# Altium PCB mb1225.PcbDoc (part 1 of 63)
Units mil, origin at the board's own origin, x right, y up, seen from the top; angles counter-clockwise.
Board outline 5000 x 3464.56 mil, 6 copper layers (TOP, L2_GND, L3_VCC, L4_SIG, L5_GND, BOTTOM), stack 62.2 mil thick; 452 components, 378 nets, 1968 pads, 949 vias.

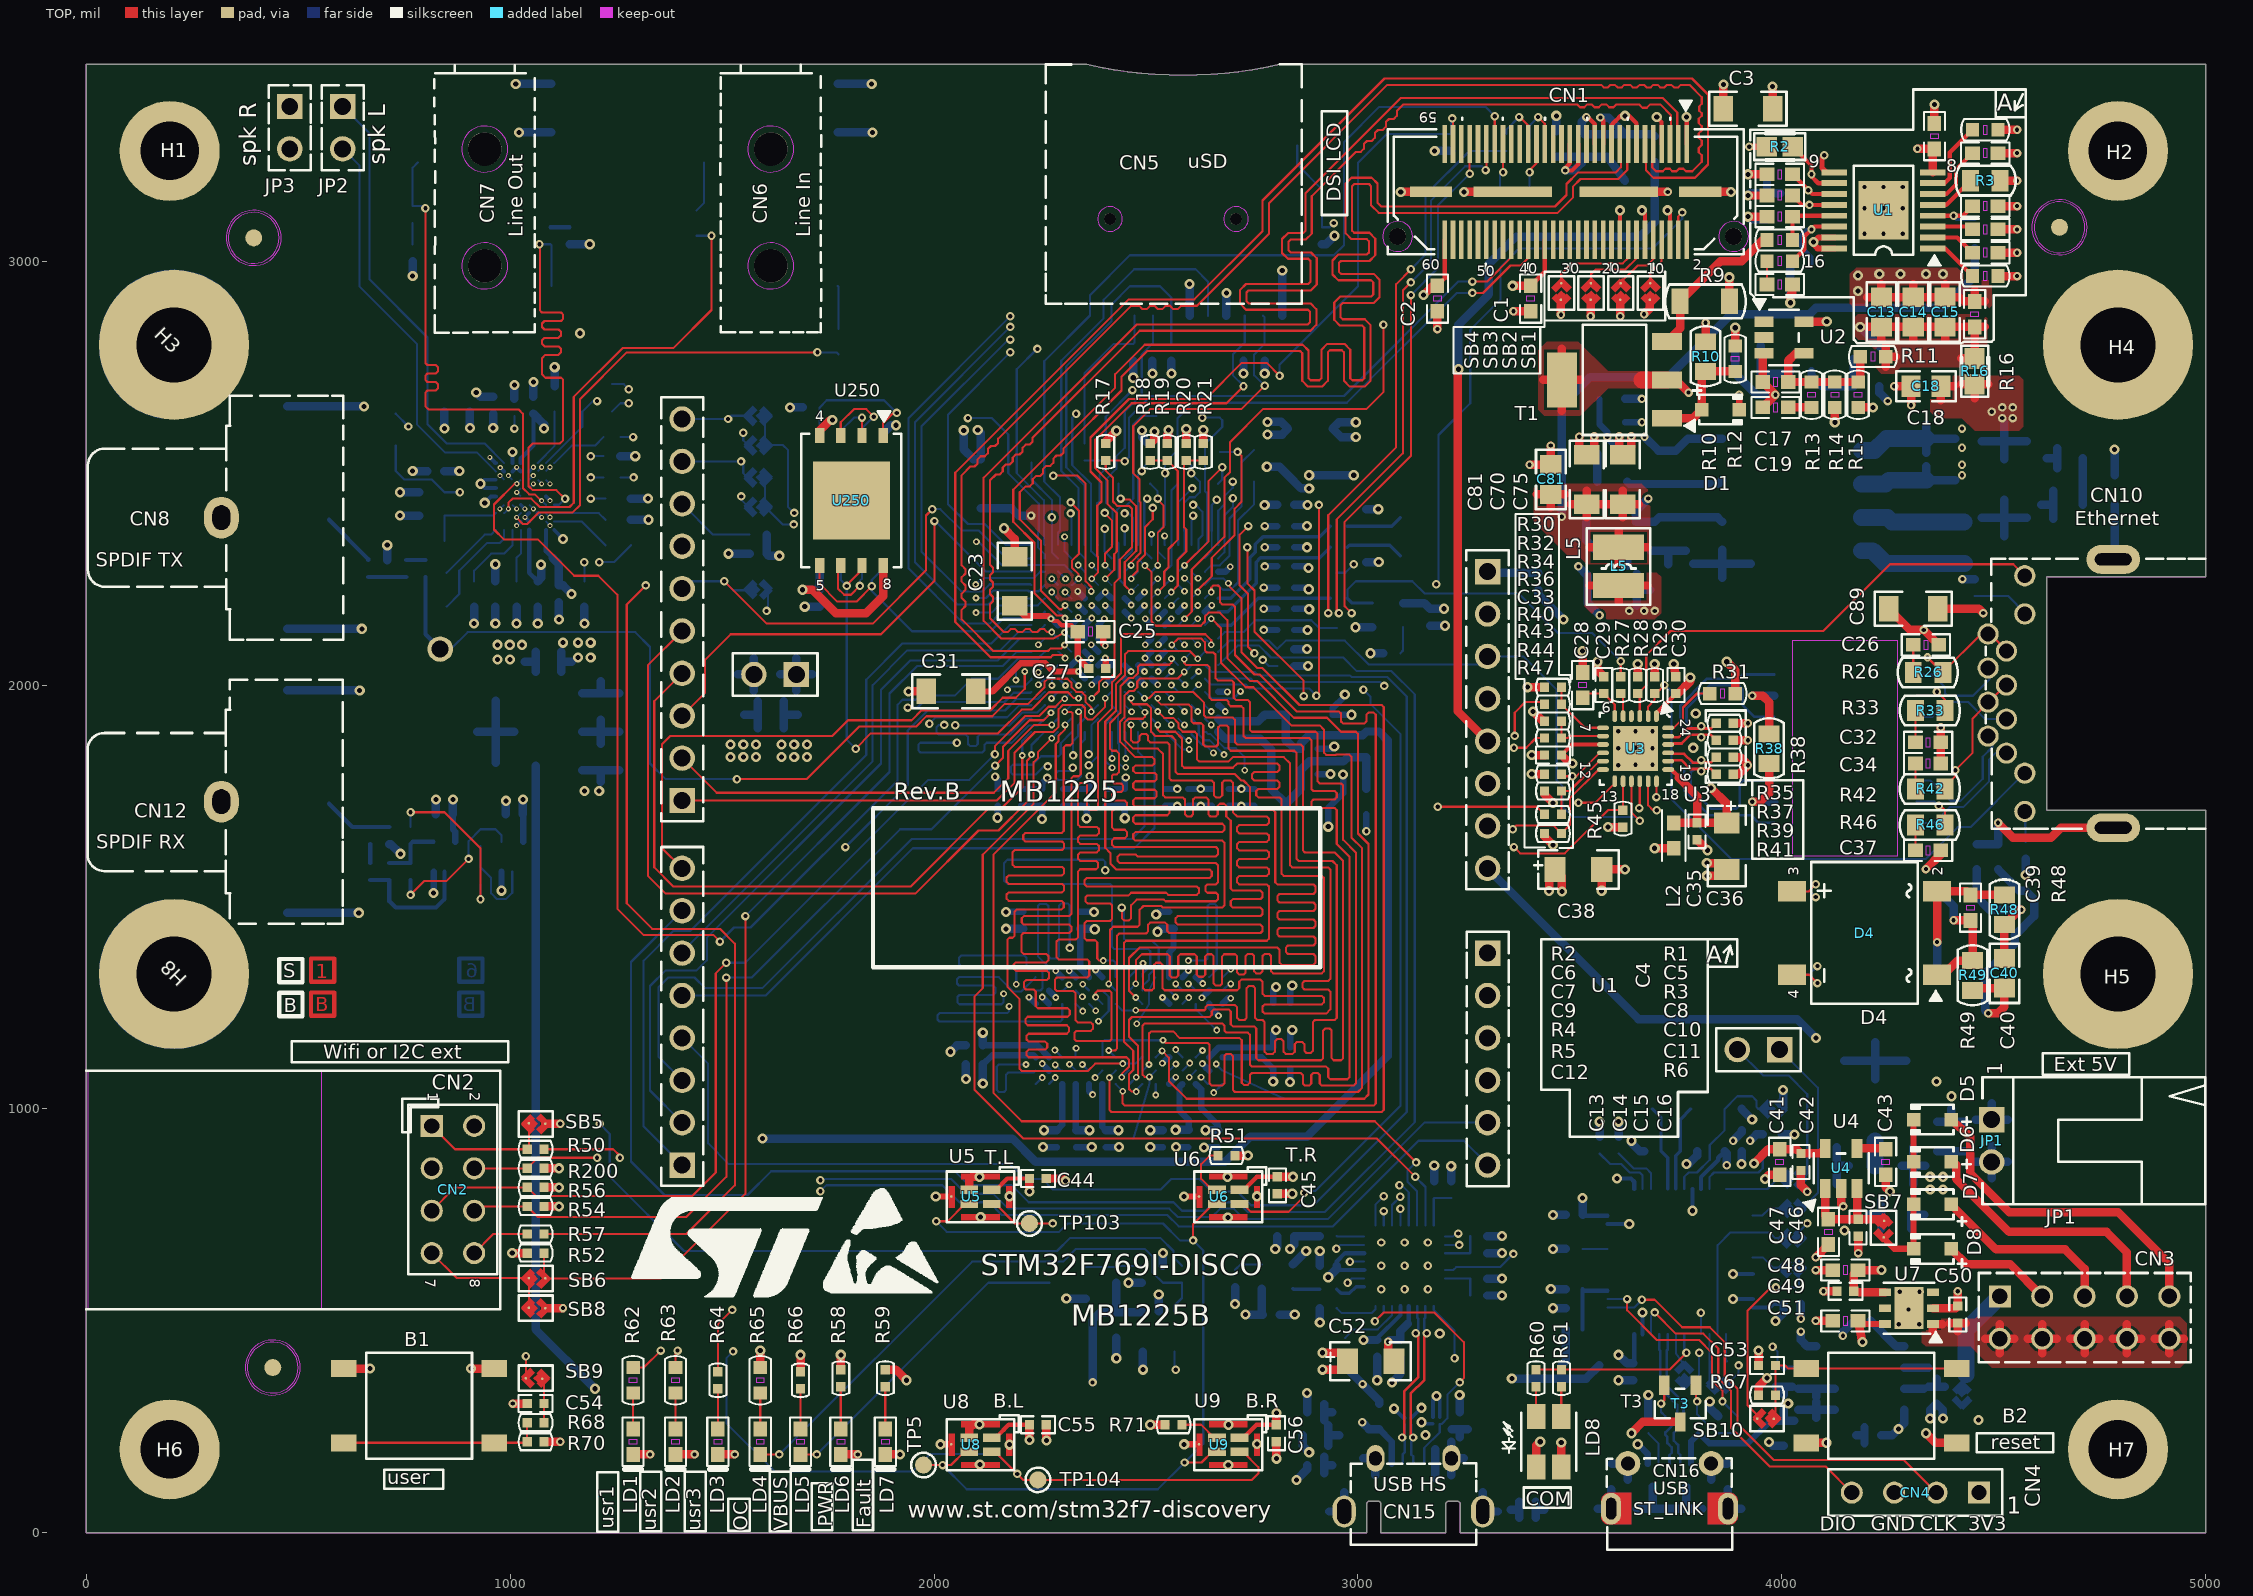
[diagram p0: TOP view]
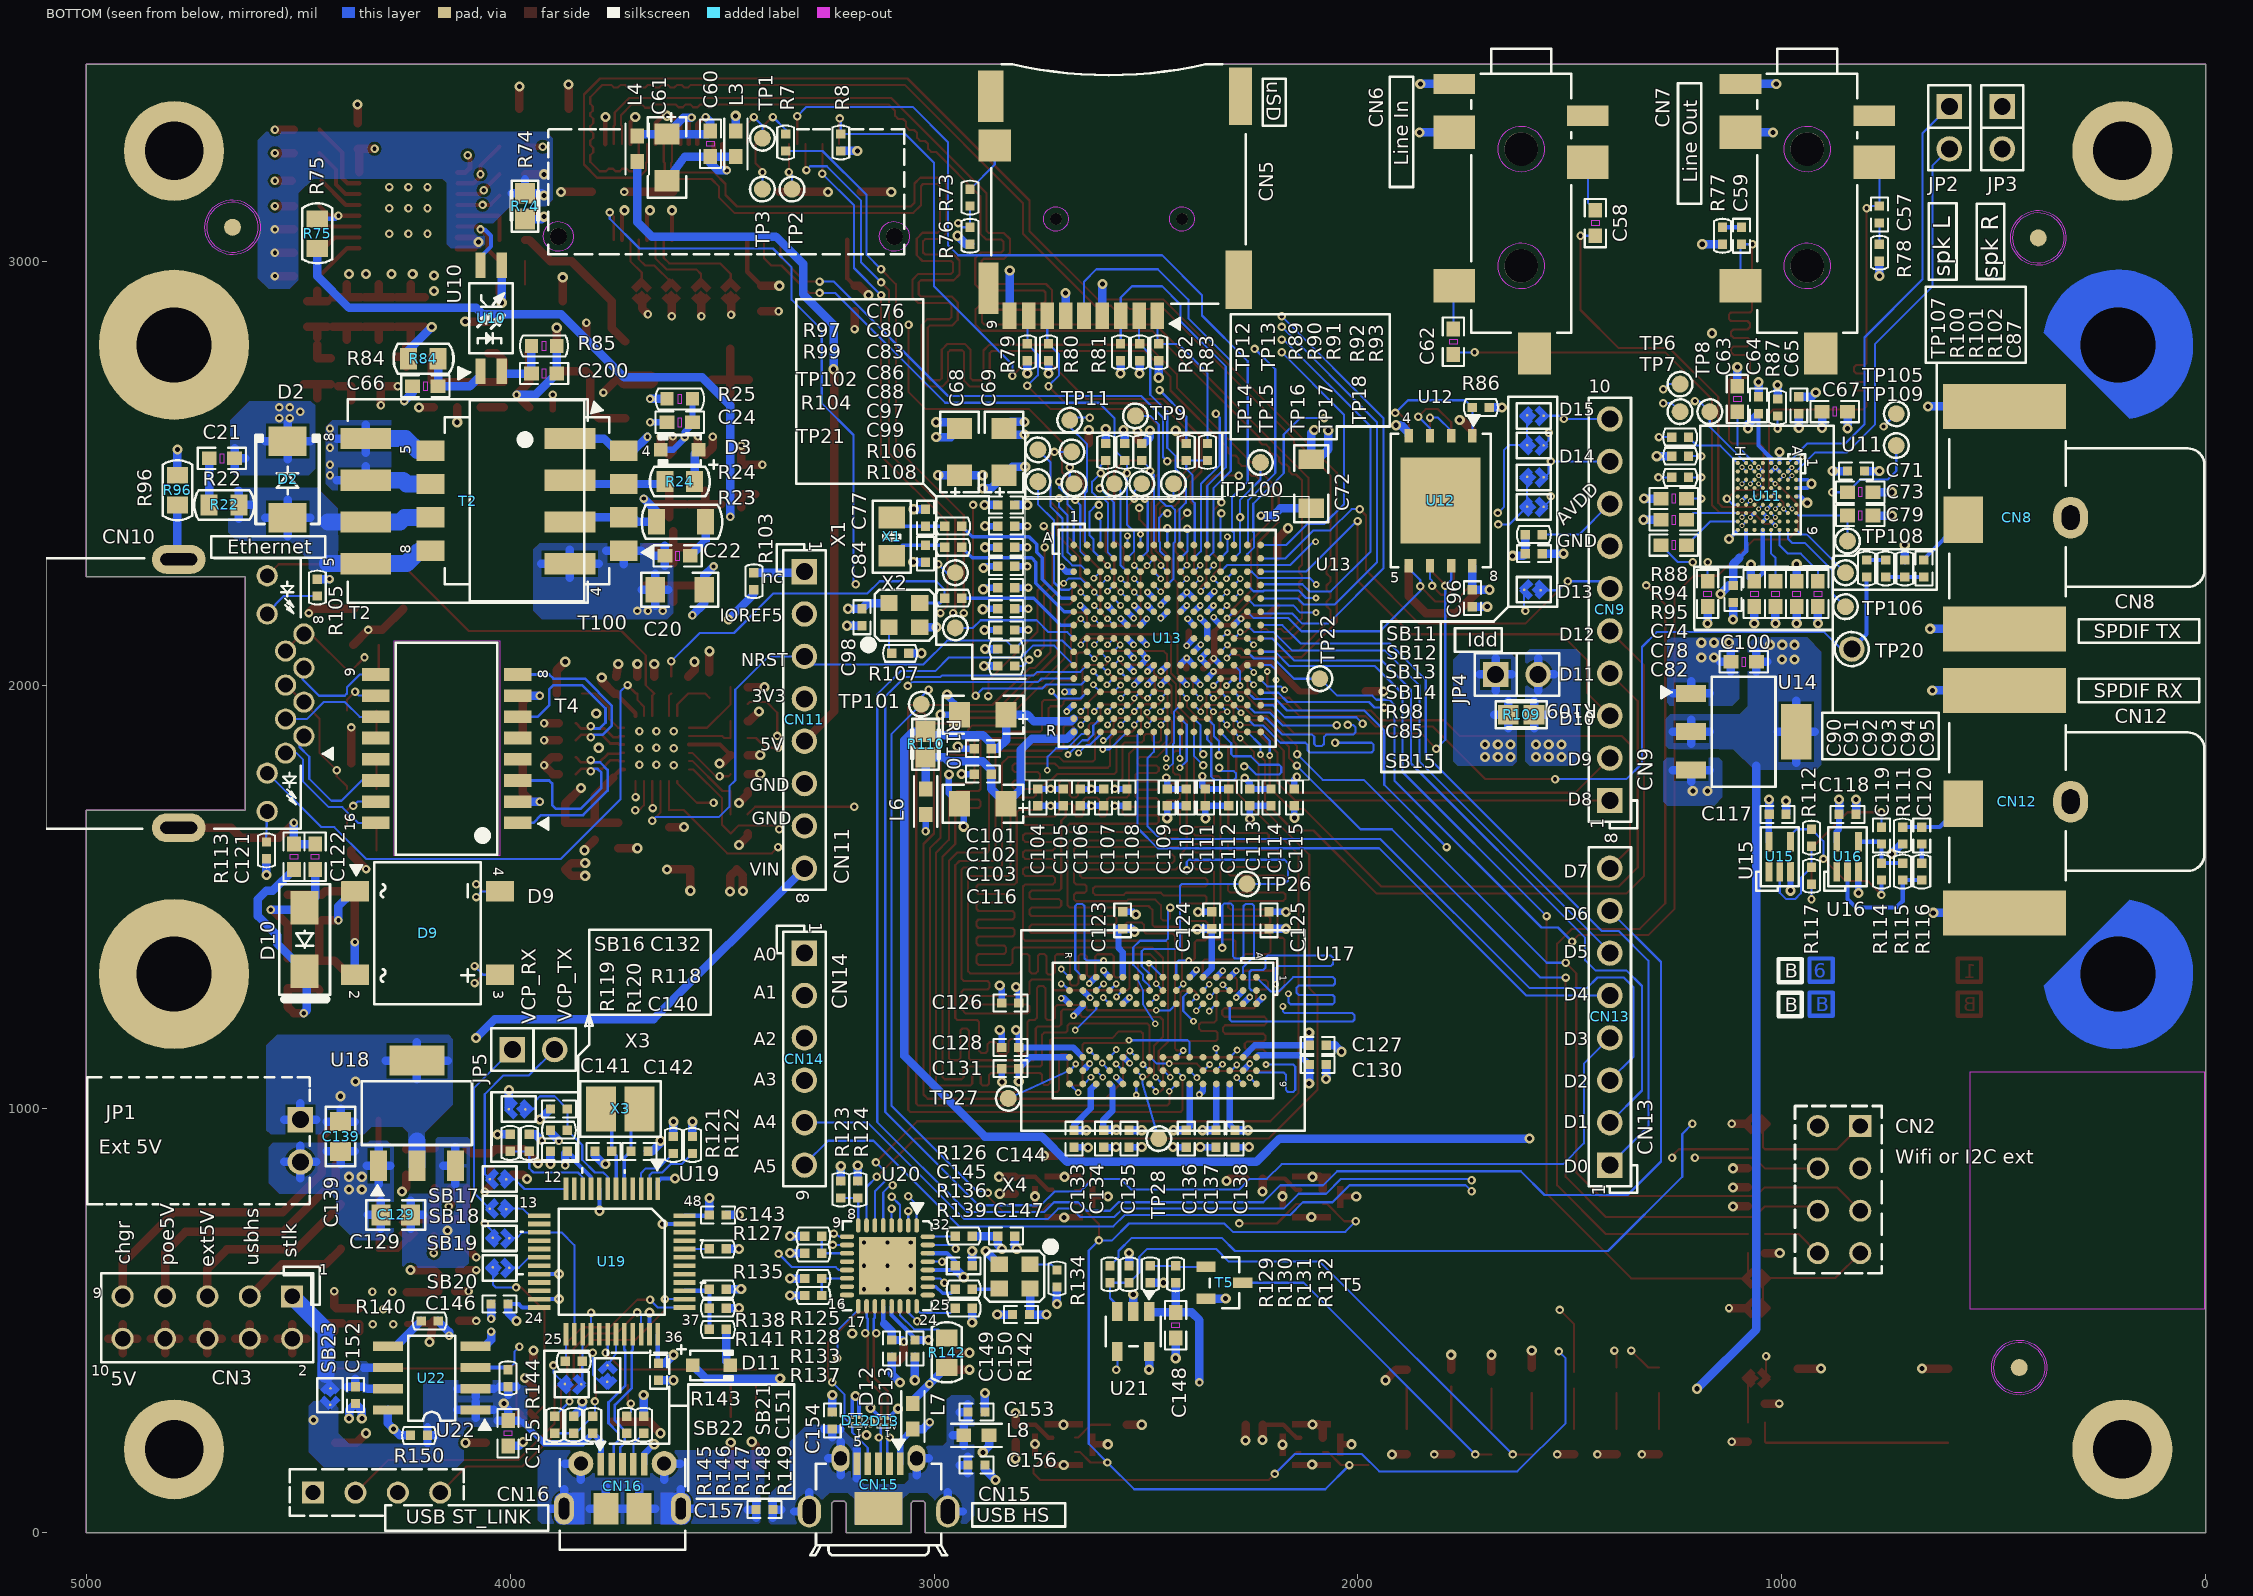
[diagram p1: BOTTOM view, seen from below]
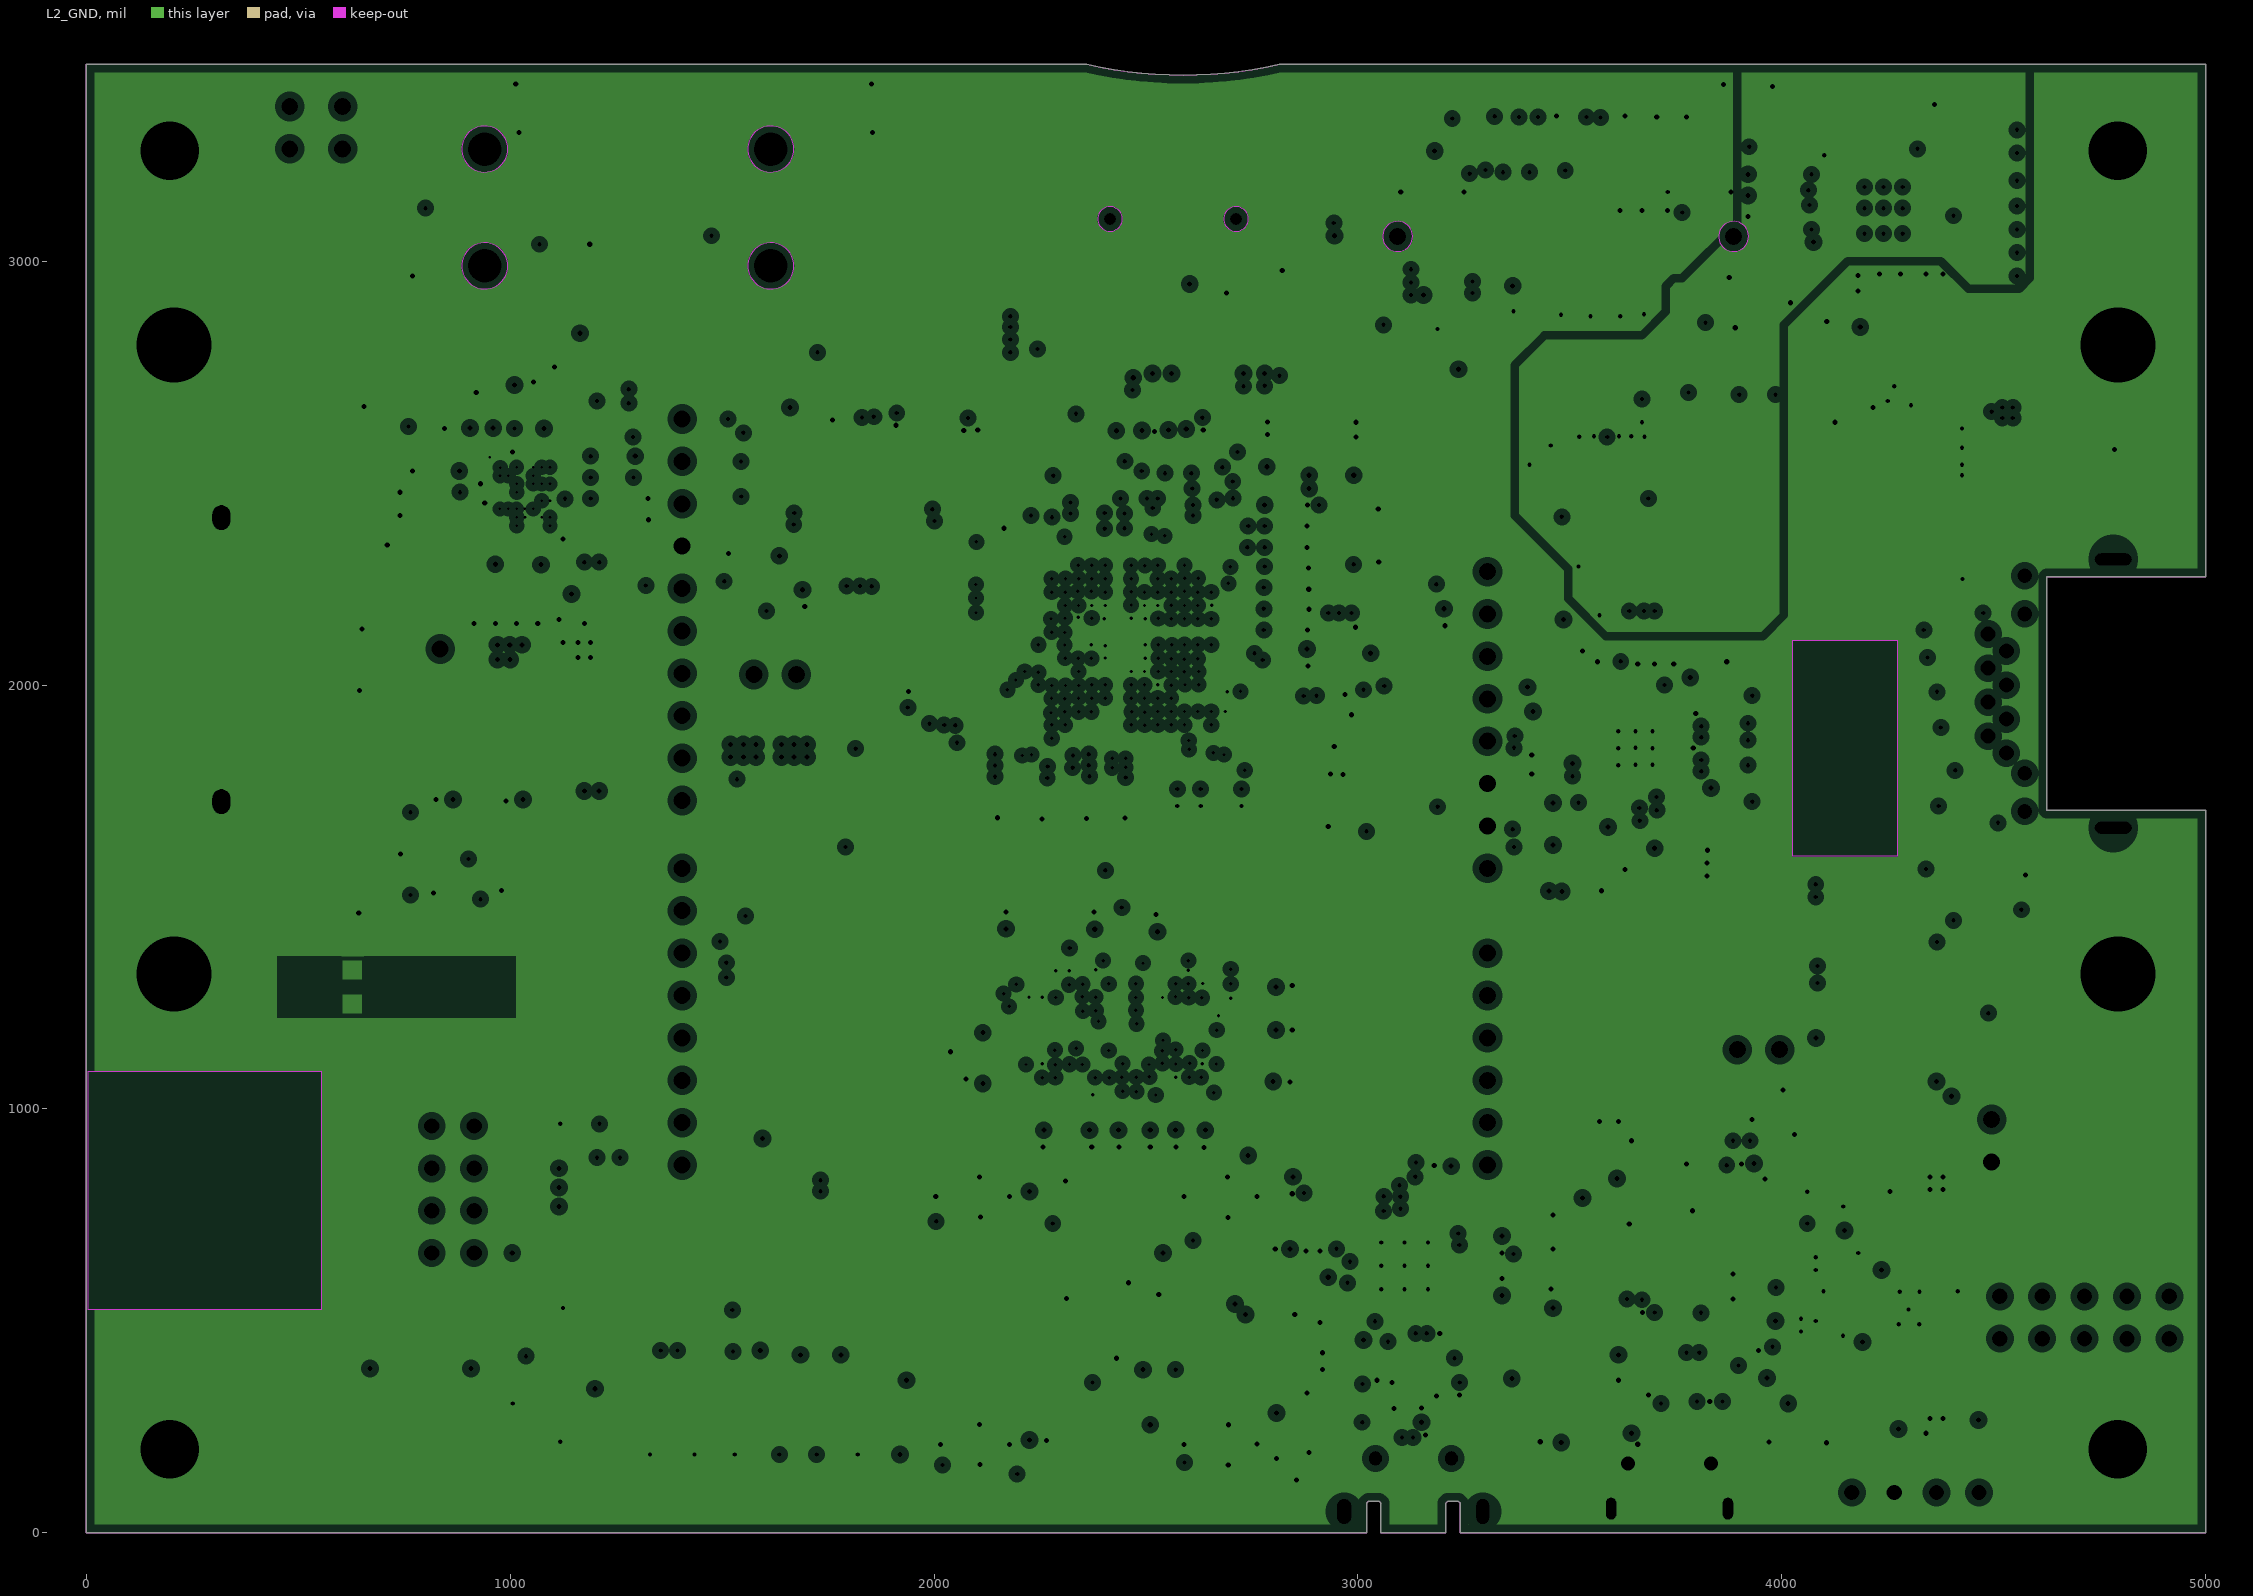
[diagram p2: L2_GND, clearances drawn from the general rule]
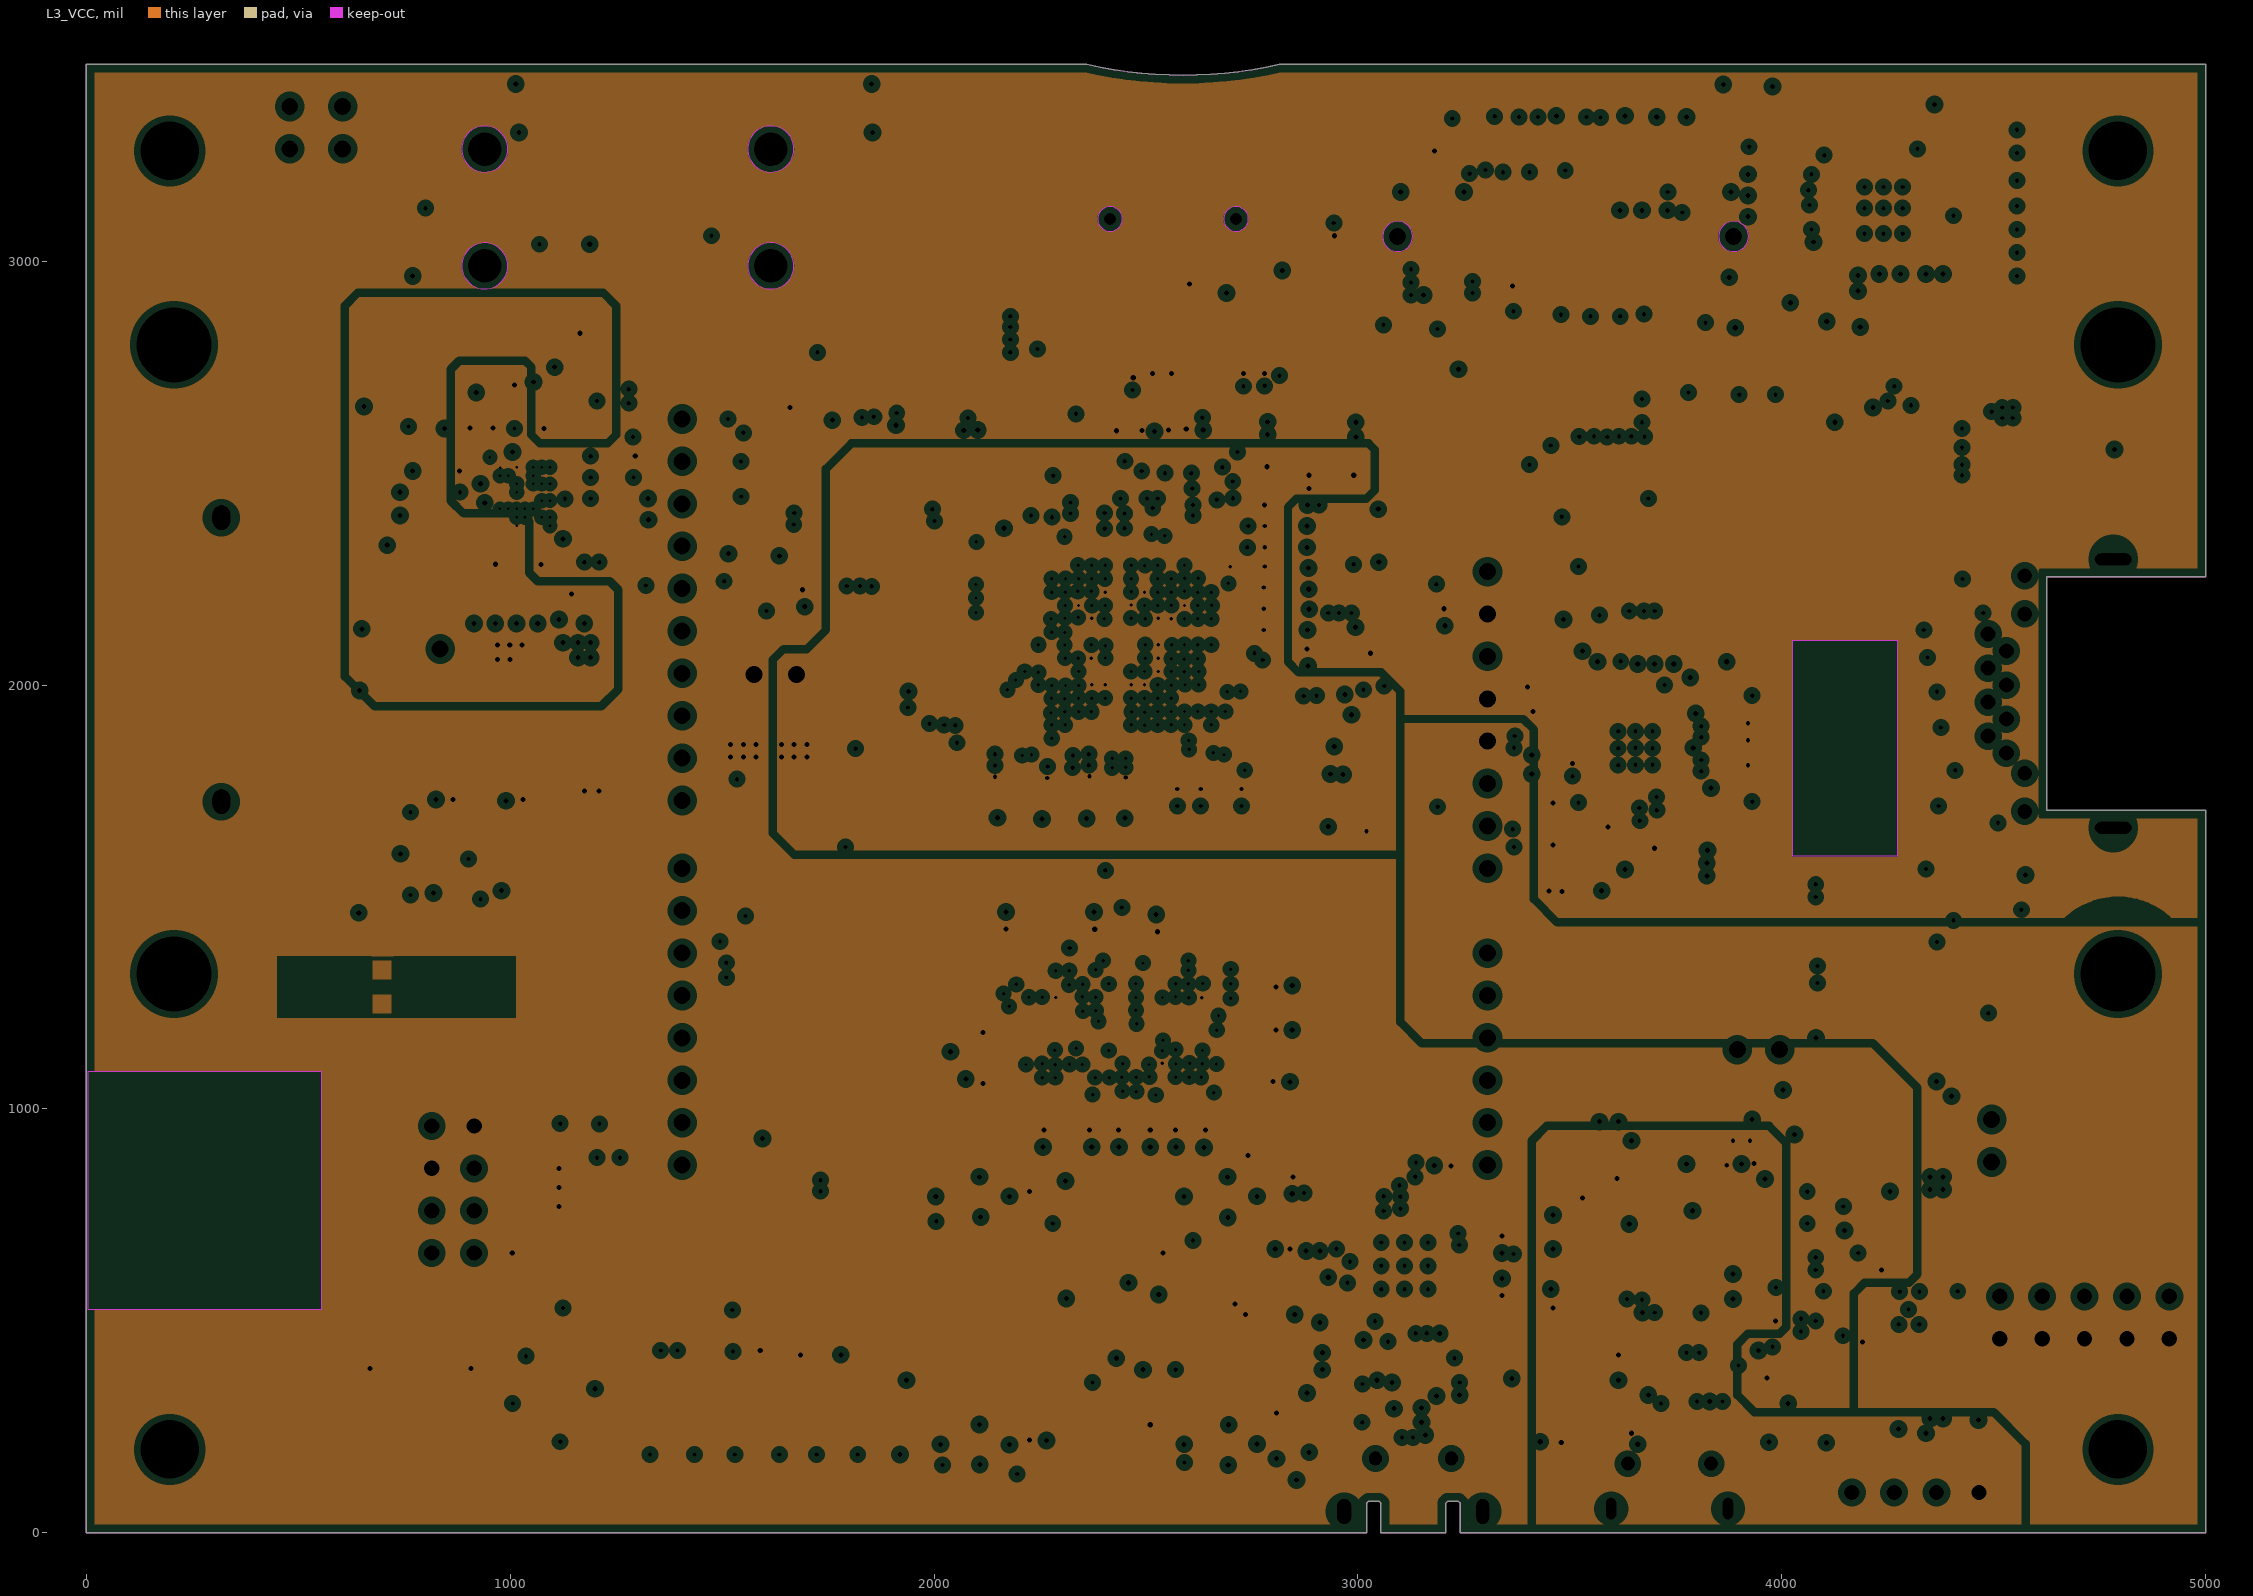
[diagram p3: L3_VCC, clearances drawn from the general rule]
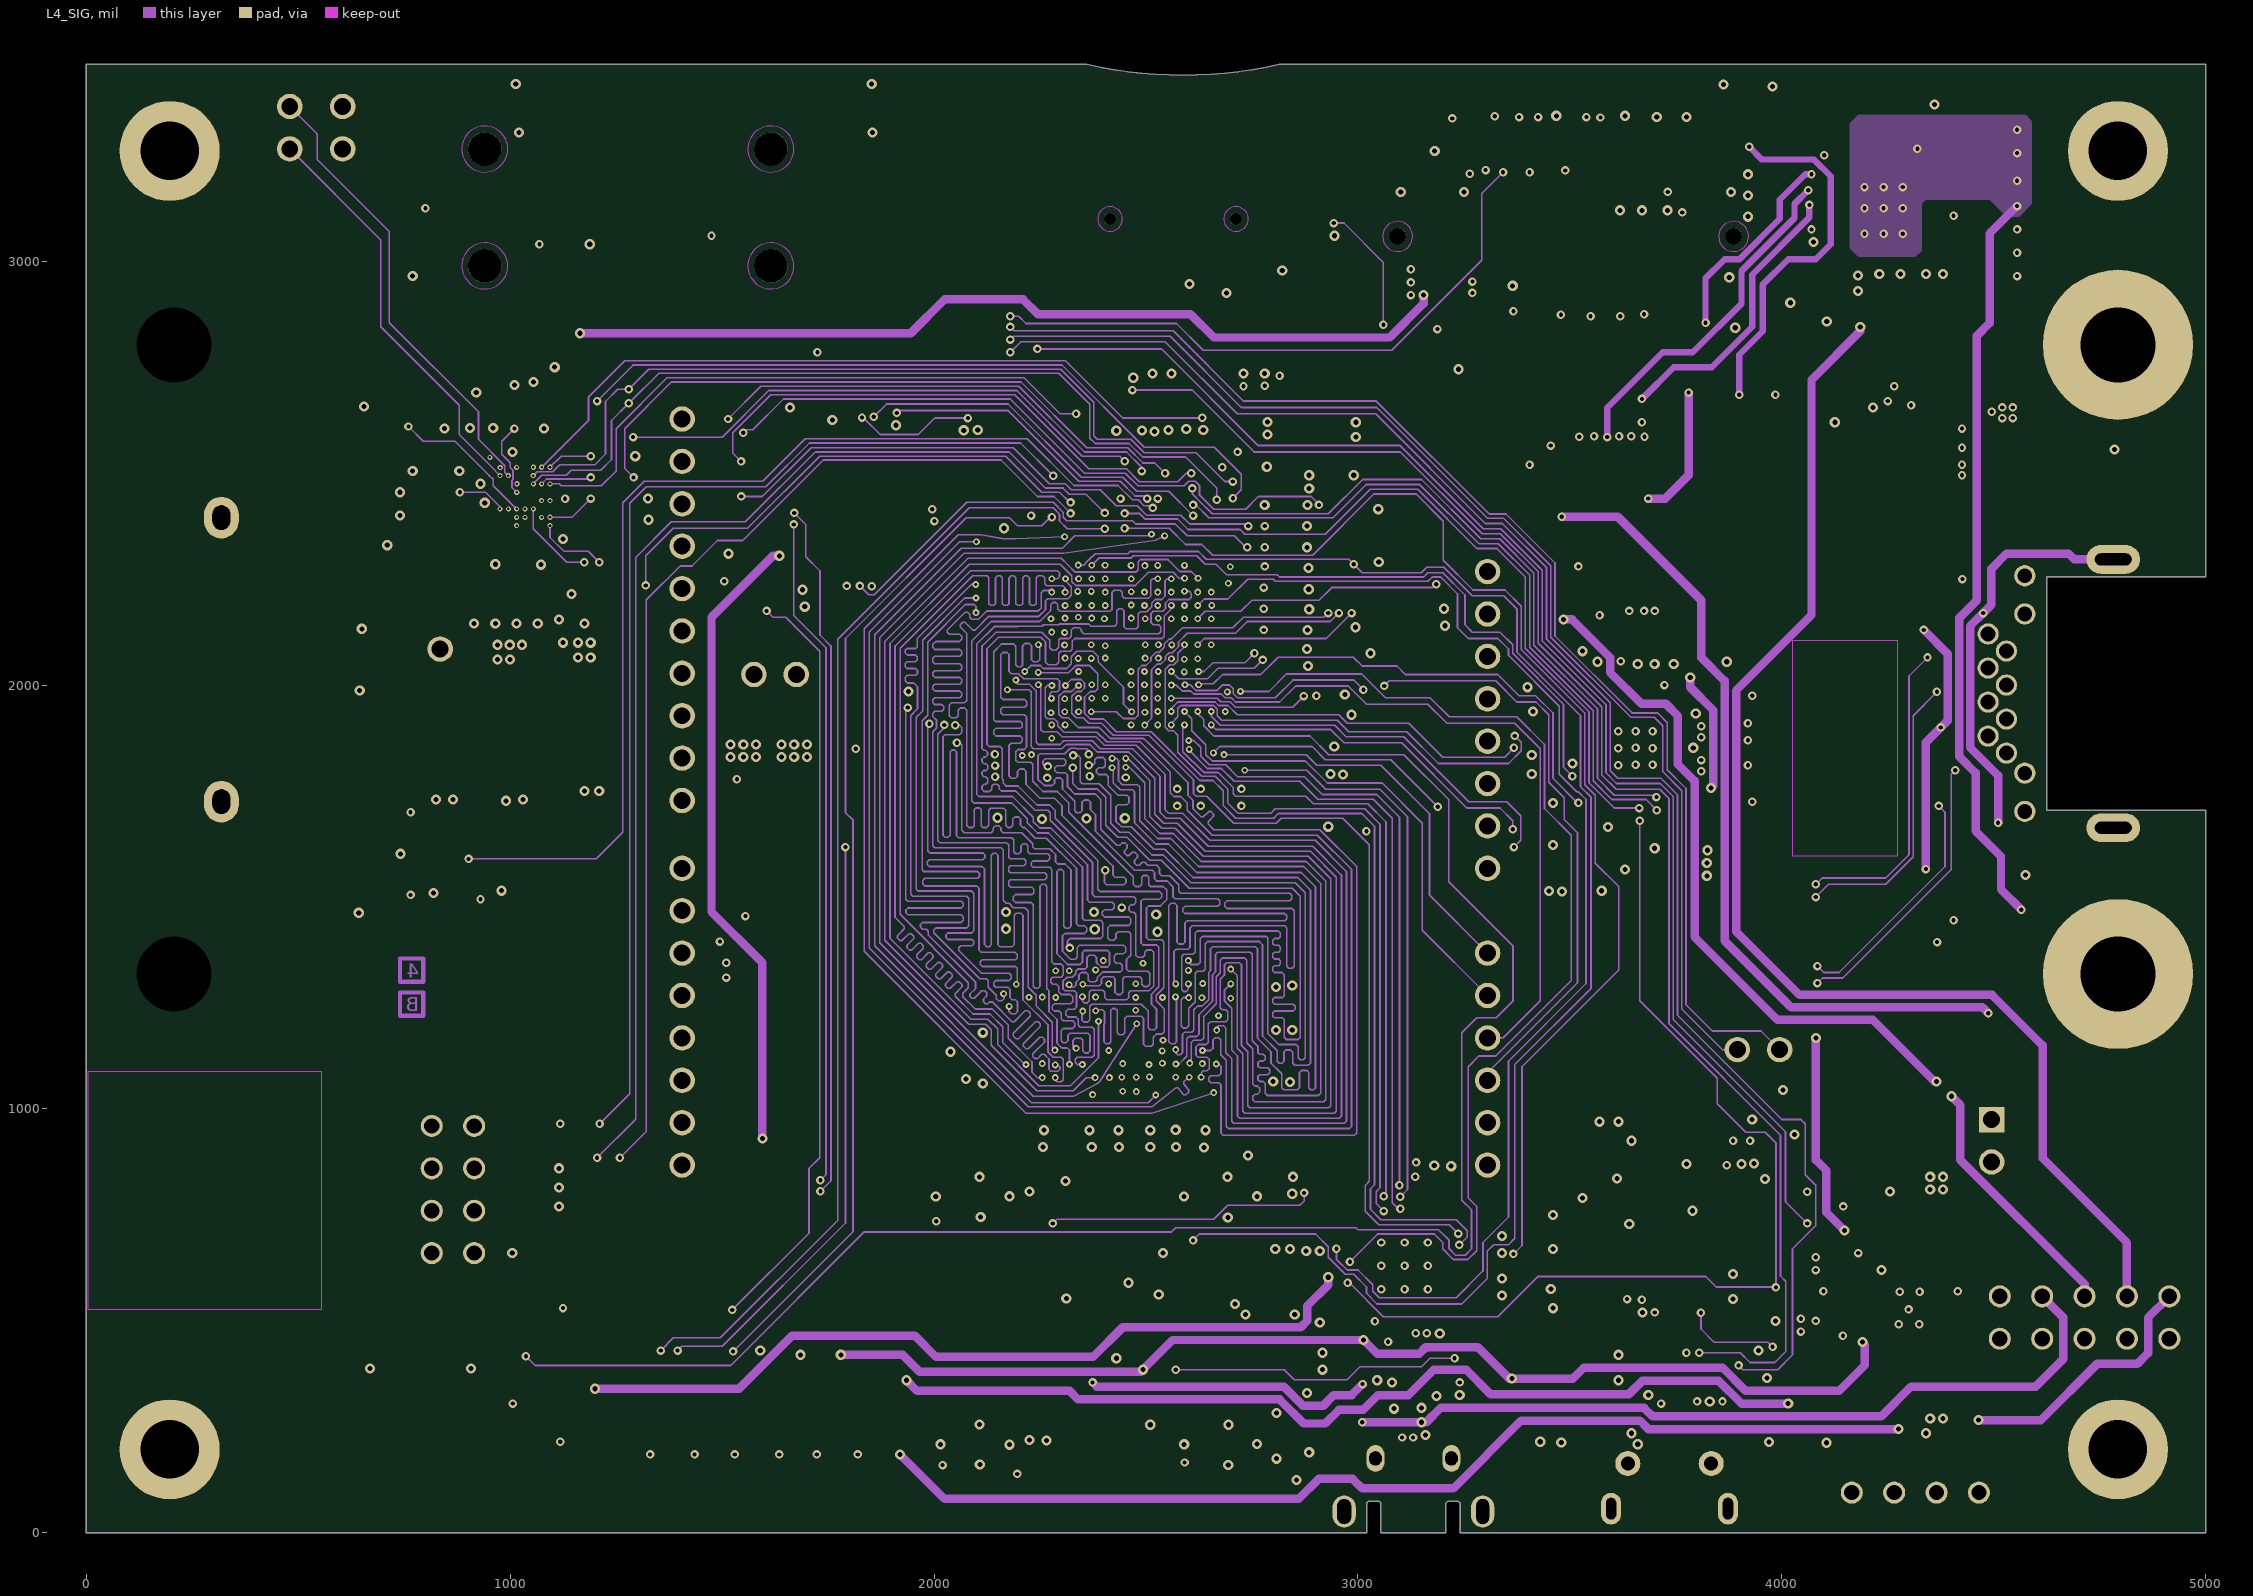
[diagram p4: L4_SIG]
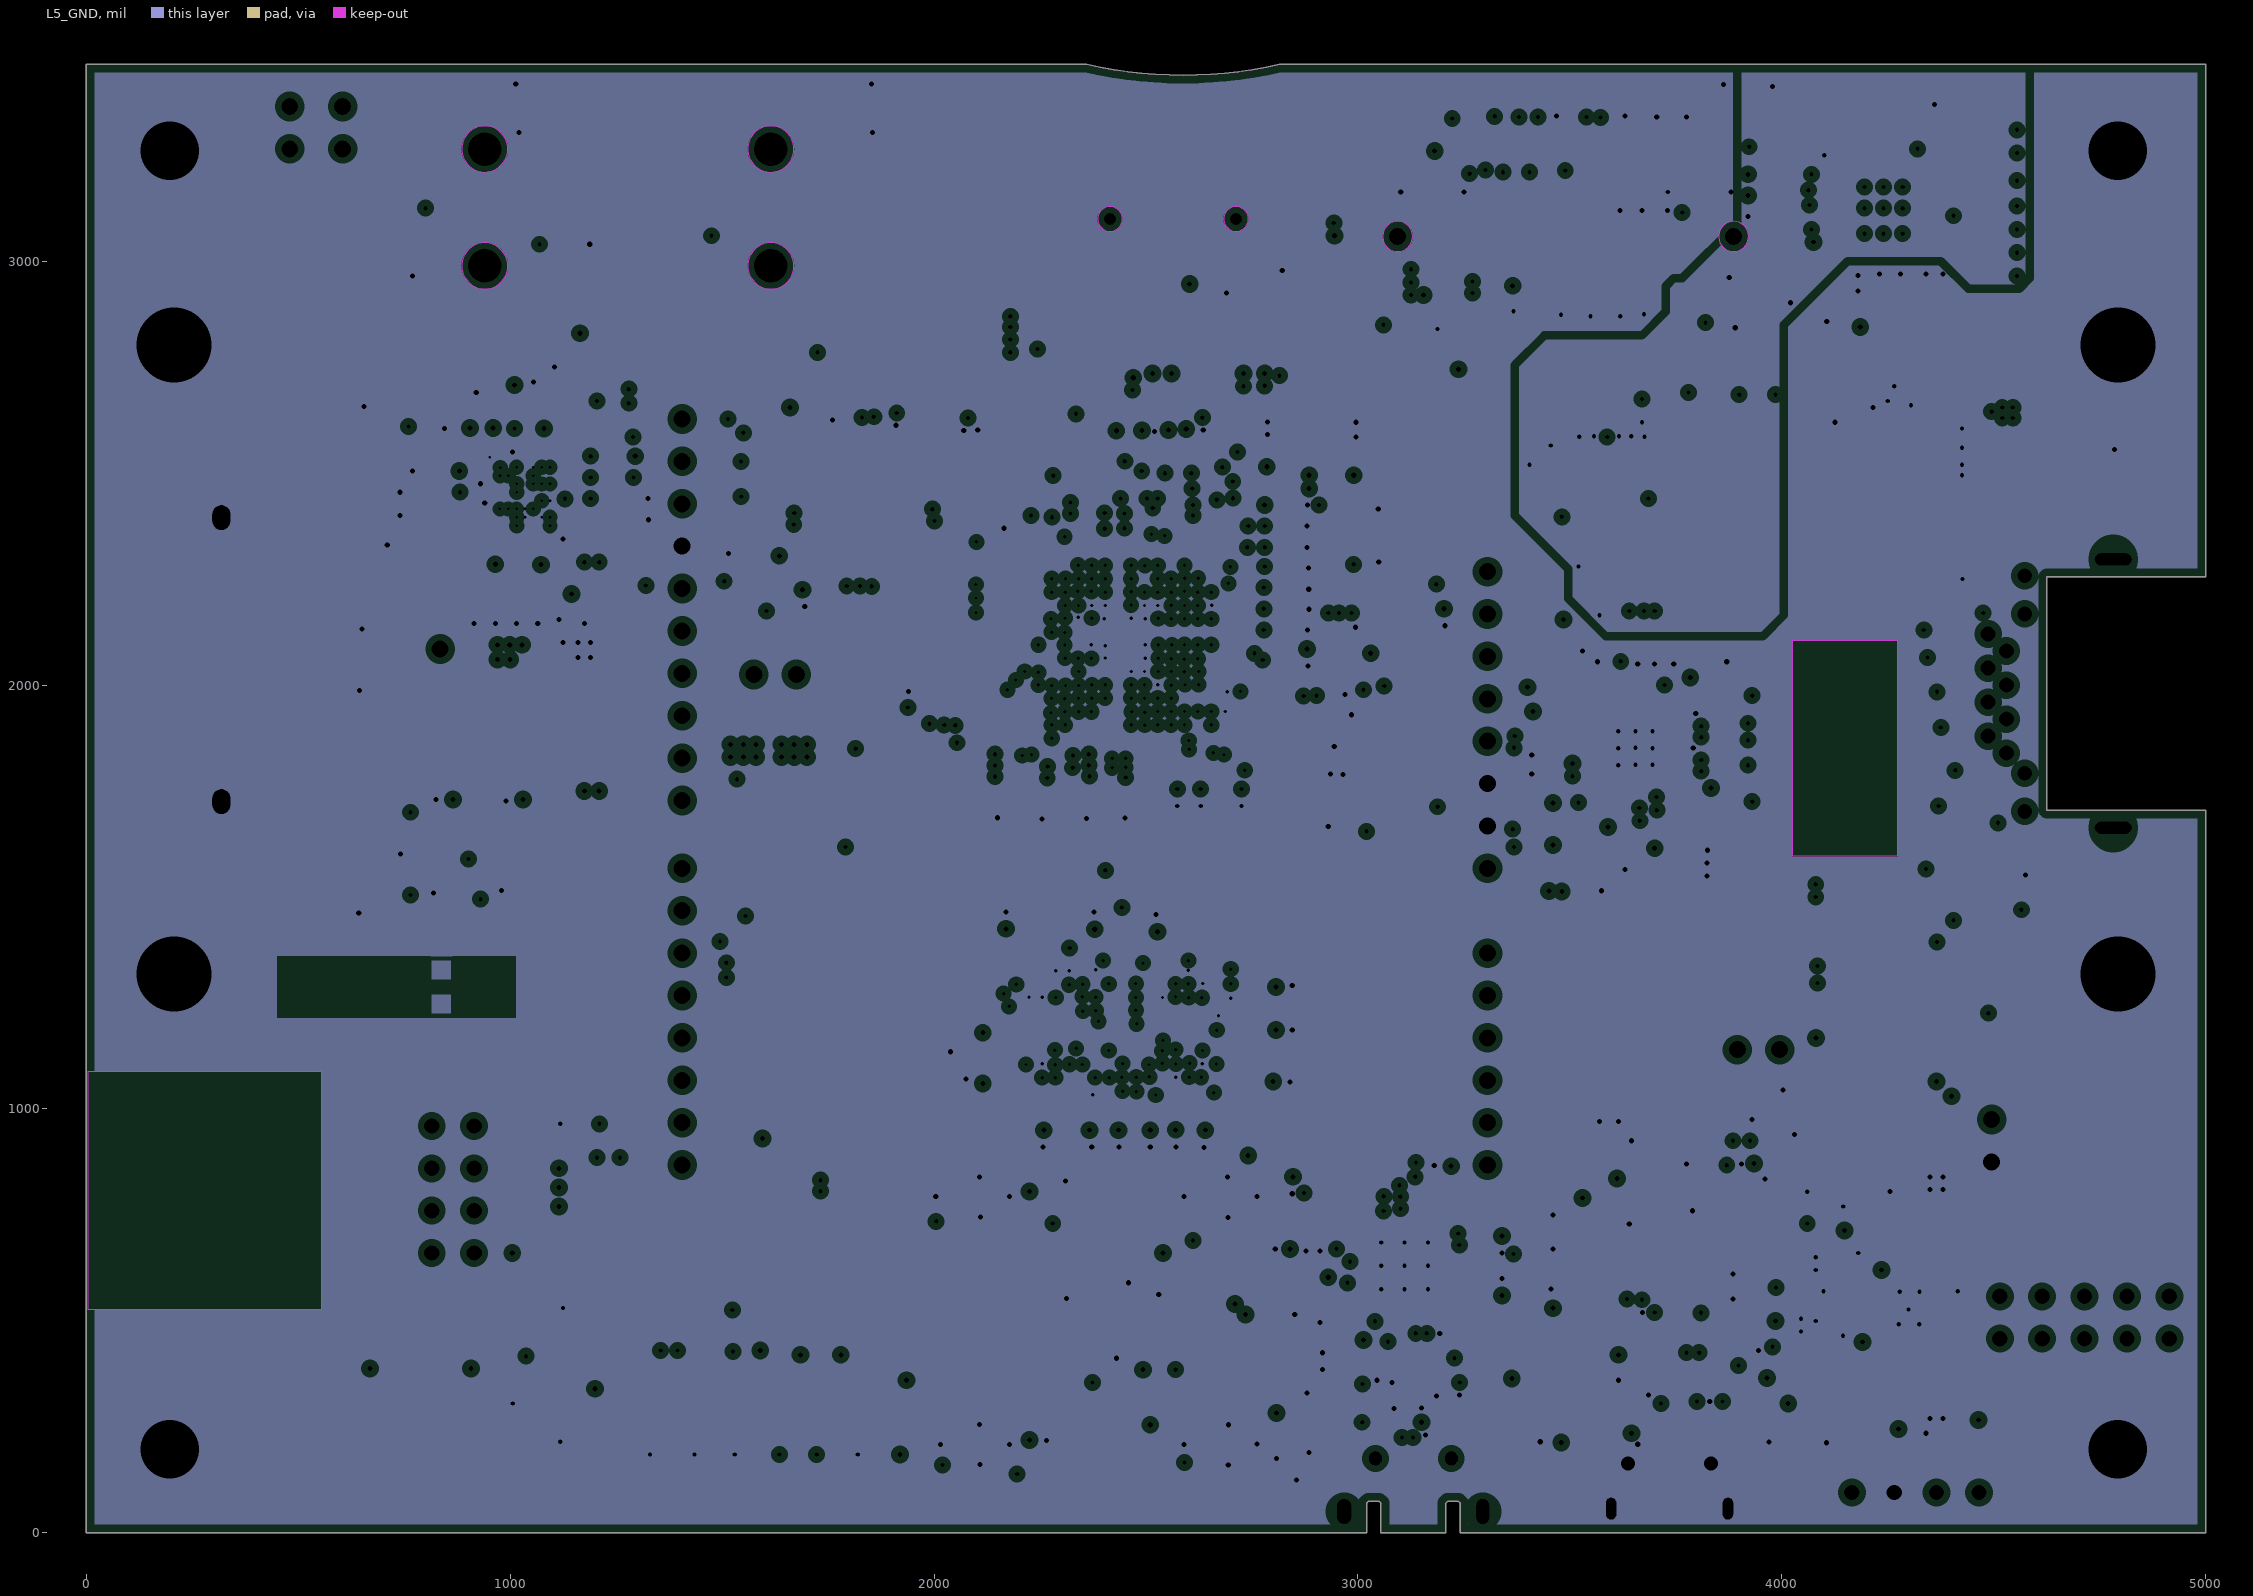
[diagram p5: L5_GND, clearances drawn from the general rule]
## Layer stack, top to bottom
Top Solder: solder mask 0.4, Solder Resist, Dk 3.5
TOP: signal copper 1.8
Dielectric 1: core 3.9, FR-4, Dk 4.3
L2_GND: plane copper 1.2, net POE7
Dielectric2: core 4, FR-4, Dk 4.3
L3_VCC: plane copper 1.2, net 3V3
Dielectric3: core 38, FR-4, Dk 4.3
L4_SIG: signal copper 1.2
Dielectric4: core 4, FR-4, Dk 4.3
L5_GND: plane copper 1.2, net POE7
Dielectric5: core 3.9, FR-4, Dk 4.3
BOTTOM: signal copper 1.8
Bottom Solder: solder mask 0.4, Solder Resist, Dk 3.5

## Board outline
0,0 3020.63,0 3020.63,70.28 3024.57,74.22 3050.16,74.22 3054.1,70.28 3054.1,0 3207.64,0 3207.64,70.28 3211.58,74.22 3237.17,74.22 3241.11,70.28 3241.11,0 5000,0 5000,1705 4625,1705 4625,2255 5000,2255 5000,3464.56 2815,3464.56 cw(c2587.5,4472.06) 2360,3464.56 0,3464.56

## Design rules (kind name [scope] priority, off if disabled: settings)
Clearance Clearance_Keepout [IsKeepOut] p1: gap=0.01 ignorepadtopadclearanceinfootprint=FALSE
Clearance Clearance_Board-cu [IsBoardOutline] p2: gap=5 ignorepadtopadclearanceinfootprint=FALSE except(6: Arc-Fill Arc-Poly Arc-Region Track-Fill Track-Poly Track-Region SMDPad-Fill SMDPad-Poly SMDPad-Region THPad-Fill THPad-Poly THPad-Region Via-Fill Via-Poly Via-Region Fill-Text Fill-Hole Poly-Text Poly-Hole Region-Text Region-Hole; 20: Fill-Fill Fill-Poly Fill-Region Poly-Poly Poly-Region Region-Region)
Clearance Clearance_Board-comp [IsBoardOutline vs IsComponent  and not InComponent('H3','H4','H5','H8','CN5','CN6','CN7','CN10','CN15','CN16')] p3: gap=5 ignorepadtopadclearanceinfootprint=FALSE except(6: Arc-Fill Arc-Poly Arc-Region Track-Fill Track-Poly Track-Region SMDPad-Fill SMDPad-Poly SMDPad-Region THPad-Fill THPad-Poly THPad-Region Via-Fill Via-Poly Via-Region Fill-Text Fill-Hole Poly-Text Poly-Hole Region-Text Region-Hole; 20: Fill-Fill Fill-Poly Fill-Region Poly-Poly Poly-Region Region-Region)
Clearance Clearance_JUMPER [HasFootprint('JP2_SMD') vs HasFootprint('jP2_SMD')] p4: gap=5 ignorepadtopadclearanceinfootprint=FALSE except(3: Fill-Fill Fill-Poly Fill-Region Poly-Poly Poly-Region Region-Region; 6: Arc-Fill Arc-Poly Arc-Region Track-Fill Track-Poly Track-Region SMDPad-Fill SMDPad-Poly SMDPad-Region THPad-Fill THPad-Poly THPad-Region Via-Fill Via-Poly Via-Region Fill-Text Fill-Hole Poly-Text Poly-Hole Region-Text Region-Hole)
Clearance Clearance_3MM [TouchesRoom('RoomDefinition_3MM')] p5: gap=5 ignorepadtopadclearanceinfootprint=FALSE except(3: Arc-Arc Arc-Track Arc-SMDPad Arc-THPad Arc-Via Track-Track Track-SMDPad Track-THPad Track-Via SMDPad-Via THPad-Via; 4: Arc-Hole Track-Hole Via-Hole; 6: Fill-Text Fill-Hole Poly-Text Poly-Hole Region-Text Region-Hole; 15: Fill-Fill Fill-Poly Fill-Region Poly-Poly Poly-Region Region-Region)
Clearance Clearance_BGA [TouchesRoom('RoomDefinition_BGA1') or TouchesRoom('RoomDefinition_BGA2') or TouchesRoom('RoomDefinition_BGA3')] p6: gap=4 ignorepadtopadclearanceinfootprint=FALSE except(5: Arc-Fill Arc-Poly Arc-Region Track-Fill Track-Poly Track-Region SMDPad-SMDPad SMDPad-THPad SMDPad-Fill SMDPad-Poly SMDPad-Region THPad-Fill THPad-Poly THPad-Region Via-Via Via-Fill Via-Poly Via-Region; 15: Fill-Fill Fill-Poly Fill-Region Poly-Poly Poly-Region Region-Region)
Clearance Clearance_2W_L4 [InNetClass('FMC_D[0..31]') or InNetClass('CRL') or InNetClass('FMC_A[0..12]')] p7: gap=5 ignorepadtopadclearanceinfootprint=FALSE except(6: SMDPad-Fill SMDPad-Poly SMDPad-Region THPad-Fill THPad-Poly THPad-Region Via-Fill Via-Poly Via-Region Fill-Text Fill-Hole Poly-Text Poly-Hole Region-Text Region-Hole; 8: Arc-Arc Arc-Track Track-Track; 10: Arc-Fill Arc-Poly Arc-Region Track-Fill Track-Poly Track-Region; 20: Fill-Fill Fill-Poly Fill-Region Poly-Poly Poly-Region Region-Region)
Clearance Clearance_2W [InNetClass('FMC_D[0..31]') or InNetClass('CRL') or InNetClass('FMC_A[0..12]')] p8: gap=5 ignorepadtopadclearanceinfootprint=FALSE except(6: SMDPad-Fill SMDPad-Poly SMDPad-Region THPad-Fill THPad-Poly THPad-Region Via-Fill Via-Poly Via-Region Fill-Text Fill-Hole Poly-Text Poly-Hole Region-Text Region-Hole; 10: Arc-Arc Arc-Track Arc-Fill Arc-Poly Arc-Region Track-Track Track-Fill Track-Poly Track-Region; 20: Fill-Fill Fill-Poly Fill-Region Poly-Poly Poly-Region Region-Region)
Clearance Clearance_3W [InNet('PG8')] p9: gap=5 ignorepadtopadclearanceinfootprint=FALSE except(6: SMDPad-Fill SMDPad-Poly SMDPad-Region THPad-Fill THPad-Poly THPad-Region Via-Fill Via-Poly Via-Region Fill-Text Fill-Hole Poly-Text Poly-Hole Region-Text Region-Hole; 15: Arc-Arc Arc-Track Arc-Fill Arc-Poly Arc-Region Track-Track Track-Fill Track-Poly Track-Region; 20: Fill-Fill Fill-Poly Fill-Region Poly-Poly Poly-Region Region-Region)
Clearance [All] p10: gap=5 ignorepadtopadclearanceinfootprint=FALSE except(6: Arc-Fill Arc-Poly Arc-Region Track-Fill Track-Poly Track-Region SMDPad-Fill SMDPad-Poly SMDPad-Region THPad-Fill THPad-Poly THPad-Region Via-Fill Via-Poly Via-Region Fill-Text Fill-Hole Poly-Text Poly-Hole Region-Text Region-Hole; 20: Fill-Fill Fill-Poly Fill-Region Poly-Poly Poly-Region Region-Region)
ComponentClearance [All] p1: gap=1 collisioncheckmode=3 verticalgap=1 showdistances=FALSE
DiffPairsRouting DiffPairsRouting_100OHM [InDifferentialPairClass('100OHM')] p1: maxlimit=10.9 minlimit=9.9 mostfreqgap=10.9 toplayer_maxgap=9.9 toplayer_prefgap=9.9 toplayer_minwidth=5.1 toplayer_maxwidth=5.1 toplayer_prefwidth=5.1 midlayer1_mingap=10.9 midlayer1_minwidth=4.1 midlayer1_maxwidth=4.1 midlayer1_prefwidth=4.1 bottomlayer_maxgap=9.9 bottomlayer_prefgap=9.9 bottomlayer_minwidth=5.1 bottomlayer_maxwidth=5.1 bottomlayer_prefwidth=5.1 maxuncoupledlength=500
DiffPairsRouting DiffPairsRouting_90OHM [InDifferentialPairClass('90OHM')] p2: maxlimit=9.9 minlimit=8.9 mostfreqgap=9.9 toplayer_maxgap=8.9 toplayer_prefgap=8.9 toplayer_minwidth=6.1 toplayer_maxwidth=6.1 toplayer_prefwidth=6.1 midlayer1_mingap=9.9 midlayer1_minwidth=5.1 midlayer1_maxwidth=5.1 midlayer1_prefwidth=5.1 bottomlayer_maxgap=8.9 bottomlayer_prefgap=8.9 bottomlayer_minwidth=6.1 bottomlayer_maxwidth=6.1 bottomlayer_prefwidth=6.1 maxuncoupledlength=500
HoleSize [All] p1: absolutevalues=TRUE maxlimit=300 minlimit=1 maxpercent=80.000 minpercent=20.000
MatchedLengths MatchedLengths_DSI_DSI_CLK_N [InDifferentialPair('DSI.DSI_D0') or InDifferentialPair('DSI.DSI_D1') or InDifferentialPair('DSI.DSI_CK') or InDifferentialPair('RD') or InDifferentialPair('TD') or InDifferentialPair('USB_HS')] p1: tolerance=5 checknetsindiffpair=TRUE checkdiffpairvsdiffpair=FALSE checkxsignals=FALSE checkothers=FALSE
MatchedLengths "Schematic Matched Net Lengths_11" [InNetClass('ULPI_D[0..7]')] p2 off: tolerance=100 checknetsindiffpair=FALSE checkdiffpairvsdiffpair=TRUE checkxsignals=TRUE checkothers=TRUE
MatchedLengths "Schematic Matched Net Lengths_8" [InNetClass('FMC_A[0..12]')] p3 off: tolerance=100 checknetsindiffpair=FALSE checkdiffpairvsdiffpair=TRUE checkxsignals=TRUE checkothers=TRUE
MatchedLengths "Schematic Matched Net Lengths_7" [InNetClass('FMC_D[0..31]')] p4 off: tolerance=100 checknetsindiffpair=FALSE checkdiffpairvsdiffpair=TRUE checkxsignals=TRUE checkothers=TRUE
MatchedLengths "Schematic Matched Net Lengths_6" [InNetClass('PF[0..15]')] p5 off: tolerance=100 checknetsindiffpair=FALSE checkdiffpairvsdiffpair=TRUE checkxsignals=TRUE checkothers=TRUE
PlaneClearance PlaneClearance_Fix-138 [InComponent('H1','H2','H6','H7')] p1: clearance=9
PlaneClearance PlaneClearance_Fix-177 [InComponent('H3','H4','H5','H8')] p2: clearance=17.5
PlaneClearance PlaneClearance_18mil [IsVia And (PadViaLibraryTemplate = 'via12d6a18')] p3: clearance=6
PlaneClearance PlaneClearance_26mil [IsVia And (PadViaLibraryTemplate = 'via16d8a26')] p4: clearance=9
PlaneClearance PlaneClearance_30mil [IsVia And (PadViaLibraryTemplate = 'via20d10a30')] p5: clearance=10
PlaneClearance PlaneClearance_32mil [IsVia And (PadViaLibraryTemplate = 'via24d12a32')] p6: clearance=10
PlaneClearance [All] p7: clearance=15
PlaneConnect PlaneConnect_CN8-12 [InComponent('CN8','CN12')] p1: planeconnectstyle=Relief reliefexpansion=8 reliefentries=4 reliefconductorwidth=15 reliefairgap=7
PlaneConnect PlaneConnect_Fix-138 [InComponent('H1','H2','H6','H7')] p2: planeconnectstyle=Relief reliefexpansion=2 reliefentries=4 reliefconductorwidth=30 reliefairgap=7
PlaneConnect PlaneConnect_Fix-177 [InComponent('H3','H4','H5','H8')] p3: planeconnectstyle=Relief reliefexpansion=8 reliefentries=4 reliefconductorwidth=40 reliefairgap=7
PlaneConnect [All] p4: pad.planeconnectstyle=Relief pad.reliefexpansion=8 pad.reliefentries=4 pad.reliefconductorwidth=15 pad.reliefairgap=7 via.planeconnectstyle=Direct via.reliefexpansion=20 via.reliefentries=4 via.reliefconductorwidth=10 via.reliefairgap=10
PolygonConnect PolygonConnect_CN15 [IsPad And (Name = 'CN15-10')] p1: connectstyle=Direct reliefconductorwidth=10 reliefentries=4 polygonreliefangle="90 Angle" airgapwidth=10
PolygonConnect [All] p2: thpad.connectstyle=Relief thpad.reliefconductorwidth=10 thpad.reliefentries=4 thpad.polygonreliefangle="90 Angle" thpad.airgapwidth=6 smdpad.connectstyle=Relief smdpad.reliefconductorwidth=10 smdpad.reliefentries=4 smdpad.polygonreliefangle="90 Angle" smdpad.airgapwidth=6 via.connectstyle=Direct via.reliefconductorwidth=10 via.reliefentries=4 via.polygonreliefangle="90 Angle" via.airgapwidth=10
RoomDefinition RoomDefinition_TitleBlock [All] p1: confinementstyle=ConfineOut formatcopy=TRUE lockcomponents=FALSE outline 480,-1550 5370,-1550 5370,-2590 480,-2590
RoomDefinition RoomDefinition_BGA3 [False] p2: confinementstyle=ConfineIn formatcopy=TRUE lockcomponents=FALSE outline 4396.96,374.85 4452.82,374.85 4452.82,285.28 4396.96,285.28
RoomDefinition RoomDefinition_BGA2 [False] p3: confinementstyle=ConfineIn formatcopy=TRUE lockcomponents=FALSE outline 2189,1362 2735,1362 2735,1000 2189,1000
RoomDefinition RoomDefinition_BGA1 [False] p4: confinementstyle=ConfineIn formatcopy=TRUE lockcomponents=FALSE outline 2191,2364 2709,2364 2709,1846 2191,1846
RoomDefinition RoomDefinition_3MM [False] p5: confinementstyle=ConfineIn formatcopy=TRUE lockcomponents=FALSE outline 950,2350 1120,2350 1120,2540 950,2540
RoutingVias RoutingVias_20mil [InNetClass('20mil')] p1: holewidth=28 width=50 viastyle="Through Hole" minholewidth=28 minwidth=50 maxholewidth=28 maxwidth=50 useviatemplates=TRUE viatemplateguid#1={5D3415D3-4873-433A-BEBD-9F6A98E01CBE} viatemplateguid#2={FEA33B1B-546A-4E39-85DE-AC0C76FFA526} viatemplateguid#3={E0448361-9551-48C3-8589-11349CFAC803} viatemplateguid#4={8D40BD13-7136-426A-BA26-E05C9D5C1322} viatemplatename#1=via12d6a18 viatemplatename#2=via16d8a26 viatemplatename#3=via20d10a30 viatemplatename#4=via24d12a32
RoutingVias [All] p2: holewidth=28 width=50 viastyle="Through Hole" minholewidth=28 minwidth=50 maxholewidth=28 maxwidth=50 useviatemplates=TRUE viatemplateguid#1={5D3415D3-4873-433A-BEBD-9F6A98E01CBE} viatemplateguid#2={FEA33B1B-546A-4E39-85DE-AC0C76FFA526} viatemplateguid#3={E0448361-9551-48C3-8589-11349CFAC803} viatemplateguid#4={8D40BD13-7136-426A-BA26-E05C9D5C1322} viatemplatename#1=via12d6a18 viatemplatename#2=via16d8a26 viatemplatename#3=via20d10a30 viatemplatename#4=via24d12a32
SolderMaskExpansion [All] p1: expansion=3
Width Width_3MM [TouchesRoom('RoomDefinition_3MM') and OnLayer('L4_SIG')] p1: maxlimit=5 minlimit=3.5 preferedwidth=3.5
Width Width_BGA [TouchesRoom('RoomDefinition_BGA1') or TouchesRoom('RoomDefinition_BGA2') or TouchesRoom('RoomDefinition_BGA3')] p2: maxlimit=40 minlimit=4 preferedwidth=4 minimp=50.000000 maximp=50.000000 favimp=50.000000
Width Width_20mil [InNetClass('20mil')] p3: maxlimit=60 minlimit=5 preferedwidth=20 minimp=50.000000 maximp=50.000000 favimp=50.000000
Width [not TouchesRoom('RoomDefinition_TitleBlock')] p4: maxlimit=40 minlimit=3 preferedwidth=5 midlayer1_prefwidth=4 minimp=60.000000 maximp=60.000000 favimp=60.000000
25 further rules are at their usual default settings.

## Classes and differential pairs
component class mb1225: H1 H2 H6 H7
component class "U_Arduino_ Connectors": C85 CN9 CN11 CN13 CN14 LD3 R64 R98 R103 SB11 SB12 SB13 SB14 SB15
component class U_AUDIO: C44 C45 C55 C56 C57 C58 C59 C62 C63 C64 C65 C67 C71 C73 C74 C78 C79 C82 C87 C90 C91 C92 C93 C94 C95 C117 C118 C119 C120 CN6 CN7 CN8 CN12 JP2 JP3 R51 R71 R77 R78 R87 R88 R94 R95 R100 R101 R102 R111 R112 R114 R115 R116 R117 TP5 TP20 TP103 TP104 TP105 TP106 TP107 TP108 TP109 U5 U6 U8 U9 U11 U15 U16
component class U_DSI_LCD: C1 C2 C60 C61 CN1 H3 H4 H5 H8 L3 L4 R7 R8 SB1 SB2 SB3 SB4
component class U_Ethernet: C28 C29 C30 C33 C35 C36 C38 L2 R27 R28 R29 R30 R31 R32 R34 R35 R36 R37 R39 R40 R41 R43 R44 R45 R47 R105 R113 U3
component class U_Peripherals: B1 B2 C53 C54 CN2 CN5 LD1 LD2 R50 R52 R54 R56 R57 R62 R63 R67 R68 R70 R73 R76 R79 R80 R81 R82 R83 R200 SB5 SB6 SB8 SB9 SB10
component class U_PoE: C3 C4 C5 C6 C7 C8 C9 C10 C11 C12 C13 C14 C15 C16 C17 C18 C19 C20 C21 C22 C24 C26 C32 C34 C37 C39 C40 C66 C70 C75 C81 C89 C121 C122 C200 CN10 D1 D2 D3 D4 D9 D10 L5 R1 R2 R3 R4 R5 R6 R9 R10 R11 R12 R13 R14 R15 R16 R22 R23 R24 R25 R26 R33 R38 R42 R46 R48 R49 R74 R75 R84 R85 R96 T1 T2 T4 T100 U1 U2 U10
component class U_QSPI: C96 R86 U12 U250
component class U_SDRAM: C123 C124 C125 C126 C127 C128 C130 C131 C133 C134 C135 C136 C137 C138 TP26 TP27 TP28 U17
component class U_ST_LINK_V2-1: C41 C42 C43 C46 C47 C48 C49 C50 C51 C100 C129 C132 C139 C140 C141 C142 C143 C146 C151 C152 C155 CN3 CN4 CN16 D5 D6 D7 D8 D11 JP1 JP5 LD6 LD7 LD8 R58 R59 R60 R61 R118 R119 R120 R121 R122 R127 R135 R138 R140 R141 R143 R144 R145 R146 R147 R148 R149 R150 SB7 SB16 SB17 SB18 SB19 SB20 SB21 SB22 SB23 T3 U4 U7 U14 U18 U19 U22 X3
component class U_STM32F7: C23 C25 C27 C31 C68 C69 C72 C76 C77 C80 C83 C84 C86 C88 C97 C98 C99 C101 C102 C103 C104 C105 C106 C107 C108 C109 C110 C111 C112 C113 C114 C115 C116 JP4 L6 R17 R18 R19 R20 R21 R89 R90 R91 R92 R93 R97 R99 R104 R106 R107 R108 R109 R110 TP1 TP2 TP3 TP6 TP7 TP8 TP9 TP11 TP12 TP13 TP14 TP15 TP16 TP17 TP18 TP21 TP22 TP100 TP101 TP102 U13 X1 X2
component class U_USB_OTG_HS: C52 C144 C145 C147 C148 C149 C150 C153 C154 C156 C157 CN15 D12 D13 L7 L8 LD4 LD5 R65 R66 R123 R124 R125 R126 R128 R129 R130 R131 R132 R133 R134 R136 R137 R139 R142 T5 U20 U21 X4
net class ARD_A[0..5]: ARD_A0 ARD_A1 ARD_A2 ARD_A3 ARD_A4 ARD_A5
net class ARD_D[0..15]: ARD_D0 ARD_D1 ARD_D2 ARD_D3 ARD_D4 ARD_D5 ARD_D6 ARD_D7 ARD_D8 ARD_D9 ARD_D10 ARD_D11 ARD_D12 ARD_D13 ARD_D14 ARD_D15
net class FMC_A[0..12]: FMC_A0 FMC_A1 FMC_A2 FMC_A3 FMC_A4 FMC_A5 FMC_A6 FMC_A7 FMC_A8 FMC_A9 FMC_A10 FMC_A11 FMC_A12
net class FMC_D[0..31]: FMC_D0 FMC_D1 FMC_D2 FMC_D3 FMC_D4 FMC_D5 FMC_D6 FMC_D7 FMC_D8 FMC_D9 FMC_D10 FMC_D11 FMC_D12 FMC_D13 FMC_D14 FMC_D15 FMC_D16 FMC_D17 FMC_D18 FMC_D19 FMC_D20 FMC_D21 FMC_D22 FMC_D23 FMC_D24 FMC_D25 FMC_D26 FMC_D27 FMC_D28 FMC_D29 FMC_D30 FMC_D31 PE0 PE1 PI4 PI5
net class PA[0..15]: PA0 PA1 PA2 PA3 PA5 PA7 PA8 PA9 PA10 PA13 PA14 PA15
net class PB[0..15]: PB0 PB1 PB2 PB3 PB4 PB5 PB6 PB7 PB10 PB11 PB12 PB13
net class PC[0..15]: PC0 PC1 PC3 PC4 PC5 PC9 PC10 PC11 PC12 PC13 PC14 PC15
net class PD[0..15]: PD2 PD3 PD4 PD5 PD6 PD7 PD11 PD12 PD13
net class PE[0..15]: PE0 PE1 PE2 PE3 PE4 PE5 PE6
net class PF[0..15]: PF11
net class PG[0..15]: PG3 PG4 PG5 PG6 PG7 PG8 PG9 PG10 PG11 PG12 PG13 PG14 PG15
net class PH[0..15]: PH0 PH1 PH2 PH3 PH4 PH5 PH7
net class PI[0..15]: PI4 PI5 PI8 PI11 PI12 PI13 PI14 PI15
net class PJ[0..15]: PJ2 PJ5 PJ6 PJ7 PJ8 PJ9 PJ10 PJ11 PJ12 PJ13 PJ14 PJ15
net class PK[0..7]: PK0 PK1 PK2 PK3 PK4 PK5 PK6 PK7
net class 20mil: 1V8 3V3 3V3_ST_LINK 5V 5V_POE 5V_USB_CHARGER 5V_USB_HS E5V POE7 VDD VDDA VIN
differential pair class 100OHM: DSI.DSI_CK DSI.DSI_D0 DSI.DSI_D1
differential pair class 90OHM: RD TD USB_HS
net class CRL: PF11 PG4 PG5 PG15 PH2 PH3 PH5
differential pair DSI.DSI_CK: +DSI.DSI_CK_P -DSI.DSI_CK_N
differential pair DSI.DSI_D0: +DSI.DSI_D0_P -DSI.DSI_D0_N
differential pair DSI.DSI_D1: +DSI.DSI_D1_P -DSI.DSI_D1_N
differential pair RD: +RD_P -RD_N
differential pair TD: +TD_P -TD_N
differential pair USB_HS: +USB_HS_P -USB_HS_N
differential pair USB_STLK: +USB_STLK_P -USB_STLK_N

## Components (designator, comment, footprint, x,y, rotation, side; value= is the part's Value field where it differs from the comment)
B1 "SW-PUSH-CMS_BLUE" PB10 785,300 r180 top
B2 "SW-PUSH-CMS_BLACK" PB10 4235,300 r180 top
C1 "100nF" 0603C#1 3407.51,2911.92 r90 top
C2 "100nF" 0603C#1 3187.51,2911.92 r90 top
C3 "1nF_2KV_X7R_10%_1206" 1206C#1 3920,3360 r180 top value=1nF
C4 "1nF_100V_X7R_10%_0603" 0603C#1 4360,3295 r90 top value=1nF
C5 "10nF_100V_X7R_10%_0603" 0603C#1 4480,3255 r180 top value=10nF
C6 "100nF_50V_X7R_10%_0603" 0603C#1 3995,3205 r0 top value=100nF
C7 "100nF_50V_X7R_10%_0603" 0603C#1 3995,3155 r0 top value=100nF
C8 "1nF_100V_X7R_10%_0603" 0603C#1 4480,3130 r180 top value=1nF
C9 "470pF_100V_X7R_10%_0603" 0603C#1 3995,3105 r0 top value=470pF
C10 "10nF_100V_X7R_10%_0603" 0603C#1 4480,3075 r0 top value=10nF
C11 "100nF_50V_X7R_10%_0603" 0603C#1 4480,3020 r0 top value=100nF
C12 "100nF_50V_X7R_10%_0603" 0603C#1 3995,2945 r180 top value=100nF
C13 "47uF_X5R_20%_0805" 0805C#1 4235,2880 r270 top value=47uF
C14 "47uF_X5R_20%_0805" 0805C#1 4310,2880 r270 top value=47uF
C15 "47uF_X5R_20%_0805" 0805C#1 4385,2880 r270 top value=47uF
C16 "100nF_X7R_10%_0603" 0603C#1 4455,2875 r270 top value=100nF
C17 "100pF_50V_X7R_10%_0603" 0603C#1 3985,2715 r0 top value=100pF
C18 "47uF_X5R_20%_0805" 0805C#1 4340,2705 r0 top value=47uF
C19 "22nF_50V_X7R_10%_0603" 0603C#1 3985,2655 r0 top value=22nF
C20 "4.7uF_100V_X7S_20%_1206" 1206C#2 3600,2225 r180 bottom value=4.7uF
C21 "560pF_X7R_10%_0603" 0603C#2 4680,2535 r0 bottom value=560pF
C22 "27pF_100V_NPO_5%_0603" 0603C#2 3605,2305 r180 bottom value=27pF
C23 "2.2uF[N/A]" 1206C#1 2190,2245 r270 top value=2.2uF
C24 "1uF_25V_X5R_10%_0603" 0603C#2 3600,2620 r0 bottom value=1uF
C25 "2.2uF" 0603C#1 2369,2126 r180 top
C26 "1nF_100V" 0603C#1 4340,2095 r180 top value=1nF
C27 "100nF" 0402C#1 2385,2039 r180 top
C28 "1uF" 0603C#1 3530,2000 r270 top
C29 "470pF" 0402C#1 3580,2000 r270 top
C30 "100nF" 0402C#1 3750,2000 r270 top
C31 "2.2uF" 1206C#1 2040,1985 r0 top
C32 "1nF_100V" 0603C#1 4345,1865 r180 top value=1nF
C33 "100nF" 0402C#1 3460,1835 r0 top
C34 "1nF_100V" 0603C#1 4345,1815 r180 top value=1nF
C35 "100nF" 0402C#1 3800,1655 r90 top
C36 "10uF" TAN-A#1 3870,1620 r90 top
C37 "1nF_100V" 0603C#1 4345,1610 r180 top value=1nF
C38 "10uF" TAN-A#1 3520,1565 r180 top
C39 "1nF_100V_X7R_10%_0603" 0603C#1 4445,1475 r270 top value=1nF
C40 "100nF_100V_X7R_10%_0805" 0805C#1 4525,1320 r270 top value=100nF
C41 "1uF" 0603C#1 3995,875 r270 top
C42 "100nF" 0402C#1 4045,875 r90 top
C43 "10nF" 0603C#1 4245,875 r90 top
C44 "100nF" 0402C#1 2245,836 r0 top
C45 "100nF" 0402C#1 2810,820 r270 top
C46 "100nF" 0402C#1 4180,720 r90 top
C47 "1uF" 0603C#1 4110,710 r90 top
C48 "1uF" 0603C#1 4150,620 r0 top
C49 "100nF" 0402C#1 4150,570 r0 top
C50 "100nF" 0402C#1 4415,515 r270 top
C51 "1uF" 0603C#1 4150,500 r0 top
C52 "2.2uF_X7R_10%_0805" TAN-A#1 3030,405 r180 top value=2.2uF
C53 "100nF" 0402C#1 3965,395 r0 top
C54 "100nF" 0402C#1 1060,305 r0 top
C55 "100nF" 0402C#1 2245,255 r0 top
C56 "100nF" 0402C#1 2807.57,235 r270 top
C57 "100nF" 0402C#2 770,3110 r90 bottom
C58 "1uF" 0603C#2 1440,3090 r270 bottom
C59 "100nF" 0402C#2 1095,3060 r270 bottom
C60 "100nF" 0603C#2 3527.51,3276.92 r270 bottom
C61 "10uF" TAN-A#2 3630,3245 r270 bottom
C62 "1uF" 0603C#2 1775,2810 r270 bottom
C63 "1uF" 0603C#2 1105,2675 r90 bottom
C64 "100nF" 0402C#2 1055,2660 r270 bottom
C65 "100nF" 0402C#2 960,2660 r270 bottom
C66 "1uF_25V_X5R_10%_0603" 0603C#2 4200,2705 r180 bottom value=1uF
C67 "1uF" 0603C#2 875,2645 r180 bottom
C68 "4.7uF" TAN-A#2 2940,2550 r90 bottom
C69 "4.7uF" TAN-A#2 2835,2550 r90 bottom
C70 "4.7uF_100V_X7S_20%_1206" 1206C#1 3540,2485 r270 top value=4.7uF
C71 "100nF" 0402C#2 825,2505 r0 bottom
C72 "2.2uF" 1206C#2 2110,2475 r90 bottom
C73 "4.7uF" 0603C#2 815,2455 r180 bottom
C74 "2.2uF" 0603C#2 1255,2440 r180 bottom
C75 "4.7uF_100V_X7S_20%_1206" 1206C#1 3625,2485 r270 top value=4.7uF
C76 "100nF" 0402C#2 2830,2425 r0 bottom
C77 "4.3pF_NPO_-+0.25pF_0402" 0402C#2 3020,2395 r90 bottom value=4.3pF
C78 "2.2uF" 0603C#2 1255,2390 r180 bottom
C79 "4.7uF" 0603C#2 815,2400 r180 bottom
C80 "100nF" 0402C#2 2830,2375 r0 bottom
C81 "100nF_100V_X7R_10%_0805" 0805C#1 3455,2485 r270 top value=100nF
C82 "2.2uF" 0603C#2 1255,2330 r180 bottom
C83 "100nF" 0402C#2 2830,2325 r0 bottom
C84 "4.3pF_NPO_-+0.25pF_0402" 0402C#2 3020,2310 r270 bottom value=4.3pF
C85 "[NA]" 0402C#2 1585,2310 r180 bottom
C86 "100nF" 0402C#2 2830,2280 r0 bottom
C87 "100nF" 0402C#2 665,2275 r270 bottom
C88 "100nF" 0402C#2 2830,2230 r0 bottom
C89 "1nF_2KV" 1206C#1 4310,2180 r180 top value=1nF
C90 "1uF" 0603C#2 1175,2215 r90 bottom
C91 "100nF" 0402C#2 1115,2215 r90 bottom
C92 "4.7uF" 0603C#2 1065,2215 r90 bottom
C93 "4.7uF" 0603C#2 1015,2215 r90 bottom
C94 "4.7uF" 0603C#2 965,2215 r90 bottom
C95 "4.7uF" 0603C#2 915,2215 r270 bottom
C96 "100nF_X7R_10%_0402" 0402C#2 1730,2205 r270 bottom value=100nF
C97 "100nF" 0402C#2 2830,2180 r0 bottom
C98 "100nF" 0402C#2 3170,2160 r270 bottom
C99 "100nF" 0402C#2 2830,2130 r0 bottom
C100 "10uF" 0603C#2 1090,2055 r0 bottom
C101 "1uF" TAN-A#2 2885,1930 r0 bottom
C102 "100nF" 0402C#2 2885,1850 r0 bottom
C103 "100nF" 0402C#2 2885,1790 r0 bottom
C104 "100nF" 0402C#2 2755,1735 r270 bottom
C105 "100nF" 0402C#2 2695,1735 r270 bottom
C106 "100nF" 0402C#2 2655,1735 r270 bottom
C107 "100nF" 0402C#2 2600,1735 r270 bottom
C108 "100nF" 0402C#2 2545,1735 r270 bottom
C109 "100nF" 0402C#2 2450,1735 r270 bottom
C110 "100nF" 0402C#2 2405,1735 r270 bottom
C111 "100nF" 0402C#2 2360,1735 r270 bottom
C112 "100nF" 0402C#2 2305,1735 r270 bottom
C113 "100nF" 0402C#2 2255,1735 r270 bottom
C114 "100nF" 0402C#2 2205,1735 r270 bottom
C115 "100nF" 0402C#2 2150,1735 r270 bottom
C116 "1uF" TAN-A#2 2885,1720 r0 bottom
C117 "100nF" 0402C#2 1010,1695 r180 bottom
C118 "100nF" 0402C#2 845,1695 r180 bottom
C119 "22nF" 0402C#2 765,1645 r270 bottom
C120 "22nF" 0402C#2 670,1645 r90 bottom
C121 "1nF_100V_X7R_10%_0603" 0603C#2 4510,1595 r90 bottom value=1nF
C122 "1nF_100V_X7R_10%_0603" 0603C#2 4460,1595 r270 bottom value=1nF
C123 "100nF_X7R_10%_0402" 0402C#2 2555,1445 r90 bottom value=100nF
C124 "100nF_X7R_10%_0402" 0402C#2 2345,1445 r90 bottom value=100nF
C125 "100nF_X7R_10%_0402" 0402C#2 2210,1445 r90 bottom value=100nF
C126 "100nF_X7R_10%_0402" 0402C#2 2820,1250 r0 bottom value=100nF
C127 "100nF_X7R_10%_0402" 0402C#2 2095,1150 r180 bottom value=100nF
C128 "100nF_X7R_10%_0402" 0402C#2 2820,1145 r0 bottom value=100nF
C129 "10uF" 0805C#2 4270,750 r0 bottom
C130 "100nF_X7R_10%_0402" 0402C#2 2095,1105 r180 bottom value=100nF
C131 "100nF_X7R_10%_0402" 0402C#2 2820,1095 r0 bottom value=100nF
C132 "100nF" 0402C#2 3885,1000 r0 bottom
C133 "100nF_X7R_10%_0402" 0402C#2 2670,930 r270 bottom value=100nF
C134 "100nF_X7R_10%_0402" 0402C#2 2600,930 r270 bottom value=100nF
C135 "100nF_X7R_10%_0402" 0402C#2 2540,930 r270 bottom value=100nF
C136 "100nF_X7R_10%_0402" 0402C#2 2405,930 r270 bottom value=100nF
C137 "100nF_X7R_10%_0402" 0402C#2 2335,930 r270 bottom value=100nF
C138 "100nF_X7R_10%_0402" 0402C#2 2290,930 r270 bottom value=100nF
C139 "10uF" 0805C#2 4400,935 r270 bottom
C140 "100nF" 0402C#2 3885,900 r180 bottom
C141 "10pF" 0402C#2 3780,900 r0 bottom
C142 "10pF" 0402C#2 3695,900 r180 bottom
C143 "100nF" 0402C#2 3510,750 r180 bottom
C144 "100nF" 0402C#2 2830,700 r0 bottom
C145 "100nF" 0402C#2 2930,630 r180 bottom
C146 "100nF" 0402C#2 4025,540 r0 bottom
C147 "100nF_X7R_10%_0402" 0402C#2 2795,515 r180 bottom value=100nF
C148 "4.7uF_X5R_10%_0603" 0603C#2 2430,490 r90 bottom value=4.7uF
C149 "100nF" 0402C#2 3100,435 r270 bottom
C150 "100nF" 0402C#2 3045,435 r90 bottom
C151 "100nF" 0402C#2 3650,380 r270 bottom
C152 "100nF" 0402C#2 4365,325 r270 bottom
C153 "100nF" 0402C#2 2900,285 r180 bottom
C154 "100nF" 0402C#2 3240,265 r90 bottom
C155 "1uF" 0603C#2 4005,235 r270 bottom
C156 "100nF" 0402C#2 2900,160 r180 bottom
C157 "100nF" 0402C#2 3400,55 r0 bottom
C200 "10nF_X7R_10%_0603" 0603C#2 3920,2735 r0 bottom value=10nF
CN1 "QSH-030-01-F-D-A-K-TR" QSH-030-01-F-D-A 3489.99,3163.54 r180 top
CN2 "Header F Straight 4x2H" HDR_2X4_2R54 815,960 r270 top
CN3 "Header M Straight 5x2H" HDR_2X5_2R54 4514.22,558 r180 bottom
CN4 "Header 4" HDR_1X4_2R54 4465,95 r180 top
CN5 "PJS008-2003" MSD_PJS008_ 2415,3099.56 r180 bottom
CN6 "PJ3028B-3_BE" PJ3028B 1615,3264.56 r90 bottom
CN7 "PJ3028B-3_GR" PJ3028B 940,3264.56 r90 bottom
CN8 "RCA_SMD_Y" PHONE_JACK_JBB0819100002 487.25,2395 r270 bottom
CN9 "BL 1-10 G" HDR_1X10_2R54_W 1405.8,1727.7 r270 bottom
CN10 "KRJ-CB4" RJ45_LED_KRJ-CB4R2GYZNL_EM 4508.23,1980 r90 bottom
CN11 "BL 1-8 G" HDR_1X8_2R54_W 3305.8,2267.7 r90 bottom
CN12 "RCA_SMD_W" PHONE_JACK_JBB0819100002 487.25,1725 r270 bottom
CN13 "BL 1-8 G" HDR_1X8_2R54_W 1405.8,867.7 r270 bottom
CN14 "BL 1-6 G" HDR_1X6_2R54_W 3305.8,1367.7 r90 bottom
CN15 "475900001" MOLEX_47590001 3130.87,162.8 r0 bottom
CN16 "1050170001" MICRO_USB_B_105017 3735,159.45 r0 bottom
D1 "BAT46JFILM" SOD-323#1 3855,2650 r0 top
D2 "STPS2L40UF" SMB 4525,2485 r90 bottom
D3 "BAT46JFILM" SOD-323#2 3600,2555 r180 bottom
D4 "DF01S" DBS101-107G#1 4195,1415 r90 top
D5 "BAT60JFILM" SOD-323#1 4355,975 r180 top
D6 "BAT60JFILM" SOD-323#1 4355,875 r180 top
D7 "BAT60JFILM" SOD-323#1 4355,775 r180 top
D8 "BAT60JFILM" SOD-323#1 4355,670 r180 top
D9 "DF01S" DBS101-107G#2 4195,1415 r90 bottom
D10 "SMAJ58A" SMA 4485,1400 r90 bottom
D11 "BAT60JFILM" SOD-323#2 3525,395 r0 bottom
D12 "ESDA14V2-2BF3" BGA4_0R4_0R8X0R8 3185,265 r180 bottom
D13 "USBULC6-2F3" BGA4_0R4_0R8X0R8 3118,263 r180 bottom
H1 "POSITION HOLE C6D3R5" HOLE_C6D3R5 196.85,3260 r0 top
H2 "POSITION HOLE C6D3R5" HOLE_C6D3R5 4792.99,3260 r0 top
H3 "POSITION HOLE" HOLE_C9D4R5-1 207,2802.84 r315 top
H4 "POSITION HOLE" HOLE_C9D4R5 4792.99,2802.84 r0 top
H5 "POSITION HOLE" HOLE_C9D4R5 4792.99,1318.43 r0 top
H6 "POSITION HOLE C6D3R5" HOLE_C6D3R5 196.85,196.85 r0 top
H7 "POSITION HOLE C6D3R5" HOLE_C6D3R5 4792.99,196.85 r0 top
H8 "POSITION HOLE" HOLE_C9D4R5-1 207,1318.43 r45 top
JP1 "WF25402-06421" HDR_1X2_2R54_RA_11R35 4495,975 r90 top
JP2 "JP2" SIP2 605,3365 r90 bottom
JP3 "JP2" SIP2 480,3365 r90 bottom
JP4 "JP2" SIP2 1675,2025 r0 bottom
JP5 "JP2" SIP2 3995,1140 r0 bottom
L2 "BLM18PG121SN1D" 0603L#1 3745,1645 r270 top value=100uH
L3 "FCM1608KF-601T03" 0603L#2 3467.51,3276.92 r90 bottom value=100uH
L4 "FCM1608KF-601T03" 0603L#2 3700,3265 r270 bottom value=100uH
L5 "ME3220-562ML" LSM2_3R2X2R8_H2 3615,2280 r90 top value=5.6uH
L6 "FCM1608KF-601T03" 0603L#2 3020,1725 r270 bottom value=100uH
L7 "BLM18PG121SN1D" 0603L#2 3050,275 r90 bottom value=100uH
L8 "BLM18PG121SN1D" 0603L#2 2900,230 r180 bottom value=100uH
LD1 "LED, red" 0603D 1290,215 r270 top
LD2 "LED, green" 0603D 1390,215 r270 top
LD3 "LED, green" 0603D 1490,215 r270 top
LD4 "LED, red" 0603D 1590,215 r270 top
LD5 "LED, green" 0603D 1685,215 r270 top
LD6 "LED, red" 0603D 1780,215 r270 top
LD7 "LED, red" 0603D 1885,215 r270 top
LD8 "LD_BICOLOR_CMS" LED2_3528 3450,215 r0 top
R1 "75K_1%_0603" 0603R#1 4480,3310 r180 top value=75K
R2 "0_5%_0603" 0603R-GS 3995,3270 r180 top value=0
R3 "2K_1%_0805" 0805R#1 4480,3190 r180 top value=2K
R4 "510_1%_0603" 0603R#1 3995,3050 r180 top value=510
R5 "1K_1%_0603" 0603R#1 3995,3000 r0 top value=1K
R6 "124K_1%_0603" 0603R#1 4480,2965 r0 top value=124K
R7 "0" 0402R#1 3350,3280 r270 bottom
R8 "10K" 0402R#1 3220,3280 r270 bottom
R9 "0.47_1%_1206" 1206R#1 3820,2905 r180 top value=0.47
R10 "56_1%_0805" 0805R#1 3820,2775 r270 top value=56
R11 "20K_1%_0603" 0603R#1 4215,2775 r0 top value=20K
R12 "10K_1%_0603" 0603R#1 3890,2770 r270 top value=10K
R13 "10K_1%_0603" 0603R#1 4070,2685 r90 top value=10K
R14 "13K_1%_0603" 0603R#1 4125,2685 r90 top value=13K
R15 "13K_1%_0603" 0603R#1 4180,2685 r90 top value=13K
R16 "0_5%_0603" 0603R-GS 4455,2740 r90 top value=0
R17 "2K7" 0402R#2 2405,2550 r90 top
R18 "10K_1%_0402" 0402R#2 2510,2550 r270 top value=10K
R19 "[NA]" 0402R#2 2550,2550 r270 top
R20 "10K_1%_0402" 0402R#2 2595,2550 r270 top value=10K
R21 "[NA]" 0402R#2 2635,2550 r270 top
R22 "15" 0805R#2 4675,2425 r180 bottom
R23 "200" 1206R#2 3595,2385 r180 bottom
R24 "68" 0805R#2 3600,2480 r180 bottom
R25 "10K_1%_0603" 0603R#2 3600,2675 r0 bottom value=10K
R26 "75" 0805R#1 4345,2030 r0 top
R27 "100" 0402R#2 3620,2000 r270 top
R28 "10K" 0402R#2 3660,2000 r270 top
R29 "10K" 0402R#2 3700,2000 r270 top
R30 "10K" 0402R#2 3460,1995 r180 top
R31 "12K1" 0603R#1 3860,1980 r0 top
R32 "33" 0402R#2 3460,1955 r180 top
R33 "75" 0805R#1 4350,1940 r0 top
R34 "10K" 0402R#2 3460,1915 r180 top
R35 "50" 0402R#2 3865,1910 r180 top
R36 "33" 0402R#2 3460,1875 r180 top
R37 "50" 0402R#2 3865,1870 r180 top
R38 "0_5%_0805" 0805R#1 3970,1850 r270 top value=0
R39 "50" 0402R#2 3865,1830 r180 top
R40 "10K" 0402R#2 3460,1790 r0 top
R41 "50" 0402R#2 3865,1790 r180 top
R42 "75" 0805R#1 4350,1755 r0 top
R43 "10K" 0402R#2 3460,1750 r180 top
R44 "33" 0402R#2 3460,1695 r180 top
R45 "10K" 0402R#2 3625,1685 r270 top
R46 "75" 0805R#1 4350,1670 r0 top
R47 "1K5" 0402R#2 3460,1650 r180 top
R48 "0" 0805R#1 4525,1470 r270 top
R49 "0" 0805R#1 4450,1315 r270 top
R50 "1K" 0402R#2 1060,905 r180 top
R51 "10K" 0402R#2 2690,890 r0 top
R52 "10K" 0402R#2 1060,660 r180 top
R54 "10K" 0402R#2 1060,770 r180 top
R56 "10K" 0402R#2 1060,815 r180 top
R57 "1K" 0402R#2 1060,705 r0 top
R58 "1K" 0402R#2 1780,365 r270 top
R59 "1K" 0402R#2 1885,365 r90 top
R60 "330" 0402R#2 3420,365 r270 top
R61 "330" 0402R#2 3480,365 r270 top
R62 "1K_1%_0603" 0603R#1 1290,360 r270 top value=1K
R63 "330_1%_0603" 0603R#1 1390,360 r270 top value=330
R64 "510_1%_0402" 0402R#2 1490,360 r90 top value=510
R65 "620_1%_0603" 0603R#1 1590,360 r90 top value=620
R66 "330_1%_0402" 0402R#2 1685,360 r90 top value=330
R67 "10K_1%_0402" 0402R#2 3965,325 r180 top value=10K
R68 "10K" 0402R#2 1060,260 r180 top
R70 "10K" 0402R#2 1060,215 r180 top
R71 "10K" 0402R#2 2565,255 r180 top
R73 "0_5%_0402" 0402R#1 2915,3150 r270 bottom value=0
R74 "0" 0603R-GS 3965,3130 r90 bottom
R75 "10_1%_0805" 0805R#2 4455,3065 r90 bottom value=10
R76 "[NA]" 0402R#1 2915,3060 r90 bottom
R77 "20" 0402R#1 1140,3060 r90 bottom
R78 "20" 0402R#1 770,3020 r90 bottom
R79 "47K_1%_0402" 0402R#1 2780,2785 r90 bottom value=47K
R80 "47K_1%_0402" 0402R#1 2730,2785 r90 bottom value=47K
R81 "47K_1%_0402" 0402R#1 2560,2785 r90 bottom value=47K
R82 "47K_1%_0402" 0402R#1 2515,2785 r90 bottom value=47K
R83 "47K_1%_0402" 0402R#1 2470,2785 r90 bottom value=47K
R84 "0_5%_0805" 0805R#2 4205,2770 r180 bottom value=0
R85 "1K_1%_0603" 0603R#2 3920,2800 r0 bottom value=1K
R86 "10K_1%_0402" 0402R#1 1710,2655 r0 bottom value=10K
R87 "10K" 0402R#1 1010,2655 r270 bottom
R88 "0" 0402R#1 1240,2585 r0 bottom
R89 "2K7" 0402R#1 2595,2550 r90 bottom
R90 "2K7" 0402R#1 2550,2550 r90 bottom
R91 "2K7" 0402R#1 2510,2550 r90 bottom
R92 "[NA]" 0402R#1 2405,2550 r90 bottom
R93 "0" 0402R#1 2355,2550 r90 bottom
R94 "[NA]" 0402R#1 1240,2540 r180 bottom
R95 "0" 0402R#1 1240,2490 r0 bottom
R96 "0_5%_0805" 0805R#2 4785,2460 r270 bottom value=0
R97 "0" 0402R#1 2955,2375 r0 bottom
R98 "0" 0402R#1 1585,2355 r180 bottom
R99 "0" 0402R#1 2955,2325 r0 bottom
R100 "0" 0402R#1 800,2275 r270 bottom
R101 "210" 0402R#1 755,2275 r90 bottom
R102 "110" 0402R#1 710,2275 r270 bottom
R103 "1K" 0402R#1 3425,2245 r90 bottom
R104 "100_1%_0402" 0402R#1 2955,2205 r0 bottom value=100
R105 "330" 0402R#1 4455,2230 r90 bottom
R106 "10K_1%_0402" 0402R#1 2830,2085 r180 bottom value=10K
R107 "10K_1%_0402" 0402R#1 3080,2075 r180 bottom value=10K
R108 "10K" 0402R#1 2830,2045 r0 bottom
R109 "0" 0603R-GS 1615,1930 r180 bottom
R110 "0" 0603R-GS 3020,1860 r90 bottom
R111 "75" 0402R#1 715,1645 r270 bottom
R112 "1M" 0402R#1 930,1640 r270 bottom
R113 "330" 0402R#1 4575,1610 r270 bottom
R114 "[NA]" 0402R#1 765,1560 r90 bottom
R115 "1M" 0402R#1 715,1560 r270 bottom
R116 "100" 0402R#1 670,1560 r90 bottom
R117 "100" 0402R#1 930,1550 r270 bottom
R118 "100K_1%_0402" 0402R#1 3885,950 r180 bottom value=100K
R119 "4K7" 0402R#1 4000,920 r90 bottom
R120 "4K7" 0402R#1 3955,920 r90 bottom
R121 "[NA]" 0402R#1 3615,915 r90 bottom
R122 "10K" 0402R#1 3570,915 r90 bottom
R123 "0_5%_0402" 0402R#1 3220,810 r270 bottom value=0
R124 "[NA]" 0402R#1 3180,810 r90 bottom
R125 "0_5%_0402" 0402R#1 3285,700 r180 bottom value=0
R126 "0_5%_0402" 0402R#1 2930,700 r0 bottom value=0
R127 "100K_1%_0402" 0402R#1 3510,670 r180 bottom value=100K
R128 "[NA]" 0402R#1 3285,660 r0 bottom
R129 "0" 0402R#1 2585,610 r270 bottom
R130 "3K3" 0402R#1 2540,610 r90 bottom
R131 "100K_1%_0402" 0402R#1 2490,610 r90 bottom value=100K
R132 "47K_1%_0402" 0402R#1 2430,610 r270 bottom value=47K
R133 "[NA]" 0402R#1 3285,600 r0 bottom
R134 "10K_1%_0402" 0402R#1 2710,600 r270 bottom value=10K
R135 "4K7_1%_0402" 0402R#1 3510,575 r180 bottom value=4K7
R136 "100_1%_0402" 0402R#1 2930,575 r180 bottom value=100
R137 "0_5%_0402" 0402R#1 3285,560 r180 bottom value=0
R138 "0" 0402R#1 3510,530 r0 bottom
R139 "8K06_1%_0402" 0402R#1 2930,530 r0 bottom value=8K06
R140 "2K2" 0402R#1 4190,500 r0 bottom
R141 "2K7_1%_0402" 0402R#1 3510,480 r0 bottom value=2K7
R142 "820_1%_0805" 0805R#2 2970,425 r90 bottom value=820
R143 "100" 0402R#1 3850,405 r180 bottom
R144 "10K" 0402R#1 4005,365 r90 bottom
R145 "100" 0402R#1 3895,255 r270 bottom
R146 "36K" 0402R#1 3850,255 r90 bottom
R147 "10K" 0402R#1 3805,255 r90 bottom
R148 "1K5" 0402R#1 3725,255 r270 bottom
R149 "100K" 0402R#1 3685,255 r90 bottom
R150 "100K" 0402R#1 4215,230 r0 bottom
R200 "10K" 0402R#2 1060,860 r180 top
SB1 "Solder Bridge ON" JP2_SMD 3690,2925 r270 top
SB2 "Solder Bridge ON" JP2_SMD 3620,2925 r270 top
SB3 "Solder Bridge ON" JP2_SMD 3550,2925 r270 top
SB4 "Solder Bridge ON" JP2_SMD 3480,2925 r270 top
SB5 "Solder Bridge OFF" JP2_SMD 1060,965 r180 top
SB6 "Solder Bridge OFF" JP2_SMD 1060,600 r180 top
SB7 "Solder Bridge ON" JP2_SMD 4240,720 r90 top
SB8 "Solder Bridge ON" JP2_SMD 1060,530 r180 top
SB9 "Solder Bridge ON" JP2_SMD 1060.14,364.8 r0 top
SB10 "Solder Bridge ON" JP2_SMD 3965,270 r0 top
SB11 "Solder Bridge OFF" JP2_SMD 1585,2635 r0 bottom
SB12 "Solder Bridge ON" JP2_SMD 1585,2565 r0 bottom
SB13 "Solder Bridge OFF" JP2_SMD 1585,2490 r0 bottom
SB14 "Solder Bridge ON" JP2_SMD 1585,2420 r0 bottom
SB15 "Solder Bridge ON" JP2_SMD 1585,2225 r180 bottom
SB16 "Solder Bridge OFF" JP2_SMD 3980,1000 r180 bottom
SB17 "Solder Bridge ON" JP2_SMD 4025,835 r180 bottom
SB18 "Solder Bridge ON" JP2_SMD 4025,765 r180 bottom
SB19 "Solder Bridge ON" JP2_SMD 4025,695 r0 bottom
SB20 "Solder Bridge ON" JP2_SMD 4025,625 r0 bottom
SB21 "Solder Bridge ON" JP2_SMD 3770,372 r270 bottom
SB22 "Solder Bridge ON" JP2_SMD 3855,350 r0 bottom
SB23 "Solder Bridge OFF" JP2_SMD 4425,325 r90 bottom
T1 "STN4NF20L" SOT-223#1 3605,2720 r90 top
T2 "POE30P50L" TF_10R9X13R2-12R2X14R4_CPT 4100,2434 r270 bottom
T3 "9013-SOT23" SOT-23#1 3760,305 r180 top
T4 "H2019NL" TF_16SM_12R7X9R65 4150,1850 r270 bottom
T5 "9013-SOT23" SOT-23#2 2315,590 r90 bottom
T100 "POE30P50L" TF_8SM_12R04X12R85 3960,2435 r270 bottom
TP1 "TP" TP_C40 3405,3290 r270 bottom
TP2 "TP" TP_C40 3335,3170 r180 bottom
TP3 "TP" TP_C40 3405,3170 r270 bottom
TP5 "TP" TP_C40 1975,160 r180 top
TP6 "TP" TP_C40 1240,2710 r0 bottom
TP7 "TP" TP_C40 1240,2645 r0 bottom
TP8 "TP" TP_C40 1170,2645 r0 bottom
TP9 "TP" TP_C40 2525,2635 r90 bottom
TP11 "TP" TP_C40 2680,2625 r0 bottom
TP12 "TP" TP_C40 2755,2555 r0 bottom
TP13 "TP" TP_C40 2675,2550 r0 bottom
TP14 "TP" TP_C40 2755,2480 r90 bottom
TP15 "TP" TP_C40 2670,2475 r0 bottom
TP16 "TP" TP_C40 2575,2475 r0 bottom
TP17 "TP" TP_C40 2510,2475 r0 bottom
TP18 "TP" TP_C40 2435,2475 r0 bottom
TP20 "Test point 1 pin with hole" TP 835,2085 r0 bottom
TP21 "TP" TP_C40 2950,2135 r180 bottom
TP22 "TP" TP_C40 2090,2015 r90 bottom
TP26 "TP" TP_C40 2262,1531 r180 bottom
TP27 "TP" TP_C40 2825,1025 r180 bottom
TP28 "TP" TP_C40 2470,930 r180 bottom
TP100 "TP" TP_C40 2230,2525 r0 bottom
TP101 "TP" TP_C40 3030,1955 r0 bottom
TP102 "TP" TP_C40 2950,2265 r0 bottom
TP103 "TP" TP_C40 2225,730 r0 top
TP104 "TP" TP_C40 2245,125 r0 top
TP105 "TP" TP_C40 730,2640 r0 bottom
TP106 "TP" TP_C40 850,2185 r0 bottom
TP107 "TP" TP_C40 850,2265 r0 bottom
TP108 "TP" TP_C40 845,2340 r0 bottom
TP109 "TP" TP_C40 730,2565 r0 bottom
U1 "PM8800A" TSSOP16_0R65_5X6R4_TP 4240,3120 r90 top
U2 "TS431AILT" SOT23-5#1 4005,2820 r270 top
U3 "LAN8742A-CZ-TR" QFN24_0R5_4X4 3655,1850 r270 top
U4 "LD3985M33R" SOT-23-5L 4140,860 r0 top
U5 "MP34DT01" MP34DT01TR 2109.43,792.55 r270 top
U6 "MP34DT01" MP34DT01TR 2694.04,792.55 r270 top
U7 "LD39050PU33R" DFN6_0R95_3X3 4300,530 r90 top
U8 "MP34DT01" MP34DT01TR 2109.43,207.94 r270 top
U9 "MP34DT01" MP34DT01TR 2694.04,207.94 r270 top
U10 "HMHA2801A" PC_4SM_1R27_2R5X6R8 4045,2865 r0 bottom
U11 "WM8994ECS/R" BGA72_0R5_4R5X4 1035,2445 r90 bottom
U12 "MT25QL512ABB1EW9 (MICRON)" DFN8_1R27_6X8_TP4R8X5R16 1805,2435 r180 bottom
U13 "STM32F769NIH6" BGA216_0R8_13X13 2450,2110 r0 bottom
U14 "LD1117S18TR" SOT-223#2 1090,1890 r90 bottom
U15 "74LVC1G04SE" SOT-353 1005,1595 r0 bottom
U16 "74LVC1G04SE" SOT-353 845,1595 r0 bottom
U17 "MT48LC4M32B2B5-6A  (MICRON)" FBGA90_0R8_8X13 2460,1185 r90 bottom
U18 "LD1117S50TR" SOT-223#2 4220,990 r0 bottom
U19 "STM32F103CBT6" LQFP48_0R5_9X9 3760,640 r90 bottom
U20 "USB3320C-EZK" QFN32_0R5_5X5 3110,630 r90 bottom
U21 "STMPS2151STR" SOT23-5#2 2530,475 r180 bottom
U22 "ST890CDR" SOIC8_1R27_4R9X6 4185,365 r270 bottom
U250 "MX25L51245G (MACRONIX)" SON8_1R27_6X8 1805,2435.44 r180 top
X1 "NX3215SA-32.768K" XTAL_2SM_3R2X1R5 3100,2350 r90 bottom
X2 "NZ2520SB-25.00M" OSC_4SM_2R5X2 3070,2165 r0 bottom
X3 "NX3225GD-8.00M" XTAL_2SM_3R2X2R5_H1 3740,1000 r0 bottom
X4 "NZ2520SB-24.00M" OSC_4SM_2R5X2 2810,605 r180 bottom

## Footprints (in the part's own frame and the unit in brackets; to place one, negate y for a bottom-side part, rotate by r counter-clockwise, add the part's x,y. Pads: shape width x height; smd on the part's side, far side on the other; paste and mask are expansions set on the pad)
0402C#1 [mil] "0402C"
  rect 22x22 smd: 1(-20,0) 2(20,0)
  silkscreen extent -40,-20 40,20, body extent -35,-14 35,14, height 150
0402C#2 [mil] "0402C"
  rect 22x22 smd: 1(20,0) 2(-20,0)
  silkscreen extent -40,-20 40,20, body extent -35,-14 35,14, height 150
0402R#1 [mil] "0402R"
  rect 22x22 smd: 1(20,0) 2(-20,0)
  silkscreen extent -40,-20 40,20, body extent -35,-14 35,14, height 150
0402R#2 [mil] "0402R"
  rect 22x22 smd: 1(-20,0) 2(20,0)
  silkscreen extent -40,-20 40,20, body extent -35,-14 35,14, height 150
0603C#1 [mil] "0603C"
  rect 35x32 smd: 1(-30,0) 2(30,0)
  TOP keep-out region: -5,-10 5,-10 5,10 -5,10 -5,-10
  silkscreen extent -57,-25 57,25, body extent -50,-20 50,20, height 150
0603C#2 [mil] "0603C"
  rect 35x32 smd: 1(30,0) 2(-30,0)
  TOP keep-out region: 5,10 -5,10 -5,-10 5,-10 5,10
  silkscreen extent -57,-25 57,25, body extent -50,-20 50,20, height 150
0603D [mil] "0603D"
  rect 35x32 smd: 1(-30,0) 2(30,0)
  TOP keep-out region: -5,-10 5,-10 5,10 -5,10 -5,-10
  silkscreen extent -57,-25 65,25, body extent -50,-20 50,20, height 150
0603L#1 [mil] "0603L"
  rect 35x32 smd: 1(-30,0) 2(30,0)
  silkscreen extent -60,-28 60,28, body extent -50,-19 50,19, height 150
0603L#2 [mil] "0603L"
  rect 35x32 smd: 1(30,0) 2(-30,0)
  silkscreen extent -60,-28 60,28, body extent -50,-19 50,19, height 150
0603R#1 [mil] "0603R"
  rect 31x32 smd: 1(-30,0) 2(30,0)
  TOP keep-out region: -5,10 -5,-10 5,-10 5,10 -5,10
  silkscreen extent -57,-25 57,25, body extent -50,-20 50,20, height 150
0603R#2 [mil] "0603R"
  rect 31x32 smd: 1(30,0) 2(-30,0)
  TOP keep-out region: 5,-10 5,10 -5,10 -5,-10 5,-10
  silkscreen extent -57,-25 57,25, body extent -50,-20 50,20, height 150
0603R-GS [mil] "0603R-GS"
  rect 49x47 smd mask+2: 1(-30.51,0) 2(30.51,0)
  silkscreen extent -60,-32 60,31, body extent -55,-24 55,24, height 150
0805C#1 [mil] "0805C"
  rect 45x50 smd: 1(-35,0) 2(35,0)
  silkscreen extent -70,-35 70,35, body extent -65,-25 65,25, height 150
0805C#2 [mil] "0805C"
  rect 45x50 smd: 1(35,0) 2(-35,0)
  silkscreen extent -70,-35 70,35, body extent -65,-25 65,25, height 150
0805R#1 [mil] "0805R"
  rect 40x50 smd: 1(-35,0) 2(35,0)
  silkscreen extent -71,-35 70,35, body extent -65,-25 65,25, height 150
0805R#2 [mil] "0805R"
  rect 40x50 smd: 1(35,0) 2(-35,0)
  silkscreen extent -70,-35 71,35, body extent -65,-25 65,25, height 150
1206C#1 [mil] "1206C"
  rect 46x60 smd: 1(-58,0) 2(58,0)
  silkscreen extent -91,-40 91,40, body extent -81,-30 81,30, height 150
1206C#2 [mil] "1206C"
  rect 46x60 smd: 1(58,0) 2(-58,0)
  silkscreen extent -91,-40 91,40, body extent -81,-30 81,30, height 150
1206R#1 [mil] "1206R"
  rect 40x60 smd: 1(-56,0) 2(60,0)
  silkscreen extent -95,-40 95,40, body extent -80,-30 80,30, height 150
1206R#2 [mil] "1206R"
  rect 40x60 smd: 1(56,0) 2(-60,0)
  silkscreen extent -95,-40 95,40, body extent -80,-30 80,30, height 150
BGA4_0R4_0R8X0R8 [mil] "BGA4_0R4_0R8X0R8"
  round 9 smd mask+2: A1(7.87,-7.87) A2(-7.87,-7.87) B1(7.87,7.87) B2(-7.87,7.87)
  silkscreen extent -16,-20 20,16, body extent -16,-16 16,16, height 150
BGA72_0R5_4R5X4 [mm] "BGA72_0R5_4R5X4"
  round 0.249 smd mask+0.051: A1(2,-1.75) A2(1.5,-1.75) A3(1,-1.75) A4(0.5,-1.75) A5(0,-1.75) A6(-0.5,-1.75) A7(-1,-1.75) A8(-1.5,-1.75) A9(-2,-1.75) B1(2,-1.25) B2(1.5,-1.25) B3(1,-1.25) B4(0.5,-1.25) B5(0,-1.25) B6(-0.5,-1.25) B7(-1,-1.25) B8(-1.5,-1.25) B9(-2,-1.25) C1(2,-0.75) C2(1.5,-0.75) C3(1,-0.75) C4(0.5,-0.75) C5(0,-0.75) C6(-0.5,-0.75) C7(-1,-0.75) C8(-1.5,-0.75) C9(-2,-0.75) D1(2,-0.25) D2(1.5,-0.25) D3(1,-0.25) D4(0.5,-0.25) D5(0,-0.25) D6(-0.5,-0.25) D7(-1,-0.25) D8(-1.5,-0.25) D9(-2,-0.25) E1(2,0.25) E2(1.5,0.25) E3(1,0.25) E4(0.5,0.25) E5(0,0.25) E6(-0.5,0.25) E7(-1,0.25) E8(-1.5,0.25) E9(-2,0.25) F1(2,0.75) F2(1.5,0.75) F3(1,0.75) F4(0.5,0.75) F5(0,0.75) F6(-0.5,0.75) F7(-1,0.75) F8(-1.5,0.75) F9(-2,0.75) G1(2,1.25) G2(1.5,1.25) G3(1,1.25) G4(0.5,1.25) G5(0,1.25) G6(-0.5,1.25) G7(-1,1.25) G8(-1.5,1.25) G9(-2,1.25) H1(2,1.75) H2(1.5,1.75) H3(1,1.75) H4(0.5,1.75) H5(0,1.75) H6(-0.5,1.75) H7(-1,1.75) H8(-1.5,1.75) H9(-2,1.75)
  silkscreen extent -4.25,-4 4.25,4, body extent -2.26,-2.01 2.26,2.01, height 3.81
BGA216_0R8_13X13 [mil] "BGA216_0R8_13X13"
  round 16 smd mask+2: A1(220.47,-220.47) A2(188.98,-220.47) A3(157.48,-220.47) A4(125.98,-220.47) A5(94.49,-220.47) A6(62.99,-220.47) A7(31.5,-220.47) A8(0,-220.47) A9(-31.5,-220.47) A10(-62.99,-220.47) A11(-94.49,-220.47) A12(-125.98,-220.47) A13(-157.48,-220.47) A14(-188.98,-220.47) A15(-220.47,-220.47) B1(220.47,-188.98) B2(188.98,-188.98) B3(157.48,-188.98) B4(125.98,-188.98) B5(94.49,-188.98) B6(62.99,-188.98) B7(31.5,-188.98) B8(0,-188.98) B9(-31.5,-188.98) B10(-62.99,-188.98) B11(-94.49,-188.98) B12(-125.98,-188.98) B13(-157.48,-188.98) B14(-188.98,-188.98) B15(-220.47,-188.98) C1(220.47,-157.48) C2(188.98,-157.48) C3(157.48,-157.48) C4(125.98,-157.48) C5(94.49,-157.48) C6(62.99,-157.48) C7(31.5,-157.48) C8(0,-157.48) C9(-31.5,-157.48) C10(-62.99,-157.48) C11(-94.49,-157.48) C12(-125.98,-157.48) C13(-157.48,-157.48) C14(-188.98,-157.48) C15(-220.47,-157.48) D1(220.47,-125.98) D2(188.98,-125.98) D3(157.48,-125.98) D4(125.98,-125.98) D5(94.49,-125.98) D6(62.99,-125.98) D7(31.5,-125.98) D8(0,-125.98) D9(-31.5,-125.98) D10(-62.99,-125.98) D11(-94.49,-125.98) D12(-125.98,-125.98) D13(-157.48,-125.98) D14(-188.98,-125.98) D15(-220.47,-125.98) E1(220.47,-94.49) E2(188.98,-94.49) E3(157.48,-94.49) E4(125.98,-94.49) E5(94.49,-94.49) E6(62.99,-94.49) E7(31.5,-94.49) E8(0,-94.49) E9(-31.5,-94.49) E10(-62.99,-94.49) E11(-94.49,-94.49) E12(-125.98,-94.49) E13(-157.48,-94.49) E14(-188.98,-94.49) E15(-220.47,-94.49) F1(220.47,-62.99) F2(188.98,-62.99) F3(157.48,-62.99) F4(125.98,-62.99) F5(94.49,-62.99) F6(62.99,-62.99) F7(31.5,-62.99) F8(0,-62.99) F9(-31.5,-62.99) F10(-62.99,-62.99) F11(-94.49,-62.99) F12(-125.98,-62.99) F13(-157.48,-62.99) F14(-188.98,-62.99) F15(-220.47,-62.99) G1(220.47,-31.5) G2(188.98,-31.5) G3(157.48,-31.5) G4(125.98,-31.5) G5(94.49,-31.5) G6(62.99,-31.5) G10(-62.99,-31.5) G11(-94.49,-31.5) G12(-125.98,-31.5) G13(-157.48,-31.5) G14(-188.98,-31.5) G15(-220.47,-31.5) H1(220.47,0) H2(188.98,0) H3(157.48,0) H4(125.98,0) H5(94.49,0) H6(62.99,0) H10(-62.99,0) H11(-94.49,0) H12(-125.98,0) H13(-157.48,0) H14(-188.98,0) H15(-220.47,0) J1(220.47,31.5) J2(188.98,31.5) J3(157.48,31.5) J4(125.98,31.5) J5(94.49,31.5) J6(62.99,31.5) J10(-62.99,31.5) J11(-94.49,31.5) J12(-125.98,31.5) J13(-157.48,31.5) J14(-188.98,31.5) J15(-220.47,31.5) K1(220.47,62.99) K2(188.98,62.99) K3(157.48,62.99) K4(125.98,62.99) K5(94.49,62.99) K6(62.99,62.99) K7(31.5,62.99) K8(0,62.99) K9(-31.5,62.99) K10(-62.99,62.99) K11(-94.49,62.99) K12(-125.98,62.99) K13(-157.48,62.99) K14(-188.98,62.99) K15(-220.47,62.99) L1(220.47,94.49) L2(188.98,94.49) L3(157.48,94.49) L4(125.98,94.49) L5(94.49,94.49) L6(62.99,94.49) L7(31.5,94.49) L8(0,94.49) L9(-31.5,94.49) L10(-62.99,94.49) L11(-94.49,94.49) L12(-125.98,94.49) L13(-157.48,94.49) L14(-188.98,94.49) L15(-220.47,94.49) M1(220.47,125.98) M2(188.98,125.98) M3(157.48,125.98) M4(125.98,125.98) M5(94.49,125.98) M6(62.99,125.98) M7(31.5,125.98) M8(0,125.98) M9(-31.5,125.98) M10(-62.99,125.98) M11(-94.49,125.98) M12(-125.98,125.98) M13(-157.48,125.98) M14(-188.98,125.98) M15(-220.47,125.98) N1(220.47,157.48) N2(188.98,157.48) N3(157.48,157.48) N4(125.98,157.48) N5(94.49,157.48) N6(62.99,157.48) N7(31.5,157.48) N8(0,157.48) N9(-31.5,157.48) N10(-62.99,157.48) N11(-94.49,157.48) N12(-125.98,157.48) N13(-157.48,157.48) N14(-188.98,157.48) N15(-220.47,157.48) P1(220.47,188.98) P2(188.98,188.98) P3(157.48,188.98) P4(125.98,188.98) P5(94.49,188.98) P6(62.99,188.98) P7(31.5,188.98) P8(0,188.98) P9(-31.5,188.98) P10(-62.99,188.98) P11(-94.49,188.98) P12(-125.98,188.98) P13(-157.48,188.98) P14(-188.98,188.98) P15(-220.47,188.98) R1(220.47,220.47) R2(188.98,220.47) R3(157.48,220.47) R4(125.98,220.47) R5(94.49,220.47) R6(62.99,220.47) R7(31.5,220.47) R8(0,220.47) R9(-31.5,220.47) R10(-62.99,220.47) R11(-94.49,220.47) R12(-125.98,220.47) R13(-157.48,220.47) R14(-188.98,220.47) R15(-220.47,220.47)
  silkscreen extent -335,-335 335,335, body extent -256,-256 256,256, height 150
DBS101-107G#1 [mil] "DBS101-107G"
  rect 48x66 smd: 1(-98.43,-171.26) 2(98.43,-171.26) 3(98.43,171.26) 4(-98.43,171.26)
  silkscreen extent -167,-183 168,126, body extent -167,-205 167,210, height 150
DBS101-107G#2 [mil] "DBS101-107G"
  rect 48x66 smd: 1(98.43,171.26) 2(-98.43,171.26) 3(-98.43,-171.26) 4(98.43,-171.26)
  silkscreen extent -168,-126 167,183, body extent -167,-210 167,205, height 150
DFN6_0R95_3X3 [mil] "DFN6_0R95_3X3"
  rect 18x28 smd: 1(-37.4,-56.52) 2(0,-56.52) 3(37.4,-56.52) 4(37.4,56.52) 5(0,56.52) 6(-37.4,56.52)
  rect 99x69 smd: 7(0,0)
  silkscreen extent -80,-78 60,60, body extent -59,-72 59,72, height 150
DFN8_1R27_6X8_TP4R8X5R16 [mil] "DFN8_1R27_6X8_TP4R8X5R16"
  rect 20x32 smd: 1(75,153.54) 2(25,153.54) 3(-25,153.54) 4(-75,153.54) 5(-75,-153.54) 6(-25,-153.54) 7(25,-153.54) 8(75,-153.54)
  rect 189x203 smd: 9(0,0)
  silkscreen extent -118,-157 118,202, body extent -119,-173 120,173, height 150
FBGA90_0R8_8X13 [mil] "FBGA90_0R8_8X13"
  round 16 smd mask+2: A1(125.98,-220.47) A2(94.49,-220.47) A3(62.99,-220.47) A7(-62.99,-220.47) A8(-94.49,-220.47) A9(-125.98,-220.47) B1(125.98,-188.98) B2(94.49,-188.98) B3(62.99,-188.98) B7(-62.99,-188.98) B8(-94.49,-188.98) B9(-125.98,-188.98) C1(125.98,-157.48) C2(94.49,-157.48) C3(62.99,-157.48) C7(-62.99,-157.48) C8(-94.49,-157.48) C9(-125.98,-157.48) D1(125.98,-125.98) D2(94.49,-125.98) D3(62.99,-125.98) D7(-62.99,-125.98) D8(-94.49,-125.98) D9(-125.98,-125.98) E1(125.98,-94.49) E2(94.49,-94.49) E3(62.99,-94.49) E7(-62.99,-94.49) E8(-94.49,-94.49) E9(-125.98,-94.49) F1(125.98,-62.99) F2(94.49,-62.99) F3(62.99,-62.99) F7(-62.99,-62.99) F8(-94.49,-62.99) F9(-125.98,-62.99) G1(125.98,-31.5) G2(94.49,-31.5) G3(62.99,-31.5) G7(-62.99,-31.5) G8(-94.49,-31.5) G9(-125.98,-31.5) H1(125.98,0) H2(94.49,0) H3(62.99,0) H7(-62.99,0) H8(-94.49,0) H9(-125.98,0) J1(125.98,31.5) J2(94.49,31.5) J3(62.99,31.5) J7(-62.99,31.5) J8(-94.49,31.5) J9(-125.98,31.5) K1(125.98,62.99) K2(94.49,62.99) K3(62.99,62.99) K7(-62.99,62.99) K8(-94.49,62.99) K9(-125.98,62.99) L1(125.98,94.49) L2(94.49,94.49) L3(62.99,94.49) L7(-62.99,94.49) L8(-94.49,94.49) L9(-125.98,94.49) M1(125.98,125.98) M2(94.49,125.98) M3(62.99,125.98) M7(-62.99,125.98) M8(-94.49,125.98) M9(-125.98,125.98) N1(125.98,157.48) N2(94.49,157.48) N3(62.99,157.48) N7(-62.99,157.48) N8(-94.49,157.48) N9(-125.98,157.48) P1(125.98,188.98) P2(94.49,188.98) P3(62.99,188.98) P7(-62.99,188.98) P8(-94.49,188.98) P9(-125.98,188.98) R1(125.98,220.47) R2(94.49,220.47) R3(62.99,220.47) R7(-62.99,220.47) R8(-94.49,220.47) R9(-125.98,220.47)
  silkscreen extent -236,-335 236,335, body extent -155,-256 155,256, height 150
HDR_1X2_2R54_RA_11R35 [mil] "HDR_1X2_2R54_RA_11R35"
  rect 60x60 hole 40: 1(0,0)
  round 60 hole 40: 2(-100,0)
  silkscreen extent -200,-504 100,22, body extent -200,-505 100,30, height 150
HDR_1X4_2R54 [mil] "HDR_1X4_2R54"
  rect 52x52 / inner round 52 / far side rect 52x52 hole 36: 1(0,0)
  round 52 hole 36: 2(100,0) 3(200,0) 4(300,0)
  silkscreen extent -70,-70 355,55, body extent -138,-138 438,138, height 150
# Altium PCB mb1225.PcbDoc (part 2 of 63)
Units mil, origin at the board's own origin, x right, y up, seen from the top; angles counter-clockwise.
Board outline 5000 x 3464.56 mil, 6 copper layers (TOP, L2_GND, L3_VCC, L4_SIG, L5_GND, BOTTOM), stack 62.2 mil thick; 452 components, 378 nets, 1968 pads, 949 vias.

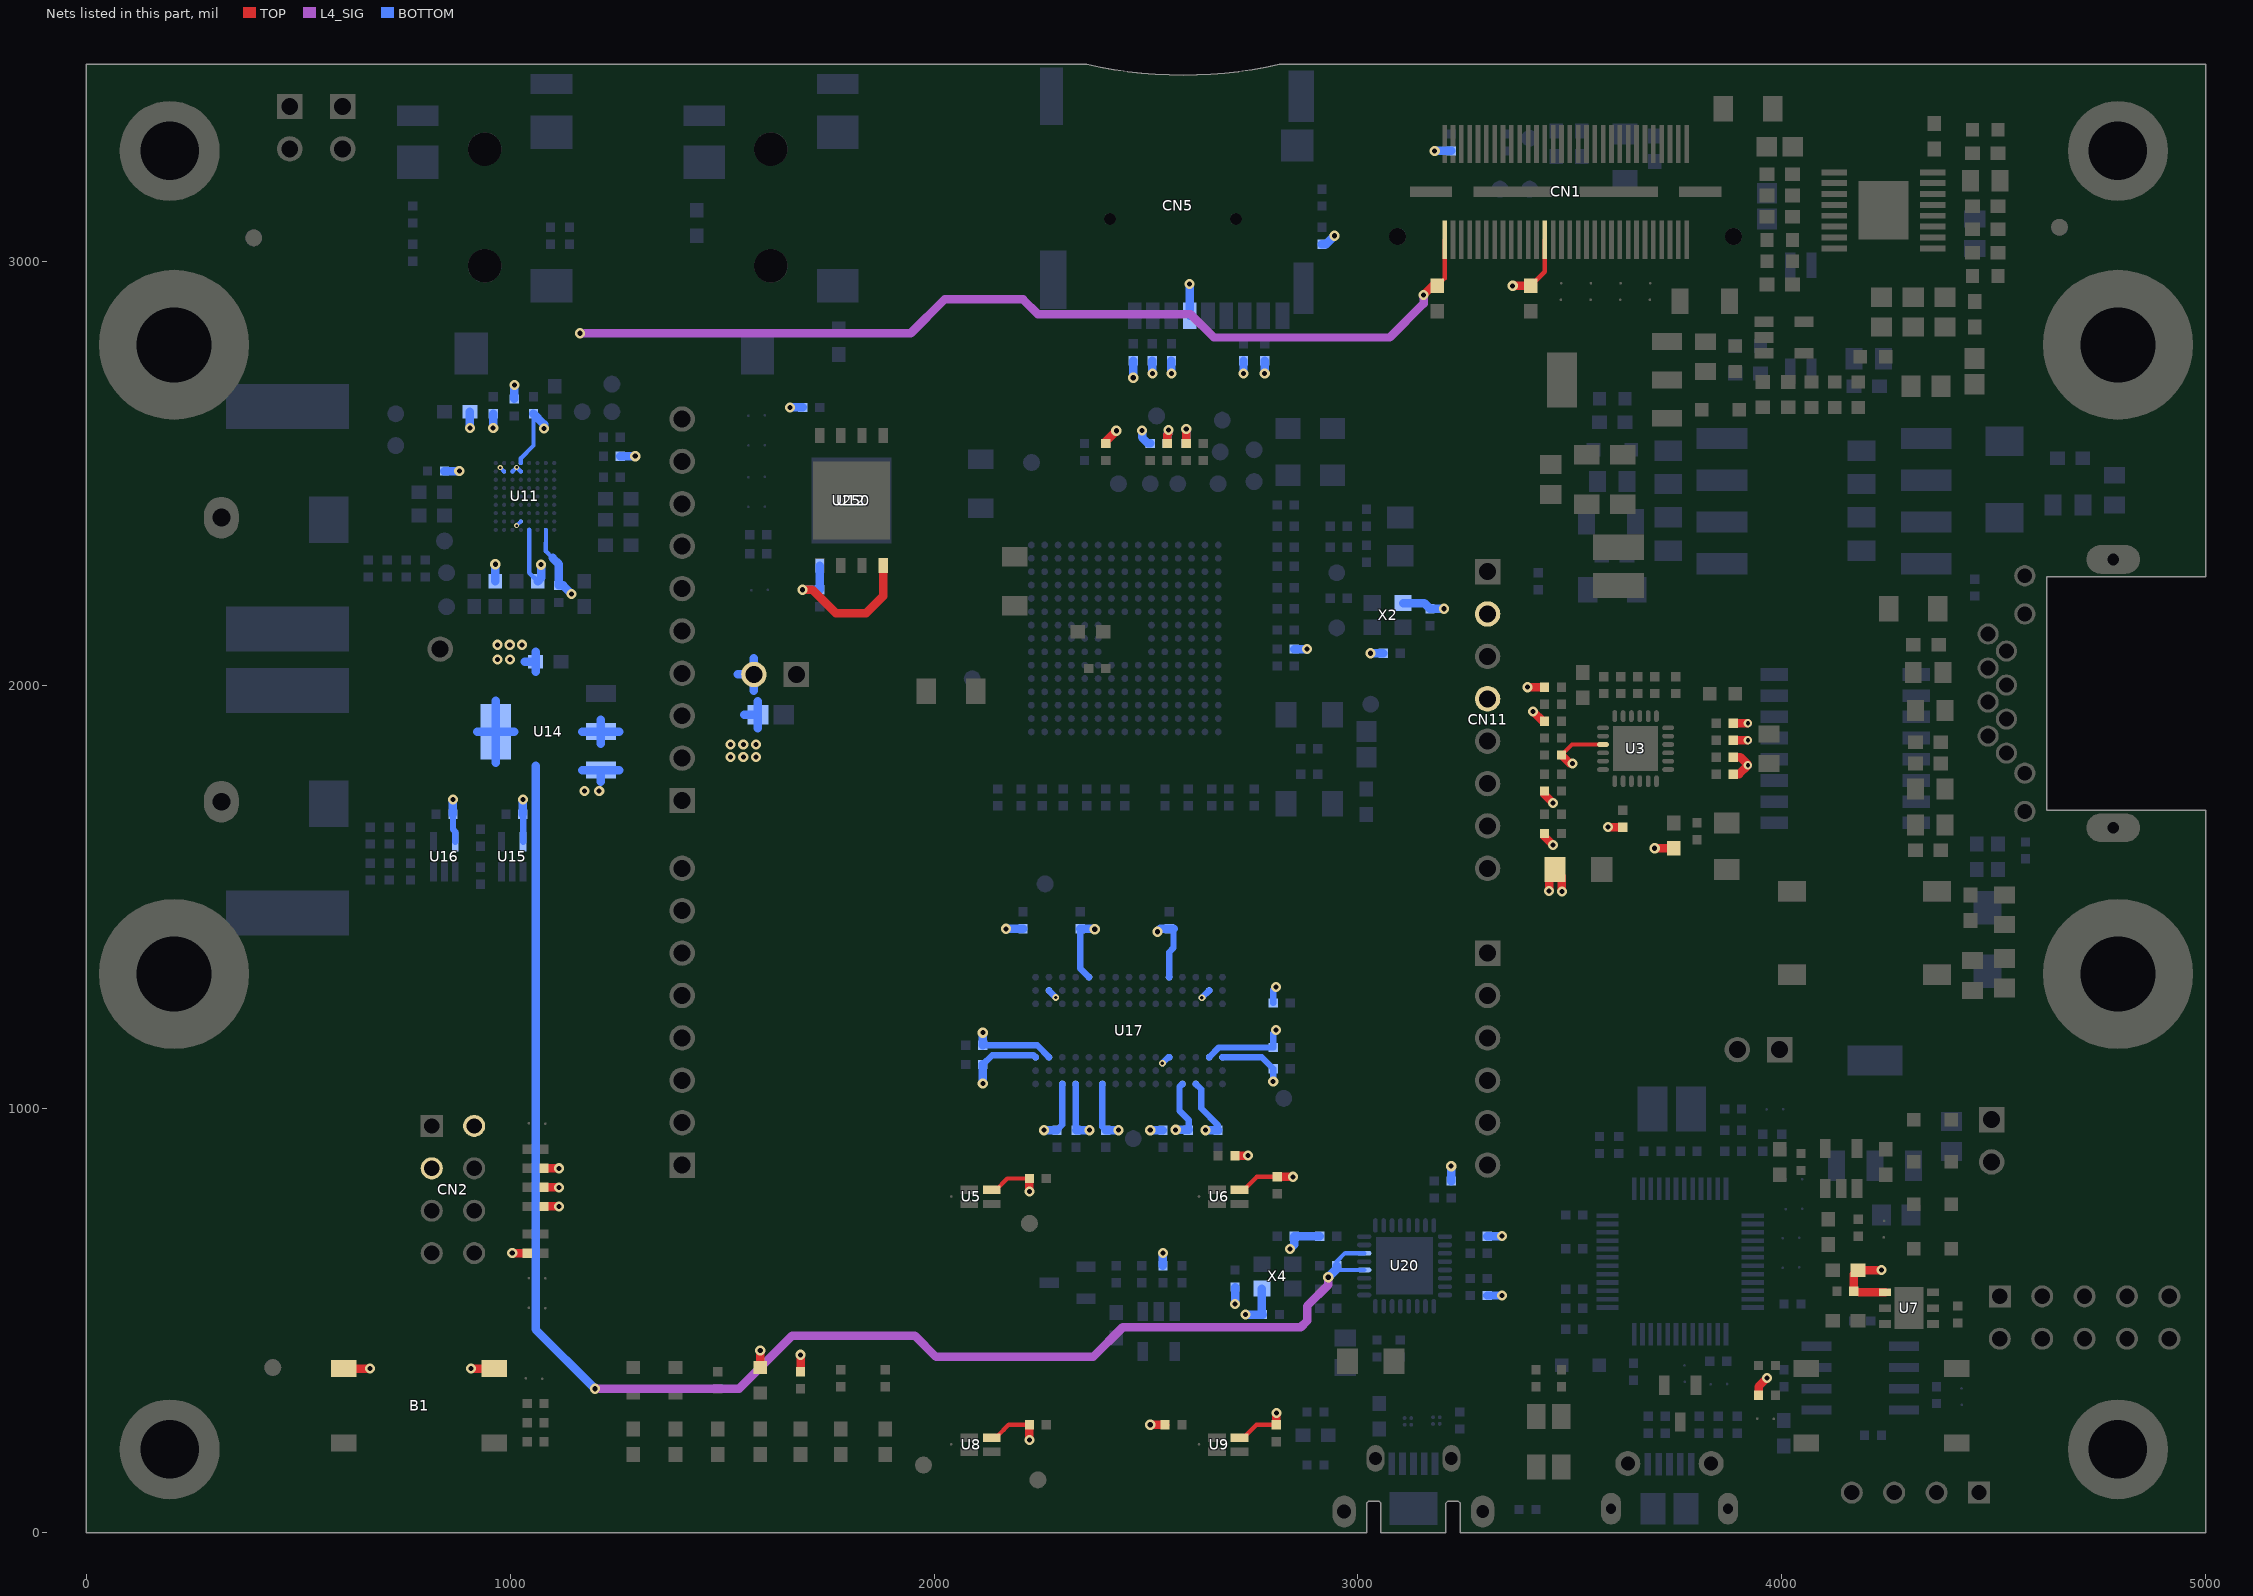
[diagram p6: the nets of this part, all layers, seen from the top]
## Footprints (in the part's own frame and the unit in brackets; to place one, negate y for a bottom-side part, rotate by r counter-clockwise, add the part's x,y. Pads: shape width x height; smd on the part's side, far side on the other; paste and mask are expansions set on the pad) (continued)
HDR_1X6_2R54_W [mil] "HDR_1X6_2R54_W"
  rect 60x60 / inner round 60 / far side rect 60x60 hole 40: 1(0,0)
  round 60 hole 40: 2(-100,0) 3(-200,0) 4(-300,0) 5(-400,0) 6(-500,0)
  silkscreen extent -550,-50 65,65, body extent -550,-50 50,50, height 150
HDR_1X8_2R54_W [mil] "HDR_1X8_2R54_W"
  rect 60x60 / inner round 60 / far side rect 60x60 hole 40: 1(0,0)
  round 60 hole 40: 2(-100,0) 3(-200,0) 4(-300,0) 5(-400,0) 6(-500,0) 7(-600,0) 8(-700,0)
  silkscreen extent -750,-50 65,65, body extent -750,-50 50,50, height 150
HDR_1X10_2R54_W [mil] "HDR_1X10_2R54_W"
  rect 60x60 / inner round 60 / far side rect 60x60 hole 40: 1(0,0)
  round 60 hole 40: 2(-100,0) 3(-200,0) 4(-300,0) 5(-400,0) 6(-500,0) 7(-600,0) 8(-700,0) 9(-800,0) 10(-900,0)
  silkscreen extent -950,-50 65,65, body extent -950,-50 50,50, height 150
HDR_2X4_2R54 [mil] "HDR_2X4_2R54"
  rect 52x52 / inner round 52 / far side rect 52x52 hole 36: 1(0,0)
  round 52 hole 36: 2(0,100) 3(100,0) 4(100,100) 5(200,0) 6(200,100) 7(300,0) 8(300,100)
  silkscreen extent -65,-70 350,155, body extent -157,-157 457,257, height 150
HDR_2X5_2R54 [mil] "HDR_2X5_2R54"
  rect 52x52 / inner round 52 / far side rect 52x52 hole 36: 1(0,0)
  round 52 hole 36: 2(0,-100) 3(-100,0) 4(-100,-100) 5(-200,0) 6(-200,-100) 7(-300,0) 8(-300,-100) 9(-400,0) 10(-400,-100)
  silkscreen extent -450,-155 65,70, body extent -445,-150 45,50, height 150
HOLE_C6D3R5 [mil] "HOLE_C6D3R5"
  round 236 hole 138: 1(0,0)
  body extent -123,-123 123,123, height 150
HOLE_C9D4R5 [mil] "HOLE_C9D4R5"
  round 354 hole 177: 1(0,0)
  body extent -185,-185 185,185, height 150
HOLE_C9D4R5-1 [mil] "HOLE_C9D4R5"
  round 354 / inner round 0 / far side round 0 hole 177 mask+4: 1(0,0)
  BOTTOM region: 103.81,-143.36 24.42,-175.31 -60.68,-166.27 -131.6,-118.37 -171.75,-42.79 -171.75,42.79 -131.6,118.37 -60.68,166.27 24.42,175.31 103.81,143.36 103.81,143.36 104,143.36
  body extent -185,-185 185,185, height 150
JP2_SMD [mil] "JP2_SMD"
  round 6 smd: 1(-23.01,-0.33) 2(15.83,-1.19)
  TOP region: -34.18,2.96 -12.96,24.18 -1.82,13.04 -15.13,-0.26 -2.09,-13.3 -12.7,-23.91 -33.91,-2.7 -31.22,0 -34.18,2.96
  TOP region: 12.7,22.91 33.91,1.7 32.21,0 33.91,-1.7 12.7,-22.91 2.09,-12.3 4.5,-9.89 -5.39,0 4.5,9.89 2.09,12.3 12.7,22.91
  silkscreen extent -40,-30 40,30, body extent -35,-24 35,24, height 150
LED2_3528 [mil] "LED2_3528"
  rect 44x59 smd: 1(-29.53,-59.06) 2(-29.53,59.06) 3(29.53,59.06) 4(29.53,-59.06)
  silkscreen extent -109,-70 65,69, body extent -55,-90 55,90, height 150
LQFP48_0R5_9X9 [mil] "LQFP48_0R5_9X9"
  rect 53x11 smd mask+2: 1(171.26,-108.27) 2(171.26,-88.58) 3(171.26,-68.9) 4(171.26,-49.21) 5(171.26,-29.53) 6(171.26,-9.84) 7(171.26,9.84) 8(171.26,29.53) 9(171.26,49.21) 10(171.26,68.9) 11(171.26,88.58) 12(171.26,108.27) 25(-171.26,108.27) 26(-171.26,88.58) 27(-171.26,68.9) 28(-171.26,49.21) 29(-171.26,29.53) 30(-171.26,9.84) 31(-171.26,-9.84) 32(-171.26,-29.53) 33(-171.26,-49.21) 34(-171.26,-68.9) 35(-171.26,-88.58) 36(-171.26,-108.27)
  rect 11x53 smd mask+2: 13(108.27,171.26) 14(88.58,171.26) 15(68.9,171.26) 16(49.21,171.26) 17(29.53,171.26) 18(9.84,171.26) 19(-9.84,171.26) 20(-29.53,171.26) 21(-49.21,171.26) 22(-68.9,171.26) 23(-88.58,171.26) 24(-108.27,171.26) 37(-108.27,-171.26) 38(-88.58,-171.26) 39(-68.9,-171.26) 40(-49.21,-171.26) 41(-29.53,-171.26) 42(-9.84,-171.26) 43(9.84,-171.26) 44(29.53,-171.26) 45(49.21,-171.26) 46(68.9,-171.26) 47(88.58,-171.26) 48(108.27,-171.26)
  silkscreen extent -220,-220 240,220, body extent -199,-199 199,199, height 150
LSM2_3R2X2R8_H2 [mil] "LSM2_3R2X2R8_H2"
  rect 60x120 smd: 1(-45.08,0) 2(45.08,0)
  silkscreen extent -90,-75 90,75, body extent -80,-65 80,65, height 150
MICRO_USB_B_105017 [mil] "MICRO_USB_B_105017"
  rect 16x53 smd: 1(51.18,-2.95) 2(25.59,-2.95) 3(0,-2.95) 4(-25.59,-2.95) 5(-51.18,-2.95)
  oval 47x75 hole 24 slot 51 at 90 deg: 6(137.8,102.36) 7(-137.8,102.36)
  round 59 hole 33: 8(98.43,-3.94) 9(-98.43,-3.94)
  rect 59x75 smd: 10(39.37,102.36) 11(-39.37,102.36)
  TOP region: 161.42,84.65 161.42,120.08 161.42,120.08 161.34,121.8 161.12,123.5 160.75,125.17 160.23,126.81 159.57,128.4 158.78,129.92 157.86,131.37 156.81,132.73 155.65,133.99 154.38,135.15 153.02,136.2 151.57,137.12 150.05,137.91 148.46,138.57 146.97,139.05 90.55,139.05 90.55,64.96 141.73,64.96 141.73,64.96 143.45,65.03 145.15,65.26 146.83,65.63 148.46,66.15 150.05,66.8 151.58,67.6 153.02,68.52 154.39,69.57 155.65,70.73 156.81,71.99 157.86,73.36 158.78,74.8 159.58,76.33 160.23,77.92 160.75,79.55 161.12,81.23 161.35,82.93 161.42,84.65
  TOP region: -161.42,120.08 -161.42,84.65 -161.42,84.65 -161.35,82.93 -161.12,81.23 -160.75,79.55 -160.23,77.92 -159.58,76.33 -158.78,74.8 -157.86,73.36 -156.81,71.99 -155.65,70.73 -154.39,69.57 -153.02,68.52 -151.58,67.6 -150.05,66.8 -148.46,66.15 -146.83,65.63 -145.15,65.26 -143.45,65.03 -141.73,64.96 -90.55,64.96 -90.55,139.25 -146.19,139.25 -146.19,139.25 -147.84,138.79 -149.45,138.19 -151,137.45 -152.48,136.57 -153.87,135.57 -155.18,134.46 -156.38,133.23 -157.47,131.9 -158.44,130.49 -159.29,128.99 -160,127.43 -160.57,125.81 -160.99,124.15 -161.28,122.45 -161.41,120.74 -161.42,120.08
  BOTTOM region: -161.42,120.08 -161.42,84.65 -161.42,84.65 -161.35,82.93 -161.12,81.23 -160.75,79.55 -160.23,77.92 -159.58,76.33 -158.78,74.8 -157.86,73.36 -156.81,71.99 -155.65,70.73 -154.39,69.57 -153.02,68.52 -151.58,67.6 -150.05,66.8 -148.46,66.15 -146.83,65.63 -145.15,65.26 -143.45,65.03 -141.73,64.96 -90.55,64.96 -90.55,139.25 -146.19,139.25 -146.19,139.25 -147.84,138.79 -149.45,138.19 -151,137.45 -152.48,136.57 -153.87,135.57 -155.18,134.46 -156.38,133.23 -157.47,131.9 -158.44,130.49 -159.29,128.99 -160,127.43 -160.57,125.81 -160.99,124.15 -161.28,122.45 -161.41,120.74 -161.42,120.08
  BOTTOM region: 161.42,84.65 161.42,120.08 161.42,120.08 161.34,121.8 161.12,123.5 160.75,125.17 160.23,126.81 159.57,128.4 158.78,129.92 157.86,131.37 156.81,132.73 155.65,133.99 154.38,135.15 153.02,136.2 151.57,137.12 150.05,137.91 148.46,138.57 146.97,139.05 90.55,139.05 90.55,64.96 141.73,64.96 141.73,64.96 143.45,65.03 145.15,65.26 146.83,65.63 148.46,66.15 150.05,66.8 151.58,67.6 153.02,68.52 154.39,69.57 155.65,70.73 156.81,71.99 157.86,73.36 158.78,74.8 159.58,76.33 160.23,77.92 160.75,79.55 161.12,81.23 161.35,82.93 161.42,84.65
  silkscreen extent -148,-56 148,199, body extent -165,-35 165,200, height 150
MOLEX_47590001 [mil] "MOLEX_47590001"
  rect 16x53 smd: 1(-51.18,0) 2(-25.59,0) 3(0,0) 4(25.59,0) 5(51.18,0)
  oval 42x63 hole 30 slot 33 at 90 deg: 6(-89.57,-12.8) 7(89.57,-12.8)
  oval 55x75 hole 30 slot 59 at 90 deg mask+2: 8(163.39,112.4)
  oval 55x75 hole 33 slot 59 at 90 deg mask+2: 9(-163.39,112.4)
  rect 114x79 smd: 10(0,105.31)
  silkscreen extent -161,-57 161,216, body extent -190,-45 190,215, height 150
MP34DT01TR [mil] "MP34DT01TR"
  rect 20x42 smd: 1(-16.73,26.57) 2(-16.73,-26.57) 3(16.73,-26.57) 4(16.73,26.57)
  round 6 smd: 5(-1,-69)
  TOP region: 41.11,45.28 41.11,-45.28 54.89,-45.28 54.89,45.28 41.11,45.28
  TOP region: -54.89,45.28 -54.89,-45.28 -41.11,-45.28 -41.11,45.28 -54.89,45.28
  TOP region: -25.59,-61.11 -25.59,-74.89 25.59,-74.89 25.59,-61.11 -25.59,-61.11
  TOP region: -25.59,74.89 -25.59,61.11 25.59,61.11 25.59,74.89 -25.59,74.89
  silkscreen extent -70,-80 60,90, body extent -58,-79 59,79, height 150
MSD_PJS008_ [mil] "MSD_PJS008_"
  rect 32x63 smd: 1(-58.07,-228.35) 2(-101.38,-228.35) 3(-144.69,-228.35) 4(-187.99,-228.35) 5(-231.3,-228.35) 6(-274.61,-228.35) 7(-317.91,-228.35) 8(-361.22,-228.35)
  rect 33x63 smd: 9(-406.5,-228.35)
  rect 77x75 smd: 10(-441.93,173.23)
  rect 60x121 smd: 11(-450.79,289.37)
  rect 55x135 smd: 12(137.93,289.65)
  rect 63x138 smd: 13(133.86,-143.7)
  rect 47x122 smd: 14(-456.69,-163.39)
  round 28 hole 28: " "(-297.24,0) " "(0,0)
  Multi-Layer keep-out circle w1: c-297.24,0 r29
  Multi-Layer keep-out circle w1: c0,0 r29
  silkscreen extent -450,-262 150,365, body extent -485,-265 170,365, height 150
OSC_4SM_2R5X2 [mil] "OSC_4SM_2R5X2"
  rect 41x37 smd: 1(36.42,28.54) 2(-36.42,28.54) 3(-36.42,-28.54) 4(36.42,-28.54)
  silkscreen extent -70,-60 95,80, body extent -60,-50 60,50, height 150
PB10 [mil] "PB10"
  rect 60x40 smd paste+15: 1(-177.17,-87.5) 2(-177.17,87.5) 3(177.17,87.5) 4(177.17,-87.5)
  silkscreen extent -125,-125 125,125, body extent -207,-108 207,108, height 150
PC_4SM_1R27_2R5X6R8 [mil] "PC_4SM_1R27_2R5X6R8"
  rect 24x60 smd: 1(25,125.08) 2(-25,125.08) 3(-25,-125.08) 4(25,-125.08)
  silkscreen extent -51,-83 77,143, body extent -51,-157 51,157, height 150
PHONE_JACK_JBB0819100002 [mil] "PHONE_JACK_JBB0819100002"
  oval 98x82 hole 42 slot 58 at 0 deg: 1(0,168.5)
  rect 106x290 smd: 2(262.28,12.6) 3(-262.28,12.6)
  rect 109x93 smd: 4(5,-85.16)
  silkscreen extent -185,-118 190,484, body extent -320,-140 320,485, height 150
PJ3028B [mil] "PJ3028B"
  rect 48x98 smd: 2(153.54,157.48) 7(78.74,-157.48)
  rect 79x98 smd: 3(39.37,157.48) 4(-31.5,-157.48) 6(-322.83,157.48)
  rect 98x79 smd: 5(-482.28,-31.5)
  round 79 hole 79: " "(-275.59,0) " "(0,0)
  Multi-Layer keep-out circle w1: c0,0 r54.33
  Multi-Layer keep-out circle w1: c-275.59,0 r54.33
  silkscreen extent -433,-118 236,118, body extent -532,-210 235,210, height 150
QFN24_0R5_4X4 [mil] "QFN24_0R5_4X4"
  oval 28x11 smd mask+2: 1(-76.77,49.21) 2(-76.77,29.53) 3(-76.77,9.84) 4(-76.77,-9.84) 5(-76.77,-29.53) 6(-76.77,-49.21) 13(76.77,-49.21) 14(76.77,-29.53) 15(76.77,-9.84) 16(76.77,9.84) 17(76.77,29.53) 18(76.77,49.21)
  oval 11x28 smd mask+2: 7(-49.21,-76.77) 8(-29.53,-76.77) 9(-9.84,-76.77) 10(9.84,-76.77) 11(29.53,-76.77) 12(49.21,-76.77) 19(49.21,76.77) 20(29.53,76.77) 21(9.84,76.77) 22(-9.84,76.77) 23(-29.53,76.77) 24(-49.21,76.77)
  rect 106x106 smd: 25(0,0)
  silkscreen extent -110,-85 85,88, body extent -95,-95 95,95, height 150
QFN32_0R5_5X5 [mil] "QFN32_0R5_5X5"
  oval 34x11 smd mask+2: 1(95.28,-68.9) 2(95.28,-49.21) 3(95.28,-29.53) 4(95.28,-9.84) 5(95.28,9.84) 6(95.28,29.53) 7(95.28,49.21) 8(95.28,68.9) 17(-95.28,68.9) 18(-95.28,49.21) 19(-95.28,29.53) 20(-95.28,9.84) 21(-95.28,-9.84) 22(-95.28,-29.53) 23(-95.28,-49.21) 24(-95.28,-68.9)
  oval 11x34 smd mask+2: 9(68.9,95.28) 10(49.21,95.28) 11(29.53,95.28) 12(9.84,95.28) 13(-9.84,95.28) 14(-29.53,95.28) 15(-49.21,95.28) 16(-68.9,95.28) 25(-68.9,-95.28) 26(-49.21,-95.28) 27(-29.53,-95.28) 28(-9.84,-95.28) 29(9.84,-95.28) 30(29.53,-95.28) 31(49.21,-95.28) 32(68.9,-95.28)
  rect 135x135 smd mask+2: 33(0,0)
  silkscreen extent -105,-105 148,105, body extent -115,-115 115,115, height 150
QSH-030-01-F-D-A [mil] "QSH-030-01-F-D-A"
  rect 11x90 smd mask+2: 1(-285.43,-112.99) 2(-285.43,112.99) 3(-265.75,-112.99) 4(-265.75,112.99) 5(-246.06,-112.99) 6(-246.06,112.99) 7(-226.38,-112.99) 8(-226.38,112.99) 9(-206.69,-112.99) 10(-206.69,112.99) 11(-187.01,-112.99) 12(-187.01,112.99) 13(-167.32,-112.99) 14(-167.32,112.99) 15(-147.64,-112.99) 16(-147.64,112.99) 17(-127.95,-112.99) 18(-127.95,112.99) 19(-108.27,-112.99) 20(-108.27,112.99) 21(-88.58,-112.99) 22(-88.58,112.99) 23(-68.9,-112.99) 24(-68.9,112.99) 25(-49.21,-112.99) 26(-49.21,112.99) 27(-29.53,-112.99) 28(-29.53,112.99) 29(-9.84,-112.99) 30(-9.84,112.99) 31(9.84,-112.99) 32(9.84,112.99) 33(29.53,-112.99) 34(29.53,112.99) 35(49.21,-112.99) 36(49.21,112.99) 37(68.9,-112.99) 38(68.9,112.99) 39(88.58,-112.99) 40(88.58,112.99) 41(108.27,-112.99) 42(108.27,112.99) 43(127.95,-112.99) 44(127.95,112.99) 45(147.64,-112.99) 46(147.64,112.99) 47(167.32,-112.99) 48(167.32,112.99) 49(187.01,-112.99) 50(187.01,112.99) 51(206.69,-112.99) 52(206.69,112.99) 53(226.38,-112.99) 54(226.38,112.99) 55(246.06,-112.99) 56(246.06,112.99) 57(265.75,-112.99) 58(265.75,112.99) 59(285.43,-112.99) 60(285.43,112.99)
  rect 100x25 smd mask+3: 61(-317.52,0) 64(317.52,0)
  rect 185x25 smd mask+3: 62(-125,0) 63(125,0)
  round 40 hole 40: " "(-396.26,105.12) " "(396.26,105.12)
  Multi-Layer keep-out circle w1: c-396.26,105.12 r35.43
  Multi-Layer keep-out circle w1: c396.26,105.12 r35.43
  silkscreen extent -420,-216 420,185, body extent -420,-160 420,160, height 150
RJ45_LED_KRJ-CB4R2GYZNL_EM [mil] "RJ45_LED_KRJ-CB4R2GYZNL_EM"
  round 50 hole 35: 1(-140.55,21.65) 2(-100.39,-21.65) 3(-60.24,21.65) 4(-20.08,-21.65) 5(20.08,21.65) 6(60.24,-21.65) 7(100.39,21.65) 8(140.55,-21.65) 9(-277.95,64.96) 10(-187.8,64.96) 11(187.8,64.96) 12(277.95,64.96)
  oval 68x127 hole 28 slot 87 at 90 deg: 13(316.54,273.62) 14(-316.54,273.62)
  silkscreen extent -319,-90 319,589, body extent -355,-55 355,590, height 150
SIP2 [mil] "SIP2"
  rect 60x60 / inner round 60 / far side rect 60x60 hole 40: 1(0,0)
  round 60 hole 40: 2(-100,0)
  silkscreen extent -150,-50 75,50, body extent -130,-30 30,30, height 150
SMA [mil] "SMA"
  rect 79x66 smd: 1(74.8,0) 2(-74.8,0)
  silkscreen extent -141,-60 130,60, body extent -130,-60 130,60, height 150
SMB [mil] "SMB"
  rect 70x90 smd: 1(-90.55,0) 2(90.55,0)
  silkscreen extent -105,-75 105,75, body extent -125,-70 125,70, height 150
SOD-323#1 [mil] "SOD-323"
  rect 32x32 smd: 1(-44.29,0) 2(44.29,0)
  silkscreen extent -65,-35 50,55, body extent -65,-25 65,27, height 150
SOD-323#2 [mil] "SOD-323"
  rect 32x32 smd: 1(44.29,0) 2(-44.29,0)
  silkscreen extent -50,-45 90,35, body extent -65,-27 65,25, height 150
SOIC8_1R27_4R9X6 [mil] "SOIC8_1R27_4R9X6"
  rect 22x70 smd: 1(75,103.3) 2(25,103.3) 3(-25,103.3) 4(-75,103.3) 5(-75,-103.3) 6(-25,-103.3) 7(25,-103.3) 8(75,-103.3)
  silkscreen extent -100,-55 123,140, body extent -96,-141 96,141, height 150
SON8_1R27_6X8 [mil] "SON8_1R27_6X8"
  rect 22x36 smd: 1(-75,-153.54) 2(-25,-153.54) 3(25,-153.54) 4(75,-153.54) 5(75,153.54) 6(25,153.54) 7(-25,153.54) 8(-75,153.54)
  rect 181x185 smd: 9(0,0)
  silkscreen extent -118,-210 118,157, body extent -120,-175 119,174, height 150
SOT23-5#1 [mil] "SOT23-5"
  rect 25x45 smd: 1(-37.4,-47.24) 2(0,-47.24) 3(37.4,-47.24) 4(37.4,47.24) 5(-37.4,47.24)
  silkscreen extent -90,-73 65,35, body extent -57,-70 57,70, height 150
SOT23-5#2 [mil] "SOT23-5"
  rect 25x45 smd: 1(37.4,47.24) 2(0,47.24) 3(-37.4,47.24) 4(-37.4,-47.24) 5(37.4,-47.24)
  silkscreen extent -65,-35 65,95, body extent -57,-70 57,70, height 150
SOT-23#1 [mil] "SOT-23"
  rect 25x45 smd: 1(-37.4,-43.31) 2(37.4,-43.31) 3(0,43.31)
  silkscreen extent -60,-35 60,35, body extent -60,-70 60,70, height 150
SOT-23#2 [mil] "SOT-23"
  rect 25x45 smd: 1(37.4,43.31) 2(-37.4,43.31) 3(0,-43.31)
  silkscreen extent -60,-35 60,35, body extent -60,-70 60,70, height 150
SOT-23-5L [mil] "SOT-23-5L"
  rect 25x45 smd: 1(-37.4,-47.24) 2(0,-47.24) 3(37.4,-47.24) 4(37.4,47.24) 5(-37.4,47.24)
  silkscreen extent -89,-102 65,35, body extent -57,-70 57,70, height 150
SOT-223#1 [mil] "SOT-223"
  rect 40x71 smd: 1(-90.55,-124.02) 2(0,-124.02) 3(90.55,-124.02)
  rect 130x71 smd: 4(0,124.02)
  silkscreen extent -130,-189 130,75, body extent -128,-160 128,160, height 150
SOT-223#2 [mil] "SOT-223"
  rect 40x71 smd: 1(90.55,124.02) 2(0,124.02) 3(-90.55,124.02)
  rect 130x71 smd: 4(0,-124.02)
  silkscreen extent -130,-75 130,194, body extent -128,-160 128,160, height 150
SOT-353 [mil] "SOT-353"
  rect 16x47 smd: 1(25.59,35.43) 2(0,35.43) 3(-25.59,35.43) 4(-25.59,-35.43) 5(25.59,-35.43)
  silkscreen extent -45,-70 55,80, body extent -40,-65 39,65, height 150
TAN-A#1 [mil] "TAN-A"
  rect 50x60 smd: 1(55,0) 2(-55,0)
  silkscreen extent -95,-45 105,45, body extent -85,-25 85,25, height 150
TAN-A#2 [mil] "TAN-A"
  rect 50x60 smd: 1(-55,0) 2(55,0)
  silkscreen extent -105,-45 95,45
TF_8SM_12R04X12R85 [mil] "TF_8SM_12R04X12R85"
  rect 48x66 smd: 1(118.11,227.95) 2(39.37,227.95) 3(-39.37,227.95) 4(-118.11,227.95) 5(-118.11,-227.95) 6(-39.37,-227.95) 7(39.37,-227.95) 8(118.11,-227.95)
  silkscreen extent -237,-194 237,296, body extent -235,-264 235,264, height 150
TF_10R9X13R2-12R2X14R4_CPT [mil] "TF_10R9X13R2-12R2X14R4_CPT"
  rect 50x120 smd: 1(-147.64,240.79) 2(-49.21,240.79) 3(49.21,240.79) 4(147.64,240.79) 5(147.64,-240.79) 6(49.21,-240.79) 7(-49.21,-240.79) 8(-147.64,-240.79)
  silkscreen extent -240,-283 240,319, body extent -240,-305 240,305, height 150
TF_16SM_12R7X9R65 [mil] "TF_16SM_12R7X9R65"
  rect 30x65 smd: 1(175,167.52) 2(125,167.52) 3(75,167.52) 4(25,167.52) 5(-25,167.52) 6(-75,167.52) 7(-125,167.52) 8(-175,167.52) 9(-175,-167.52) 10(-125,-167.52) 11(-75,-167.52) 12(-25,-167.52) 13(25,-167.52) 14(75,-167.52) 15(125,-167.52) 16(175,-167.52)
  silkscreen extent -250,-120 250,240, body extent -250,-203 250,203, height 150
TP [mil] "TP"
  round 60 hole 40: 1(0,0)
  silkscreen extent -40,-40 40,40, body extent -31,-31 31,31, height 150
TP_C40 [mil] "TP_C40"
  round 40 smd paste-100: 1(0,0)
  silkscreen extent -29,-29 29,29, body extent -31,-31 31,31, height 150
TSSOP16_0R65_5X6R4_TP [mil] "TSSOP16_0R65_5X6R4_TP"
  rect 14x60 smd: 1(-89.57,-116.14) 2(-63.98,-116.14) 3(-38.39,-116.14) 4(-12.8,-116.14) 5(12.8,-116.14) 6(38.39,-116.14) 7(63.98,-116.14) 8(89.57,-116.14) 9(89.57,116.14) 10(63.98,116.14) 11(38.39,116.14) 12(12.8,116.14) 13(-12.8,116.14) 14(-38.39,116.14) 15(-63.98,116.14) 16(-89.57,116.14)
  rect 138x118 smd: 17(0,0)
  silkscreen extent -130,-135 105,70, body extent -100,-149 100,149, height 150
XTAL_2SM_3R2X1R5 [mil] "XTAL_2SM_3R2X1R5"
  rect 51x63 smd: 1(45.28,0) 2(-45.28,0)
  silkscreen extent -85,-45 85,45, body extent -72,-32 71,30, height 150
XTAL_2SM_3R2X2R5_H1 [mil] "XTAL_2SM_3R2X2R5_H1"
  rect 71x106 smd: 1(45.28,0) 2(-45.28,0)
  silkscreen extent -95,-65 95,65, body extent -84,-56 84,56, height 150

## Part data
B1: "Non-Open Push-Button 0.1A 24V", Manuf_1=wealthmetal, Manuf_2=FARNELL, Manuf_Part_1=TD0341X-G01-BLU, Manuf_Part_2=535-930
B2: "Non-Open Push-Button 0.1A 24V", Manuf_1=wealthmetal, Manuf_2=FARNELL, Manuf_Part_1=TD0341X-G01-BLA, Manuf_Part_2=535-930
C1 C2 C16 C60: library part Cap_100nF_X7R_10%_0603, "Capacitor,100nF,16V,X7R,10%,0603,YAGEO", Manuf_1=YAGEO, Manuf_Part_1=CC0603KRX7R9BB104
C3 C89: library part Cap_1nF_2KV_X7R_10%_1206, "Capacitor,1nF,2KV,X7R,10%,1206,YAGEO", Manuf_1=YAGEO, Manuf_Part_1=CC1206KKX7RDBB102
C4 C8 C26 C32 C34 C37 C39 C121 C122: library part Cap_1nF_100V_X7R_10%_0603, "Capacitor,1nF,100V,X7R,10%,0603,YAGEO", Manuf_1=YAGEO, Manuf_Part_1=CC0603KRX7R0BB102
C5 C10: library part Cap_10nF_100V_X7R_10%_0603, "Capacitor,10nF,100V,X7R,10%,0603,YAGEO", Manuf_1=YAGEO, Manuf_Part_1=CC0603KRX7R0BB103
C6 C7 C11 C12: library part Cap_100nF_50V_X7R_10%_0603, "Capacitor,100nF,50V,X7R,10%,0603,YAGEO", Manuf_1=YAGEO, Manuf_Part_1=CC0603KRX7R9BB104
C9: library part Cap_470pF_100V_X7R_10%_0603, "Capacitor,470pF,100V,X7R,10%,0603,AVX", Manuf_1=AVX, Manuf_Part_1=06031C471KAT2A
C13 C14 C15 C18: library part Cap_47uF_X5R_20%_0805, "Capacitor,47uF,10V,X5R,20%,0805,MURATA", Manuf_1=MURATA, Manuf_Part_1=GRM21BR61A476ME15K
C17: library part Cap_100pF_50V_X7R_10%_0603, "Capacitor,100pF,50V,X7R,10%,0603,AVX", Manuf_1=AVX, Manuf_Part_1=06035C101JAT4A
C19: library part Cap_22nF_50V_X7R_10%_0603, "Capacitor,22nF,50V,X7R,10%,0603,YAGEO", Manuf_1=YAGEO, Manuf_Part_1=CC0603KRX7R9BB223
C20 C70 C75: library part Cap_4.7uF_100V_X7S_20%_1206, "Capacitor,4.7uF,100V, X7S,20%,1206,AVX", Manuf_1=AVX, Manuf_Part_1=12061Z475MAT2A
C21: library part Cap_560pF_X7R_10%_0603, "Capacitor,560pF,16V,X7R,10%,0603,AVX", Manuf_1=AVX, Manuf_Part_1=0603YC561KAT2A
C22: library part Cap_27pF_100V_NPO_5%_0603, "Capacitor,27pF,100V,NPO,5%,0603,YAGEO", Manuf_1=YAGEO, Manuf_2=AVX, Manuf_Part_1=CC0603JRNPO0BN270, Manuf_Part_2=06031A270JAT2A
C23 C31 C72: library part Cap_2.2uF_X7R_10%_1206, "Capacitor,2.2uF,16V, X7R,10%,1206,YAGEO", Manuf_1=YAGEO, Manuf_2=KEMET, Manuf_Part_1=CC1206KKX7R7BB225, Manuf_Part_2=C1206C225K4RAC
C24 C66: library part Cap_1uF_25V_X5R_10%_0603, "Capacitor,1uF,25V,X5R,10%,0603,YAGEO", Manuf_1=YAGEO, Manuf_Part_1=CC0603KRX5R8BB105
C25 C74 C78 C82: library part Cap_2.2uF_X5R_10%_0603, "Capacitor,2.2uF,10V, X5R,10%,0603,YAGEO", Manuf_1=YAGEO, Manuf_2=KEMET, Manuf_Part_1=CC0603KRX5R6BB225, Manuf_Part_2=C0603C225K8PACTU
C27 C30 C33 C35 C42 C44 C45 C46 C49 C50 C53 C54 C55 C56 C57 C59 C64 C65 C71 C76 C80 C83 C86 C87 C88 C91 C96 C97 C98 C99 C102 C103 C104 C105 C106 C107 C108 C109 C110 C111 C112 C113 C114 C115 C117 C118 C123 C124 C125 C126 C127 C128 C130 C131 C132 C133 C134 C135 C136 C137 C138 C140 C143 C144 C145 C146 C147 C149 C150 C151 C152 C153 C154 C156 C157: library part Cap_100nF_X7R_10%_0402, "Capacitor,100nF,16V,X7R,10%,0402,YAGEO", Manuf_1=YAGEO, Manuf_Part_1=CC0402KRX7R7BB104
C28 C41 C47 C48 C51 C58 C62 C63 C67 C90 C155: library part Cap_1uF_X5R_10%_0603, "Capacitor,1uF,16V,X5R,10%,0603,YAGEO", Manuf_1=YAGEO, Manuf_Part_1=CC0603KRX5R7BB105
C29: library part Cap_470pF_X7R_10%_0402, "Capacitor,470pF,16V,X7R,10%,0402,YAGEO", Manuf_1=YAGEO, Manuf_Part_1=0402YC471KAT4A
C36 C38 C61: library part Cap_10uF_POL_10%_TANA, "Polarized Capacitor,10uF,10V,10%,typeA,VISHAY", Manuf_1=VISHAY, Manuf_Part_1=293D106X9010A2TE3
C40 C81: library part Cap_100nF_100V_X7R_10%_0805, "Capacitor,100nF,100V,X7R,10%,0805,TDK", Manuf_1=TDK, Manuf_Part_1=C2012X7R2A104K125AA
C43 C200: library part Cap_10nF_X7R_10%_0603, "Capacitor,10nF,50V,X7R,10%,0603,YAGEO", Manuf_1=YAGEO, Manuf_Part_1=CC0603KRX7R9BB103
C52: library part Cap_2.2uF_X7R_10%_0805, "Capacitor,2.2uF,16V, X7R,10%,0805,YAGEO", Manuf_1=YAGEO, Manuf_Part_1=CC0805KKX7R7BB225
C68 C69: library part Cap_4.7uF_POL_10%_TANA, "Polarized Capacitor,4.7uF,16V,10%,typeA,AVX", Manuf_1=AVX, Manuf_Part_1=TAJA475K016R
C73 C79 C92 C93 C94 C95 C148: library part Cap_4.7uF_X5R_10%_0603, "Capacitor,4.7uF,16V, X5R,10%,0603,YAGEO", Manuf_1=YAGEO, Manuf_Part_1=CC0603KRX5R7BB475
C77 C84: library part Cap_4.3pF_NPO_-+0.25pF_0402, "Capacitor, 4.3pF, 16V, NPO, -+0.25pF, 0402, KEMET", Manuf_1=AVX, Manuf_Part_1=C0402C439C4GACTU
C85: library part Cap_NA_0402, "Capacitor,NA,0402"
C100: library part Cap_10uF_X5R_10%_0603, "Capacitor,10uF,6.3V,X5R,10%,0603,YAGEO", Manuf_1=YAGEO, Manuf_Part_1=CC0603KRX5R5BB106
C101 C116: library part Cap_1uF_POL_10%_TANA, "Polarized Capacitor,1uF,16V,10%,typeA,AVX", Manuf_1=AVX, Manuf_Part_1=TAJA105K016R
C119 C120: library part Cap_22nF_X7R_10%_0402, "Capacitor,22nF,16V,X7R,10%,0402,YAGEO", Manuf_1=YAGEO, Manuf_Part_1=CC0402KRX7R7BB223
C129 C139: library part Cap_10uF_X5R_10%_0805, "Capacitor,10uF,25V,X5R,10%,0805,YAGEO", Manuf_1=YAGEO, Manuf_Part_1=CC0805KRX5R8BB106
C141 C142: library part Cap_10pF_NPO_5%_0402, "Capacitor,10pF,50V,NPO,5%,0402,YAGEO", Manuf_1=YAGEO, Manuf_Part_1=CC0402JRNPO9BN100
CN1: library part QSH-030-01-F-D-A, "HIGH SPEED SOCKET STRIP, .5mm PITCH, 60 PINS", Manuf_1=SAMTEC
CN2: library part "Header 4X2F", "Header Female, 4-Pin, Dual row, Straight", Manuf_1="Fischer Electronik", Manuf_Part_1="BL 2-8G"
CN3: library part "Header 5X2M", "Header Male, 5-Pin, Dual row, Straight, AMD", Manuf_1=AMD, Manuf_Part_1=826632-5
CN4: "Header, 4-Pin"
CN5: library part microSD-PJS008-2003, "Memory Card Connectors MicroSD Card Conn Revrs Mnt Push-Push", Manuf_1=YAMAICHI, Manuf_Part_1=PJS008-2003-1
CN6: "Connector Jack Stereo 3.5mm, female SMT, Blue (Line input)", Manuf_Part_2=PJ30280-3_BE
CN7: "Connector Jack Stereo 3.5mm, female SMT, Green (Line output)", Manuf_Part_2=PJ30280-3_GR
CN8: "RCA Phono Jack, Right Angle, SMD, Yellow", Manuf_1=JIUBABA, Manuf_2="CUI Inc", Manuf_Part_1=JBB0819100002, Manuf_Part_2=RCJ-014-SMT
CN9: library part "Header 10X1_Female_THT", "Header, 10-Pin, Single row, female, THT, 2.54", Manuf_1="Fischer Electronik"
CN10: "100 Base-TX (Fast Ethernet)  RJ45 single port (1x1) with LEDS Integrated Connector", Manuf_1=DGKYD, Manuf_Part_1=KRJ-CB4.2GYZNL
CN11 CN13: library part "Header 8X1_Female_THT", "Header, 8-Pins, Single row, female, THT, 2.54", Manuf_1="Fischer Electronik"
CN12: "RCA Phono Jack, Right Angle, SMD, White", Manuf_1=JIUBABA, Manuf_2="CUI Inc", Manuf_Part_1=JBB0819100004, Manuf_Part_2=RCJ-013-SMT
CN14: library part "Header 6X1_Female_THT", "Header, 6-Pins, Single row, female THT, 2.54", Manuf_1="Fischer Electronik"
CN15: "USB-MICRO-AB, 47590-0001, SMT, MOLEX", Manuf_1=MOLEX, Manuf_Part_1=47590-0001
CN16: "USB-MICRO-B, 1050170001, SMT, MOLEX", Manuf_1=MOLEX
D1 D3: "Schottky Single diode(150mA, 100V)", Manuf_1=STM
D2: "Low drop power Schottky rectifier(2A, 40V, 0.34V)", Manuf_1=STM, Manuf_Part_2=STPS2L40U, Manuf_Part_3=STPS2L40AF
D4 D9: library part DF01S_SMD, "Surface Mount Bridge Rectifiers", Manuf_1=VISHAY, Manuf_2=DIODES, Manuf_3=FAIRCHILD
D5 D6 D7 D8 D11: Manuf_1=STM
D10: "Transil 400W, VRM=58V", Manuf_1=STM, Manuf_Part_1=SMAJ58A-TR
D12: "Quad bidirectional Transil array for ESD protection", Manuf_1=STM
D13: "2-line Transil, (TVS), ultralow capacitance protection for high speed USB", Manuf_1=STM
JP1: library part JP2_RA, "Header, 2-Pins, Single row, Right Angle, 2.54 mm pitch, DIP", Manuf_1=ATOM
L2 L7 L8: library part BEAD_120R_2A_0603, "Bead,120R,2A,0603,BLM18PG121SN1D,MURATA", Manuf_1=MURATA, Manuf_2=TDK, Manuf_3=Tai-tech, Manuf_Part_2=MPZ1608S300A, Manuf_Part_3=FCM1608KF-601T03
L3 L4 L6: library part BEAD_600R_350MA_0603, "Bead,600R,350mA,0603,FCM1608KF-601T03,Tai-tech", Manuf_1=Tai-tech, Manuf_2=TDK, Manuf_3=MURATA, Manuf_Part_2=MPZ1608S300A, Manuf_Part_3=BLM18PG121SN1D
L5: "Power Inductor, 5.6uH, 0.2R, ME3220-562ML, CoilCraft", Manuf_1=CoilCraft, Manuf_2=Cyntec, Manuf_Part_2=SDET32251E-5R6MS-11
LD1 LD4 LD6 LD7: library part LED_red, "LED, red, 0603", Manuf_1=everlight, Manuf_Part_1=19-213-R6C-AP1Q2B/3T
LD2 LD3 LD5: library part LED_green, "LED, green, 0603", Manuf_1=everlight, Manuf_Part_1=19-213SYGC/S530-E2/TR8
LD8: "Bicolor Led", Manuf_1="Avago Technologies", Manuf_2=everluck, Manuf_Part_1=HSMF-A201-A00J1, Manuf_Part_2=LE-RGW35280
R1: library part Res_75K_1%_0603, "Resistor,75K,0603,1%,YAGEO", Manuf_1=YAGEO, Manuf_Part_1=RC0603FR-0775KL
R2 R16 R74 R109 R110: library part Res_0_5%_0603, "Resistor,0,0603,5%,YAGEO", Manuf_1=YAGEO, Manuf_Part_1=RC0603JR-070RL
R3: library part Res_2K_1%_0805, "Resistor,2K,0805,1%,YAGEO", Manuf_1=YAGEO, Manuf_Part_1=RC0805FR-072KL, Manuf_Part_2=RT0805FRE072KL
R4: library part Res_510_1%_0603, "Resistor,510,0603,1%,YAGEO", Manuf_1=YAGEO, Manuf_Part_1=RC0603FR-07510RL
R5 R62 R85: library part Res_1K_1%_0603, "Resistor,1K,0603,1%,YAGEO", Manuf_1=YAGEO, Manuf_Part_1=RC0603FR-071KL
R6: library part Res_124K_1%_0603, "Resistor,124K,0603,1%,YAGEO", Manuf_1=YAGEO, Manuf_Part_1=RC0603FR-07124KL
R7 R73 R88 R93 R95 R97 R98 R99 R100 R123 R125 R126 R129 R137 R138: library part Res_0_5%_0402, "Resistor,0,0402,5%,YAGEO", Manuf_1=YAGEO, Manuf_Part_1=RC0402JR-070RL
R8 R18 R20 R28 R29 R30 R34 R40 R43 R45 R51 R52 R54 R56 R67 R68 R70 R71 R86 R87 R106 R107 R108 R122 R134 R144 R147 R200: library part Res_10K_1%_0402, "Resistor,10K,0402,1%,YAGEO", Manuf_1=YAGEO, Manuf_Part_1=RC0402FR-0710KL
R9: library part Res_0.47_1%_1206, "Resistor,0.47,1206,1%,YAGEO", Manuf_1=YAGEO, Manuf_2="Rohm Semiconductor", Manuf_Part_1=RL1206FR-070R47L, Manuf_Part_2=LTR18EZPFLR470
R10: library part Res_56_1%_0805, "Resistor,56,0805,1%,YAGEO", Manuf_1=YAGEO, Manuf_Part_1=RC0805FR-0756RL
R11: library part Res_20K_1%_0603, "Resistor,20K,0603,1%,YAGEO", Manuf_1=YAGEO, Manuf_Part_1=RC0603FR-0720KL
R12 R13 R25: library part Res_10K_1%_0603, "Resistor,10K,0603,1%,YAGEO", Manuf_1=YAGEO, Manuf_Part_1=RC0603FR-0710KL
R14 R15: library part Res_13K_1%_0603, "Resistor,13K,0603,1%,YAGEO", Manuf_1=YAGEO, Manuf_Part_1=RC0603FR-0713KL
R17 R89 R90 R91 R141: library part Res_2K7_1%_0402, "Resistor,2K7,0402,1%,YAGEO", Manuf_1=YAGEO, Manuf_Part_1=RC0402FR-072K7L
R19 R21 R76 R92 R94 R114 R121 R124 R128 R133: library part Res_NA_0402, "Resistor,[NA],0402"
R22: library part Res_15_1%_0805, "Resistor,15,0805,1%,YAGEO", Manuf_1=YAGEO, Manuf_Part_1=RC0805FR-0715RL
R23: library part Res_200_1%_1206, "Resistor,200,1206,1%,Rohm", Manuf_1="Rohm Semiconductor", Manuf_Part_1=LTR18EZPF2000
R24: library part Res_68_1%_0805, "Resistor,68,0805,1%,YAGEO", Manuf_1=YAGEO, Manuf_Part_1=RC0805FR-0768RL
R26 R33 R42 R46: library part Res_75_1%_0805, "Resistor,75,0805,1%,YAGEO", Manuf_1=YAGEO, Manuf_Part_1=RC0805FR-0775RL
R27 R104 R116 R117 R136 R143 R145: library part Res_100_1%_0402, "Resistor,100,0402,1%,YAGEO", Manuf_1=YAGEO, Manuf_Part_1=RC0402FR-07100RL
R31: library part Res_12K1_1%_0603, "Resistor,12K1,0603,1%,VISHAY", Manuf_1=VISHAY, Manuf_Part_1="MCT 0603-50 1% P5 12K1"
R32 R36 R44: library part Res_33_1%_0402, "Resistor,33,0402,1%,YAGEO", Manuf_1=YAGEO, Manuf_Part_1=RC0402FR-0733RL
R35 R37 R39 R41: library part Res_50_1%_0402, "Resistor,50,0402,1%,YAGEO", Manuf_1=YAGEO, Manuf_Part_1=RC0402FR-0750RL
R38 R48 R49 R84 R96: library part Res_0_5%_0805, "Resistor,0,0805,5%,YAGEO", Manuf_1=YAGEO, Manuf_Part_1=RC0805JR-070RL
R47 R148: library part Res_1K5_1%_0402, "Resistor,1K5,0402,1%,YAGEO", Manuf_1=YAGEO, Manuf_Part_1=RC0402FR-071K5L
R50 R57 R58 R59 R103: library part Res_1K_1%_0402, "Resistor,1K,0402,1%,YAGEO", Manuf_1=YAGEO, Manuf_Part_1=RC0402FR-071KL
R60 R61 R66 R105 R113: library part Res_330_1%_0402, "Resistor,330,0402,1%,YAGEO", Manuf_1=YAGEO, Manuf_Part_1=RC0402FR-07330RL
R63: library part Res_330_1%_0603, "Resistor,330,0603,1%,YAGEO", Manuf_1=YAGEO, Manuf_Part_1=RC0603FR-07330RL, Manuf_Part_2=RT0603FRE07330RL
R64: library part Res_510_1%_0402, "Resistor,510,0402,1%,YAGEO", Manuf_1=YAGEO, Manuf_Part_1=RC0402FR-07510L
R65: library part Res_620_1%_0603, "Resistor,620,0603,1%,VISHAY", Manuf_1="VISHAY DRALORIC", Manuf_Part_1=CRCW0603620RFKEA
R75: library part Res_10_1%_0805, "Resistor,10,0805,1%,Stackpole,1/4W", Manuf_1="Stackpole Electronics Inc", Manuf_Part_1=RNCP0805FTD10R0
R77 R78: library part Res_20_1%_0402, "Resistor,20,0402,1%,YAGEO", Manuf_1=YAGEO, Manuf_Part_1=RC0402FR-0720RL
R79 R80 R81 R82 R83 R132: library part Res_47K_1%_0402, "Resistor,47K,0402,1%,YAGEO", Manuf_1=YAGEO, Manuf_Part_1=RC0402FR-0747KL
R101: library part Res_210_1%_0402, "Resistor,210,0402,1%,YAGEO", Manuf_1=YAGEO, Manuf_Part_1=RC0402FR-07210RL
R102: library part Res_110_1%_0402, "Resistor,110,0402,1%,YAGEO", Manuf_1=YAGEO, Manuf_Part_1=RC0402FR-07110RL
R111: library part Res_75_1%_0402, "Resistor,75,0402,1%,YAGEO", Manuf_1=YAGEO, Manuf_Part_1=RC0402FR-0775RL
R112 R115: library part Res_1M_1%_0402, "Resistor,1M,0402,1%,YAGEO", Manuf_1=YAGEO, Manuf_Part_1=RC0402FR-071ML
R118 R127 R131 R149 R150: library part Res_100K_1%_0402, "Resistor,100K,0402,1%,YAGEO", Manuf_1=YAGEO, Manuf_Part_1=RC0402FR-07100KL, Manuf_Part_2=RT0402FRE07100KL
R119 R120 R135: library part Res_4K7_1%_0402, "Resistor,4K7,0402,1%,YAGEO", Manuf_1=YAGEO, Manuf_Part_1=RC0402FR-074K7L, Manuf_Part_2=RT0402FRE074K7L
R130: library part Res_3K3_1%_0402, "Resistor,3K3,0402,1%,YAGEO", Manuf_1=YAGEO, Manuf_Part_1=RC0402FR-073K3L
R139: library part Res_8K06_1%_0402, "Resistor,8K06,0402,1%,YAGEO", Manuf_1=YAGEO, Manuf_Part_1=RC0402FR-078K06L
R140: library part Res_2K2_1%_0402, "Resistor,2K2,0402,1%,YAGEO", Manuf_1=YAGEO, Manuf_Part_1=RC0402FR-072K2L
R142: library part Res_820_1%_0805, "Resistor,820,0805,1%,YAGEO", Manuf_1=YAGEO, Manuf_Part_1=RC0805FR-07820RL
R146: library part Res_36K_1%_0402, "Resistor,36K,0402,1%,YAGEO", Manuf_1=YAGEO, Manuf_Part_1=RC0402FR-0736KL
SB1 SB2 SB3 SB4 SB7 SB8 SB9 SB10 SB12 SB14 SB15 SB17 SB18 SB19 SB20 SB21 SB22: library part SB_ON
SB5 SB6 SB11 SB13 SB16 SB23: library part SB_OFF
T1: "N-channel 200 V, 1.1ohm, 1 A, low gate charge STripFET II, Power MOSFET", Manuf_1=ST, Manuf_2=Fairchild, Manuf_Part_2=FDN86246
T2: library part POE30P_C, "Flyback Transformers for 3 Watt, PoE applications, CoilCraft Cyntec", Manuf_1=CoilCraft, Manuf_2=Cyntec, Manuf_Part_1=POEP30P50L, Manuf_Part_2=86H-15181
T3 T5: "NPN Bipolar Transistor", Manuf_1=NXP, Manuf_Part_1=BSR14
T4: library part H2019, "10/100BASE-TX VoIP Magnetics Modules, Data Transformer", Manuf_1=PULSE, Manuf_2=TDK, Manuf_3=DGKYD, Manuf_Part_2="TLA-6T127LF, with different pinout", Manuf_Part_3=KMS-1102NL
T100: library part POE30P_W, "Flyback Transformers for 3 Watt, PoE applications, Wurth", Manuf_1=Wurth, Manuf_Part_1=750315923
TP1 TP2 TP3 TP5 TP6 TP7 TP8 TP9 TP11 TP12 TP13 TP14 TP15 TP16 TP17 TP18 TP21 TP22 TP26 TP27 TP28 TP100 TP101 TP102 TP103 TP104 TP105 TP106 TP107 TP108 TP109: "Test Point"
TP20: library part TP1, "Test Point"
U1: "Integrated IEEE 802.3af compliant PoE-PD interface, and PWM controller with support of external source", Manuf_1=ST, Manuf_Part_1=PM8800ATR
U2: "Low voltage adjustable shunt reference", Manuf_1=ST
U3: "LAN8742A-CZ-TR - Small Footprint RMII 10/100 Ethernet, Transceiver with HP Auto-MDIX and flexPWR Technology SQFN-24", Manuf_1=MICROCHIP
U4: "Ultra low drop-low noise BiCMOS voltage, regulators low ESR capacitors compatible", Manuf_1=STM
U5 U6 U8 U9: "MEMS audio sensor, omnidirectional digital microphone", Manuf_1=STM, Manuf_Part_1=MP34DT01TR-M
U7: library part LD39050P, "Ultra low drop-low , 500 mA low quiescent current", Manuf_1=STM
U10: "OPTOISOLATOR 3.7KV TRANSISTOR 4SMD", Manuf_1=FAIRCHILD
U11: "Multi-Channel Audio Hub CODEC for Smartphones", Manuf_1="Cirrus Logic"
U12: library part MT25QL512ABB1EW9, "512Mb, 3V, Multiple I/O Serial Flash Memory, Quad/Dual", Manuf_1=MICRON, Manuf_Part_1=MT25QL512ABB1EW9-0SIT, Manuf_Part_2=N25Q512A13GF840E
U13: library part STM32F769NIH6U, "STM32F769NIH6 (STM32F7 Big Birdie) TBGA216", Manuf_1=STM
U14: "LOW DROP FIXED AND ADJUSTABLE POSITIVE VOLTAGE REGULATORS (1.8 Volts)", Manuf_1=STM
U15 U16: "Single inverter gate with a standard push-pull output. (1.65V to 5.5V)", Manuf_1=DIODES, Manuf_Part_1=74LVC1G04SE-7
U17: library part MT48LC4M32B2B5-6A, "SDRAM 128MBIT (4M x 32) 166MHZ 90-VFBGA (8x13)", Manuf_1=MICRON, Manuf_Part_1="MT48LC4M32B2B5-6A IT:L TR"
U18: "IC REG LDO 5V 0.8A SOT223", Manuf_1=STM
U19: "Medium-density performance line ARM-based 32-bit MCU with 128KB Flash", Manuf_1=STM
U20: "USB3320C,  Hi-Speed USB Host, Device or OTG PHY with ULPI Low Pin Interface", Manuf_1=MICROCHIP, Manuf_Part_1=USB3320C-EZK-TR
U21: "Enhanced single channel power switches", Manuf_1=STM
U22: "1.2 A current limited high-side power switch with thermal shutdown", Manuf_1=STM
U250: library part MX25L51245G, "512Mb, 3V, Multiple I/O Serial Flash Memory, Quad/Dual", Manuf_1=MACRONIX, Manuf_Part_1=MX25L51245GZ2I-08G, Manuf_Part_2=MX25L51245GZ2I-10G
X1: library part XTAL_32K_NX3215SA, "Crystal 32.768kHz, 6pF, -+20PPM, R=50K, SMD", Manuf_1=NDK, Manuf_Part_1="NX3215SA 32.768KHz EXS00A-MU00525"
X2: library part OSC_25M_NZ2520SB, "Oscillator 25.00Mhz, -+50PPM, 3.3V, Temp -55 to +125°C", Manuf_1=NDK, Manuf_2="AVX Corp/Kyocera Corp", Manuf_Part_1="NZ2520SB 25MHz END4869B", Manuf_Part_2=KC2520B25.0000C10E00
X3: library part XTAL_8M_NX3225GD, "Crystal 8Mhz, 8pF, -+50PPM, SMD", Manuf_1=NDK, Manuf_Part_1="NX3225GD 8MHz EXS00A-CG04874", Manuf_Part_2=NX3225GD-8.000M-STD-CRA-3
X4: library part OSC_24M_NZ2520SB, "Oscillator 24.00Mhz, -+50PPM, 3.3V, Temp -55 to +125°C", Manuf_1=NDK, Manuf_2="AVX Corp/Kyocera Corp", Manuf_Part_1="NZ2520SB 24MHz END4869A", Manuf_Part_2=KC2520B24.0000C10E00

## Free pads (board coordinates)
  round 0 on Mech12: 1(-5703.15,-5263.15) 1(-5703.15,-2200) 1(-5693,-4141.57) 1(-5693,-2657.16) 1(-5581.25,-3735) 1(-5581.25,-3065) 1(-5257.28,-3997.28) 1(-5254.97,-3472.68) 1(-5250,-3327.28) 1(-5245,-2802.72) 1(-5190,-3130) 1(-5160,-3060) 1(-5160,-3005) 1(-5159,-3858) 1(-5130,-2955) 1(-5130,-2495) 1(-5080.59,-3950.59) 1(-5075,-3730) 1(-5055,-2855) 1(-4985,-3315) 1(-4980,-2770) 1(-4970,-2985) 1(-4960,-3030) 1(-4947.74,-2922.64) 1(-4935,-3315) 1(-4920.59,-3945) 1(-4910,-3733) 1(-4894.53,-2910.4) 1(-4894,-5155) 1(-4886.9,-2041.9) 1(-4885,-3315) 1(-4878.93,-2156.07) 1(-4865.09,-3044.44) 1(-4865,-3064.21) 1(-4845.3,-2946.1) 1(-4845,-2745) 1(-4835,-3315) 1(-4825.62,-3064.22) 1(-4806.04,-3024.75) 1(-4795,-2710) 1(-4785,-3305) 1(-4782,-5245) 1(-4781.99,-4494.67) 1(-4775.33,-4929.67) 1(-4775,-3360) 1(-4775,-3115) 1(-4740,-3395) 1(-4740,-3360) 1(-4725,-3315) 1(-4712.3,-2420) 1(-4710,-3395) 1(-4710,-3360) 1(-4575,-3020) 1(-4574,-3070) 1(-4570,-5275) 1(-4494.2,-3132.3) 1(-4465,-5275) 1(-4385,-3150) 1(-4370,-5275) 1(-4205,-3275) 1(-4140,-2835) 1(-4080,-5275) 1(-4047.1,-2041.9) 1(-4045.07,-2156.07) 1(-3990,-2847) 1(-3960,-3475) 1(-3896,-4666.45) 1(-3884.94,-5251.06) 1(-3861,-4325) 1(-3830,-2859) 1(-3825,-4389) 1(-3797,-2858) 1(-3793,-5204) 1(-3793,-4620) 1(-3792,-5299) 1(-3790,-4715) 1(-3750,-3773) 1(-3735,-3090) 1(-3730,-3995) 1(-3722,-5252) 1(-3722,-4666) 1(-3676,-4196.49) 1(-3645,-4353) 1(-3645,-4196) 1(-3645,-3776) 1(-3643,-4550) 1(-3635,-5242) 1(-3613,-4134) 1(-3590,-4630) 1(-3588,-4907.4) 1(-3581,-4134.01) 1(-3560,-3300.16) 1(-3540,-3775) 1(-3529,-3365) 1(-3528,-4550) 1(-3527.84,-3272.16) 1(-3526,-4426) 1(-3523,-3995) 1(-3519,-4132) 1(-3498.14,-3303.65) 1(-3496.35,-3272.16) 1(-3496,-3396) 1(-3496,-3367) 1(-3470,-5048) 1(-3464,-4550) 1(-3450,-3774) 1(-3441,-4870) 1(-3435.15,-3427.84) 1(-3435,-3302.01) 1(-3403.65,-3427.84) 1(-3403.65,-3272.16) 1(-3402.16,-3396.35) 1(-3402,-3303.51) 1(-3401.86,-3364.85) 1(-3390,-4550) 1(-3380.24,-2862) 1(-3376,-4001) 1(-3372.16,-3459.34) 1(-3372.16,-3272.16) 1(-3370,-4898) 1(-3361,-4197) 1(-3330,-4385) 1(-3329,-4550) 1(-3326,-3745) 1(-3310,-4666.45) 1(-3309.94,-5251.06) 1(-3300,-4133) 1(-3271,-3745) 1(-3267,-4353) 1(-3266,-4164) 1(-3265,-2858) 1(-3263,-4551) 1(-3245,-3271.99) 1(-3229,-4240) 1(-3213.01,-3522.33) 1(-3210.39,-2535) 1(-3208,-4620) 1(-3208,-3475.98) 1(-3207,-4716) 1(-3206,-5300) 1(-3205,-5205) 1(-3200,-4199) 1(-3175,-3745) 1(-3138,-5250) 1(-3138,-4666) 1(-3113,-2869) 1(-3113,-2839) 1(-3095,-4790) 1(-3092.43,-5285) 1(-3078.5,-2482) 1(-3060,-4396) 1(-3055,-4660) 1(-3055,-4274) 1(-3055,-4169) 1(-3049,-4945) 1(-3045,-5335) 1(-3022.12,-4794.96) 1(-3020,-5130) 1(-3020,-3135) 1(-3020,-3085) 1(-3019.14,-3035) 1(-3019,-3330) 1(-3018,-3415) 1(-3017,-3184) 1(-3016,-3234) 1(-3015,-5270) 1(-3015,-3281) 1(-2990,-4964) 1(-2990,-4795) 1(-2984,-5075) 1(-2984,-5035) 1(-2970,-3794) 1(-2965,-3670) 1(-2956,-3605) 1(-2935,-3671) 1(-2931,-3482) 1(-2915,-3530) 1(-2906,-3323.54) 1(-2905,-2875) 1(-2905,-2840) 1(-2854.64,-5100) 1(-2852,-3045) 1(-2851,-3170) 1(-2845,-4885) 1(-2845,-4830) 1(-2845,-4775) 1(-2820,-5105) 1(-2815,-5167) 1(-2799,-2296.46) 1(-2790,-4885) 1(-2790,-4830) 1(-2790,-4775) 1(-2750,-5165) 1(-2741,-5229) 1(-2735,-4885) 1(-2735,-4830) 1(-2735,-4775) 1(-2720,-4593) 1(-2714.33,-5137) 1(-2712.49,-2620) 1(-2707,-4990) 1(-2695,-3320) 1(-2660,-5135) 1(-2650,-2296.46) 1(-2594.2,-3792.3) 1(-2594.2,-3692.3) 1(-2560,-4860) 1(-2560,-4800) 1(-2533.08,-2578.08) 1(-2495,-2940) 1(-2490,-3670) 1(-2490,-3625) 1(-2470,-5245) 1(-2445,-4885) 1(-2445,-2895) 1(-2440,-4790) 1(-2440,-4710) 1(-2432,-2117) 1(-2421.19,-2586.19) 1(-2380,-3180) 1(-2378,-2874) 1(-2370,-3380) 1(-2351.19,-2590) 1(-2343,-2873) 1(-2335,-3405) 1(-2330,-4490) 1(-2330,-3295) 1(-2325,-3945.1) 1(-2302.8,-5402.91) 1(-2286,-3649) 1(-2286,-3609) 1(-2286,-3569) 1(-2285,-5100) 1(-2285,-4490) 1(-2284,-2873) 1(-2282.06,-2340) 1(-2281.19,-2590) 1(-2270,-3895) 1(-2270,-2117) 1(-2263.43,-5296.61) 1(-2260,-4731.42) 1(-2255,-4535) 1(-2255,-2873) 1(-2245,-3648) 1(-2245,-3608) 1(-2245,-3569) 1(-2240,-5251) 1(-2240,-3410) 1(-2230,-2840) 1(-2230,-2340) 1(-2228.58,-4940) 1(-2225,-2585) 1(-2224,-2874) 1(-2215,-5135) 1(-2205,-3648) 1(-2205,-3609) 1(-2205,-3569) 1(-2200,-3410) 1(-2195,-2120) 1(-2170,-2340) 1(-2169,-2296.46) 1(-2155,-3410) 1(-2125,-4590) 1(-2124.58,-2120) 1(-2110.47,-4700) 1(-2109,-3608) 1(-2103,-3527) 1(-2077,-3910) 1(-2077,-3880) 1(-2075.7,-3849.6) 1(-2070,-5150) 1(-2066.57,-5296.61) 1(-2038,-2043) 1(-2030,-3405) 1(-2027.2,-5402.91) 1(-2024,-2498) 1(-2020,-2296.46) 1(-2015,-4908.58) 1(-2015,-4849.53) 1(-2010,-2617) 1(-1995,-4590) 1(-1980,-2355) 1(-1970,-4485) 1(-1955,-5030) 1(-1940,-4625) 1(-1930,-5246) 1(-1922,-2048) 1(-1896.99,-4415) 1(-1880,-2558) 1(-1870,-4520) 1(-1855,-4985) 1(-1855,-4955) 1(-1840,-4655) 1(-1820,-4960) 1(-1820,-4840) 1(-1820,-4810) 1(-1802,-4890) 1(-1800,-2210) 1(-1795,-5247.5) 1(-1794,-2602.6) 1(-1775,-2840) 1(-1756,-4995) 1(-1755,-4690) 1(-1720,-4800) 1(-1720,-2530) 1(-1720,-2494) 1(-1685,-2805) 1(-1670,-2490) 1(-1650,-2790) 1(-1645,-4655) 1(-1635,-5365) 1(-1635,-2755) 1(-1624,-4968) 1(-1622,-4891) 1(-1620,-2490) 1(-1601,-4933) 1(-1595,-2800) 1(-1576,-4968) 1(-1575,-4891) 1(-1560,-5225) 1(-1560,-2490) 1(-1550,-5190) 1(-1550,-4650) 1(-1550,-4620) 1(-1540,-2090) 1(-1520,-5190) 1(-1520,-4650) 1(-1520,-4620) 1(-1520,-2490) 1(-1485,-4890) 1(-1475,-2965) 1(-1475,-2940) 1(-1475,-2900) 1(-1475,-2855) 1(-1474,-3210) 1(-1405,-4585) 1(-1325,-3908.2) 1(-1115,-2904) 1(-1107.01,-5263.15) 1(-1107.01,-4141.57) 1(-1107.01,-2657.16) 1(-1107.01,-2200)
  round 40 smd far side mask+40: ""(395,3055) ""(440,390) ""(4655,3080)
  round 40 smd mask+40: ""(395,3055) ""(440,390) ""(4655,3080)

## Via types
v1: diameter 20, hole 10, TOP to BOTTOM, 354 vias
v2: diameter 24, hole 12, TOP to BOTTOM, 349 vias
v3: diameter 16, hole 8, TOP to BOTTOM, 219 vias
v4: diameter 12, hole 6, TOP to BOTTOM, 27 vias

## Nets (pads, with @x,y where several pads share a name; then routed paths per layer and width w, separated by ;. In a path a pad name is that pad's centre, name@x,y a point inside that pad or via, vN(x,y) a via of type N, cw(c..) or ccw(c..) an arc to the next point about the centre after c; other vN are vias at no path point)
1V8: C2.2 C64.1 C91.1 C94.1 C100.2 C145.2 CN1.60 U11.D1 U11.D8 U11.G9 U14.2 U14.4 U20.28 U20.30 | length 6757.6
  TOP w10: C2.2@3187.51,2941.92 3204.56,2958.97 CN1.60@3204.56,3050.55
  TOP w20: v2(3155,2920) 3176.92,2941.92 C2.2@3187.51,2941.92
  L4_SIG w20: v2(1165,2830) 1945,2830 2025,2910 2210,2910 2245,2875 2605,2875 2660,2820 3075,2820 3155,2900 v2(3155,2920) ; v2(1200,340) 1540,340 1665,465 1955,465 2005,415 2375,415 2445,485 2865,485 2880,500 2880,535 2930,585 v2(2930,603)
  BOTTOM w9: v4(1015.31,2376.09) U11.D8@1025.16,2385.94 ; 1084.21,2335.96 U11.G9@1084.21,2366.26
  BOTTOM w10: U11.D1@1025.16,2523.74 1025.16,2535.16 1055,2565 C64.1@1055,2640 ; 1084.21,2335.96 1084.21,2315.79 1100,2300 ; U20.28@3014.72,620.16 2993.77,620.16 2993.45,619.84 2960.16,619.84 C145.2@2950,630 2950,640 2969.84,659.84 3014.41,659.84 U20.30@3014.72,659.53
  BOTTOM w20: 922.46,1890 U14.4@965.98,1890 ; C94.1@965,2245 v2(965,2285) ; 965.98,1816.98 U14.4@965.98,1890 ; 965.98,1963.02 U14.4@965.98,1890 ; 1009.5,1890 U14.4@965.98,1890 ; 1034.48,2055 C100.2@1060,2055 ; C64.1@1055,2640 1080,2615 v2(1080,2605) ; 1060,1810 1060,480 v2(1200,340) ; 1060,2030.98 C100.2@1060,2055 ; 1060,2079.02 C100.2@1060,2055 ; 1100,2300 1115,2285 C91.1@1115,2235 1125,2235 v2(1145,2215) ; 1170.5,1890 U14.2@1214.02,1890 ; 1214.02,1861.98 U14.2@1214.02,1890 ; 1214.02,1918.02 U14.2@1214.02,1890 ; 1257.54,1890 U14.2@1214.02,1890 ; v2(2930,603) 2950,623 C145.2@2950,630
  other v2: 970,2060 1000,2060 970,2095 999,2094.97 1028,2095.01
3V3: B1.1 B1.4 C1.2 C33.2 C38.1 C44.1 C45.1 C48.2 C49.2 C55.1 C56.1 C65.1 C67.2 C71.1 C92.1 C96.2 C98.2 C117.2 C118.2 C123.2 C124.2 C125.2 C126.2 C127.2 C128.2 C130.2 C131.2 C133.2 C134.2 C135.2 C136.2 C137.2 C138.2 C144.1 C147.1 CN1.36 CN2.2 CN2.3 CN5.4 CN11.2 CN11.4 JP4.2 L2.2 R8.1 R17.2 R19.1 R20.1 R30.2 R34.2 R35.1 R37.1 R39.1 R41.1 R43.2 R45.2 R47.2 R51.2 R52.2 R54.1 R56.1 R65.2 R66.2 R67.2 R71.2 R76.2 R79.2 R80.2 R81.2 R82.2 R83.2 R86.2 R87.2 R89.1 R90.1 R91.1 R94.2 R106.2 R107.1 R109.2 R123.2 R125.2 R126.2 R130.1 R134.1 R137.2 R200.1 U3.9 U5.1 U6.1 U7.4 U8.1 U9.1 U11.B2 U11.C2 U11.D2 U11.E9 U12.8 U14.3 U15.5 U16.5 U17.A7 U17.B2 U17.B7 U17.C9 U17.D9 U17.E1 U17.F9 U17.L1 U17.L7 U17.M9 U17.N9 U17.P2 U17.P7 U17.R7 U250.8 X2.4 X4.4 | length 6354.3
  TOP w10: U8.1@2136,224.67 2145.67,224.67 2159.05,238.05 2159.27,238.05 2165.71,244.49 2165.71,244.71 2176,255 C55.1@2225,255 ; U5.1@2136,809.28 2145.89,809.28 2172.61,836 C44.1@2225,836 ; U9.1@2720.61,224.67 2730.5,224.67 2760.83,255 C56.1@2807.57,255 ; U6.1@2720.61,809.28 2730.73,809.28 2761.45,840 C45.1@2810,840 ; C1.2@3407.51,2941.92 3440.78,2975.19 CN1.36@3440.78,3050.55 ; C33.2@3480,1835 3504.84,1859.84 U3.9@3578.23,1859.84
  TOP w20: B1.4@607.83,387.5 v2(669.5,387.5) ; v2(907.5,387.5) B1.1@962.17,387.5 ; v2(1005,660) R52.2@1040,660 ; R54.1@1080,770 v2(1115,770) ; R56.1@1080,815 v2(1115,815) ; R200.1@1080,860 v2(1115,860) ; R65.2@1590,390 v2(1590,430) ; R66.2@1685,380 v2(1685,420) ; v2(1690,2225) 1713,2225 1768,2170 1840,2170 1880,2210 U250.8@1880,2281.9 ; v2(2225,219) C55.1@2225,255 ; C44.1@2225,836 2225,805.29 v2(2225.29,805.29) ; R17.2@2405,2570 2405,2575 v2(2430,2600) ; v2(2510,255) R71.2@2545,255 ; R19.1@2550,2570 2550,2590 2553,2593 v2(2553,2602) ; R20.1@2595,2570 v2(2595,2604) ; R51.2@2710,890 v2(2741,890) ; C56.1@2807.57,255 v2(2807.57,283) ; C45.1@2810,840 v2(2847,840) ; v2(3365,2941.92) C1.2@3407.51,2941.92 ; v2(3400,1995) R30.2@3440,1995 ; v2(3413,1938) 3436,1915 R34.2@3440,1915 ; R47.2@3440,1650 3440,1643 v2(3460,1623) ; R43.2@3440,1750 3440,1742 v2(3460,1722) ; v2(3451,1514) C38.1@3451,1544 ; C38.1@3451,1551 C38.1@3465,1565 3481,1549 v2(3481,1513) ; C33.2@3480,1835 3500,1815 v2(3506,1815) ; v2(3590,1665) R45.2@3625,1665 ; v2(3700,1615) L2.2@3745,1615 ; R41.1@3885,1790 3899,1790 v1(3920,1811) 3920,1812 3902,1830 R39.1@3885,1830 ; R37.1@3885,1870 v1(3920,1870) ; R35.1@3885,1910 v1(3920,1910) ; R67.2@3945,325 3945,345 v2(3965,365) ; v2(4235,620) C48.2@4180,620 4170,610 C49.2@4170,570 4182.6,567.4 U7.4@4243.48,567.4
  BOTTOM w9: v4(976.54,2513.25) 985.73,2504.06 U11.B2@985.79,2504.06 ; U11.C2@1005.47,2504.06 U11.C2@1005.47,2504.06 v4(1015.22,2513.76)
  BOTTOM w10: v4(1015.22,2513.76) 1024.92,2504.06 U11.D2@1025.16,2504.06 ; U11.E9@1044.84,2366.26 1044.84,2265.16 C92.1@1065,2245
  BOTTOM w15: C118.2@865,1695 865,1660 870.59,1654.41 U16.5@870.59,1630.43 ; C117.2@1030,1695 1030.59,1694.41 U15.5@1030.59,1630.43 ; C130.2@2115,1105 2137,1127 2234.54,1127 U17.A7@2239.53,1122.01 ; C127.2@2115,1150 2243.03,1150 U17.B7@2271.02,1122.01 ; U17.B2@2271.02,1279.49 2271.02,1278.98 v3(2287,1263) ; C138.2@2290,950 2302.52,962.52 U17.C9@2302.52,1059.02 ; U17.D9@2334.02,1059.02 2334.02,950.98 C137.2@2335,950 ; C124.2@2345,1425 2345,1331.49 U17.E1@2365.51,1310.98 ; U17.F9@2397.01,1059.02 2397.01,957.99 C136.2@2405,950 ; v3(2538.61,1108) 2552.62,1122.01 U17.L7@2554.49,1122.01 ; U17.L1@2554.49,1310.98 2554.49,1369.49 2565,1380 C123.2@2565,1425 ; U17.M9@2585.98,1059.02 2579,1052.04 2579,996 2600.84,974.16 2600.84,950.84 C134.2@2600,950 ; U17.N9@2617.48,1059.02 2630,1046.5 2630,1002 2670,962 C133.2@2670,950 ; v3(2631.92,1262.43) U17.P2@2648.98,1279.49 ; U17.P7@2648.98,1122.01 2671.97,1145 C128.2@2800,1145 2800,1179 v2(2807,1186) ; U17.R7@2680.47,1122.01 2772.99,1122.01 C131.2@2800,1095 v2(2800,1065) ; C126.2@2800,1250 2800,1281 v2(2807,1288)
  BOTTOM w20: C71.1@845,2505 v2(880,2505) ; C118.2@865,1695 v2(865,1730) ; v2(905,2606.83) C67.2@905,2645 ; v2(960,2606.83) C65.1@960,2640 ; R87.2@1010,2675 v2(1010,2707.91) ; C117.2@1030,1695 v2(1030,1730) ; C92.1@1065,2245 1073,2253 v2(1073,2284) ; 1170.5,1799.45 U14.3@1214.02,1799.45 ; 1214.02,1771.43 U14.3@1214.02,1799.45 ; 1257.54,1799.45 U14.3@1214.02,1799.45 ; R94.2@1260,2540 v2(1295,2540) ; 1536.98,2025 JP4.2@1575,2025 ; 1551.97,1930 R109.2@1584.49,1930 ; 1575,1986.98 JP4.2@1575,2025 ; 1575,2063.02 JP4.2@1575,2025 ; 1584.49,1898.48 R109.2@1584.49,1930 ; 1584.49,1961.52 R109.2@1584.49,1930 ; v2(1660,2655) R86.2@1690,2655 ; v2(1690,2225) C96.2@1730,2225 U12.8@1730,2281.46 ; v2(2115,1060) C130.2@2115,1105 ; C127.2@2115,1150 v2(2115,1180) ; v2(2170,1425) C125.2@2210,1425 ; v2(2259,950) C138.2@2290,950 ; C137.2@2335,950 v2(2367,950) ; C124.2@2345,1425 2378,1425 v2(2379,1424) ; C136.2@2405,950 v2(2435,950) ; v2(2470,2725) R83.2@2470,2765 ; v2(2490.82,2600.29) 2490.82,2584.18 2505,2570 R91.1@2510,2570 ; v2(2510,950) C135.2@2540,950 ; v2(2515,2735) R82.2@2515,2765 ; v2(2527,1418) 2534,1425 C123.2@2555,1425 C123.2@2565,1425 ; R130.1@2540,630 v2(2540,660) ; R90.1@2550,2570 2550,2590 2553,2593 v2(2553,2602) ; v2(2560,2735) R81.2@2560,2765 ; v2(2570,950.84) C134.2@2600.84,950.84 ; R89.1@2595,2570 v2(2595,2604) ; CN5.4@2602.99,2871.21 v2(2602.99,2946) ; v2(2640,950) C133.2@2670,950 ; v2(2710,540) R134.1@2710,580 ; v2(2730,2735) R80.2@2730,2765 ; v2(2735,515) C147.1@2775,515 2773.58,516.42 X4.4@2773.58,576.46 ; v2(2780,2735) R79.2@2780,2765 ; v2(2840,670) 2850,680 C144.1@2850,700 R126.2@2910,700 ; R106.2@2850,2085 v2(2880,2085) ; R76.2@2915,3040 2925,3040 v2(2945,3060) ; v2(3030,2075) R107.1@3060,2075 ; X2.4@3106.42,2193.54 3156.46,2193.54 C98.2@3170,2180 v2(3203.12,2180) ; v2(3181,3260) R8.1@3220,3260 ; R123.2@3220,830 v2(3220,865) ; R137.2@3305,560 v2(3340,560) ; R125.2@3305,700 v2(3340,700)
  other v2: 1175,1750 1210,1750 1520,1830 1550,1830 1580,1830 1520,1860 1550,1860 1580,1860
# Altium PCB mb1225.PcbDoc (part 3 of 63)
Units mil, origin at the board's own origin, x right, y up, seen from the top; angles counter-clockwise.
Board outline 5000 x 3464.56 mil, 6 copper layers (TOP, L2_GND, L3_VCC, L4_SIG, L5_GND, BOTTOM), stack 62.2 mil thick; 452 components, 378 nets, 1968 pads, 949 vias.

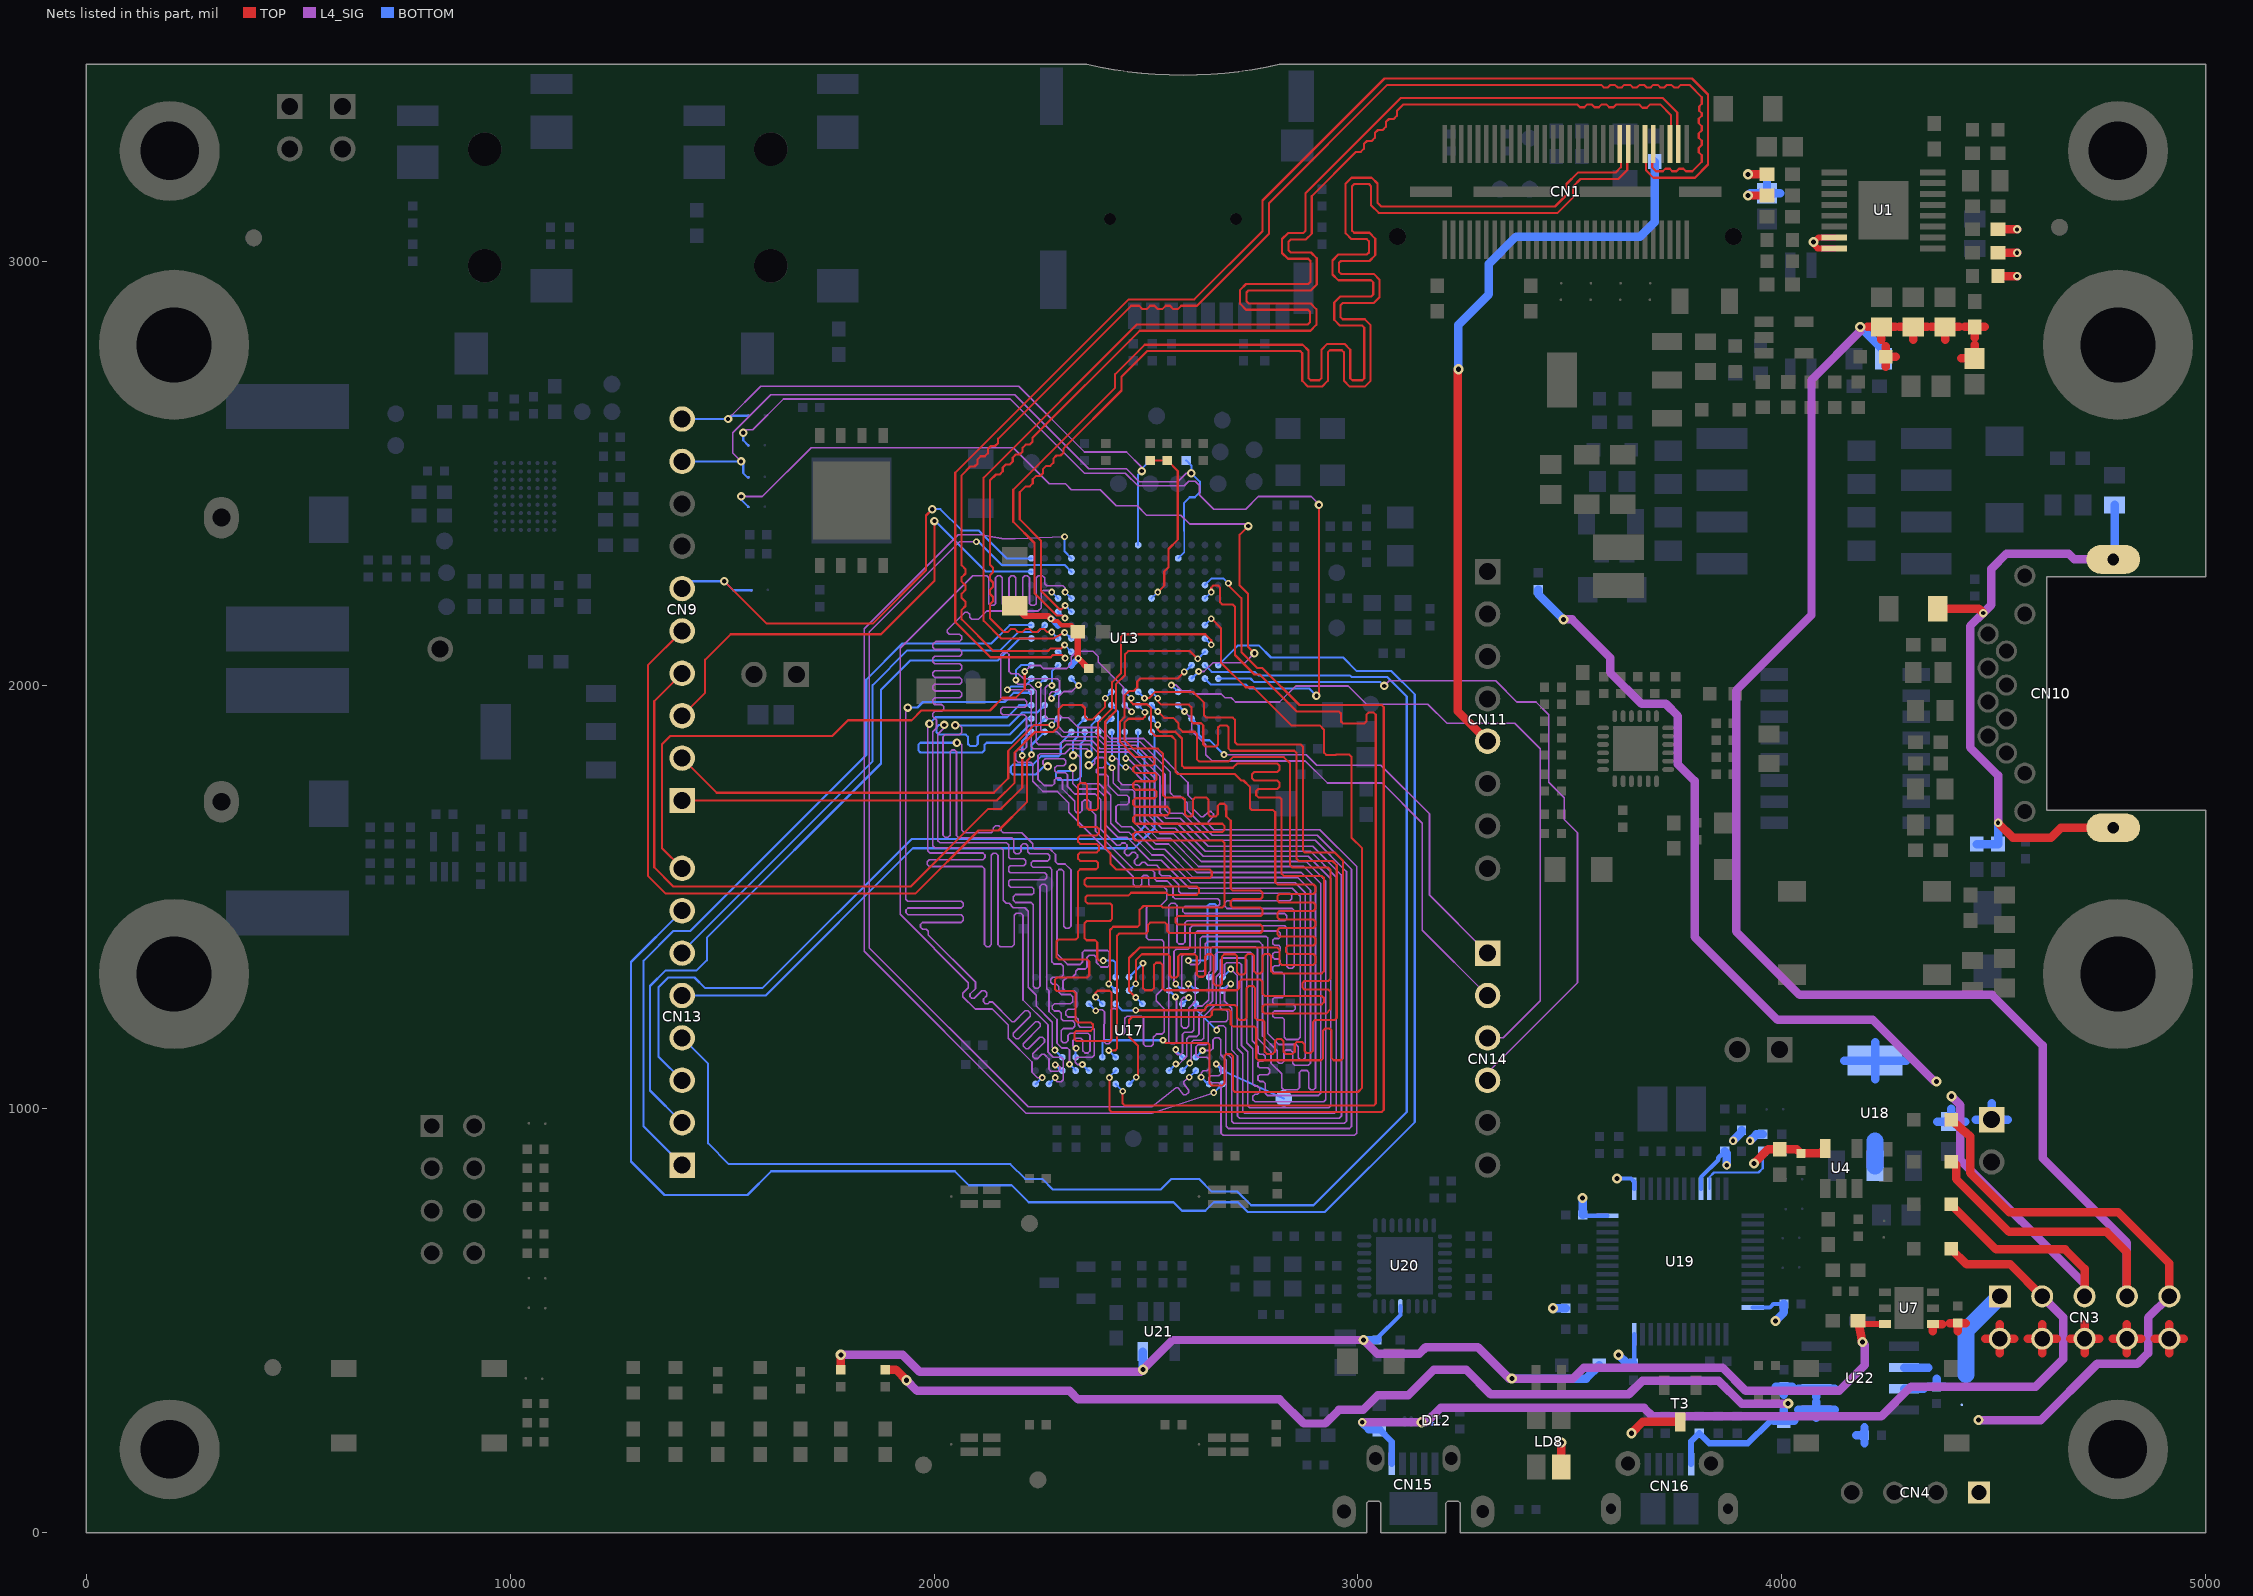
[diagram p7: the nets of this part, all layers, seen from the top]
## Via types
v1: diameter 20, hole 10, TOP to BOTTOM, 354 vias
v2: diameter 24, hole 12, TOP to BOTTOM, 349 vias
v3: diameter 16, hole 8, TOP to BOTTOM, 219 vias
v4: diameter 12, hole 6, TOP to BOTTOM, 27 vias

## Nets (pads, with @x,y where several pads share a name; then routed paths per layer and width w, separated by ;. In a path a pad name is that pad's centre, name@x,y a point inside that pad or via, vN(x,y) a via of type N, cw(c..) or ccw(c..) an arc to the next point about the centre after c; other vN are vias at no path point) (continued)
3V3_ST_LINK: C41.1 C42.2 C140.1 C143.2 C146.2 C151.2 CN4.1 LD8.4 R118.2 R120.1 R138.2 T3.3 U4.5 U19.1 U19.9 U19.24 U19.36 U19.48 | length 1019.4
  TOP w20: LD8.4@3479.53,155.94 v2(3479.53,213) ; v2(3645,235) 3671.69,261.69 T3.3@3760,261.69 ; v2(3933.98,871.31) 3967.67,905 C41.1@3995,905 4035,905 C42.2@4045,895 4090.36,895 U4.5@4102.6,907.24
  BOTTOM w10: C143.2@3530,750 3531.73,748.27 U19.48@3588.74,748.27 ; v2(3611,836) 3644,836 3651.73,828.27 U19.1@3651.73,811.26 ; C151.2@3650,400 3651.73,401.73 U19.36@3651.73,468.74 ; U19.9@3809.21,811.26 3809.21,839.21 3850,880 3850,885 C140.1@3865,900 ; U19.24@3931.26,531.73 3971.73,531.73 3980,540 C146.2@4005,540
  BOTTOM w20: v2(3460,530) R138.2@3490,530 ; C143.2@3530,750 v2(3530,790) ; v2(3615,420) 3635,400 C151.2@3650,400 ; C140.1@3865,900 3870,895 v1(3870,867.5) ; v1(3885,925) 3905,945 R118.2@3905,950 ; v1(3925,925) 3940,940 R120.1@3955,940 ; v2(3985,500) 4005,520 C146.2@4005,540
5V: C50.2 C51.2 C150.1 CN3.2 CN3.4 CN3.6 CN3.8 CN3.10 CN11.5 D11.1 L4.1 R58.1 U7.1 U7.6 U20.21 U21.5 | length 5713.9
  TOP w15: C51.2@4180,500 4197.4,492.6 U7.6@4243.48,492.6
  TOP w20: R58.1@1780,385 v2(1780,420) ; v2(3237,2745) 3235,2743 3235,1938.5 CN11.5@3305.8,1867.7 ; C51.2@4180,500 v2(4190,450) ; 4356.52,475.58 U7.1@4356.52,492.6 4378.54,492.6 ; 4395.98,495 C50.2@4415,495 ; 4415,475.98 C50.2@4415,495 ; 4434.02,495 C50.2@4415,495 ; 4480.2,458 CN3.2@4514.22,458 ; 4514.22,423.98 CN3.2@4514.22,458 ; 4514.22,492.02 CN3.2@4514.22,458 ; 4548.24,458 CN3.2@4514.22,458 ; 4580.2,458 CN3.4@4614.22,458 ; 4614.22,423.98 CN3.4@4614.22,458 ; 4614.22,492.02 CN3.4@4614.22,458 ; 4648.24,458 CN3.4@4614.22,458 ; 4680.2,458 CN3.6@4714.22,458 ; 4714.22,423.98 CN3.6@4714.22,458 ; 4714.22,492.02 CN3.6@4714.22,458 ; 4748.24,458 CN3.6@4714.22,458 ; 4780.2,458 CN3.8@4814.22,458 ; 4814.22,423.98 CN3.8@4814.22,458 ; 4814.22,492.02 CN3.8@4814.22,458 ; 4848.24,458 CN3.8@4814.22,458 ; 4880.2,458 CN3.10@4914.22,458 ; 4914.22,423.98 CN3.10@4914.22,458 ; 4914.22,492.02 CN3.10@4914.22,458 ; 4948.24,458 CN3.10@4914.22,458
  L4_SIG w20: v2(1780,420) 1926,420 1966,380 2487.6,380 v2(2492.6,385) 2562.6,455 v2(3013,455) 3045,423 3145,423 3160,438 3283,438 3357,364 v2(3363,364) 3507,364 3533,390 3860,390 3915,335 4135,335 4196,396 4196,444 v2(4190,450)
  BOTTOM w10: C150.1@3045,455 3045,459 3100.16,514.16 U20.21@3100.16,534.72
  BOTTOM w20: v2(2492.6,385) U21.5@2492.6,427.76 ; v2(3013,455) C150.1@3045,455 ; v2(3237,2745) 3237,2850 3309,2922 3309,2994 3373,3058 3666,3058 3700,3092 L4.1@3700,3235 ; v2(3363,364) 3538.29,364 D11.1@3569.29,395
5V_POE: C13.2 C14.2 C15.2 C16.2 CN3.7 D6.1 R11.2 R16.2 R84.2 | length 4278.5
  TOP w20: 4201.98,2845 C13.2@4235,2845 ; 4235,2814.48 C13.2@4235,2845 ; 4245,2750.98 R11.2@4245,2775 ; 4245,2799.02 R11.2@4245,2775 ; 4268.02,2845 C13.2@4235,2845 ; 4268.52,2775 R11.2@4245,2775 ; 4276.98,2845 C14.2@4310,2845 ; 4310,2814.48 C14.2@4310,2845 ; 4343.02,2845 C14.2@4310,2845 ; 4351.98,2845 C15.2@4385,2845 ; 4385,2814.48 C15.2@4385,2845 ; D6.1@4399.29,875 4411,868.29 4411,835 4536,710 4766,710 4814.22,661.78 CN3.7@4814.22,558 ; 4418.02,2845 C15.2@4385,2845 ; 4423.48,2770.51 R16.2@4455,2770.51 4455,2803.03 ; 4430.98,2845 C16.2@4455,2845 ; 4455,2819.48 C16.2@4455,2845 ; 4479.02,2845 C16.2@4455,2845
  L4_SIG w20: v2(4185,2845) 4185,2835 4070,2720 4070,2165 3892,1987 3892,1419 4042,1269 4496,1269 4615,1150 4615,884 4814.22,684.78 CN3.7@4814.22,558
  BOTTOM w20: v2(4185,2845) 4240,2790 R84.2@4240,2770
5V_ST_LINK: C152.2 CN3.1 SB23.2 U22.6 U22.7 | length 378.7
  BOTTOM w20: U22.7@4288.3,340 4335,340 ; U22.6@4288.3,390 4345.98,390 ; 4345.98,345 C152.2@4365,345 ; 4365,364.02 C152.2@4365,345 ; 4384.02,345 C152.2@4365,345
  BOTTOM w40: 4434,374 4434,477.78 CN3.1@4514.22,558
5V_USB_CHARGER: C155.2 CN3.9 CN16.1 D5.1 R59.2 R144.2 R147.2 R150.2 SB23.1 U22.1 U22.2 | length 4390.4
  TOP w20: R59.2@1885,385 1910,385 v2(1935,360) ; D5.1@4399.29,975 4444,935.29 4444,849 4537,756 4794,756 4914.22,635.78 CN3.9@4914.22,558
  L4_SIG w20: v2(1935,360) 1960,335 2320,335 2340,315 2815,315 2872,258 2923,258 2955,290 3012,290 3047,325 3119,325 3179,385 3255,385 3313,327 3639,327 3671,359 3851,359 3905,305 v2(4015,305) ; v2(4464,266) 4611,266 4744,399 4839,399 4864,424 4864,507.78 CN3.9@4914.22,558
  BOTTOM w14: CN16.1@3786.18,162.4 3786.18,216.18 R147.2@3805,235
  BOTTOM w15: R147.2@3805,235 3829,211 3920,211 3970,261
  BOTTOM w20: 3980.98,265 C155.2@4005,265 ; 3985.98,345 R144.2@4005,345 ; 4005,290.52 C155.2@4005,265 ; 4005,325.98 R144.2@4005,345 ; 4024.02,345 R144.2@4005,345 ; 4029.02,265 C155.2@4005,265 ; 4038.68,290 U22.1@4081.7,290 ; 4038.68,340 U22.2@4081.7,340 ; 4081.7,270.98 U22.1@4081.7,290 ; 4081.7,309.02 U22.1@4081.7,290 ; 4081.7,320.98 U22.2@4081.7,340 ; 4124.72,290 U22.1@4081.7,290 ; 4124.72,340 U22.2@4081.7,340 ; 4175.98,230 R150.2@4195,230 ; 4195,210.98 R150.2@4195,230 ; 4195,249.02 R150.2@4195,230
5V_USB_HS: CN3.3 CN15.1 D8.1 D12.A1 L7.2 | length 2332.1
  TOP w20: D8.1@4399.29,670 4436.15,633.14 4539.08,633.14 CN3.3@4614.22,558
  L4_SIG w20: v1(3010,261) v2(3150,261) 3161.03,261 3194.98,295 3675,295 3695,275 4235,275 4305,345 4599,345 4664,410 4664,508.22 CN3.3@4614.22,558
  BOTTOM w8: v2(3150,261) 3153.87,257.13 D12.A1@3177.13,257.13
  BOTTOM w15: L7.2@3050,245 3079.69,215.31 CN15.1@3079.69,162.8
  BOTTOM w20: v1(3010,261) 3026,245 L7.2@3050,245
AGND: C6.1 C7.1 C10.2 C11.2 R6.2 R74.2 U1.15 U1.16 | length 447.6
  TOP w14: U1.16@4123.86,3030.43 4084.57,3030.43 4075,3040 v2(4075,3045) 4086.02,3056.02 U1.15@4123.86,3056.02
  TOP w20: v2(3920,3155) C7.1@3965,3155 ; v2(3920,3205) C6.1@3965,3205 ; R6.2@4510,2965 v1(4555,2965) ; C11.2@4510,3020 v1(4555,3020) ; C10.2@4510,3075 v1(4555,3075)
  BOTTOM w20: v2(3920,3155) 3925.51,3160.51 R74.2@3965,3160.51 ; 3965,3193.03 R74.2@3965,3160.51 ; 3996.52,3160.51 R74.2@3965,3160.51
AIN_1: R119.2 R120.2 U19.10 | length 247.5
  BOTTOM w5: U19.10@3828.9,811.26 3828.9,838.9 3840,850 3945,850 3955,860 R120.2@3955,900 R119.2@4000,900
ARD_A0: CN14.1 U13.P3 | length 1051.7
  L4_SIG w4: v3(2684,1836) 2878,1836 2903,1811 3054,1811 3169,1696 3169,1504.5 CN14.1@3305.8,1367.7
  BOTTOM w5: U13.P3@2607.48,1921.02 2624.48,1904.02 2624.48,1883.52 2638,1870 2650,1870 v3(2684,1836)
ARD_A1: CN14.2 U13.N4 | length 1191.6
  L4_SIG w4: v3(2590.83,1937.67) 2608,1920.5 2608,1892 2641,1859 2641,1836 2656,1821 2876,1821 2928,1769 3057,1769 3152,1674 3152,1421.5 CN14.2@3305.8,1267.7
  BOTTOM w5: U13.N4@2575.98,1952.52 v3(2590.83,1937.67)
ARD_A2: CN14.3 U13.M4 | length 1741.6
  L4_SIG w4: v3(2560,2000) 2571.41,2000 2585.2,1986.21 2605.47,1986.21 2612.68,1979 2677.22,1979 2686.2,1970.02 2700.98,1970.02 2711,1960 2815,1960 2853,1998 2977,1998 3020,1955 3165,1955 3210,1910 3370,1910 3430,1850 3430,1255 3342.7,1167.7 CN14.3@3305.8,1167.7
  BOTTOM w5: v3(2560,2000) U13.M4@2575.98,1984.02
ARD_A3: CN14.4 U13.L1 | length 1803.3
  L4_SIG w4: v1(3062,1998) 3074,2010 3325,2010 3375,1960 3420,1960 3450,1930 3450,1771 3487,1734 3487,1683 3518,1652 3518,1298 3305.8,1085.8 CN14.4@3305.8,1067.7
  BOTTOM w5: U13.L1@2670.47,2015.51 2746.49,2015.51 2755,2007 3053,2007 v1(3062,1998)
ARD_A4: SB14.1 U13.L3 | length 1847.5
  TOP w5: v1(2741,2375) 2721,2355 2721,2235 2741,2215 2741,2089.77 v1(2755.75,2075.02)
  L4_SIG w4: v1(1545,2445) 1595,2445 1710,2560 2187,2560 2272,2475 2310,2475 2324,2461 2392,2461 2430,2423 2479,2423 2501.16,2400.84 2582.16,2400.84 2603,2380 2736,2380 v1(2741,2375) ; v3(2624,2032) 2637,2032 2658,2053 2733.73,2053 v1(2755.75,2075.02)
  BOTTOM w5: v1(1545,2445) 1545,2437.32 SB14.1@1561.99,2420.33 ; U13.L3@2607.48,2015.51 2616.96,2024.99 ; 2616.99,2024.99 v3(2624,2032)
ARD_A5: SB12.1 U13.L2 | length 2310.3
  TOP w5: v1(2902,1975) 2903,1975 2908,1980 v1(2908,2425.01)
  L4_SIG w4: v1(1550,2595) 1557.5,2602.5 1572.5,2602.5 1645,2675 2180,2675 2355,2500 2451.22,2500 2481.22,2470 2590,2470 2601,2481 2616.05,2481 2626,2471.05 2626,2449 2660,2415 2735,2415 2765,2445 2890,2445 2908,2427 v1(2908,2425.01)
  BOTTOM w5: v1(1550,2595) 1550,2577.32 SB12.1@1561.99,2565.33 ; U13.L2@2638.98,2015.51 2653.49,2001 2736,2001 2745,1992 2885,1992 v1(2902,1975)
ARD_D0: CN13.1 U13.G15 | length 1866.6
  BOTTOM w5: CN13.1@1405.8,867.7 1315,958.5 1315,1350 1385,1420 1425,1420 1840,1835 1840,2013 1925,2098 2135,2098 2178.5,2141.5 U13.G15@2229.53,2141.5
ARD_D1: CN13.2 U13.H15 | length 1725.9
  BOTTOM w5: CN13.2@1405.8,967.7 1330,1043.5 1330,1290 1367,1327 1440,1327 1464,1351 1464,1404 1875,1815 1875,1989 1944,2058 2150,2058 2202,2110 U13.H15@2229.53,2110
ARD_D2: CN13.3 U13.R7 | length 1795.4
  BOTTOM w5: CN13.3@1405.8,1067.7 1350,1123.5 1350,1287 1373,1310 1435,1310 1460,1285 1595,1285 1947,1637 2466,1637 2496.35,1667.35 2496.35,1827.65 2481.5,1842.5 U13.R7@2481.5,1889.53
ARD_D3: CN13.4 U13.K2 | length 3581
  BOTTOM w5: CN13.4@1405.8,1167.7 1467,1106.5 1467,919 1516,870 2180,870 2215,835 2255,835 2280,810 2535,810 2560,835 2625,835 2655,805 2716,805 2748,773 2895,773 3115,993 3115,1973 3069,2019 2985,2019 2981,2023 2765,2023 2756.9,2031.1 2654.89,2031.1 U13.K2@2638.98,2047.01
ARD_D4: CN13.5 U13.R6 | length 1507.4
  BOTTOM w5: CN13.5@1405.8,1267.7 1602.7,1267.7 1950,1615 2472,1615 2520,1663 2520,1882.52 U13.R6@2512.99,1889.53
ARD_D5: CN13.6 U13.G14 | length 1283
  BOTTOM w5: CN13.6@1405.8,1367.7 1405.8,1370.8 1855,1820 1855,2000 1937,2082 2156,2082 2199,2125 2244.52,2125 U13.G14@2261.02,2141.5
ARD_D6: CN13.7 U13.K1 | length 4230
  BOTTOM w5: CN13.7@1405.8,1467.7 1285,1346.9 1285,876 1364,797 1560,797 1616,853 2049,853 2082,820 2183,820 2223,780 2565,780 2585,760 2640,760 2660,780 2717,780 2740,757 2922,757 3134,969 3134,1978 3079,2033 2997,2033 2965,2065 2795,2065 2767,2093 2716.46,2093 U13.K1@2670.47,2047.01
ARD_D7: CN13.8 U13.N8 | length 1663.7
  TOP w5: CN13.8@1405.8,1567.7 1358,1615.5 1358,1860 1378,1880 1760,1880 1797,1917 1947,1917 1970,1940 2132,1940 2162,1970 2193,1970 2214,1991 v3(2214,2032)
  L4_SIG w4: v3(2214,2032) 2228,2046 2251,2046 2258,2039 2313,2039 2324,2050 2324,2067 2337,2080 2375,2080 2387.5,2067.5 2387.5,2054.5 2447,1995 2447,1955 2465,1937 v3(2466,1937)
  BOTTOM w4: U13.N8@2450,1952.52 2450.48,1952.52 v3(2466,1937)
ARD_D8: CN9.1 U13.M9 | length 1237
  TOP w5: CN9.1@1405.8,1727.7 2147.7,1727.7 2190,1770 2190,1841 2238.25,1889.25 2281.26,1889.25 2294,1901.99 2294,1942.99 2304.01,1953 2349,1953 2356,1946 2356,1925 2362,1919 2374,1919 2403.65,1948.65 v3(2403.65,1969.17)
  BOTTOM w5: v3(2403.65,1969.17) U13.M9@2418.5,1984.02
ARD_D9: CN9.2 U13.P13 | length 1031
  TOP w5: CN9.2@1405.8,1827.7 1487.5,1746 2141,1746 2175.08,1780.08 2175.08,1844.92 2236.33,1906.17 v3(2277.67,1906.17)
  BOTTOM w5: v3(2277.67,1906.17) U13.P13@2292.52,1921.02
ARD_D10: CN9.3 U13.C15 | length 1191.8
  TOP w5: CN9.3@1405.8,1927.7 1460,1981.9 1460,2060 1520,2120 1875,2120 2001,2246 v1(2001,2387)
  BOTTOM w5: v1(2001,2387) 2003,2387 2122,2268 2229.01,2268 U13.C15@2229.53,2267.48
ARD_D11: CN9.4 U13.R15 | length 1608.6
  TOP w5: CN9.4@1405.8,2027.7 1340,1961.9 1340,1570 1385,1525 1945,1525 2128,1708 2158,1708 2208,1758 v3(2208,1834)
  BOTTOM w5: v3(2208,1834) 2208,1868 U13.R15@2229.53,1889.53
ARD_D12: CN9.5 U13.R14 | length 1795
  TOP w5: CN9.5@1405.8,2127.7 1325,2046.9 1325,1550 1367,1508 1956,1508 2105,1657 2152,1657 2219,1724 2219,1821 2230,1832 v3(2230,1836)
  BOTTOM w5: v3(2230,1836) 2230,1858.51 U13.R14@2261.02,1889.53
ARD_D13: CN9.6 SB15.2 U13.B15 | length 1180.7
  TOP w5: v1(1505,2245) 1605,2145 1855,2145 1981,2271 1981,2400 v1(1996,2415)
  BOTTOM w5: CN9.6@1405.8,2227.7 1423.1,2245 v1(1505,2245) 1526.19,2223.81 SB15.2@1569.17,2223.81 ; v1(1996,2415) 2015,2415 2065,2365 2105,2365 2171.02,2298.98 U13.B15@2229.53,2298.98
ARD_D14: CN9.9 R89.2 SB13.1 U13.B4 | length 1745.1
  L4_SIG w4: v1(1544.67,2527.7) 1525,2547.37 1525,2595 1615,2685 2190,2685 2365,2510 2453.95,2510 2483.95,2480 2575,2480 2595,2500 v1(2607,2500)
  BOTTOM w4: U13.B4@2575.98,2298.98 2590,2313 2590,2364
  BOTTOM w5: CN9.9@1405.8,2527.7 v1(1544.67,2527.7) 1550,2522.37 1550,2500 1559.67,2490.33 SB13.1@1561.99,2490.33 ; 2590,2364 2590,2430 2603,2443 2615,2443 2627,2455 2627,2480 v1(2607,2500) 2607,2518 R89.2@2595,2530
ARD_D15: CN9.10 R91.2 SB11.1 U13.A7 | length 1466.8
  L4_SIG w4: v1(1514,2627.7) 1591.3,2705 2200,2705 2355,2550 2454,2550 2490,2514 v1(2490,2505)
  BOTTOM w5: CN9.10@1405.8,2627.7 v1(1514,2627.7) 1521.63,2635.33 SB11.1@1561.99,2635.33 ; U13.A7@2481.5,2330.47 2481.5,2496.5 v1(2490,2505) 2490,2510 R91.2@2510,2530
BOOT0: R18.2 R19.2 U13.E6 | length 401.6
  TOP w5: R18.2@2510,2530 R19.2@2550,2530 2575,2505 2575,2343 2553,2321 2553,2278 2543,2268 2543,2234.5 v3(2527.84,2219.34)
  BOTTOM w4: U13.E6@2512.99,2204.49 v3(2527.84,2219.34)
CHASSIS: C89.1 C121.1 C122.2 CN10.13 CN10.14 R96.1 | length 1592.4
  TOP w20: C89.1@4368,2180 4465,2180 v1(4475,2170) ; v1(4510,1675) 4545,1640 4635,1640 4658.46,1663.46 CN10.14@4781.85,1663.46
  L4_SIG w20: v1(4510,1675) 4510,1787 4444,1853 4444,2139 v1(4475,2170) 4494,2189 4494,2274 4530,2310 4676.54,2310 4690,2296.54 CN10.13@4781.85,2296.54
  BOTTOM w20: C122.2@4460,1625 C121.1@4510,1625 v1(4510,1675) ; CN10.13@4781.85,2296.54 4785,2299.69 R96.1@4785,2425
DSI.DSI_CK_N: CN1.5 U13.H13 | length 3263.4
  TOP w5.1: v3(2277.5,2125) 2267,2125 2260,2132 2249.79,2132 2242.79,2125 2232.59,2125 2225.59,2132 2215.39,2132 2208.39,2125 2198.19,2125 2191.19,2132 2180.99,2132 2173.99,2125 2165,2125 2132,2158 2132,2190.52 2139,2197.52 2139,2207.72 2132,2214.72 2132,2224.92 2139,2231.92 2139,2242.12 2132,2249.12 2132,2259.32 2139,2266.32 2139,2276.52 2132,2283.52 2132,2483 2145.93,2496.93 2154.93,2496.93 2162.14,2504.14 2162.14,2513.14 2169.35,2520.35 2178.35,2520.35 2185.56,2527.56 2185.56,2536.56 2192.77,2543.77 2201.77,2543.77 2208.98,2550.98 2208.98,2559.98 2216.19,2567.19 2225.19,2567.19 2232.4,2574.4 2232.4,2583.4 2485,2836 2888.22,2836 2902,2849.78 2902,2886.76 2888.22,2900.54 2742,2900.54 2737,2905.54 2737,2926.14 2742,2931.14 2889.22,2931.14 2903,2944.92 2903,3006.86 2889.22,3020.64 2841.1,3020.64 2836,3025.74 2836,3046.14 2841.1,3051.24 2877.12,3051.24 2891,3065.12 2891,3153.52 2995.29,3257.81 3006.81,3257.81 3014.02,3265.02 3014.02,3276.54 3021.23,3283.75 3032.75,3283.75 3039.96,3290.96 3039.96,3302.48 3047.17,3309.69 3058.69,3309.69 3065.9,3316.9 3065.9,3328.42 3073.11,3335.63 3084.63,3335.63 3091.84,3342.84 3091.84,3354.36 3107.48,3370 3516.78,3370 3523.78,3363 3533.98,3363 3540.98,3370 3551.18,3370 3558.18,3363 3568.38,3363 3575.38,3370 3585.58,3370 3592.58,3363 3602.78,3363 3609.78,3370 3663.01,3370 3671.01,3362 3681.21,3362 3689.21,3370 3713,3370 3738.39,3344.61 3738.39,3321 3736.05,3318.66 CN1.5@3736.05,3276.53
  BOTTOM w5.1: v3(2277.5,2125) U13.H13@2292.52,2110
DSI.DSI_CK_P: CN1.3 U13.H12 | length 3265
  TOP w5.1: v3(2308,2124) 2281,2110 2158.78,2110 2117,2151.78 2117,2489.22 2478.78,2851 2882,2851 2887,2856 2887,2880.54 2882,2885.54 2735.78,2885.54 2722,2899.32 2722,2932.36 2735.78,2946.14 2883,2946.14 2888,2951.14 2888,3000.64 2883,3005.64 2834.88,3005.64 2821,3019.52 2821,3052.36 2834.88,3066.24 2870.9,3066.24 2876,3071.34 2876,3159.74 3101.26,3385 3719.22,3385 3753.39,3350.83 3753.39,3321 3755.74,3318.65 CN1.3@3755.74,3276.53
  BOTTOM w5.1: v3(2308,2124) U13.H12@2324.02,2110
DSI.DSI_D0_N: CN1.11 U13.J13 | length 3288
  TOP w5.1: v3(2309.17,2063.65) 2301.82,2071 2280.67,2071 2275.22,2065.55 2133.23,2065.55 2050,2148.78 2050,2501 2459,2910 2614,2910 2775,3071 2775,3143.22 3062.78,3431 3788.22,3431 3826,3393.22 3826,3228 3795,3197 3697,3197 3679.34,3214.66 3679.34,3231.66 3677,3234 CN1.11@3677,3276.53
  BOTTOM w4: U13.J13@2292.52,2078.5 2294.32,2078.5 v3(2309.17,2063.65)
DSI.DSI_D0_P: CN1.9 U13.J12 | length 3284.5
  TOP w5.1: v3(2308,2094.52) 2299.48,2086 2274.45,2086 2269,2080.55 2139.45,2080.55 2065,2155 2065,2177.44 2074,2186.44 2074,2196.64 2065,2205.64 2065,2215.84 2074,2224.84 2074,2235.04 2065,2244.04 2065,2254.24 2074,2263.24 2074,2273.44 2065,2282.44 2065,2494.78 2085.76,2515.54 2095.54,2515.54 2102.76,2522.76 2102.76,2532.54 2109.98,2539.76 2119.76,2539.76 2126.98,2546.98 2126.98,2556.76 2134.2,2563.98 2143.98,2563.98 2151.2,2571.2 2151.2,2580.98 2465.22,2895 2483.78,2895 2491.78,2887 2501.98,2887 2509.98,2895 2520.18,2895 2528.18,2887 2538.38,2887 2546.38,2895 2556.58,2895 2564.58,2887 2574.78,2887 2582.78,2895 2620.22,2895 2790,3064.78 2790,3137 3069,3416 3573.8,3416 3579.8,3410 3590,3410 3596,3416 3606.2,3416 3612.2,3410 3622.4,3410 3628.4,3416 3642.29,3416 3648.29,3410 3658.49,3410 3664.49,3416 3674.69,3416 3680.69,3410 3690.89,3410 3696.89,3416 3707.09,3416 3713.09,3410 3723.29,3410 3729.29,3416 3739.49,3416 3745.49,3410 3755.69,3410 3761.69,3416 3782,3416 3811,3387 3811,3371.06 3805,3365.06 3805,3354.86 3811,3348.86 3811,3342.92 3804,3335.92 3804,3325.72 3811,3318.72 3811,3308.52 3804,3301.52 3804,3291.32 3811,3284.32 3811,3274.12 3804,3267.12 3804,3256.92 3811,3249.92 3811,3234.22 3788.78,3212 3773.8,3212 3767.8,3218 3757.6,3218 3751.6,3212 3741.4,3212 3735.4,3218 3725.2,3218 3719.2,3212 3703.22,3212 3694.34,3220.88 3694.34,3234 3696.68,3236.34 CN1.9@3696.68,3276.53
  BOTTOM w4: v3(2308,2094.52) U13.J12@2324.02,2078.5
DSI.DSI_D1_N: CN1.17 U13.F13 | length 3220.4
  TOP w5.1: v3(2309,2158) 2303,2164 2289.78,2164 2237,2216.78 2237,2335 2187,2385 2187,2461 2427.22,2701.22 2427.22,2733.44 2496.78,2803 2869.59,2803 2883.47,2789.12 2883.47,2724 2888.47,2719 2909.07,2719 2914.07,2724 2914.07,2791.22 2927.85,2805 2968.22,2805 2982,2791.22 2982,2724 2987,2719 3010,2719 3015,2724 3015,2843 3010,2848 2957.78,2848 2944,2861.78 2944,2902.62 2957.78,2916.4 3031,2916.4 3036,2921.4 3036,2950 3031,2955 2953.78,2955 2940,2968.78 2940,3001.82 2953.78,3015.6 3021,3015.6 3026,3020.6 3026,3047 3021,3052 2984.78,3052 2971,3065.78 2971,3183.22 2984.78,3197 3032.22,3197 3046,3183.22 3046,3138.22 3055.22,3129 3464.78,3129 3492,3156.22 3492,3182.22 3518.78,3209 3607.78,3209 3620.28,3221.5 3620.28,3232 3617.94,3234.34 CN1.17@3617.94,3276.53
  BOTTOM w5.1: U13.F13@2292.52,2172.99 v3(2309,2158)
DSI.DSI_D1_P: CN1.15 U13.F12 | length 3218.5
  TOP w5.1: v3(2309.17,2187.84) 2300.33,2179 2296,2179 2252,2223 2252,2341.22 2202,2391.22 2202,2454.78 2216.01,2468.79 2225.79,2468.79 2233.01,2476.01 2233.01,2485.79 2240.23,2493.01 2250.01,2493.01 2257.23,2500.23 2257.23,2510.01 2264.45,2517.23 2274.23,2517.23 2281.45,2524.45 2281.45,2534.23 2288.67,2541.45 2298.45,2541.45 2305.67,2548.67 2305.67,2558.45 2442.22,2695 2442.22,2727.22 2503,2788 2863.37,2788 2868.47,2782.9 2868.47,2717.78 2882.25,2704 2915.29,2704 2929.07,2717.78 2929.07,2785 2934.07,2790 2962,2790 2967,2785 2967,2717.78 2980.78,2704 3016.22,2704 3030,2717.78 3030,2849.22 3016.22,2863 2964,2863 2959,2868 2959,2896.4 2964,2901.4 3037.22,2901.4 3051,2915.18 3051,2956.22 3037.22,2970 2960,2970 2955,2975 2955,2995.6 2960,3000.6 3027.22,3000.6 3041,3014.38 3041,3053.22 3027.22,3067 2991,3067 2986,3072 2986,3177 2991,3182 3026,3182 3031,3177 3031,3132 3049,3114 3471,3114 3507,3150 3507,3176 3525,3194 3614,3194 3635.28,3215.28 3635.28,3232 3637.63,3234.35 CN1.15@3637.63,3276.53
  BOTTOM w5.1: v3(2309.17,2187.84) U13.F12@2324.02,2172.99
DSI_VDD12: C23.2 C25.2 C27.2 U13.G13 U13.K12 | length 317.9
  TOP w10: v3(2276,2156.35) 2281.35,2151 2291,2151 2301,2141 2324,2141 C25.2@2339,2126
  TOP w15: C23.2@2190,2187 2214,2163 2269.35,2163 v3(2276,2156.35) ; C25.2@2339,2126 2339,2064 v3(2340,2063) 2364,2039 C27.2@2365,2039
  BOTTOM w15: v3(2276,2156.35) 2277.67,2156.35 U13.G13@2292.52,2141.5 ; U13.K12@2324.02,2047.01 v3(2340,2063)
E5V: C139.2 CN3.5 D7.1 JP1.1 R103.2 U18.2 U18.4 | length 3276.8
  TOP w20: D7.1@4399.29,775 4505.65,668.64 4668.36,668.64 4714.22,622.78 CN3.5@4714.22,558
  L4_SIG w20: v2(3485,2155) 3505,2155 3595,2065 3595,2030 3669,1956 3726,1956 3755,1927 3755,1813 3794,1774 3794,1406 3990,1210 4215,1210 4360,1065 v2(4365,1065) ; v2(4400,1030) 4421,1009 4421,880 4714.22,586.78 CN3.5@4714.22,558
  BOTTOM w20: R103.2@3425,2225 3425,2215 v2(3485,2155) ; 4146.98,1114.02 U18.4@4220,1114.02 ; 4220,1070.5 U18.4@4220,1114.02 ; 4220,1157.54 U18.4@4220,1114.02 ; 4293.02,1114.02 U18.4@4220,1114.02 ; 4366.98,970 C139.2@4400,970 ; 4400,1000.52 C139.2@4400,970 ; 4433.02,970 C139.2@4400,970 ; 4456.98,975 JP1.1@4495,975 ; 4495,1013.02 JP1.1@4495,975 ; 4533.02,975 JP1.1@4495,975
  BOTTOM w40: U18.2@4220,865.98 4220,925
FMC_A0: U13.D2 U17.G8 | length 2331.5
  TOP w5: v3(2413.65,1074) 2413.65,998 2418.65,993 3056,993 3061,998 3061,1948 3056,1953 2862,1953 2775,2040 2763,2040 2725,2078 2725,2205 2694.36,2235.64 v3(2694.36,2240)
  BOTTOM w5: v3(2413.65,1074) 2413.65,1075.66 U17.G8@2428.5,1090.51 ; U13.D2@2638.98,2235.98 2654.83,2251.83 2682.53,2251.83 v3(2694.36,2240)
FMC_A1: U13.E2 U17.G9 | length 2248.6
  TOP w5: v3(2445,1042) 2445,1013 2450,1008 3037,1008 3042,1013 3042,1930 3037,1935 3025,1935 3020,1930 3020,1914 3015,1909 2965,1909 2960,1914 2960,1933 2955,1938 2855,1938 2768,2025 2756,2025 2710,2071 2710,2185 2705,2190 2680,2190 2675,2195 2675,2230 2670,2235 2658.83,2235 2653.83,2230 v3(2653.83,2219.34)
  BOTTOM w5: U17.G9@2428.5,1059.02 2428.5,1058.5 v3(2445,1042) ; U13.E2@2638.98,2204.49 v3(2653.83,2219.34)
FMC_A2: U13.G2 U17.F7 | length 2263.1
  TOP w5: v3(2540,1162) 2546,1156 2645,1156 2650,1151 2650,1060 2655,1055 2680,1055 2685,1060 2685,1125 2690,1130 2700,1130 2705,1125 2705,1045 2710,1040 3000,1040 3010,1050 3010,1615 2984.5,1640.5 2984.5,1831 2979.5,1836 2948.58,1836 2948.08,1835.5 2925,1835.5 2920,1840.5 2920,1895 2910,1905 2843,1905 2753,1995 2735,1995 2677,2053 2677,2134.35 2655,2156.35 v3(2653.83,2156.35)
  BOTTOM w5: U17.F7@2397.01,1122.01 2397.01,1157 2402.01,1162 v3(2540,1162) ; U13.G2@2638.98,2141.5 v3(2653.83,2156.35)
FMC_A3: U13.H2 U17.F3 | length 2226.7
  TOP w5: v3(2381,1264) 2381,1274 2386,1279 2414,1279 2419,1274 2419,1165 2414,1160 2336,1160 2331,1165 2331,1179.29 2336,1184.29 2370,1184.29 2375,1189.29 2375,1199.29 2370,1204.29 2339,1204.29 2334,1209.29 2334,1273 2329,1278 2290,1278 2285,1283 2285,1305 2290,1310 2361,1310 2366,1315 2366,1348 2361,1353 2294,1353 2289,1358 2289,1395 2294,1400 2315.78,1400 2328.21,1399.99 2335,1400 2340,1405 2340,1560.44 2345,1565.44 2382,1565.44 2387,1570.44 2387,1580.44 2382,1585.44 2345,1585.44 2340,1590.44 2340,1600.44 2345,1605.44 2384,1605.44 2389,1610.44 2389,1620.44 2384,1625.44 2345,1625.44 2340,1630.44 2340,1640.44 2345,1645.44 2384,1645.44 2389,1650.44 2389,1660.44 2384,1665.44 2345,1665.44 2340,1670.44 2340,1764 2345,1769 2356,1769 2361,1764 2361,1710 2366,1705 2382,1705 2387,1710 2387,1912 2420,1945 2420,2007 2441.35,2028.35 2441.35,2115 2446.35,2120 2640,2120 2653.83,2106.17 v3(2653.83,2095.15)
  BOTTOM w5: v3(2381,1264) U17.F3@2397.01,1247.99 ; U13.H2@2638.98,2110 v3(2653.83,2095.15)
FMC_A4: U13.J2 U17.G1 | length 2221.5
  TOP w5: v3(2399,1350) 2390,1350 2385,1355 2385,1393 2380,1398 2360,1398 2355,1403 2355,1438.5 2360,1443.5 2415,1443.5 2420,1448.5 2420,1480 2415,1485 2362,1485 2357,1490 2357,1499 2362,1504 2459,1504 2465,1510 2547.44,1510 2552.44,1505 2620,1505 2625,1510 2625,1520 2620,1525 2360,1525 2355,1530 2355,1540 2360,1545 2650,1545 2655,1550 2655,1560 2650,1565 2430,1565 2416,1579 2416,1604 2404,1616 2404,1914 2429,1939 2429,2002 2450.35,2023.35 2450.35,2072.35 2458,2080 2603.65,2080 2621.65,2062 v3(2622,2062)
  BOTTOM w5: v3(2399,1350) 2423.5,1350 2428.5,1345 U17.G1@2428.5,1310.98 ; v3(2622,2062) 2623.51,2063.51 2623.99,2063.51 U13.J2@2638.98,2078.5
FMC_A5: U13.K3 U17.G2 | length 2248.1
  TOP w5: v3(2412,1295) 2415,1298 2415,1422.28 2422.72,1430 2480,1430 2485,1435 2485,1470 2494,1479 2536,1479 2540,1475 2680,1475 2685,1480 2685,1628 2680,1633 2475,1633 2470,1638 2470,1648 2475,1653 2680,1653 2685,1658 2685,1668 2680,1673 2475,1673 2470,1678 2470,1688 2475,1693 2550,1693 2555,1698 2555,1708 2550,1713 2475,1713 2470,1718 2470,1728 2475,1733 2520,1733 2525,1738 2525,1748 2520,1753 2475,1753 2470,1758 2470,1768 2475,1773 2520,1773 2525,1778 2525,1788 2520,1793 2475,1793 2470,1798 2470,1805 2475,1810 2515,1810 2520,1815 2520,1825 2515,1830 2475,1830 2439,1866 2439,1914 2449,1924 2449,1975 2460.16,1986.16 2470.86,1986.16 2479.35,1994.65 2479.35,2008.51 2486,2015.16 2574.16,2015.16 v3(2590,2031)
  BOTTOM w5: v3(2412,1295) 2412.99,1295 U17.G2@2428.5,1279.49 ; v3(2590,2031) 2591.47,2031 U13.K3@2607.48,2047.01
FMC_A6: U13.M6 U17.G3 | length 2219.6
  TOP w5: v3(2476,1233) 2638,1233 2640,1235 2640,1240 2645,1245 2710,1245 2715,1240 2715,1215 2720,1210 2732.36,1210 2737.36,1215 2737.36,1285 2742.36,1290 2752.36,1290 2757.36,1285 2757.36,1215 2762.36,1210 2775,1210 2780,1205 2780,1135 2785,1130 2799.34,1130 2804.34,1135 2804.34,1160 2809.34,1165 2819.34,1165 2824.34,1160 2824.34,1135 2829.34,1130 2846,1130 2851,1135 2851,1153 2856,1158 2868.56,1158 2873.56,1153 2873.56,1137 2878.56,1132 2888.56,1132 2893.56,1137 2893.56,1205 2898.56,1210 2945,1210 2950,1215 2950,1575 2940,1585 2860,1585 2855,1590 2855,1840 2850,1845 2700,1845 2695,1850 2695,1900 2690,1905 2675,1905 2670,1900 2670,1860 2665,1855 2640,1855 2635,1860 2635,1905 2630,1910 2612,1910 2607,1915 2607,1948 2601,1954 2536,1954 2527.84,1962.16 v3(2527.84,1969.17)
  BOTTOM w5: U17.G3@2428.5,1247.99 2444.49,1232 2475,1232 v3(2476,1233) ; U13.M6@2512.99,1984.02 v3(2527.84,1969.17)
FMC_A7: U13.N6 U17.H1 | length 2266.8
  TOP w5: v3(2493,1344) 2493,1285 2498,1280 2513.83,1280 2518.83,1285 2518.83,1340 2523.83,1345 2533.83,1345 2538.83,1340 2538.83,1285 2543.83,1280 2715,1280 2720,1285 2720,1300 2725,1305 2770,1305 2775,1300 2775,1271.87 2780,1266.87 2915,1266.87 2920,1261.87 2920,1251.87 2915,1246.87 2780,1246.87 2775,1241.87 2775,1230 2780,1225 2925,1225 2935,1235 2935,1276.87 2930,1281.87 2874,1281.87 2869,1286.87 2869,1296.87 2874,1301.87 2930,1301.87 2935,1306.87 2935,1565 2930,1570 2845,1570 2840,1575 2840,1815 2825,1830 2705,1830 2695,1820 2625,1820 2620,1825 2620,1885 2615,1890 2586.33,1890 2576.33,1900 2576.33,1910.67 2564.25,1922.75 2542.76,1922.75 v3(2527.84,1937.67)
  BOTTOM w5: U17.H1@2460,1310.98 v3(2493,1344) ; U13.N6@2512.99,1952.52 v3(2527.84,1937.67)
FMC_A8: U13.P6 U17.H2 | length 2265.5
  TOP w5: v3(2476,1295.34) 2476,1350.71 2490.29,1365 2551.02,1365 2556.02,1360 2556.02,1315 2561.02,1310 2571.02,1310 2576.02,1315 2576.02,1360 2581.02,1365 2614.67,1365 2619.67,1360 2619.67,1317 2624.67,1312 2634.67,1312 2639.67,1317 2639.67,1360 2644.67,1365 2654.67,1365 2659.67,1360 2659.67,1296 2664.67,1291 2674.67,1291 2679.67,1296 2679.67,1360 2684.67,1365 2710,1365 2715,1360 2715,1322 2720,1317 2730,1317 2735,1322 2735,1361 2740,1366 2750,1366 2755,1361 2755,1325 2760,1320 2770,1320 2775,1325 2775,1361 2780,1366 2790,1366 2795,1361 2795,1325 2800,1320 2915,1320 2920,1325 2920,1545 2915,1550 2825,1550 2820,1555 2820,1730 2815,1735 2765,1735 2760,1740 2760,1750 2765,1755 2810,1755 2815,1760 2815,1770 2810,1775 2755,1775 2750,1780 2750,1790 2755,1795 2810,1795 2815,1800 2815,1810 2810,1815 2715,1815 2705,1805 2590,1805 2585,1810 2585,1874.01 2569.01,1890 2532.84,1890 2527.84,1895 v3(2527.84,1906.17)
  BOTTOM w5: U17.H2@2460,1279.49 2460.15,1279.49 v3(2476,1295.34) ; U13.P6@2512.99,1921.02 v3(2527.84,1906.17)
FMC_A9: U13.M8 U17.J3 | length 2269.8
  TOP w5: v3(2464.85,1969.17) 2464.85,1959.82 2470,1954.67 2502.36,1954.67 2512,1945.03 2512,1890 2522,1880 2560,1880 2570,1870 2570,1795 2575,1790 2710,1790 2725,1775 2730,1775 2745,1760 2745,1710 2750,1705 2800,1705 2805,1700 2805,1535 2810,1530 2895,1530 2900,1525 2900,1512.05 2895,1507.05 2815,1507.05 2810,1502.05 2810,1492.05 2815,1487.05 2895,1487.05 2900,1482.05 2900,1472.05 2895,1467.05 2815,1467.05 2810,1462.05 2810,1452.05 2815,1447.05 2895,1447.05 2900,1442.05 2900,1432.05 2895,1427.05 2815,1427.05 2810,1422.05 2810,1412.05 2815,1407.05 2895,1407.05 2900,1402.05 2900,1390.56 2895,1385.56 2835,1385.56 2830,1380.56 2830,1370.56 2835,1365.56 2895,1365.56 2900,1360.56 2900,1345 2895,1340 2820,1340 2815,1345 2815,1376 2810,1381 2485,1381
  TOP w5.1: v3(2476,1263) 2460,1279 2460,1356 2485,1381
  BOTTOM w5: U13.M8@2450,1984.02 v3(2464.85,1969.17) ; v3(2476,1263) 2491.01,1247.99 U17.J3@2491.5,1247.99
FMC_A10: U13.N7 U17.G7 | length 2227.5
  TOP w5: v3(2412,1138) 2427,1138 2432,1143 2432,1409 2437,1414 2500,1414 2505,1419 2505,1434.5 2510,1439.5 2545,1439.5 2550,1434.5 2550,1420 2555,1415 2770,1415 2775,1420 2775,1430 2770,1435 2575,1435 2570,1440 2570,1450 2575,1455 2770,1455 2775,1460 2775,1470 2770,1475 2705,1475 2700,1480 2700,1490 2705,1495 2770,1495 2775,1500 2775,1510 2770,1515 2705,1515 2700,1520 2700,1680 2689.37,1690.63 2689.37,1715 2684.37,1720 2674.37,1720 2669.37,1715 2669.37,1695 2664.37,1690 2652,1690 2647,1695 2647,1730 2642,1735 2616,1735 2611,1730 2611,1695 2606,1690 2597,1690 2592,1695 2592,1730 2587,1735 2545,1735 2540,1740 2540,1838 2528,1850 2470,1850 2449,1871 2449,1911 2458.67,1920.67 2492.5,1920.67 2497.5,1925.67 v3(2497.5,1935.81)
  BOTTOM w4: U13.N7@2481.5,1952.52 2497.5,1936.52 v3(2497.5,1935.81)
  BOTTOM w5: v3(2412,1138) 2427.99,1122.01 U17.G7@2428.5,1122.01
FMC_A11: U13.M7 U17.H9 | length 2255.9
  TOP w5: v3(2477,1075) 2481,1079 2481,1149 2460,1170 2460,1210 2467,1217 2650,1217 2655,1222 2655,1230 2660,1235 2695,1235 2700,1230 2700,1200 2705,1195 2755,1195 2760,1190 2760,1120 2765,1115 2912.9,1115 2917.9,1120 2917.9,1185 2922.9,1190 2932.9,1190 2937.9,1185 2937.9,1120 2942.9,1115 2960,1115 2965,1120 2965,1585 2945,1605 2875,1605 2870,1610 2870,1855 2865,1860 2715,1860 2710,1865 2710,1918.17 2705,1923.17 2642,1923.17 2637,1928.17 2637,1958 2611,1984 2522,1984 2507.17,1969.17 v3(2496.35,1969.17)
  BOTTOM w5: U17.H9@2460,1059.02 2461.02,1059.02 v3(2477,1075) ; U13.M7@2481.5,1984.02 v3(2496.35,1969.17)
FMC_A12: U13.M13 U17.E3 | length 2225
  L4_SIG w4: v3(2277,1968.5) 2273,1972.5 2273,1979 2278,1984 2291,1984 2296,1989 2296,2009.66 2291,2014.66 2211.34,2014.66 2199,2027 2182,2027 2177,2032 2177,2072 2172,2077 2162,2077 2157,2072 2157,1971 2162,1966 2214,1966 2219,1961 2219,1952.69 2214.31,1948 2162,1948 2157,1943 2157,1935 2162,1930 2213,1930 2218,1925 2218,1853 2213,1848 2198,1848 2193,1843 2193,1823 2198,1818 2228,1818 2233,1813 2233,1773 2257,1749 2291,1749 2318,1722 2318,1700.12 2470.12,1548 2470.12,1530 2475.12,1525 2485.29,1525 2490.29,1530 2490.29,1547 2494.29,1551 2502.29,1551 2506.29,1547 2506.29,1529 2510.29,1525 2541,1525 2549,1517 2549,1494 2534,1479 2506,1479 2501,1474 2501,1404 2506,1399 2537,1399 2542,1394 2542,1286 2524,1268 2524,1255 2543,1236 2543,1182 2538,1177 2525,1177 2517,1169 2517,1153 2512,1148 2499,1148 2494,1153 2494,1214 2489,1219 2455,1219 2450,1214 2450,1180 2445,1175 2437,1175 2432,1180 2432,1232.61 2427.61,1237 2421.39,1237 2417,1232.61 2417,1158.69 2412.31,1154 2405.69,1154 2401,1158.69 2401,1200.2 2402,1201.2 2402,1229 2397,1234 2383.54,1234 v3(2381.52,1231.98)
  BOTTOM w5: v3(2277,1968.5) U13.M13@2292.52,1984.02 ; U17.E3@2365.51,1247.99 v3(2381.52,1231.98)
FMC_D0: TP27.1 U13.L12 U17.R8 | length 2396.6
  L4_SIG w4: v3(2341,1999) 2339,1999 2325,1985 2305.68,1985 2294.37,1973.69 2294.37,1962.09 2294.51,1961.95 2294.51,1931.19 2302.71,1922.99 2317.01,1922.99 2340,1900 2390,1900 2416,1874 2495,1874 2510.97,1858.03 ; 2510.97,1858.01 2599,1769.98 2599,1740 2611,1728 2611,1708 2629.78,1689.22 2635.44,1689.22 2647.78,1701.56 2653.44,1701.56 2659.1,1695.9 2659.1,1690.24 2646.76,1677.9 2646.76,1672.24 2660,1659 2910,1659 2997,1572 2997,943 2992,938 2682,938 2677,943 2677,1057.17 2672,1062.17 2652.69,1062.17 2648,1066.86 2648,1073.48 2652.69,1078.17 2672,1078.17 2677,1083.17 2677,1101 2672,1106 v3(2665.98,1106)
  BOTTOM w5: U13.L12@2324.02,2015.51 2340.53,1999 v3(2341,1999) ; v3(2665.98,1106) 2665.98,1105 U17.R8@2680.47,1090.51 TP27.1@2825,1025
FMC_D1: U13.K13 U17.N7 | length 2263.6
  L4_SIG w4: v3(2278,1999) 2267,1999 2262,1994 2262,1925.5 2267,1920.5 2283.14,1920.5 2291.67,1911.97 2291.67,1903.87 2306.54,1889 2384,1889 2407,1866 2486,1866 2557,1795 2557,1746 2566,1737 2582,1737 2597,1722 2597,1705 2656,1646 2904,1646 2985,1565 2985,959 2980,954 2694,954 2689,959 2689,1115 2676,1128 2676,1163.61 2671.61,1168 2663,1168 2658,1163 2658,1142.86 2653,1137.86 v3(2633.33,1137.86)
  BOTTOM w5: v3(2278,1999) 2278,2032.49 U13.K13@2292.52,2047.01 ; U17.N7@2617.48,1122.01 v3(2633.33,1137.86)
FMC_D2: U13.B12 U17.R9 | length 2404.5
  L4_SIG w4: v3(2308,2350) 2191,2345.43 2180,2345 2175,2345 2160,2346 2111,2355 2057,2355 1835.14,2133.14 1835.14,1371.86 2217,990 2514,990 2589.18,1015 v3(2660,1038.55)
  BOTTOM w5: v3(2308,2350) 2308,2315 U13.B12@2324.02,2298.98 ; v3(2660,1038.55) U17.R9@2680.47,1059.02
FMC_D3: U13.C12 U17.N8 | length 2341.6
  L4_SIG w4: v3(2100,2338) 2060,2338 1847.14,2125.14 1847.14,1379.86 2222,1005 2514,1005 2570.64,1050.06 2576.26,1049.41 2588.39,1034.16 2594.01,1033.53 2600.28,1038.52 2600.91,1044.14 2588.78,1059.38 2589.42,1065.01 v3(2602,1075.03)
  BOTTOM w5: v3(2100,2338) 2105,2338 2159.75,2283.25 2308.25,2283.25 U13.C12@2324.02,2267.48 ; v3(2602,1075.03) U17.N8@2617.48,1090.51
FMC_D4: U13.R8 U17.P9 | length 2240.9
  L4_SIG w4: v3(2452,1827) 2457,1827 2509,1775 2509,1690.06 2537.06,1662 2569,1662 2635,1596 2883,1596 2936,1543 2936,1008 2931,1003 2745,1003 2740,1008 2740,1135 2725.5,1149.5 2725.5,1340 2720.5,1345 2690,1345 2685,1340 2685,1316 2675,1306 2675,1239 2680,1234 2688,1234 2693,1229 2693,1211 2688,1206 2652,1206 2647,1201 2647,1157 2642,1152 2623,1152 2618,1147 2618,1127 2623,1122 2644,1122 2649,1117 2649,1095 2644,1090 2635.05,1090 2630.05,1085 v3(2630.05,1074.94)
  BOTTOM w5: U13.R8@2450,1889.53 2452,1887.53 v3(2452,1827) ; v3(2630.05,1074.94) 2645.97,1059.02 U17.P9@2648.98,1059.02
FMC_D5: U13.N9 U17.M8 | length 2219.5
  L4_SIG w4: v3(2452,1806) 2461,1806 2497,1770 2497,1685.08 2532.08,1650 2564,1650 2630,1584 2878,1584 2924,1538 2924,1022 2919,1017 2757,1017 2752,1022 2752,1030 2757,1035 2763,1035 2768,1040 2768,1049 2763,1054 2757,1054 2752,1059 2752,1142 2738,1156 2738,1351 2733,1356 2680,1356 2675,1351 2675,1321 2666,1312 2666,1248 2636,1218 2636,1167 2631,1162 2612,1162 2607,1157 2607,1112.08 v3(2603.06,1108.14)
  BOTTOM w5: U13.N9@2418.5,1952.52 2434.3,1936.72 2434.3,1862.7 2436,1861 2436,1816 2446,1806 v3(2452,1806) ; U17.M8@2585.98,1090.51 2603.06,1107.59 v3(2603.06,1108.14)
FMC_D6: U13.P9 U17.M7 | length 2233.1
  L4_SIG w4: v3(2420,1805) 2423,1802 2423,1769 2439,1753 2468,1753 2473,1748 2473,1675.12 2523.12,1625 2553,1625 2620,1558 2866,1558 2900,1524 2900,1049.69 2895.31,1045 2888.69,1045 2884,1049.69 2884,1086 2879,1091 2867,1091 2862,1086 2862,1050 2857,1045 2825,1045 2820,1050 2820,1083 2795,1108 2795,1135 2763,1167 2763,1378 2758,1383 2657,1383 2652,1378 2652,1326 2648,1322 2648,1258 2633,1243 2622,1243 2613,1234 2613,1186 2608,1181 2591,1181 2586,1176 2586,1133 2581,1128 2575,1128 2570,1133 v3(2570,1140)
  BOTTOM w5: U13.P9@2418.5,1921.02 2404,1906.52 2404,1821 v3(2420,1805) ; v3(2570,1140) 2570,1137.99 U17.M7@2585.98,1122.01
FMC_D7: U13.R9 U17.L8 | length 2224
  L4_SIG w4: v3(2420,1827) 2430,1827 2435,1822 2435,1774 2444,1765 2480,1765 2485,1760 2485,1680.1 2527.1,1638 2558,1638 2624,1572 2872,1572 2912,1532 2912,1037 2907,1032 2786,1032 2781,1037 2781,1060.02 2776,1065.02 2768,1065.02 2764,1069.02 2764,1077.02 2768,1081.02 2787.31,1081.02 2792,1085.71 2792,1092.33 2787.31,1097.02 2768,1097.02 2764,1101.02 2764,1109.02 2768,1113.02 2776.31,1113.02 2781,1117.71 2781,1124.33 2776.31,1129.02 2768,1129.02 2764,1133.02 2764,1148 2751,1161 2751,1365 2746,1370 2669,1370 2664,1365 2664,1324 2657,1317 2657,1254 2625,1222 2625,1176 2620,1171 2601,1171 2596,1166 2596,1124 2578.01,1106.01 v3(2570.51,1106.01)
  BOTTOM w5: U13.R9@2418.5,1889.53 2420,1888.03 v3(2420,1827) ; U17.L8@2554.49,1090.51 2569.48,1105.5 2570,1105.5 v3(2570.51,1106.01)
FMC_D8: U13.P10 U17.L2 | length 2225.9
  L4_SIG w4: v1(2365,1837) 2365,1845 2360,1850 2336.05,1850 2335.05,1851 2320.95,1851 2307.95,1838 2250,1838 2245,1833 2245,1778 2260,1763 2279,1763 2284,1768 2284,1776 2289,1781 2298,1781 2303,1776 2303,1755 2332,1726 2332,1703.98 2336.98,1699 2344.02,1699 2349,1703.98 2349,1724 2354,1729 2364,1729 2369,1724 2369,1706 2381,1694 2381,1655 2473,1563 2515,1563 2520,1558 2520,1543 2525,1538 2550,1538 2563.5,1524.5 2563.5,1501 2568.5,1496 2669,1496 2674,1491 2674,1483 2669,1478 2592,1478 2587,1473 2587,1465.98 2591.98,1461 2827.02,1461 2832,1456.02 2832,1448.98 2827.02,1444 2597,1444 2592,1439 2592,1394 2587,1389 2578,1389 2573,1394 2573,1480 2568,1485 2559,1485 2554,1480 2554,1159 2559,1154 2567,1154 2572,1159 2572,1261.98 v3(2569.49,1264.49)
  BOTTOM w5: v1(2365,1837) 2371.2,1843.2 2371.2,1905.21 U13.P10@2387.01,1921.02 ; U17.L2@2554.49,1279.49 v3(2569.49,1264.49)
FMC_D9: U13.R10 U17.M3 | length 2226.1
  L4_SIG w4: v1(2365,1811) 2374,1811 2379,1816 2379,1824 2384,1829 2399.02,1829 2404,1824.02 2404,1810 2399,1805 2388,1805 2383,1800 2383,1793.98 2387.98,1789 2406,1789 2411,1784 2411,1763 2434,1740 2455,1740 2460,1735 2460,1723 2455,1718 2434,1718 2429,1713 2429,1679.12 2442.12,1666 2465,1666 2518,1613 2544,1613 2611,1546 2858,1546 2888,1516 2888,1108 2883,1103 2851,1103 2846,1108 2846,1134 2841,1139 2829.54,1139 2825.54,1135 2825.54,1112.69 2820.85,1108 2814.23,1108 2809.54,1112.69 2809.54,1137.46 2775,1172 2775,1387 2767,1395 2645,1395 2640,1390 2640,1330 2635,1325 2621,1325 2616,1320 2616,1253 2601,1238 2601,1196 2596,1191 2588,1191 2583,1196 2583,1257.84 2588,1262.84 v3(2600.83,1262.84)
  BOTTOM w5: v1(2365,1811) 2387.01,1833.01 U13.R10@2387.01,1889.53 ; U17.M3@2585.98,1247.99 v3(2600.83,1262.84)
FMC_D10: U13.R12 U17.M2 | length 2247.4
  L4_SIG w4: v1(2268,1808) 2262,1808 2257,1813 2257,1821 2262,1826 2306.31,1826 2311,1821.31 2311,1814.69 2306.31,1810 2289.98,1810 2285,1805.02 2285,1797.98 2289.98,1793 2310,1793 2315,1788 2315,1760 2332,1743 2380,1743 2393,1730 2393,1660 2431,1622 2438,1622 2443.54,1627.54 2450.46,1627.54 2455.37,1622.63 2455.37,1615.71 2449.15,1609.49 2449.15,1603.83 2454.81,1598.17 2460.47,1598.17 2467.82,1605.52 2473.48,1605.52 2479.86,1599.14 2479.86,1593.48 2473.01,1586.63 2473.01,1579.99 2477.69,1575.31 2484.33,1575.31 2491.18,1582.16 2496.84,1582.16 2504,1575 2525,1575 2532,1568 2532,1555 2537,1550 2556,1550 2577,1529 2577,1514 2582,1509 2839,1509 2844,1504 2844,1496 2839,1491 2691,1491 2686,1486 2686,1478 2691,1473 2845,1473 2850,1468 2850,1337 2845,1332 2837,1332 2832,1337 2832,1427 2827,1432 2609,1432 2604,1427 2604,1382 2599,1377 2571,1377 2566,1372 2566,1299 v3(2570,1295)
  BOTTOM w5: v1(2268,1808) 2259,1808 2240,1789 2186,1789 2181,1794 2181,1807 2186,1812 2233,1812 2253,1832 2294,1832 2299,1837 2299,1862.98 2324.02,1888 U13.R12@2324.02,1889.53 ; v3(2570,1295) 2570.47,1295 U17.M2@2585.98,1279.49
FMC_D11: U13.P11 U17.P1 | length 2226.8
  L4_SIG w4: v1(2328,1834) 2340,1834 2345,1829 2345,1772 2350,1767 2390,1767 2417,1740 2417,1674.14 2438.14,1653 2460,1653 2514,1599 2541.02,1599 2606.02,1534 2852,1534 2876,1510 2876,1120.9 2871.1,1116 2864.18,1116 2859.28,1120.9 2859.28,1147 2854.28,1152 2813,1152 2787,1178 2787,1404 2784,1407 2633,1407 2628,1402 2628,1346 2623,1341 2605,1341 2600,1346 v3(2600,1350)
  BOTTOM w5: v1(2328,1834) 2328,1868 2340,1880 2340,1905.51 2343.81,1909.33 U13.P11@2355.51,1921.02 ; v3(2600,1350) 2640,1350 2645,1355 2645,1479 2650,1484 2662,1484 2667,1479 2667,1329 U17.P1@2648.98,1310.98
FMC_D12: U13.R11 U17.N2 | length 2224.3
  L4_SIG w4: v1(2327,1805) 2327,1768 2340,1755 2385,1755 2405,1735 2405,1669.16 2433.16,1641 2455,1641 2509,1587 2536.04,1587 2602.04,1521 2845,1521 2864,1502 2864,1169 2859,1164 2831,1164 2826,1169 2826,1211.02 2822,1215.02 2803,1215.02 2799,1219.02 2799,1227.02 2803,1231.02 2847.31,1231.02 2852,1235.71 2852,1242.33 2847.31,1247.02 2803,1247.02 2799,1251.02 2799,1259.02 2803,1263.02 2822,1263.02 2826,1267.02 2826,1317 2821,1322 2803,1322 2799,1326 2799,1334 2803,1338 2813,1338 2817,1342 2817,1350 2813,1354 2803,1354 2799,1358 2799,1366 2803,1370 2813,1370 2817,1374 2817,1382 2813,1386 2803,1386 2799,1390 2799,1398 2803,1402 2813,1402 2817,1406 2817,1415 2812,1420 2621,1420 2616,1415 2616,1370 2611,1365 2589,1365 2584,1360 2584,1281.69 2588.69,1277 2595.31,1277 2600,1281.69 v3(2600,1295)
  BOTTOM w5: v1(2327,1805) 2327,1802 2322,1797 2293,1797 2288,1792 2288,1781 2293,1776 2338,1776 2346,1784 2346,1862 2355.51,1871.51 U13.R11@2355.51,1889.53 ; v3(2600,1295) 2601.97,1295 U17.N2@2617.48,1279.49
FMC_D13: U13.L15 U17.R1 | length 2313
  L4_SIG w4: v3(2173.05,1988.95) 2224,1988.95 2229,1983.95 2229,1855 2234,1850 2302,1850 2312,1860 2367,1860 2385,1842 2459,1842 2521,1780 2521,1695.04 2542.04,1674 2574,1674 2640,1608 2888,1608 2949,1547 2949,995 2944,990 2733,990 2728,995 2728,1130 2715,1143 2715,1315 v3(2700,1330)
  BOTTOM w5: v3(2173.05,1988.95) 2173.77,1988.95 2181.82,1997 2214,1997 2229.53,2012.53 U13.L15@2229.53,2015.51 ; U17.R1@2680.47,1310.98 2680.98,1310.98 v3(2700,1330)
FMC_D14: U13.L14 U17.N3 | length 2241.2
  L4_SIG w4: v3(2246.17,2000.66) 2247,2000.66 2252,1995.66 2252,1895 2257,1890 2290,1890 2302,1878 2382,1878 2402,1858 2477,1858 2545,1790 2545,1706 2553,1698 2586,1698 2650,1634 2899,1634 2973,1560 2973,971 2968,966 2707,966 2702,971 2702,1119 2688,1133 2688,1191 2683,1196 2671.9,1196 2666.9,1191 v3(2666.9,1186)
  BOTTOM w5: v3(2246.17,2000.66) U13.L14@2261.02,2015.51 ; U17.N3@2617.48,1247.99 2617.48,1235.42 v3(2666.9,1186)
FMC_D15: U13.K15 U17.R2 | length 2329.2
  L4_SIG w4: v3(2193,2012) 2193,2007 2198,2002 2225,2002 2241,1986 2241,1865 2246,1860 2297,1860 2306,1869 2373,1869 2392,1850 2467.98,1850 2533,1784.98 2533,1700.02 2547.02,1686 2581,1686 2647,1620 2893,1620 2961,1552 2961,983 2956,978 2721,978 2716,983 2716,1125 2702,1139 2702,1238 2685,1255 2685,1280 v3(2700,1295)
  BOTTOM w5: v3(2193,2012) 2193,2035 2205.01,2047.01 U13.K15@2229.53,2047.01 ; U17.R2@2680.47,1279.49 2695.98,1295 v3(2700,1295)
FMC_D16: U13.P14 U17.E8 | length 2227.8
  L4_SIG w4: v1(2054,1864) 2060,1864 2065,1859 2065,1658 2071,1652 2135,1652 2140,1657 2140,1663 2145,1668 2153,1668 2158,1663 2158,1657 2163,1652 2207,1652 2233,1626 2233,1618 2237,1614 2273,1614 2286.5,1600.5 2286.5,1583.5 2292,1578 2309,1578 2323,1564 2323,1430.98 2318.02,1426 2310.98,1426 2306,1430.98 2306,1560.31 2301.31,1565 2294.69,1565 2290,1560.31 2290,1366 2315,1341 2345,1341 2350,1346 2350,1369 2355,1374 2409,1374 2414,1369 2414,1340 2409,1335 2394,1335 2383,1346 2383,1358.02 2378.02,1363 2366,1363 2361,1358 2361,1335 2356,1330 2339,1330 2334,1325 2334,1319 2326,1311 2314,1311 2304,1301 2304,1284 2309,1279 2331,1279 2336,1274 2336,1240 2331,1235 2316,1235 2311,1230 2311,1222 2316,1217 2335,1217 2340,1212 2340,1198 2345,1193 2373,1193 2378,1188 2378,1127 2373,1122 2338,1122 2333,1117 2333,1110 2338,1105 v3(2350,1105)
  BOTTOM w5: v1(2054,1864) 1968,1864 1963,1859 1963,1846 1968,1841 2114,1841 2119,1846 2119,1859 2124,1864 2183,1864 2224.1,1905.1 2245.1,1905.1 U13.P14@2261.02,1921.02 ; v3(2350,1105) 2364.49,1090.51 U17.E8@2365.51,1090.51
FMC_D17: U13.N14 U17.D7 | length 2223.5
  L4_SIG w4: v1(2050,1905) 2060,1905 2065,1900 2065,1888 2060,1883 2026,1883 2021,1878 2021,1645.98 2025.98,1641 2033.02,1641 2038,1645.98 2038,1842.61 2042.39,1847 2048.61,1847 2053,1842.61 2053,1645 2058,1640 2183,1640 2188,1635 2188,1607 2193,1602 2200,1602 2205,1607 2205,1621.31 2209.69,1626 2216,1626 2221,1621 2221,1607 2226,1602 2268.02,1602 2273,1597.02 2273,1589.98 2268.02,1585 2233.39,1585 2229,1580.61 2229,1574.39 2233.39,1570 2273,1570 2278,1565 2278,1347 2283,1342 2300,1342 2305,1337 2305,1316 2300,1311 2279.98,1311 2275,1306.02 2275,1298.98 2279.98,1294 2289,1294 2294,1289 2294,1276 2300,1270 2322,1270 2327,1265 2327,1253 2322,1248 2283.98,1248 2279,1243.02 2279,1235.98 2283.98,1231 2295,1231 2300,1226 2300,1213 2305,1208 2327,1208 2332,1203 2332,1195 2327,1190 2305,1190 2300,1185 2300,1161 2305,1156 2311,1156 2316,1161 2316,1174 2321,1179 2363,1179 2368,1174 2368,1137 2363,1132 2356,1132 2351,1137 2351,1162.31 2346.31,1167 2333,1167 2328,1162 2328,1148.01 2333,1143.01 v3(2335,1143.01)
  BOTTOM w5: v1(2050,1905) 2178,1905 2208.52,1935.52 2244.02,1935.52 U13.N14@2261.02,1952.52 ; U17.D7@2334.02,1122.01 2334.02,1142.03 v3(2335,1143.01)
FMC_D18: U13.P15 U17.D8 | length 2224.4
  L4_SIG w4: v1(2024,1906) 2024,1899 2009,1884 2009,1633 2014,1628 2171,1628 2176,1623 2176,1594 2180,1590 2211.31,1590 2216,1585.31 2216,1578.69 2211.31,1574 2180,1574 2176,1570 2176,1561 2180,1557 2261.31,1557 2266,1552.31 2266,1545.69 2261.31,1541 2180,1541 2176,1537 2176,1528 2181,1523 2231,1523 2235,1519 2235,1509 2232,1506 2192,1506 2187,1501 2187,1492 2192,1487 2229,1487 2234,1482 2234,1289.69 2238.69,1285 2245.31,1285 2250,1289.69 2250,1525.31 2254.69,1530 2261.31,1530 2266,1525.31 2266,1284 2271,1279 2271,1230 2290,1211 2290,1155 2301,1144 2314.41,1144 2319.41,1139 v3(2319.41,1105.61)
  BOTTOM w5: v1(2024,1906) 2011,1906 2006,1901 2006,1888 2011,1883 2075,1883 2080,1878 2080,1861 2085,1856 2098,1856 2103,1861 2103,1878 2108,1883 2178,1883 2216.02,1921.02 U13.P15@2229.53,1921.02 ; v3(2319.41,1105.61) 2334.02,1091 U17.D8@2334.02,1090.51
FMC_D19: U13.N15 U17.B9 | length 2255.1
  L4_SIG w4: v1(1989,1909) 1985,1905 1985,1609 1990,1604 2115.31,1604 2120,1599.31 2120,1592.69 2115.31,1588 1988.69,1588 1984,1583.31 1984,1576.69 1988.69,1572 2114,1572 2119,1567 2119,1388 2124,1383 2130,1383 2135,1388 2135,1598.31 2139.69,1603 2146.31,1603 2151,1598.31 2151,1388 2156,1383 2184,1383 2189,1388 2189,1457 2194,1462 2205,1462 2210,1457 2210,1257 2269,1198 2269,1134 2281,1122 2300,1122 2305,1117 2305,1069 2300,1064 2291,1064 2286,1069 v3(2286,1074)
  BOTTOM w5: v1(1989,1909) 2004,1924 2172.48,1924 2201,1952.52 U13.N15@2229.53,1952.52 ; U17.B9@2271.02,1059.02 v3(2286,1074)
FMC_D20: U13.M15 U17.C8 | length 2245.9
  L4_SIG w4: v1(1938,1947) 1933,1942 1933,1495 1938,1490 2064.31,1490 2069,1485.31 2069,1478.69 2064.31,1474 1938.69,1474 1934,1469.31 1934,1462.69 1938.69,1458 2064,1458 2069,1453 2069,1445 2064,1440 1972.69,1440 1968,1435.31 1968,1429 1973,1424 1981.5,1424 1986.5,1419 1986.5,1410.5 2098,1299 2098,1284.32 2084.82,1271.14 2084.82,1265.18 2089.02,1260.98 2094.98,1260.98 2112.63,1278.63 2119.37,1278.63 2124.13,1273.87 2124.13,1267.13 2116.48,1259.48 2116.48,1253.09 2121.02,1248.56 2127.42,1248.56 2131.43,1252.57 2137.41,1252.57 2183.99,1205.99 2188.99,1205.99 2214.46,1231.46 2221.54,1231.46 2226.96,1226.04 2226.96,1218.96 2187,1179 2187,1171.98 2193.38,1165.6 2199.04,1165.6 2239.4,1205.96 2246.04,1205.96 2250.72,1201.28 2250.72,1194.64 2210.36,1154.28 2210.36,1148.62 2216.75,1142.23 2222.41,1142.23 2249.27,1169.09 2255.91,1169.09 2260.59,1164.41 2260.59,1157.77 2233.16,1130.34 2233.16,1123.84 2237.75,1119.25 2244.25,1119.25 2254,1129 2260,1129 2271,1118 2271,1093.39 2275.39,1089 2292.22,1089 2297,1093.78 2297,1099 2292,1104 v3(2286,1104)
  BOTTOM w5: v1(1938,1947) 1961,1947 1974,1960 2166.04,1960 2188.04,1982 2227.51,1982 U13.M15@2229.53,1984.02 ; v3(2286,1104) 2299.49,1090.51 U17.C8@2302.52,1090.51
FMC_D21: U13.E12 U17.A9 | length 2242.8
  L4_SIG w4: v3(2255,1074) 2244,1074 2231,1087 2231,1111 2175,1167 2175,1198 2138,1235 2136.98,1236 2097,1236 2068,1265 2068,1273 2081,1286 2081,1298 1920,1459 1920,2087 2091,2258 2124.01,2258 2129.01,2253 2129.01,2192 2133.01,2188 2141.01,2188 2145.01,2192 2145.01,2253 2150.01,2258 2156.01,2258 2161.01,2253 2161.01,2192 2165.01,2188 2173.01,2188 2177.01,2192 2177.01,2253 2182.01,2258 2188.01,2258 2193.01,2253 2193.01,2192 2197.01,2188 2205.01,2188 2209.01,2192 2209.01,2253 2214.01,2258 2220.01,2258 2225.01,2253 2225.01,2192 2229.01,2188 2237.01,2188 2241.01,2192 2241.01,2253 2246.01,2258 2256,2258 2261,2253 2261,2239 2266,2234 2304.17,2234 2309.17,2229 v3(2309.17,2219.34)
  BOTTOM w5: U17.A9@2239.53,1059.02 2254.51,1074 v3(2255,1074) ; v3(2309.17,2219.34) U13.E12@2324.02,2204.49
FMC_D22: U13.E13 U17.C7 | length 2228.9
  L4_SIG w4: v3(2277.67,2219.34) 2274.01,2223 2258,2223 2253,2218 2253,2182 2246,2175 2125,2175 2105,2155 2089,2155 2084,2160 2084,2167 2079,2172 2073,2172 2031,2130 2031,2125 2036,2120 2060.02,2120 2065,2115.02 2065,2107.98 2060.02,2103 2004,2103 1997,2096 1997,2088.98 2002,2083.98 2060.31,2083.98 2065,2079.29 2065,2072.67 2060.31,2067.98 2002,2067.98 1997,2062.98 1997,2055 2002,2050 2060.31,2050 2065,2045.31 2065,2038.69 2060.31,2034 2002,2034 1997,2029 1997,2023 2002,2018 2060.31,2018 2065,2013.31 2065,2006.69 2060.31,2002 2002,2002 1997,1997 1997,1991 2002,1986 2060.31,1986 2065,1981.31 2065,1974.69 2060.31,1970 2002,1970 1997,1965 1997,1959 2002,1954 2018.31,1954 2023,1949.31 2023,1942.69 2018.31,1938 2002,1938 1997,1933 1997,1926 2006,1917 2006,1899 1997,1890 1997,1621 2002,1616 2158,1616 2163,1611 2163,1492 2170,1485 2177,1485 2187,1475 2213.85,1475 2222,1466.85 2222,1287 2241,1268 2241,1243 2279,1205 2279,1145 v3(2285,1139)
  BOTTOM w4: v3(2277.67,2219.34) U13.E13@2292.52,2204.49
  BOTTOM w5: v3(2285,1139) 2301.99,1122.01 U17.C7@2302.52,1122.01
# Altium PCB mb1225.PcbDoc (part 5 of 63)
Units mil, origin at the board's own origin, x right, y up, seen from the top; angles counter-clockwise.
Board outline 5000 x 3464.56 mil, 6 copper layers (TOP, L2_GND, L3_VCC, L4_SIG, L5_GND, BOTTOM), stack 62.2 mil thick; 452 components, 378 nets, 1968 pads, 949 vias.

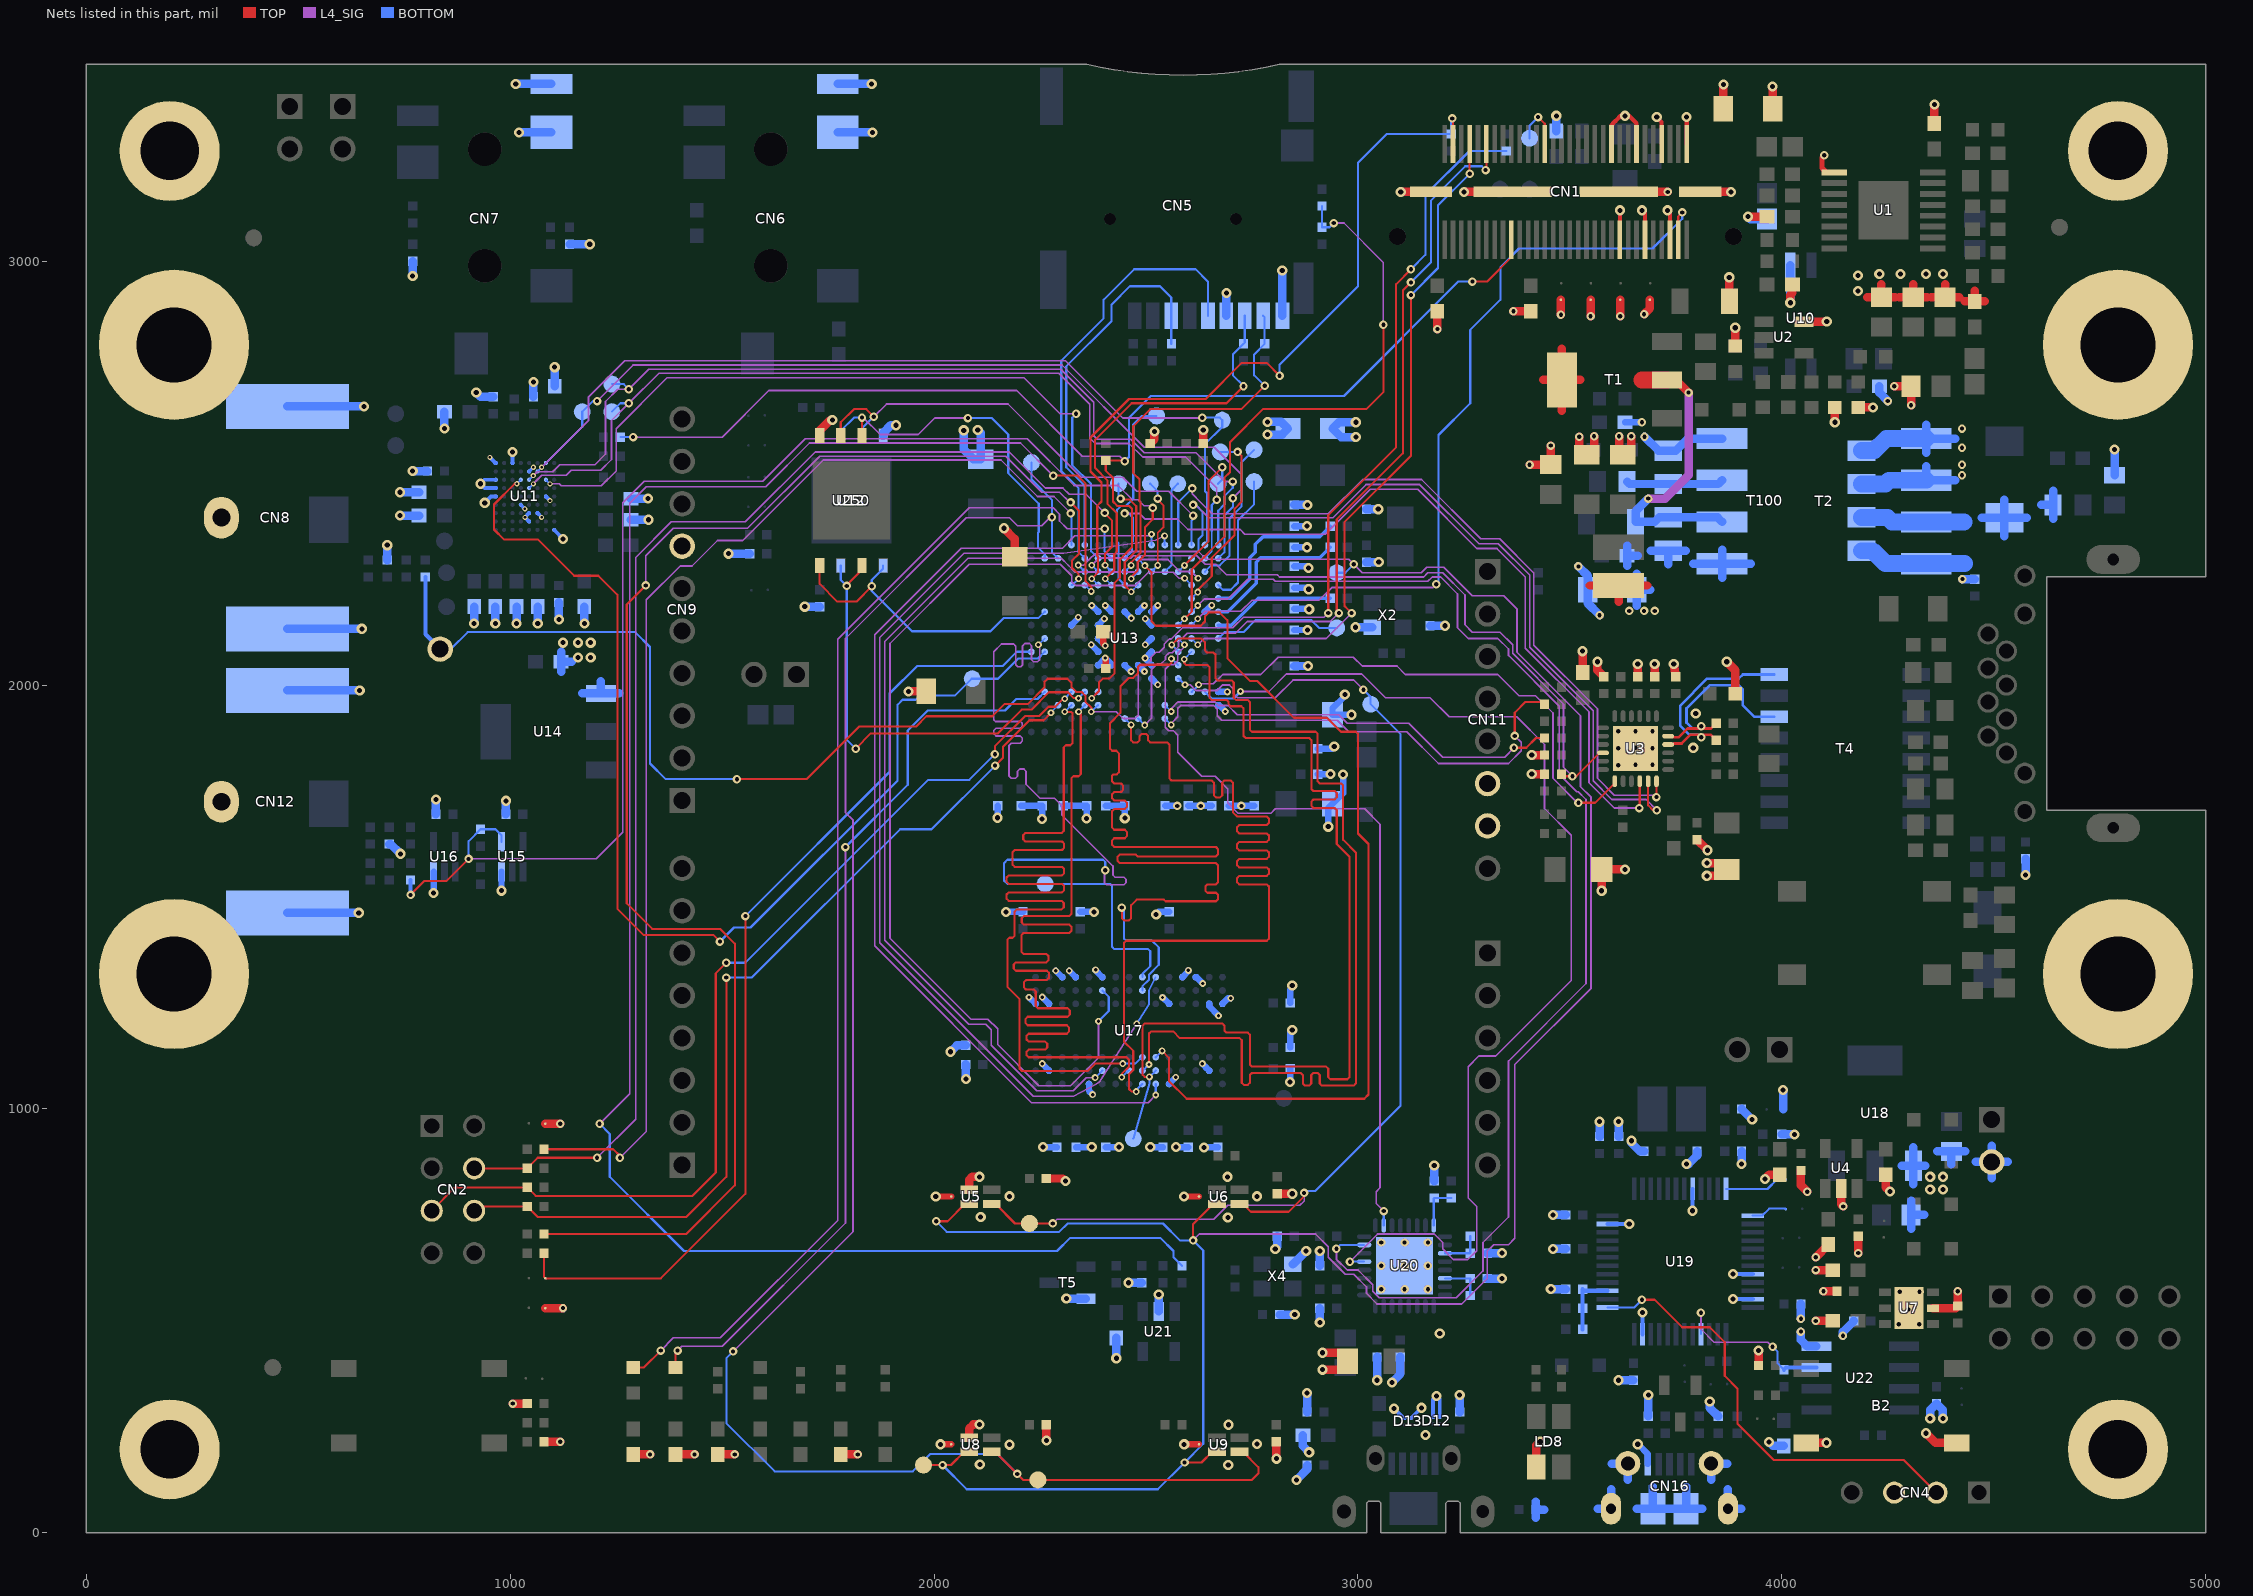
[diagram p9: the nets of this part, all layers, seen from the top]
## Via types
v1: diameter 20, hole 10, TOP to BOTTOM, 354 vias
v2: diameter 24, hole 12, TOP to BOTTOM, 349 vias
v3: diameter 16, hole 8, TOP to BOTTOM, 219 vias
v4: diameter 12, hole 6, TOP to BOTTOM, 27 vias

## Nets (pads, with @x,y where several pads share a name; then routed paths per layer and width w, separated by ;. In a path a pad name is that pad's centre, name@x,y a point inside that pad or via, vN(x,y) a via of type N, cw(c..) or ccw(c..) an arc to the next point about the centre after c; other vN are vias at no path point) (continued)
PC0: U13.M2 U20.29 | length 2654.4
  L4_SIG w4: v3(2723,1985) 2790,1985 2831,2026 3009,2026 3065,1970 3170,1970 3215,1925 3375,1925 3440,1860 3440,1709 3503,1646 3503,1303 3325,1125 3285,1125 3260,1100 3260,790 3280,770 3280,665.75 3259.25,645 3225,645 3200,670 3200,685 3180,705 3046.33,705 v1(2981.17,639.84)
  BOTTOM w5: U13.M2@2638.98,1984.02 2654.61,1968.4 2706.4,1968.4 v3(2723,1985) ; v1(2981.17,639.84) U20.29@3014.72,639.84
PC1: U3.13 U13.M3 | length 1289
  TOP w5: v1(3520,1722.5) 3559.5,1722.5 3605.79,1768.79 U3.13@3605.79,1773.23
  L4_SIG w4: v3(2624,2001) 2626,2003 2659,2003 2681,2025 2771,2025 2812,2066 2989,2066 3010,2045 3092,2045 3112,2025 3330,2025 3380,1975 3419,1975 3460,1934 3460,1780 3517.5,1722.5 v1(3520,1722.5)
  BOTTOM w5: U13.M3@2607.48,1984.02 2608.02,1984.02 2624,2000 v3(2624,2001)
PC3: TP101.1 TP103.1 U5.4 U6.4 U13.L4 | length 2810
  TOP w5: U5.4@2136,775.82 2145.18,775.82 2191,730 TP103.1@2225,730 v1(2280,730) ; U6.4@2720.61,775.82 2729.18,775.82 2747.5,757.5 2836.5,757.5 2873,794 v1(2873,802)
  L4_SIG w4: v1(2280,730) 2290,740 2660,740 2693,773 2863,773 2873,783 v1(2873,802) ; v3(2592,2001) 2604,2001 2618,1987 2667,1987 2680,2000 2697,2000 2706,1991 2706,1980 2716,1970 2805,1970 2847,2012 2990,2012 v1(3013,1989)
  BOTTOM w5: U13.L4@2575.98,2015.51 2577.49,2015.51 v3(2592,2001) ; v1(2873,802) 2877.5,806.5 2899.5,806.5 3100,1007 3100,1885 TP101.1@3030,1955 3030,1972 v1(3013,1989)
PC4: R36.2 U13.N5 | length 987.3
  TOP w5: v1(3367.97,1852.03) 3397.03,1852.03 3420,1875 R36.2@3440,1875
  L4_SIG w4: v3(2559.34,1937.67) 2559.34,1944.34 2575,1960 2662.62,1960 2670.95,1951.67 2693.33,1951.67 2715,1930 2955,1930 2975,1910 3120,1910 3200,1830 3345.94,1830 v1(3367.97,1852.03)
  BOTTOM w4: U13.N5@2544.49,1952.52 v3(2559.34,1937.67)
PC5: R32.2 U13.P5 | length 1135.7
  TOP w5: v1(3370,1880) 3370,1935 3395,1960 3435,1960 R32.2@3440,1955
  L4_SIG w4: v3(2559.34,1906.17) 2559.34,1909.34 2575,1925 2575,1945 2581.67,1951.67 2659.63,1951.67 2668,1943.3 2668,1928 2679,1917 2951,1917 2978,1890 3115,1890 3190,1815 3355,1815 3385,1845 3385,1865 v1(3370,1880)
  BOTTOM w5: U13.P5@2544.49,1921.02 v3(2559.34,1906.17)
PC9: U12.5 U13.F14 U250.5 | length 735.3
  TOP w5: U250.5@1730,2281.9 1730,2239 1772,2197 1817,2197 v1(1853,2233)
  BOTTOM w5: U12.5@1880,2281.46 1880,2275 1853,2248 v1(1853,2233) 1853,2222 1948,2127 2133,2127 2164,2158 2246.03,2158 U13.F14@2261.02,2172.99
PC10: U12.2 U13.B14 U250.2 | length 839.5
  TOP w5: U250.2@1830,2588.98 v1(1830,2631)
  L4_SIG w4: v1(1830,2631) 1833,2631 1873,2591 1963,2591 2002,2630 v1(2080,2630)
  BOTTOM w5: U12.2@1780,2588.54 1780,2600 1811,2631 v1(1830,2631) ; v1(2080,2630) 2136,2630 2175,2591 2175,2500 2247,2428 2247,2361 2245,2359 2245,2325 2261.02,2308.98 U13.B14@2261.02,2298.98
PC11: TP100.1 TP104.1 U8.4 U9.4 U13.B13 | length 4362.1
  TOP w5: U8.4@2136,191.21 2143.79,191.21 v1(2196,139) 2210,125 TP104.1@2245,125 2750,125 2765,140 2765,155 2728.79,191.21 U9.4@2720.61,191.21
  L4_SIG w4: v1(1526,428) 1809,711 1809,1681 1791,1699 1791,2110 2076,2395 2178,2395 2197,2376 2254,2376 2274,2396 v1(2278,2396)
  BOTTOM w5: v1(1526,428) 1510,412 1510,259 1624,145 1950,145 1991,186 2149,186 v1(2196,139) ; TP100.1@2230,2525 2230,2485 2278,2437 v1(2278,2396) 2278,2313.5 U13.B13@2292.52,2298.98
PC12: R50.1 U13.A12 | length 2797.1
  TOP w5: R50.1@1080,905 1243,905 1259,889 v1(1259,885)
  L4_SIG w4: v1(1259,885) 1321,947 1321,2201 1401,2281 1429,2281 1489,2341 1549,2341 1739,2531 2158,2531 2244,2445 2283,2445 2322,2406 v1(2322,2405)
  BOTTOM w5: v1(2322,2405) 2324.02,2402.98 U13.A12@2324.02,2330.47
PC13: TP14.1 U13.D1 | length 311.9
  BOTTOM w5: U13.D1@2670.47,2235.98 2681.45,2225 2700,2225 2717,2242 2717,2389 2755,2427 TP14.1@2755,2480
PC14: R97.2 U13.E1 | length 375.6
  BOTTOM w8: U13.E1@2670.47,2204.49 2699.49,2204.49 2745,2250 2745,2300 2758,2313 2758,2332 2776,2350 2910,2350 R97.2@2935,2375
PC15: R99.2 U13.F1 | length 356.8
  BOTTOM w8: U13.F1@2670.47,2172.99 2692.99,2172.99 2760,2240 2760,2290 2770,2300 2910,2300 R99.2@2935,2325
PD2: R57.2 U13.D12 | length 3570.3
  TOP w5: R57.2@1080,705 1415,705 1530,820 1530,1390 1495,1425 1335,1425 1275,1485 1275,2190 v1(1320,2235) ; v1(2322,2431) 2342,2411 2342,2310 2325,2293 2325,2277.49 2341,2261.49 v3(2341,2251)
  L4_SIG w4: v1(1320,2235) 1320,2305 1385,2370 1560,2370 1730,2540 2169,2540 2254,2455 2296,2455 2320,2431 v1(2322,2431)
  BOTTOM w5: U13.D12@2324.02,2235.98 2325.98,2235.98 v3(2341,2251)
PD3: TP5.1 TP102.1 U5.3 U6.3 U8.3 U9.3 U13.C11 | length 6007.5
  TOP w5: TP5.1@1975,160 v1(2020,160) 2040,160 2071.21,191.21 U8.3@2082.86,191.21 ; v1(2005,735) 2032,735 2072.82,775.82 U5.3@2082.86,775.82 ; v1(2591,166) 2631,166 2656.21,191.21 U9.3@2667.47,191.21 ; v1(2611,690) 2611,728 2658.82,775.82 U6.3@2667.47,775.82
  L4_SIG w4: v3(2340,2283) 2353,2283 2358,2288 2358,2288.29 2366.2,2296.49 2366.49,2296.49 2380,2310 2457,2310 2462,2315 2624,2315 2642,2297 2978,2297 v1(2990,2285) 3010,2265 3149,2265 3162,2278 3202.46,2278 3269.81,2210.65 3344.35,2210.65 3375,2180 3375,2078 3525,1928 3525,1760 3550,1735 3550,1285 3370,1105 3370,695 3355,680 3320,680 3305,665 3305,600 3245,540 3045,540 3020,565 3020,580 2990,610 2970,610 2930,650 2930,675 2900,705 2626,705 v1(2611,690)
  BOTTOM w5: v1(2005,735) 2030,710 2295,710 2315,730 2540,730 2580,690 v1(2611,690) 2635,666 2635,210 v1(2591,166) 2528,103 2077,103 v1(2020,160) ; v3(2340,2283) 2341,2282 U13.C11@2355.51,2267.48 ; TP102.1@2950,2265 2970,2265 v1(2990,2285)
PD4: R129.2 U13.D11 | length 4555.2
  TOP w5: v1(2281,2494) 2338.5,2494 2357.5,2475 2357.5,2244.98 2371,2231.48 v3(2371,2221)
  L4_SIG w4: v1(1211,965) 1282,1036 1282,2429 1321,2468 1603,2468 1706,2571 2204,2571 v1(2281,2494)
  BOTTOM w4: U13.D11@2355.51,2235.98 2370.49,2221 v3(2371,2221)
  BOTTOM w5: v1(1211,965) 1235,941 1235,840 1410,665 2290,665 2321,696 2534,696 2565,665 2565,650 R129.2@2585,630
PD5: R40.2 U3.10 U13.C10 | length 1651.4
  TOP w5: R40.2@3480,1790 3485,1785 v1(3506,1785) 3515,1785 3570.16,1840.16 U3.10@3578.23,1840.16
  L4_SIG w4: v3(2372,2282.49) 2389.51,2300 2465,2300 2470,2305 2620,2305 2640,2285 2665,2285 2690,2260 2810,2260 2815,2255 3155,2255 3165,2265 3200,2265 3252.5,2212.5 3252.5,2142.5 3270,2125 3335,2125 3365,2095 3365,2075 3485,1955 3485,1806 v1(3506,1785)
  BOTTOM w5: v3(2372,2282.49) U13.C10@2387.01,2267.48
PD6: CN5.5 U13.B11 | length 1043.2
  BOTTOM w5: U13.B11@2355.51,2298.98 2341,2313.49 2341,2464 2300,2505 2300,2765 2400,2865 2400,2909 2472,2981 2617,2981 2646.3,2951.7 CN5.5@2646.3,2871.21
PD7: CN5.3 R81.1 U13.A11 | length 908.9
  BOTTOM w5: U13.A11@2355.51,2330.47 2355.51,2470 2312,2513.51 2312,2752 2419,2859 2419,2898 2462,2941 2533,2941 2559.69,2914.31 CN5.3@2559.69,2871.21 2559.69,2805.31 R81.1@2560,2805
PD11: R7.1 R100.1 TP20.1 U13.N10 | length 4278.9
  TOP w5: v1(1535,1778) 1699,1778 1823,1902 1957.25,1902 1981.75,1926.5 2137.5,1926.5 2166,1955 2221.02,1955 2260.67,1994.65 2260.67,2007.67 2268,2015 2314.51,2015 2324.5,2005.01 2324.5,1994.99 2335.49,1984 2348,1984 2357,1975 2357,1961 2371,1947 v3(2371,1937) ; v1(2930,2170) 2930,2401 3090,2561 3090,2946 v1(3125,2981)
  L4_SIG w4: v3(2371,1937) 2430,1937 2446,1921 2474,1921 2482,1929 2482,2037.61 2490.55,2046.16 2500.15,2046.16 2511.84,2057.85 2511.84,2065.95 2523.54,2077.65 2531.64,2077.65 2543.34,2089.35 2543.34,2097.01 2555.2,2108.87 2559.87,2108.87 2586,2135 2705,2135 2730,2160 2920,2160 v1(2930,2170)
  BOTTOM w5: TP20.1@835,2085 860,2085 900,2125 1295,2125 1330,2090 1330,1815 1367,1778 v1(1535,1778) ; v3(2371,1937) 2386.52,1952.52 U13.N10@2387.01,1952.52 ; v1(3125,2981) 3159,3015 3159,3156 3263,3260 R7.1@3350,3260
  BOTTOM w10: R100.1@800,2255 800,2120 TP20.1@835,2085
PD12: CN1.44 R17.1 R88.1 U13.M10 | length 3230.1
  TOP w5: v3(2372.16,1969.17) 2389.15,1986.16 2389.15,2006.67 2397.64,2015.16 2413.16,2015.16 2426,2028 2426,2241 2438,2253 2438,2296 2467,2325 2467,2416 2460.5,2422.5 2432.49,2422.5 2430.99,2424 2422,2433.01 2422,2489 2405,2506 R17.1@2405,2530 2448,2530 v1(2450,2528) ; v1(3270,2952) 3305,2952 3362.04,3009.04 CN1.44@3362.04,3050.55
  L4_SIG w4: v1(1290,2585) 1500,2585 1610,2695 2195,2695 2350,2540 2438,2540 v1(2450,2528)
  BOTTOM w5: R88.1@1260,2585 v1(1290,2585) ; v3(2372.16,1969.17) U13.M10@2387.01,1984.02 ; v1(2450,2528) 2460,2538 2460,2631 2511,2682 2967,2682 3237,2952 v1(3270,2952)
PD13: U12.7 U13.M11 U250.7 | length 1116.2
  TOP w5: v1(1794,2234) 1794,2236 1830,2272 U250.7@1830,2281.9 ; v1(1815,1850) 1851,1886 2151,1886 2207,1942 2229.99,1942 2270.99,1983 2316,1983 2329.83,1969.17 v3(2340.66,1969.17)
  BOTTOM w5: U12.7@1780,2281.46 1780,2248 v1(1794,2234) 1794,1871 v1(1815,1850) ; v3(2340.66,1969.17) U13.M11@2355.51,1984.02
PE0: U13.A6 U17.K9 | length 2360.2
  L4_SIG w4: v3(2512.99,2356) 2508.99,2352 2332,2352 2303,2323 2064.41,2323 1860,2118.59 1860,1385 2230,1015 2504.99,1015 v3(2522.99,1033)
  BOTTOM w4: U13.A6@2512.99,2330.47 v3(2512.99,2356)
  BOTTOM w5: v3(2522.99,1033) U17.K9@2522.99,1059.02
PE1: U13.A5 U17.K1 | length 2463.1
  L4_SIG w4: v3(2478,1201) 2411.36,1096.46 2398.25,1076.06 2391.15,1065 2391,1065 2388.5,1062.5 2381.75,1058.05 2329,1030 2234,1030 1872,1392 1872,2112.2 2070.8,2311 2306,2311 2522.89,2341.59 v3(2543.96,2352)
  BOTTOM w4: v3(2478,1201) 2507,1246 2507,1280 U17.K1@2522.99,1310.98
  BOTTOM w5: v3(2543.96,2352) 2543.96,2331 U13.A5@2544.49,2330.47
PE2: U12.3 U13.A3 U250.3 | length 1131.3
  TOP w5: U250.3@1780,2588.98 1780,2620 1811,2651 1840,2651 v1(1858,2633)
  L4_SIG w4: v1(1858,2633) 1888,2663 2174.27,2663 2347.27,2490 2445,2490 2478,2457 2554,2457 v1(2611,2400)
  BOTTOM w5: U12.3@1830,2588.54 1830,2606 1857,2633 v1(1858,2633) ; U13.A3@2607.48,2330.47 2607.48,2387.48 2611,2391 v1(2611,2400)
PE3: TP11.1 U11.F2 U13.A2 | length 2130.5
  L4_SIG w3.5: v4(1074.28,2513.81) 1100.47,2540
  L4_SIG w4: 1100.47,2540 1185,2624.53 1185,2680 1270,2765 2310,2765 2445,2630 2631.99,2630 v1(2632.92,2630.93)
  BOTTOM w3.5: U11.F2@1064.53,2504.06 v4(1074.28,2513.81)
  BOTTOM w5: v1(2632.92,2630.93) 2674.07,2630.93 TP11.1@2680,2625 2680,2609 2638.98,2567.98 2638.98,2458.02 2644,2453 2644,2335.49 U13.A2@2638.98,2330.47
PE4: TP6.1 U11.E3 U13.A1 | length 2205.1
  L4_SIG w3.5: v4(1054.47,2494) 1063.47,2503 1100,2503 1117,2520 1120,2520
  L4_SIG w4: 1120,2520 1200,2520 1225,2545 1225,2669 1254,2698 v1(1280,2698) 1327,2745 2299,2745 2376.79,2667.21 2376.79,2588.21 2385,2580 2464,2580 2496,2548 2618,2548 2685.9,2480.1 v1(2704.63,2480.1)
  BOTTOM w3.5: U11.E3@1044.84,2484.37 v4(1054.47,2494)
  BOTTOM w5: TP6.1@1240,2710 1268,2710 v1(1280,2698) ; U13.A1@2670.47,2330.47 2670.47,2411.47 2685,2426 2685,2445.75 2704.63,2465.38 v1(2704.63,2480.1)
PE5: TP8.1 U11.G1 U13.B1 | length 2084.8
  L4_SIG w4: v1(1205,2670) 1290,2755 2302,2755 2496,2561 2661,2561 2725,2497 2725,2461 v1(2705,2441)
  BOTTOM w5: U11.G1@1084.21,2523.74 1170,2609.53 TP8.1@1170,2645 1195,2670 v1(1205,2670) ; U13.B1@2670.47,2298.98 2685,2313.51 2685,2400 2705,2420 v1(2705,2441)
PE6: TP7.1 U11.E4 U13.B2 | length 2173.5
  L4_SIG w3.5: v4(1054.69,2474.54) 1055.94,2475.79 1055.94,2475.94 1075,2495 1120,2495
  L4_SIG w4: 1120,2495 1132,2495 1144,2507 1214,2507 1239,2532 1239,2624 v1(1280,2665) 1351,2736 2294,2736 2367.5,2662.5 2367.5,2582.5 2380,2570 2460,2570 2492,2538 2594,2538 2667,2465 v1(2667,2437)
  BOTTOM w3.5: U11.E4@1044.84,2464.69 v4(1054.69,2474.54)
  BOTTOM w4: U13.B2@2638.98,2298.98 2655,2315 2655,2364
  BOTTOM w5: TP7.1@1240,2645 1260,2665 v1(1280,2665) ; 2655,2364 2655,2425 v1(2667,2437)
PF11: U13.P8 U17.J9 | length 2227.6
  TOP w5: v3(2464.85,1906.17) 2464.85,1870 2469.85,1865 2480,1865 2485,1870 2485,1880 2490,1885 2500,1885 2505,1880 2505,1870 2510,1865 2550,1865 2555,1860 2555,1780 2560,1775 2655,1775 2660,1770 2660,1740 2665,1735 2675,1735 2680,1740 2680,1770 2685,1775 2700,1775 2705,1770 2705,1700 2715,1690 2785,1690 2790,1685 2790,1675 2785,1670 2720,1670 2715,1665 2715,1655 2720,1650 2785,1650 2790,1645 2790,1635 2785,1630 2720,1630 2715,1625 2715,1615 2720,1610 2785,1610 2790,1605 2790,1595 2785,1590 2720,1590 2715,1585 2715,1575 2720,1570 2785,1570 2790,1565 2790,1555 2785,1550 2720,1550 2715,1545 2715,1535 2720,1530 2785,1530 2790,1525 2790,1402 2785,1397 2453,1397 2448,1392 2448,1159 2470,1137 2470,1092 2460,1082 2460,1047 2466,1041 v3(2477.23,1041)
  BOTTOM w5: U13.P8@2450,1921.02 v3(2464.85,1906.17) ; v3(2477.23,1041) 2477.23,1044.75 U17.J9@2491.5,1059.02
PG3: CN2.5 R56.2 U13.M12 | length 2319
  TOP w5: CN2.5@815,760 870,815 R56.2@1040,815 1060,795 1430,795 1485,850 1485,1320 v1(1510,1345) ; v1(2143.5,1837) 2143.5,1855.5 2215,1927 2247.99,1927 2269.99,1949 2286,1949 2304.89,1967.89 v3(2308.37,1967.89)
  BOTTOM w5: v1(1510,1345) 1555,1345 1986.5,1776.5 2083,1776.5 v1(2143.5,1837) ; v3(2308.37,1967.89) 2308.37,1968.37 U13.M12@2324.02,1984.02
PG4: U13.N12 U17.J7 | length 2266.1
  TOP w5: v3(2308.51,1936.99) 2308.51,1936.49 2324,1936.49 2326.5,1933.99 2326.5,1863 2321.5,1858 2311,1858 2306,1853 2306,1656 2301,1651 2215.5,1651 2210.5,1646 2210.5,1636 2215.5,1631 2302,1631 2307,1626 2307,1616 2302,1611 2190,1611 2185,1606 2185,1576.03 2190,1571.03 2302,1571.03 2307,1566.03 2307,1556.03 2302,1551.03 2176,1551.03 2171,1546.03 2171,1536.03 2176,1531.03 2302,1531.03 2307,1526.03 2307,1516.03 2302,1511.03 2176,1511.03 2171,1506.03 2171,1496.03 2176,1491.03 2301,1491.03 2306,1486.03 2306,1476.03 2301,1471.03 2195,1471.03 2190,1466.03 2190,1409 2185,1404 2178,1404 2173,1399 2173,1288 2202,1259 2202,1094.5 2207,1089.5 2362.5,1089.5 2380,1107 v3(2445,1107)
  BOTTOM w5: v3(2308.51,1936.99) U13.N12@2324.02,1952.52 ; v3(2445,1107) 2474.99,1107 2490,1122.01 U17.J7@2491.5,1122.01
PG5: U13.N11 U17.H8 | length 2237.8
  TOP w5: v3(2341,1937) 2346,1932 2346,1790 2341,1785 2329,1785 2324,1780 2324,1460 2319,1455 2212,1455 2207,1450 2207,1440 2212,1435 2319,1435 2324,1430 2324,1420 2319,1415 2211,1415 2206,1410 2206,1371 2211,1366 2265,1366 2270,1361 2270,1351 2265,1346 2193,1346 2188,1341 2188,1331 2193,1326 2266,1326 2271,1321 2271,1309 2266,1304 2217,1304 2212,1299 2212,1287 2217,1282 2235,1282 2240,1277 2240,1242.54 2245,1237.54 2315,1237.54 2320,1232.54 2320,1222.54 2315,1217.54 2221,1217.54 2216,1212.54 2216,1202.54 2221,1197.54 2313,1197.54 2318,1192.54 2318,1182.54 2313,1177.54 2223,1177.54 2218,1172.54 2218,1164 2223,1159 2262,1159 2267,1154 2267,1145 2262,1140 2223,1140 2218,1135 2218,1127 2223,1122 2454,1122 2460,1116 2460,1100 2443,1083 v3(2443,1075)
  BOTTOM w5: v3(2341,1937) 2341,1938.01 U13.N11@2355.51,1952.52 ; v3(2443,1075) 2458.51,1090.51 U17.H8@2460,1090.51
PG6: R52.1 SB6.1 U13.J15 | length 2311.8
  TOP w5: R52.1@1080,660 1080,603.34 SB6.1@1083.01,600.33 1355.33,600.33 1555,800 v1(1555,1455)
  BOTTOM w5: v1(1555,1455) 1895,1795 1895,1980 1960,2045 2162,2045 2195.5,2078.5 U13.J15@2229.53,2078.5
PG7: TP22.1 U11.D3 U13.J14 | length 2670
  TOP w5: v4(1015.73,2474.94) 1010.94,2474.94 962,2426 962,2367 986,2343 1066,2343 1151,2258 1208,2258 1253,2213 1253,1472 1315,1410 1480,1410 v1(1495,1395)
  BOTTOM w3.5: v4(1015.73,2474.94) U11.D3@1025.16,2484.37
  BOTTOM w5: v1(1495,1395) 1528,1428 1567,1428 1914,1775 1914,1954 1925.5,1965.5 1956.5,1965.5 1966,1975 2049,1975 2089,2015 TP22.1@2090,2015 2151,2015 2198.8,2062.8 2245.32,2062.8 U13.J14@2261.02,2078.5
PG8: TP26.1 U13.H14 U17.J1 | length 2225
  L4_SIG w4: v3(2246.17,2095.15) 2249,2092.32 2249,2060 2244,2055 2234.74,2055 2230,2059.74 2230,2093 2225,2098 2213.85,2098 2208.85,2093 2208.85,2047.64 2204.21,2043 2197.64,2043 2193,2047.64 2193,2092 2188,2097 2159,2097 2141,2079 2141,1918 2145,1914 2204,1914 2208,1910 2208,1902 2204,1898 2146,1898 2141,1893 2141,1885 2146,1880 2203,1880 2208,1875 2208,1868 2203,1863 2182,1863 2177,1858 2177,1785 2182,1780 2192,1780 2197,1785 2197,1797 2202,1802 2212,1802 2217,1797 2217,1766 2250,1733 2284,1733 2302,1715 2302,1693 2422,1573 2422,1552 2427,1547 2448,1547 2453,1542 2453,1534 2448,1529 2407,1529 2402,1534 2402,1561 v1(2404,1563)
  BOTTOM w4: v3(2246.17,2095.15) U13.H14@2261.02,2110
  BOTTOM w5: v1(2404,1563) 2404,1583 2399,1588 2173,1588 2165,1580 2165,1539 2173,1531 TP26.1@2262,1531 2415,1531 2420,1526 2420,1382 2425,1377 2505,1377 2510,1372 2510,1337 2491.5,1318.5 U17.J1@2491.5,1310.98
PG9: CN5.7 R80.1 U13.D9 | length 972
  TOP w5: v3(2403.65,2250.83) 2403.83,2250.83 2425,2272 2425,2309 2431,2315 2431,2406 2409,2428 2409,2483 2380,2512 2380,2579 2466,2665 2690,2665 v1(2730,2705)
  BOTTOM w4: v3(2403.65,2250.83) U13.D9@2418.5,2235.98
  BOTTOM w5: v1(2730,2705) 2730,2706 2705,2731 2705,2780 R80.1@2730,2805 2732.91,2807.91 CN5.7@2732.91,2871.21
PG10: CN5.8 R79.1 U13.C8 | length 902.7
  TOP w5: v3(2464.85,2282.33) 2464.85,2289.85 2487,2312 2487,2430.75 2485,2432.75 2485,2485 2470,2500 2470,2611 2510,2651 2725,2651 v1(2780,2706)
  BOTTOM w5: U13.C8@2450,2267.48 v3(2464.85,2282.33) ; CN5.8@2776.22,2871.21 2780,2867.43 R79.1@2780,2805 2755,2780 2755,2731 v1(2780,2706)
PG11: U3.16 U13.B8 | length 1977.4
  TOP w5: v1(3663.68,1710) 3664.84,1711.16 U3.16@3664.84,1773.23
  L4_SIG w4: v1(2449.5,2405) 2484,2405 2497,2392 2497.27,2392 2497.43,2391.84 2574.16,2391.84 2599,2367 2722,2367 2733,2356 2923,2356 3029,2462 3141,2462 3281,2322 3328,2322 3395,2255 3395,2086.73 3545,1936.73 3545,1770 3605,1710 v1(3663.68,1710)
  BOTTOM w5: v1(2449.5,2405) 2459,2405 2469,2395 2469,2338.48 2467,2336.48 2467,2315.98 U13.B8@2450,2298.98
PG12: R112.2 R114.2 U13.C7 U15.4 | length 3118.9
  TOP w5: v1(765,1505) 798,1538 850,1538 v1(902,1590) ; v3(2465,2250.98) 2465,2255 2480,2270 2480,2290 2498,2308 2498,2373 2516,2391 2516,2417.84 v1(2515.91,2417.84)
  L4_SIG w4: v1(902,1590) 1203,1590 1265.5,1652.5 1265.5,2430.5 1316,2481 1596,2481 1696,2581 2220,2581 2330,2471 2434,2471 2468,2437 2481.45,2437 2495.45,2423 2511,2423 2516,2418 2516,2417.84 v1(2515.91,2417.84)
  BOTTOM w5: v1(902,1590) 902,1632 R112.2@930,1660 965,1660 965.76,1659.24 966.1,1659.24 979.41,1645.93 U15.4@979.41,1630.43 ; v3(2465,2250.98) U13.C7@2481.5,2267.48
  BOTTOM w10: v1(765,1505) R114.2@765,1540
PG13: U3.17 U13.B3 | length 1884.6
  TOP w5: U3.17@3684.53,1773.23 3684.53,1716.42 3695.95,1705 v1(3705,1705)
  L4_SIG w4: v1(2611,2425) 2618,2425 2648,2395 2941,2395 3019,2473 3146,2473 3285.44,2333.56 3331,2333.56 3405,2259.56 3405,2089.46 3555,1939.46 3555,1774 3599,1730 3680,1730 v1(3705,1705)
  BOTTOM w5: U13.B3@2607.48,2298.98 2624,2315.5 2624,2344 2633,2353 2633,2409 2619,2423 2613,2423 v1(2611,2425)
PG14: U3.18 U13.A4 | length 1852.2
  TOP w5: v1(3704.21,1735.79) U3.18@3704.21,1773.23
  L4_SIG w4: v1(2609,2464) 2609,2451.05 2628,2432.05 ; 2628,2432 2656,2404 2930,2404 3011,2485 3150,2485 3290,2345 3334.56,2345 3415,2264.56 3415,2094 3565,1944 3565,1780 3605,1740 3700,1740 v1(3704.21,1735.79)
  BOTTOM w5: U13.A4@2575.98,2330.47 2575.98,2430.98 v1(2609,2464)
PG15: U13.B7 U17.K7 | length 2296.9
  TOP w5: v3(2497.35,2281.83) 2513.34,2265.84 2513.34,2150 2523.34,2140 2629.33,2140 2639.33,2150 2639.33,2162.36 2647.82,2170.85 2674.15,2170.85 2692,2153 2692,2063 2745,2010 2761.78,2010 2848.78,1923 2927,1923 2960,1890 2995,1890 3000,1885 3000,1650 3025,1625 3025,1034 3015,1024 2596,1024 2554,1066 2554,1121 v3(2537.98,1137)
  BOTTOM w5: U13.B7@2481.5,2298.98 2481.5,2297.68 v3(2497.35,2281.83) ; U17.K7@2522.99,1122.01 v3(2537.98,1137)
PH0: R104.2 U13.G1 | length 290.8
  BOTTOM w8: U13.G1@2670.47,2141.5 2701.5,2141.5 2765,2205 R104.2@2935,2205
PH1: TP21.1 U13.H1 | length 304.8
  BOTTOM w5: U13.H1@2670.47,2110 2685.47,2125 2730,2125 2758,2153 2890,2153 2908,2135 TP21.1@2950,2135
PH2: U13.K4 U17.J2 | length 2218
  TOP w5: v1(2443,1475) 2443,1450 2448,1445 2460,1445 2465,1450 2465,1481 2478,1494 2542.22,1494 2546.22,1490 2665,1490 2670,1495 2670,1505 2665,1510 2645,1510 2640,1515 2640,1525 2645,1530 2665,1530 2670,1535 2670,1575 2665,1580 2438,1580 2433,1585 2433,1595 2438,1600 2476,1600 2480,1596 2665,1596 2670,1601 2670,1613 2665,1618 2425,1618 2420,1623 2420,1633.7 2425,1638.7 2450,1638.7 2455,1643.7 2455,1653.7 2450,1658.7 2425,1658.7 2420,1663.7 2420,1702.71 2425,1707.71 2450,1707.71 2455,1712.71 2455,1722.71 2450,1727.71 2425,1727.71 2420,1732.71 2420,1742.71 2425,1747.71 2441,1747.71 2446,1752.71 2446,1762.71 2441,1767.71 2425,1767.71 2420,1772.71 2420,1786 2423.5,1789.5 2431,1789.5 2436,1794.5 2436,1839 2430,1845 2420,1845 2415,1850 2415,1910 2439.5,1934.5 2439.5,1996.5 2460,2017 2470.2,2017 2481,2027.8 2481,2043 2486,2048 2555,2048 2560,2053 v3(2560,2062)
  BOTTOM w4: v3(2560,2062) 2560.99,2062 U13.K4@2575.98,2047.01
  BOTTOM w5: v1(2443,1475) 2448,1470 2448,1402 2453,1397 2514.18,1397 2530,1381.18 2530,1340 2507,1317 2507,1305 2491.5,1289.5 U17.J2@2491.5,1279.49
PH3: U13.J4 U17.J8 | length 2252.7
  TOP w5: v3(2507,1105) 2507,1178 2512,1183 2564,1183 2580,1167 2721,1167 2726,1162 2726,1062 2731,1057 2740,1057 2745,1062 2745,1080 2750,1085 2864.95,1085 2869.95,1080 2869.95,1060 2874.95,1055 2884.95,1055 2889.95,1060 2889.95,1080 2894.95,1085 2904.95,1085 2909.95,1080 2909.95,1060 2914.95,1055 2990,1055 2995,1060 2995,1605 2965,1635 2965,1763 2960,1768 2910,1768 2905,1773 2905,1885 2900,1890 2750,1890 2745,1895 2745,1960 2740,1965 2712,1965 2707,1970 2707,2006 2702,2011 2669,2011 2664,2016 2664,2072 2659,2077 2644,2077 2639,2082 2639,2101 2630,2110 2576.13,2110 v3(2561,2094.87)
  BOTTOM w4: v3(2561,2094.87) 2575.98,2079.89 U13.J4@2575.98,2078.5
  BOTTOM w5: U17.J8@2491.5,1090.51 2492.51,1090.51 v3(2507,1105)
PH4: U13.H4 U20.2 | length 1850.7
  L4_SIG w4: v3(2590.83,2095.15) 2590.83,2090.83 2575,2075 2575,2057.2 2565.6,2047.8 2556,2047.8 2545.34,2037.14 2545.34,1900.37 2553.54,1892.17 2564.83,1892.17 2575,1882 2575,1841.54 2631.54,1785 2663,1785 2693,1755 2693,1722 2717,1698 2795,1698 2805,1708 3016,1708 3052.13,1671.87 3052.13,814.1 3043,804.97 3043,777 v1(3060.79,759.21)
  BOTTOM w4: U13.H4@2575.98,2110 v3(2590.83,2095.15)
  BOTTOM w5: U20.2@3060.79,725.28 v1(3060.79,759.21)
PH5: TP28.1 U13.J3 U17.K8 | length 2375
  TOP w5: v3(2508,1075.66) 2497,1075.66 2492,1080.66 2492,1197 2497,1202 2680,1202 2685,1197 2685,1185 2690,1180 2740,1180 2745,1175 2745,1105 2750,1100 2924.95,1100 2929.95,1095 2929.95,1075 2934.95,1070 2975,1070 2980,1075 2980,1595 2950,1625 2950,1705 2945,1710 2895,1710 2890,1715 2890,1725 2895,1730 2945,1730 2950,1735 2950,1745 2945,1750 2895,1750 2890,1755 2890,1870 2885,1875 2735,1875 2730,1880 2730,1945 2725,1950 2700,1950 2695,1955 2695,1960 2690,1965 2655,1965 2650,1970 2650,2042 2645,2047 2595.28,2047 2590.28,2052 v3(2590.28,2061)
  BOTTOM w4: v3(2590.28,2061) 2590.28,2061.3 U13.J3@2607.48,2078.5
  BOTTOM w5: TP28.1@2470,930 2508,1060 v3(2508,1075.66) 2508.15,1075.66 U17.K8@2522.99,1090.51
PH7: CN2.6 R54.2 U13.N13 | length 2183.6
  TOP w5: CN2.6@915,760 925,770 R54.2@1040,770 1065,745 1415,745 1510,840 v1(1510,1310) ; v1(2144,1810) 2163,1829 2163,1855 2225,1917 2258.5,1917 v3(2276,1934.5)
  BOTTOM w4: v3(2276,1934.5) 2276,1936 U13.N13@2292.52,1952.52
  BOTTOM w5: v1(1510,1310) 1570,1310 1920,1660 1994,1660 v1(2144,1810)
PI4: U13.C3 U17.F8 | length 2303.6
  L4_SIG w4: v3(2380,1074) 2359,1074 2328,1043 2242,1043 2135,1150 2135,1187 2122,1200 2082,1200 1884,1398 1884,2102.98 2080.02,2299 2300,2299 2317,2282 2331.99,2267 2477,2267 2482,2272 2482,2291.33 2487,2296.33 2551.67,2296.33 2580,2268 2607,2268 v3(2623,2252)
  BOTTOM w4: U13.C3@2607.48,2267.48 v3(2623,2252)
  BOTTOM w5: v3(2380,1074) 2396.51,1090.51 U17.F8@2397.01,1090.51
PI5: U13.D3 U17.F2 | length 2397.9
  L4_SIG w4: v3(2388,1207) 2388,1121 2322,1055 2247,1055 2150,1152 2150,1189 2127,1212 2087.02,1212 2086.02,1213 1896,1403 1896,2098 2083,2285 2298,2285 2325,2258 2325,2244 2334,2235 2475,2235 2506,2266 2563.97,2266 2577.97,2252 v3(2591,2252)
  BOTTOM w4: v3(2591,2252) 2593,2250 2593.46,2250 U13.D3@2607.48,2235.98
  BOTTOM w5: v3(2388,1207) 2412,1231 2412,1264.5 U17.F2@2397.01,1279.49
PI8: TP12.1 U13.C2 | length 347.6
  BOTTOM w5: U13.C2@2638.98,2267.48 2653.83,2282.33 2674.33,2282.33 2697,2305 2697,2393 2725,2421 2725,2525 TP12.1@2755,2555
PI11: U13.F3 U20.31 | length 3059.9
  L4_SIG w4: v3(2622.33,2187.84) 2637.49,2203 2693.16,2203 2740.16,2250 2800,2250 2805,2245 3165,2245 3175,2255 3195,2255 3235,2215 3235,2135 3260,2110 3330,2110 3355,2085 3355,2070 3475,1950 3475,1790 3516.5,1748.5 3519.5,1748.5 3538,1730 3538,1296 3355,1113 3355,745 3295,685 3295,618 3232,555 3050,555 3035,570 3035,585 3000,620 2975,620 2949.21,645.79 v1(2949.21,670)
  BOTTOM w4: U13.F3@2607.48,2172.99 v3(2622.33,2187.84)
  BOTTOM w5: v1(2949.21,670) 2958.42,679.21 U20.31@3014.72,679.21
PI12: TP13.1 U13.E3 | length 438.9
  TOP w5: v3(2622.33,2219.34) 2622.33,2224.33 2655,2257 2655,2300 2709,2354 2709,2416 2725,2432 2725,2541 v1(2716,2550)
  BOTTOM w4: U13.E3@2607.48,2204.49 v3(2622.33,2219.34)
  BOTTOM w5: TP13.1@2675,2550 v1(2716,2550)
PI13: CN1.4 U13.G3 | length 1987.5
  TOP w5: CN1.4@3755.74,3050.55 3755.74,3105.74 v1(3765,3115)
  L4_SIG w4: v3(2622.33,2156.35) 2639.82,2173.84 2723.84,2173.84 2750,2200 2908,2200 2938,2230 3177,2230 v1(3185,2238)
  BOTTOM w4: U13.G3@2607.48,2141.5 v3(2622.33,2156.35)
  BOTTOM w5: v1(3185,2238) 3190,2243 3190,2590 3265,2665 3265,2838 3336,2909 3336,2986 3380,3030 3695,3030 3765,3100 v1(3765,3115)
PI14: CN1.53 U13.H3 | length 1651.9
  TOP w5: v1(2985,2170) 2970,2185 2968,2185 2968,2384 3125,2541 v1(3125,2920) ; v1(3263.61,3206.39) CN1.53@3263.61,3276.53
  L4_SIG w4: v3(2622.33,2095.15) 2637.18,2110 2925,2110 v1(2985,2170)
  BOTTOM w4: U13.H3@2607.48,2110 v3(2622.33,2095.15)
  BOTTOM w5: v1(3125,2920) 3189,2984 3189,3131.78 v1(3263.61,3206.39)
PI15: R73.1 R76.1 U13.G4 | length 1436.6
  TOP w5: v3(2590.83,2156.35) 2607.83,2173.35 2607.83,2272.83 2685,2350 2685,2489 2698,2502 2698,2573 2776.5,2651.5 3020.5,2651.5 3060,2691 v1(3060,2850)
  L4_SIG w4: v1(2943,3090) 2967,3090 3060,2997 v1(3060,2850)
  BOTTOM w4: U13.G4@2575.98,2141.5 v3(2590.83,2156.35)
  BOTTOM w5: R73.1@2915,3130 R76.1@2915,3080 2933,3080 v1(2943,3090)
PJ2: CN1.49 U13.P7 | length 1962.7
  TOP w5: v1(2955,2170) 2950,2175 2950,2391 3106,2547 3106,2931 v1(3125,2950) ; v1(3301,3215) 3302.98,3216.98 CN1.49@3302.98,3276.53
  L4_SIG w4: v3(2497,1905.52) 2513,1921.52 2513,2035.8 2526.85,2049.65 2535.14,2049.65 2546,2060.51 2546,2067.8 2554.55,2076.35 2562.28,2076.35 2576.83,2090.9 2576.83,2101.8 2597.03,2122 2711,2122 2739,2150 2935,2150 v1(2955,2170)
  BOTTOM w5: U13.P7@2481.5,1921.02 v3(2497,1905.52) ; v1(3125,2950) 3172,2997 3172,3143 3253,3224 3292,3224 v1(3301,3215)
PJ5: R63.1 U13.M14 | length 2146.4
  TOP w5: R63.1@1390,390 1390,425 v1(1395,430)
  L4_SIG w4: v1(1395,430) 1405,440 1500,440 1791,731 v1(1791,1618)
  BOTTOM w5: v1(1791,1618) 1938,1765 1938,1893 1985,1940 2167.26,1940 2194.28,1967.02 2244.02,1967.02 U13.M14@2261.02,1984.02
PJ12: U11.G3 U13.B10 | length 1826.2
  L4_SIG w3.5: v4(1093.96,2474.62) 1115.38,2474.62 1120,2470
  L4_SIG w4: 1120,2470 1215,2470 1250,2505 1250,2605 1370,2725 2212.06,2725 2297.06,2640 v1(2335,2640)
  BOTTOM w3.5: U11.G3@1084.21,2484.37 v4(1093.96,2474.62)
  BOTTOM w5: v1(2335,2640) 2326,2631 2326,2519 2370.5,2474.5 2370.5,2315.49 U13.B10@2387.01,2298.98
PJ13: R62.1 U13.B9 | length 2862
  TOP w5: R62.1@1290,390 1315,390 v1(1355,430)
  L4_SIG w4: v1(1355,430) 1385,460 1496,460 1773,737 1773,2108 2083,2418 2281,2418 2296,2403 2296,2387 2314,2369 v1(2402.5,2369)
  BOTTOM w5: v1(2402.5,2369) 2402.5,2314.98 U13.B9@2418.5,2298.98
PJ14: CN2.4 R200.2 U13.C9 | length 3182.2
  TOP w5: CN2.4@915,860 R200.2@1040,860 1065,885 v1(1205,885) ; v1(2402.5,2406) 2402.5,2405 2420,2387.5 2420,2327 2403.49,2310.49 v3(2403.49,2282.49)
  L4_SIG w4: v1(1205,885) 1296,976 1296,2301 1380,2385 1555,2385 1720,2550 2177,2550 2262,2465 2304,2465 2319,2450 2358.5,2450 v1(2402.5,2406)
  BOTTOM w5: v3(2403.49,2282.49) U13.C9@2418.5,2267.48
PJ15: CN1.57 R8.2 U13.D10 | length 1832.8
  TOP w5: v3(2372.16,2250.83) 2386.5,2265.17 2386.5,2303 2385,2304.5 2385,2423 2395,2433 2395,2478 2369,2504 2369,2584 2460,2675 2641,2675 2726,2760 2785,2760 v1(2815,2730) ; v1(3222.51,3336.92) 3224.24,3335.19 CN1.57@3224.24,3276.53
  BOTTOM w4: v3(2372.16,2250.83) U13.D10@2387.01,2235.98
  BOTTOM w5: v1(2815,2730) 2815,2756 3000,2941 3000,3232 3068,3300 R8.2@3220,3300 3220,3334.41 v1(3222.51,3336.92)
PK3: TP9.1 U13.D8 | length 472.5
  BOTTOM w5: U13.D8@2450,2235.98 2435,2250.98 2435,2334.48 2432,2337.48 2432,2414 2440.5,2422.5 2452.5,2422.5 2470,2440 2470,2615 2490,2635 TP9.1@2525,2635
PK4: TP18.1 U13.D7 | length 324
  TOP w5: v1(2440,2440) 2440.53,2440 2443.06,2437.47 2461.53,2437.47 2477,2422 2477,2317 2450,2290 2450,2235 v3(2465,2220)
  BOTTOM w4: v3(2465,2220) 2480.98,2235.98 U13.D7@2481.5,2235.98
  BOTTOM w5: TP18.1@2435,2475 2435,2445 v1(2440,2440)
PK5: TP17.1 U13.C6 | length 232
  TOP w4: v3(2527.84,2282.33) 2527.84,2359.25 2532.59,2364
  TOP w5: v1(2527.5,2440) 2527.5,2437.5 2541,2424 2541,2372.41 2532.59,2364
  BOTTOM w5: TP17.1@2510,2475 2527.5,2457.5 v1(2527.5,2440) ; U13.C6@2512.99,2267.48 v3(2527.84,2282.33)
PK6: TP16.1 U13.C5 | length 220.2
  BOTTOM w5: U13.C5@2544.49,2267.48 2560,2282.99 2560,2460 TP16.1@2575,2475
PK7: TP15.1 U13.C4 | length 332.7
  TOP w5: v3(2590.83,2282.33) 2647,2338.5 2647,2481 v1(2680,2514)
  BOTTOM w4: U13.C4@2575.98,2267.48 v3(2590.83,2282.33)
  BOTTOM w5: TP15.1@2670,2475 2680,2485 v1(2680,2514)
POE1: C3.1 C4.2 C9.1 C12.1 C20.1 C24.1 C70.1 C75.1 C81.1 R9.1 R12.1 R74.1 T2.1 T100.4 U1.9 U10.3 | length 1168.6
  TOP w12: v1(4100,3250) 4095,3245 4095,3220 4105.43,3209.57 U1.9@4123.86,3209.57
  TOP w20: v1(3405,2520) C81.1@3455,2520 v1(3455,2565) ; v1(3522,2586) 3522,2561 C70.1@3540,2543 3557,2560 v1(3557,2587) ; v1(3616,2587) 3616,2552 C75.1@3625,2543 3645,2563 v1(3645,2587) ; R9.1@3876,2905 v2(3876,2962) ; R12.1@3890,2800 v2(3890,2843) ; v2(3920,3105) C9.1@3965,3105 ; C3.1@3978,3360 v2(3978,3412) ; v2(4020,2902) 4020,2920 4025,2925 C12.1@4025,2945 ; C4.2@4360,3325 v2(4360,3370)
  BOTTOM w15: C24.1@3630,2620 v1(3670,2620)
  BOTTOM w20: v1(3520,2280) 3542,2258 C20.1@3542,2225 3542,2193 v1(3570,2165) ; v1(3676,2586) 3708.89,2553.11 T100.4@3732.05,2553.11 3750.11,2553.11 3778.64,2581.64 T2.1@3859.21,2581.64 ; v2(3920,3105) 3925.51,3099.49 R74.1@3965,3099.49 ; v2(4020,2902) U10.3@4020,2990.08
POE2: R24.2 T2.2 T100.3 | length 230.2
  BOTTOM w20: R24.2@3635,2480 3640.63,2474.37 T100.3@3732.05,2474.37 3850.37,2474.37 T2.2@3859.21,2483.21
POE3: R23.2 T1.2 T1.4 T2.3 T100.2 | length 948.8
  TOP w20: 3437.46,2720 T1.4@3480.98,2720 ; 3480.98,2646.98 T1.4@3480.98,2720 ; 3480.98,2793.02 T1.4@3480.98,2720 ; 3524.5,2720 T1.4@3480.98,2720 ; T1.2@3729.02,2720 3750,2720 v1(3780,2690)
  TOP w40: 3670,2720 T1.2@3729.02,2720
  L4_SIG w20: v1(3685,2440) 3725,2440 3780,2495 v1(3780,2690)
  BOTTOM w20: v1(3685,2440) 3655,2410 R23.2@3655,2385 3700,2385 3710.63,2395.63 T100.2@3732.05,2395.63 3848.37,2395.63 T2.3@3859.21,2384.79
POE4: C20.2 C22.2 L5.1 T2.4 T100.1 | length 701.8
  TOP w20: 3546.98,2234.92 L5.1@3615,2234.92 ; 3615,2196.9 L5.1@3615,2234.92 ; 3683.02,2234.92 L5.1@3615,2234.92
  BOTTOM w20: 3626.98,2225 C20.2@3658,2225 ; 3635,2280.98 C22.2@3635,2305 ; 3635,2329.02 C22.2@3635,2305 ; 3658,2186.98 C20.2@3658,2225 ; 3658,2263.02 C20.2@3658,2225 ; 3660.52,2305 C22.2@3635,2305 ; 3689.02,2225 C20.2@3658,2225 ; 3691.03,2316.89 T100.1@3732.05,2316.89 ; 3732.05,2284.87 T100.1@3732.05,2316.89 ; 3773.07,2316.89 T100.1@3732.05,2316.89 ; 3791.19,2286.36 T2.4@3859.21,2286.36 ; 3859.21,2253.34 T2.4@3859.21,2286.36 ; 3859.21,2319.38 T2.4@3859.21,2286.36 ; 3927.23,2286.36 T2.4@3859.21,2286.36
  other v1: 3640,2175 3675,2175 3700,2175
POE5: D2.1 R22.1 T2.5 T2.6 T100.7 T100.8 | length 788.5
  BOTTOM w20: 4471.98,2394.45 D2.1@4525,2394.45 ; 4525,2351.43 D2.1@4525,2394.45 ; 4525,2437.47 D2.1@4525,2394.45 ; 4578.02,2394.45 D2.1@4525,2394.45 ; 4611.98,2425 R22.1@4640,2425 ; 4640,2391.98 R22.1@4640,2425 ; 4640,2458.02 R22.1@4640,2425
  BOTTOM w40: T100.8@4187.95,2316.89 4214.47,2316.89 4245,2286.36 T2.5@4340.79,2286.36 4431.36,2286.36 ; T100.7@4187.95,2395.63 4249.37,2395.63 4260.21,2384.79 T2.6@4340.79,2384.79 4429.79,2384.79
POE7: B2.2 B2.3 C1.1 C2.1 C3.2 C13.1 C14.1 C15.1 C16.1 C18.1 C23.1 C25.1 C27.1 C28.1 C29.1 C30.1 C31.1 C33.1 C35.1 C36.2 C38.2 C41.2 C42.1 C43.1 C44.2 C45.2 C46.1 C47.1 C48.1 C49.1 C50.1 C51.1 C52.1 C53.1 C54.1 C55.2 C56.2 C63.1 C64.2 C65.2 C66.2 C67.1 C68.2 C69.2 C71.2 C72.1 C73.1 C74.2 C76.1 C77.1 C78.2 C79.1 C80.1 C83.1 C84.1 C85.1 C86.1 C88.1 C90.2 C91.2 C92.2 C93.2 C94.2 C95.1 C96.1 C97.1 C98.1 C99.1 C100.1 C101.2 C102.1 C103.1 C104.1 C105.1 C106.1 C107.1 C108.1 C109.1 C110.1 C111.1 C112.1 C113.1 C114.1 C115.1 C116.2 C117.1 C118.1 C123.1 C124.1 C125.1 C126.1 C127.1 C128.1 C129.1 C130.1 C131.1 C132.1 C133.1 C134.1 C135.1 C136.1 C137.1 C138.1 C139.1 C140.2 C141.1 C142.1 C143.1 C144.2 C145.1 C146.1 C147.2 C148.2 C149.1 C150.2 C151.1 C152.1 C153.1 C154.1 C155.1 C156.1 C157.1 CN1.1 CN1.6 CN1.7 CN1.12 CN1.13 CN1.18 CN1.19 CN1.61 CN1.62 CN1.63 CN1.64 CN4.3 CN5.6 CN5.9 CN6.2 CN6.3 CN7.2 CN7.3 CN8.1 CN8.2 CN8.3 CN9.7 CN11.6 CN11.7 CN12.1 CN12.2 CN12.3 CN16.5 CN16.6 CN16.7 CN16.8 CN16.9 CN16.10 CN16.11 D12.B1 D12.B2 D13.B1 D13.B2 H1.1 H2.1 H3.1 H4.1 H5.1 H6.1 H7.1 H8.1 JP1.2 L3.1 L8.1 LD1.2 LD2.2 LD3.2 LD6.2 LD8.1 R14.1 R15.1 R18.1 R21.1 R28.1 R29.1 R31.2 R40.1 R70.1 R77.2 R78.2 R96.2 R102.2 R105.1 R108.1 R111.1 R113.1 R119.1 R121.1 R122.1 R124.1 R127.1 R128.1 R131.2 R133.1 R135.1 R139.2 R140.2 R146.1 R149.1 SB1.2 SB2.2 SB3.2 SB4.2 SB5.1 SB8.1 SB16.1 T2.7 T2.8 T5.2 T100.5 T100.6 U2.5 U3.25 U4.2 U5.2 U5.5 U6.5 U7.2 U7.7 U8.2 U8.5 U9.5 U11.A1 U11.A3 U11.A4 U11.A5 U11.C1 U11.D6 U11.E2 U11.E7 U11.E8 U11.F7 U11.G5 U11.H9 U12.4 U13.F2 U13.F6 U13.F7 U13.F8 U13.F9 U13.F10 U13.G6 U13.G10 U13.G12 U13.H6 U13.H10 U13.J6 U13.J10 U13.K6 U13.K7 U13.K8 U13.K9 U13.K10 U13.L6 U13.M1 U13.N1 U14.1 U15.3 U16.3 U17.A3 U17.B3 U17.B8 U17.C1 U17.D1 U17.E9 U17.F1 U17.L3 U17.L9 U17.M1 U17.N1 U17.P3 U17.P8 U17.R3 U18.1 U19.8 U19.20 U19.23 U19.35 U19.47 U20.33 U21.2 U22.4 U250.4 X2.2 X4.2 | length 13554.8
  TOP w10: CN1.19@3598.26,3276.53 3598.26,3321.26 3602.44,3325.44 3602.44,3325.68 3608.29,3331.53 3608.53,3331.53 3620,3343 v2(3630,3343) 3639.62,3343 3657.31,3325.31 CN1.13@3657.31,3276.53 ; CN1.18@3617.94,3050.55 v2(3617.94,3120) ; v2(3670,3120) 3677,3113 CN1.12@3677,3050.55 ; v2(3705,3340) 3716.37,3328.63 CN1.7@3716.37,3276.53 ; v2(3730,3120) 3736.05,3113.95 CN1.6@3736.05,3050.55
  TOP w11: CN1.1@3775.42,3276.53 v2(3775.42,3340)
  TOP w15: v2(2004,793.55) U5.5@2040.43,793.55 ; v2(2015.06,208.94) U8.5@2040.43,208.94 ; C25.1@2399,2126 2399,2098 v3(2404,2093) ; v3(2404,2064) 2405,2063 C27.1@2405,2039 ; v2(2590,793.55) U6.5@2625.04,793.55 ; v2(2590.06,208.94) U9.5@2625.04,208.94
  TOP w20: v1(1006,305) C54.1@1040,305 ; R70.1@1080,215 v1(1118,215) ; SB8.1@1083.01,530.33 v1(1124.67,530.33) ; SB5.1@1083.01,965.33 v1(1118.01,965.33) ; LD1.2@1290,185 v1(1330,185) ; LD2.2@1390,185 v1(1435,185) ; LD3.2@1490,185 v1(1530,185) ; U250.4@1730,2588.98 1730,2600 1755,2625 v2(1760,2625) ; LD6.2@1780,185 v1(1820,185) ; v2(1940,1985) C31.1@1982,1985 ; U8.2@2082.86,224.67 2082.86,245.86 2093,256 v2(2107,256) ; U5.2@2082.86,809.28 2082.86,832.86 2090,840 v2(2107,840) ; v2(2165,2370) 2190,2345 C23.1@2190,2303 ; v2(2265,218) C55.2@2265,255 ; C44.2@2265,836 2304,836 v2(2310,830) ; R18.1@2510,2570 2519.76,2579.76 v2(2519.76,2598) ; R21.1@2635,2570 v2(2635,2602) ; v2(2807.57,175) C56.2@2807.57,215 ; C45.2@2810,800 v2(2845,800) ; v2(2916,385) 2955,385 C52.1@2975,405 2955,425 v2(2916,425) ; v2(3101,3163.54) CN1.64@3172.47,3163.54 ; v1(3187.51,2840) C2.1@3187.51,2881.92 ; v2(3250,3163.54) CN1.63@3364.99,3163.54 ; v1(3366.92,2881.92) C1.1@3407.51,2881.92 ; v2(3410,1790) R40.1@3440,1790 ; v2(3410,1835) C33.1@3440,1835 ; LD8.1@3420.47,155.94 3420.47,206.47 3429,215 v2(3430,215) ; v1(3478.81,2873.81) SB4.2@3478.81,2909.17 ; C28.1@3530,2030 v2(3530,2080) ; v1(3548.81,2870) SB3.2@3548.81,2909.17 ; v2(3565,2055) 3565,2035 C29.1@3580,2020 ; v2(3575,1514.9) C38.2@3575,1565 v2(3630,1565) ; CN1.62@3614.99,3163.54 v1(3731,3163.54) ; v1(3618.81,2870) SB2.2@3618.81,2909.17 ; R28.1@3660,2020 v2(3660,2050) ; v1(3675,2875) 3688.81,2888.81 SB1.2@3688.81,2909.17 ; R29.1@3700,2020 v2(3700,2050) ; v2(3745,2050) C30.1@3750,2020 ; C35.1@3800,1635 3824.3,1610.7 v2(3824.3,1610.4) ; CN1.61@3807.51,3163.54 v2(3880,3163.54) ; v2(3823,1550) 3855,1550 C36.2@3870,1565 3855,1580 v2(3823,1580) ; C3.2@3862,3360 v2(3862,3417) ; v2(3870,2055) 3890,2035 R31.2@3890,1980 ; C53.1@3945,395 v2(3945,430) ; v2(3960,835) 3970,845 C41.2@3995,845 ; C42.1@4045,855 4045,820 v1(4060,805) ; U2.5@4052.24,2857.4 v2(4106,2857.4) ; B2.3@4057.83,212.5 v2(4105,212.5) ; v1(4080,500) C51.1@4120,500 ; v1(4080,620) C48.1@4120,620 ; v1(4080,650) C47.1@4110,680 ; v1(4098,570) C49.1@4130,570 ; v2(4125,2620) R14.1@4125,2655 ; U4.2@4140,812.76 4140,775 v1(4145,770) ; v1(4180,660) C46.1@4180,700 ; R15.1@4180,2655 v2(4215,2655) ; 4201.98,2915 C13.1@4235,2915 ; 4235,2945.52 C13.1@4235,2915 ; C43.1@4245,845 4245,815 v2(4255,805) ; v1(4265,2705) C18.1@4305,2705 v1(4305,2660) ; 4268.02,2915 C13.1@4235,2915 ; 4276.98,2915 C14.1@4310,2915 ; 4310,2945.52 C14.1@4310,2915 ; v2(4340,235) 4362.5,212.5 B2.2@4412.17,212.5 ; 4343.02,2915 C14.1@4310,2915 ; 4351.98,2915 C15.1@4385,2915 ; U7.2@4356.52,530 4410,530 C50.1@4415,535 v1(4415,570) ; 4385,2945.52 C15.1@4385,2915 ; 4418.02,2915 C15.1@4385,2915 ; 4430.98,2905 C16.1@4455,2905 ; 4455,2930.52 C16.1@4455,2905 ; 4479.02,2905 C16.1@4455,2905
  BOTTOM w9: v2(930,2475) 939.37,2484.37 U11.A3@966.1,2484.37 ; U11.C1@1005.47,2523.74 v2(1005.47,2549.6) ; U11.D6@1025.16,2425.31 v4(1034.91,2415.56) ; U11.E8@1044.84,2385.94 v4(1035,2395.79) U11.E7@1044.84,2405.63 ; U11.E2@1044.84,2504.06 1049.88,2509.1 v4(1054.7,2513.9) ; U11.F7@1064.53,2405.63 v4(1074.38,2395.78) ; U11.G5@1084.21,2445 v4(1093.96,2435.25) ; U11.H9@1103.9,2366.26 1103.9,2366.1 v2(1125,2345) ; v2(3085,293) 3107.13,270.87 D13.B1@3110.13,270.87 ; D13.B2@3125.87,270.87 v2(3150,295) ; D12.B1@3177.13,272.87 3177.13,314.46 v2(3185.67,323) 3192.87,315.8 D12.B2@3192.87,272.87
  BOTTOM w10: v2(930,2475) 940.31,2464.69 U11.A4@966.1,2464.69 ; v2(940,2430) 955,2445 U11.A5@966.1,2445 ; v4(952.26,2537.36) 952.26,2536.48 965,2523.74 U11.A1@966.1,2523.74 ; U19.47@3588.74,728.58 v2(3640,728.58) ; U19.35@3671.42,468.74 v2(3671.42,520) ; v2(3789.53,760) U19.8@3789.53,811.26 ; v2(3885,551.42) U19.23@3931.26,551.42 ; v2(3885,610.47) U19.20@3931.26,610.47
  BOTTOM w15: v2(819.41,1509.41) U16.3@819.41,1559.57 ; v2(979.41,1515) U15.3@979.41,1559.57 ; v2(2150,1687) C115.1@2150,1715 ; v2(2170,1465) C125.1@2210,1465 ; C114.1@2205,1715 C113.1@2255,1715 v2(2255,1684) ; v3(2224,1263.51) U17.A3@2239.53,1247.99 ; v3(2255,1107) 2255,1106.53 U17.B8@2271.02,1090.51 ; v3(2255,1264) U17.B3@2271.02,1247.99 ; v2(2257,910) C138.1@2290,910 ; v3(2287,1326) 2287,1326.5 U17.C1@2302.52,1310.98 ; C112.1@2305,1715 C111.1@2360,1715 v2(2360,1685) ; v3(2319,1325.99) U17.D1@2334.02,1310.98 ; U13.G12@2324.02,2141.5 2340,2157.48 v3(2340,2159.84) ; C137.1@2335,910 v2(2372,910) ; C124.1@2345,1465 v2(2377,1465) ; U17.E9@2365.51,1059.02 2365.51,1042.49 v3(2374,1034) ; v3(2371,2095) 2387.01,2078.99 U13.J10@2387.01,2078.5 ; v3(2372.16,2187.84) U13.F10@2387.01,2172.99 ; v3(2381,1328) 2380,1328 U17.F1@2397.01,1310.98 ; U13.K10@2387.01,2047.01 v3(2404,2064) 2418.5,2049.5 U13.K9@2418.5,2047.01 ; U13.H10@2387.01,2110 v3(2404,2093) ; U13.G10@2387.01,2141.5 v3(2401.86,2156.35) ; v3(2403.65,2187.84) U13.F9@2418.5,2172.99 ; C136.1@2405,910 v2(2436,910) ; C110.1@2405,1715 C109.1@2450,1715 v2(2450,1686) ; U13.K8@2450,2047.01 v3(2464.85,2032.16) ; U13.F8@2450,2172.99 v3(2465,2157.99) ; U13.K7@2481.5,2047.01 v3(2496.35,2032.16) ; U13.F7@2481.5,2172.99 v3(2496.35,2187.84) ; v3(2498,2156.49) U13.G6@2512.99,2141.5 ; v3(2498.14,2095.15) U13.H6@2512.99,2110 ; v2(2510,910) C135.1@2540,910 ; U13.L6@2512.99,2015.51 v3(2527.84,2000.66) ; U13.K6@2512.99,2047.01 2497.84,2062.16 v3(2497.84,2063.65) 2512.69,2078.5 U13.J6@2512.99,2078.5 ; U13.F6@2512.99,2172.99 v3(2527.84,2187.84) ; v2(2524,1459) 2530,1465 C123.1@2555,1465 ; v3(2539,1263) 2539,1263.48 U17.L3@2554.49,1247.99 ; C108.1@2545,1715 v1(2574,1715) ; U17.L9@2554.49,1059.02 2554.49,1059.49 v3(2570,1075) ; v2(2571,910) C134.1@2600,910 ; U17.M1@2585.98,1310.98 2600,1325 v3(2600,1327) ; C107.1@2600,1715 v1(2629,1715) C106.1@2655,1715 ; U17.N1@2617.48,1310.98 2619.02,1310.98 v3(2634,1296) ; v3(2633,1107) 2640.53,1099.47 2640.53,1098.96 U17.P8@2648.98,1090.51 ; v2(2637,909) 2638,910 C133.1@2670,910 ; U13.F2@2638.98,2172.99 2654,2188.01 v3(2655,2188.01) ; U17.P3@2648.98,1247.99 2648.98,1242.02 v3(2671,1220) ; U13.N1@2670.47,1952.52 2672.48,1952.52 2686.99,1938.01 v3(2686.99,1937.67) ; U13.M1@2670.47,1984.02 v3(2692,1984.02) ; U17.R3@2680.47,1247.99 2693.48,1261 v3(2700,1261) ; C105.1@2695,1715 v1(2725,1715) C104.1@2755,1715 ; v2(2840,1064) C131.1@2840,1095 ; C128.1@2840,1145 2840,1181 v2(2845,1186) ; C126.1@2840,1250 2840,1282 2845,1287 v2(2845,1291) ; C99.1@2850,2130 v2(2881,2130) ; C97.1@2850,2180 2884,2180 v2(2885,2179) ; C88.1@2850,2230 2880,2230 v2(2884,2226) ; C86.1@2850,2280 2879,2280 v2(2883,2276) ; C83.1@2850,2325 v2(2880,2325) ; C80.1@2850,2375 v2(2880,2375) ; C103.1@2905,1790 v2(2935,1790) ; C102.1@2905,1850 2940,1850 2944,1854 v2(2944,1855) ; v2(2930,1666) 2930,1710 C116.2@2940,1720 2965,1745 v2(2965,1789) ; v2(2969,1978) 2969,1974 2940,1945 C101.2@2940,1930 v2(2985,1930) ; v2(3660,209) 3661,209 3683.82,186.18 CN16.5@3683.82,162.4
  BOTTOM w20: CN12.2@474.65,1462.72 v2(642.72,1462.72) ; CN12.3@474.65,1987.28 v2(645.03,1987.32) v2(645.03,1987.32) ; CN8.2@474.65,2132.72 v2(650,2132.72) ; CN8.3@474.65,2657.28 v2(655,2657.28) ; R102.2@710,2295 v2(710,2330) ; R111.1@715,1625 718,1625 v2(741,1602) ; v2(740,2400) C79.1@785,2400 ; v2(740,2455) C73.1@785,2455 ; v2(770,2505) C71.2@805,2505 ; v2(770,2965) R78.2@770,3000 ; C118.1@825,1695 v2(825,1730) ; v2(845,2605) C67.1@845,2645 ; v2(915,2145) C95.1@915,2185 ; v2(920,2690) 930,2680 C65.2@960,2680 ; v2(965,2145) C94.2@965,2185 ; C117.1@990,1695 v2(990,1727) ; v2(1013.1,3418.1) CN7.2@1097.48,3418.1 ; v2(1015,2145) C93.2@1015,2185 ; v2(1021.07,3303.93) CN7.3@1097.48,3303.93 ; C64.2@1055,2680 v2(1055,2715) ; v2(1065,2145) C92.2@1065,2185 ; C63.1@1105,2705 v2(1105,2750) ; v2(1115,2155) C91.2@1115,2195 ; 1120,2030.98 C100.1@1120,2055 ; 1120,2079.02 C100.1@1120,2055 ; R77.2@1140,3040 v2(1187.7,3040) ; 1145.52,2055 C100.1@1120,2055 ; 1170.5,1980.55 U14.1@1214.02,1980.55 ; v2(1175,2145) C90.2@1175,2185 ; 1214.02,2008.57 U14.1@1214.02,1980.55 ; 1257.54,1980.55 U14.1@1214.02,1980.55 ; C78.2@1285,2390 v2(1326,2390) ; C74.2@1285,2440 v2(1325,2440) ; v2(1515,2310) C85.1@1565,2310 ; v2(1695,2185) C96.1@1730,2185 ; CN6.3@1772.48,3303.93 v2(1854.93,3303.93) ; CN6.2@1772.48,3418.1 v2(1852.9,3418.1) ; U12.4@1880,2588.54 1880,2595 1898,2613 v2(1910,2613) ; v2(2039,1135) 2054,1150 C127.1@2075,1150 ; v2(2070,2601) 2070,2556 2093,2533 C72.1@2110,2533 2110,2595 v2(2103,2602) ; v2(2075,1071) C130.1@2075,1105 ; v2(2312,552.6) T5.2@2358.31,552.6 ; v2(2430,412) C148.2@2430,460 ; v2(2459,590) R131.2@2490,590 ; U21.2@2530,522.24 v2(2530,562) ; CN5.6@2689.61,2871.21 v2(2689.61,2925) ; v2(2787,2591) 2821,2591 C69.2@2835,2605 2819,2621 v2(2787,2621) ; v2(2805,670) 2810,675 C144.2@2810,700 ; C147.2@2815,515 v2(2851,515) ; CN5.9@2821.5,2871.21 v2(2821.5,2978) ; X4.2@2846.42,633.54 v2(2877.88,665.04) ; R108.1@2850,2045 v2(2882,2045) ; C76.1@2850,2425 v2(2880.86,2425) ; v2(2855,125) 2880,150 C156.1@2880,160 ; L8.1@2870,230 2870,205 v2(2885,190) ; C153.1@2880,285 v2(2880,330) ; v2(2910,496) R139.2@2910,530 ; C145.1@2910,630 v2(2910,665) ; v2(2994,2136.46) X2.2@3033.58,2136.46 ; v2(2995,2585) 2960,2585 C68.2@2940,2605 2955,2620 v2(2995,2620) ; C84.1@3020,2290 v2(3049,2290) ; C77.1@3020,2415 v2(3048,2415) ; C150.2@3045,415 3045.36,414.64 v2(3045.36,360) ; v2(3080,355) 3100,375 C149.1@3100,415 ; C98.1@3170,2140 v2(3205,2140) ; R124.1@3180,830 v2(3180,867) ; C154.1@3240,285 v2(3240,325) ; R133.1@3305,600 v2(3340,600) ; R128.1@3305,660 v2(3340,660) ; 3420,35.98 C157.1@3420,55 ; 3420,74.02 C157.1@3420,55 ; 3439.02,55 C157.1@3420,55 ; v2(3455,575) R135.1@3490,575 ; v2(3460,670) R127.1@3490,670 ; v2(3460,750) C143.1@3490,750 ; L3.1@3467.51,3306.92 3467.51,3342.51 v2(3468,3343) ; 3565.68,57.09 CN16.7@3597.2,57.09 3597.2,102.61 ; R122.1@3570,935 v2(3570,970) ; 3599.05,163.39 CN16.9@3636.57,163.39 3636.57,125.87 ; v2(3615,360) C151.1@3650,360 ; R121.1@3615,935 v2(3615,970) ; v2(3645,925) 3645,920 3665,900 C142.1@3675,900 ; 3657.91,57.09 CN16.11@3695.63,57.09 ; R149.1@3685,275 v2(3685,325) ; 3695.63,109.37 CN16.11@3695.63,57.09 ; 3774.37,109.37 CN16.10@3774.37,57.09 ; v2(3775,870) 3780,870 3800,890 C141.1@3800,900 ; 3812.09,57.09 CN16.10@3774.37,57.09 ; v2(3830,310) 3830,295 R146.1@3850,275 ; 3833.43,125.87 CN16.8@3833.43,163.39 3870.95,163.39 ; 3872.8,102.61 CN16.6@3872.8,57.09 3904.32,57.09 ; v2(3905,870) C140.2@3905,900 ; C132.1@3905,1000 v2(3930,975) ; v2(3970,214) 3979,205 C155.1@4005,205 ; R119.1@4000,940 v2(4030,940) ; SB16.1@4003.01,999.67 v2(4003.01,1045) ; v1(4045,475) 4045,455 4060,440 U22.4@4081.7,440 ; v1(4045,505) C146.1@4045,540 ; v1(4144,465) 4144,474 R140.2@4170,500 ; C66.2@4230,2705 4230,2690 v1(4250,2670) ; 4282.53,865.98 U18.1@4310.55,865.98 ; 4305,716.98 C129.1@4305,750 ; 4305,783.02 C129.1@4305,750 ; 4310.55,822.46 U18.1@4310.55,865.98 ; 4310.55,909.5 U18.1@4310.55,865.98 ; 4335.52,750 C129.1@4305,750 ; 4338.57,865.98 U18.1@4310.55,865.98 ; 4340.79,2516.23 T2.7@4340.79,2483.21 4408.81,2483.21 ; 4340.79,2548.62 T2.8@4340.79,2581.64 ; 4340.79,2614.66 T2.8@4340.79,2581.64 ; v2(4350,270) 4350,290 C152.1@4365,305 4380,290 v2(4380,270) ; 4366.98,900 C139.1@4400,900 ; 4400,869.48 C139.1@4400,900 ; 4408.81,2581.64 T2.8@4340.79,2581.64 ; v1(4426,2250) R105.1@4455,2250 ; 4433.02,900 C139.1@4400,900 ; 4456.98,875 JP1.2@4495,875 ; 4495,836.98 JP1.2@4495,875 ; 4495,913.02 JP1.2@4495,875 ; 4533.02,875 JP1.2@4495,875 ; v2(4575,1551.8) R113.1@4575,1590 ; R96.2@4785,2495 v2(4785,2556) ; CN16.11@3695.63,57.09 CN16.10@3774.37,57.09
  BOTTOM w40: T100.6@4187.95,2474.37 4244.37,2474.37 4253.21,2483.21 T2.7@4340.79,2483.21 ; T100.5@4187.95,2553.11 4218.11,2553.11 4246.64,2581.64 T2.8@4340.79,2581.64
  other v1: 4276,492 4324,492 4299,527 4278,569 4325,569 3055,575 3110,575 3165,575 3055,630 3110,630 3165,630 3055,685 3110,685 3165,685 3614,1811 3655,1812 3695,1812 3614,1851 3695,1851 3655,1852 3614,1891 3655,1891 3695,1891 4425,2495 4425,2520 4425,2560 4425,2605
  other v2: 2694,160 2108,161 2178,208 2762,210 3159,231 2695,255 3193,470 2693,744 2110,745 2178,794 2762,794 4350,810 4380,810 2692,840 4350,840 4380,840 3791,1852 3797,1933 1160,2065 1190,2065 1125,2100 1160,2100 1190,2100 4180,2930 4180,2966 4230,2970 4280,2970 4340,2970 4380,2970
PWR_ENN: R144.1 U19.28 U22.3 | length 418.9
  L4_SIG w4: v1(3809.21,519.21) 3809.21,480.79 3840,450 3967,450 v1(3978,439)
  BOTTOM w5: U19.28@3809.21,468.74 v1(3809.21,519.21) ; v1(3978,439) 3990,427 3990,400 R144.1@4005,385
  BOTTOM w10: R144.1@4005,385 4010,390 U22.3@4081.7,390
PWR_EXT: R135.2 R138.1 R141.1 U19.39 | length 155.4
  BOTTOM w10: R141.1@3530,480 R138.1@3530,530 R135.2@3530,575 3533.9,571.1 U19.39@3588.74,571.1
RD_N: R37.2 T4.8 U3.22 | length 493
  TOP w6.1: U3.22@3731.77,1859.84 3742.65,1859.84 3745,1862.19 3763.41,1862.19 3783.72,1882.5 3804.31,1882.5 v1(3809.81,1877) 3815.31,1882.5 3832.5,1882.5 R37.2@3845,1870
  BOTTOM w6.1: v1(3809.81,1877) 3804.31,1882.5 3782.5,1882.5 3760,1905 3760,1951.22 3823.78,2015 3898,2015 3908,2025 T4.8@3982.48,2025
RD_P: R35.2 T4.6 U3.23 | length 492.5
  TOP w6.1: U3.23@3731.77,1879.53 3742.66,1879.53 3745,1877.19 3757.19,1877.19 3777.5,1897.5 3804.31,1897.5 v1(3809.81,1903) 3815.31,1897.5 3832.5,1897.5 R35.2@3845,1910
  BOTTOM w6.1: v1(3809.81,1903) 3804.31,1897.5 3788.72,1897.5 3775,1911.22 3775,1945 3830,2000 3898,2000 3908,1990 3908,1952 3935,1925 T4.6@3982.48,1925
REFSEL0: R123.1 R124.2 U20.8 | length 105.2
  BOTTOM w5: U20.8@3178.9,725.28 3178.9,788.9 R124.2@3180,790 R123.1@3220,790
REFSEL1: R125.1 R128.2 U20.11 | length 99.9
  BOTTOM w5: U20.11@3205.28,659.53 3264.53,659.53 R128.2@3265,660 R125.1@3265,700
REFSEL2: R133.2 R137.1 U20.14 | length 99.9
  BOTTOM w5: U20.14@3205.28,600.47 3264.53,600.47 R133.2@3265,600 R137.1@3265,560
SCLK_MCLK: CN1.35 TP1.1 | length 128.3
  TOP w5: v1(3425,3340) 3440.78,3324.22 CN1.35@3440.78,3276.53
  BOTTOM w5: TP1.1@3405,3290 3405,3320 v1(3425,3340)
STLINK_RX: SB18.2 U19.13 | length 85.3
  BOTTOM w5: U19.13@3931.26,748.27 3953.27,748.27 3970,765 4007.98,765 SB18.2@4009.17,763.81
STLINK_TX: SB17.2 U19.12 | length 150.2
  BOTTOM w5: U19.12@3868.27,811.26 3966.26,811.26 3988.81,833.81 SB17.2@4009.17,833.81
STM_JTCK: CN4.2 U19.37 | length 1067.2
  TOP w5: v1(3670,550) 3700,550 3765,485 3830,485 3865.39,449.61 3865.39,370.28 3895,340.67 3895,258 3981,172 4288,172 CN4.2@4365,95
  BOTTOM w5: U19.37@3588.74,531.73 3651.73,531.73 v1(3670,550)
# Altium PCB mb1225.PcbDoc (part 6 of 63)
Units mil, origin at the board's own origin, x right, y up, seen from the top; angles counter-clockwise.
Board outline 5000 x 3464.56 mil, 6 copper layers (TOP, L2_GND, L3_VCC, L4_SIG, L5_GND, BOTTOM), stack 62.2 mil thick; 452 components, 378 nets, 1968 pads, 949 vias.

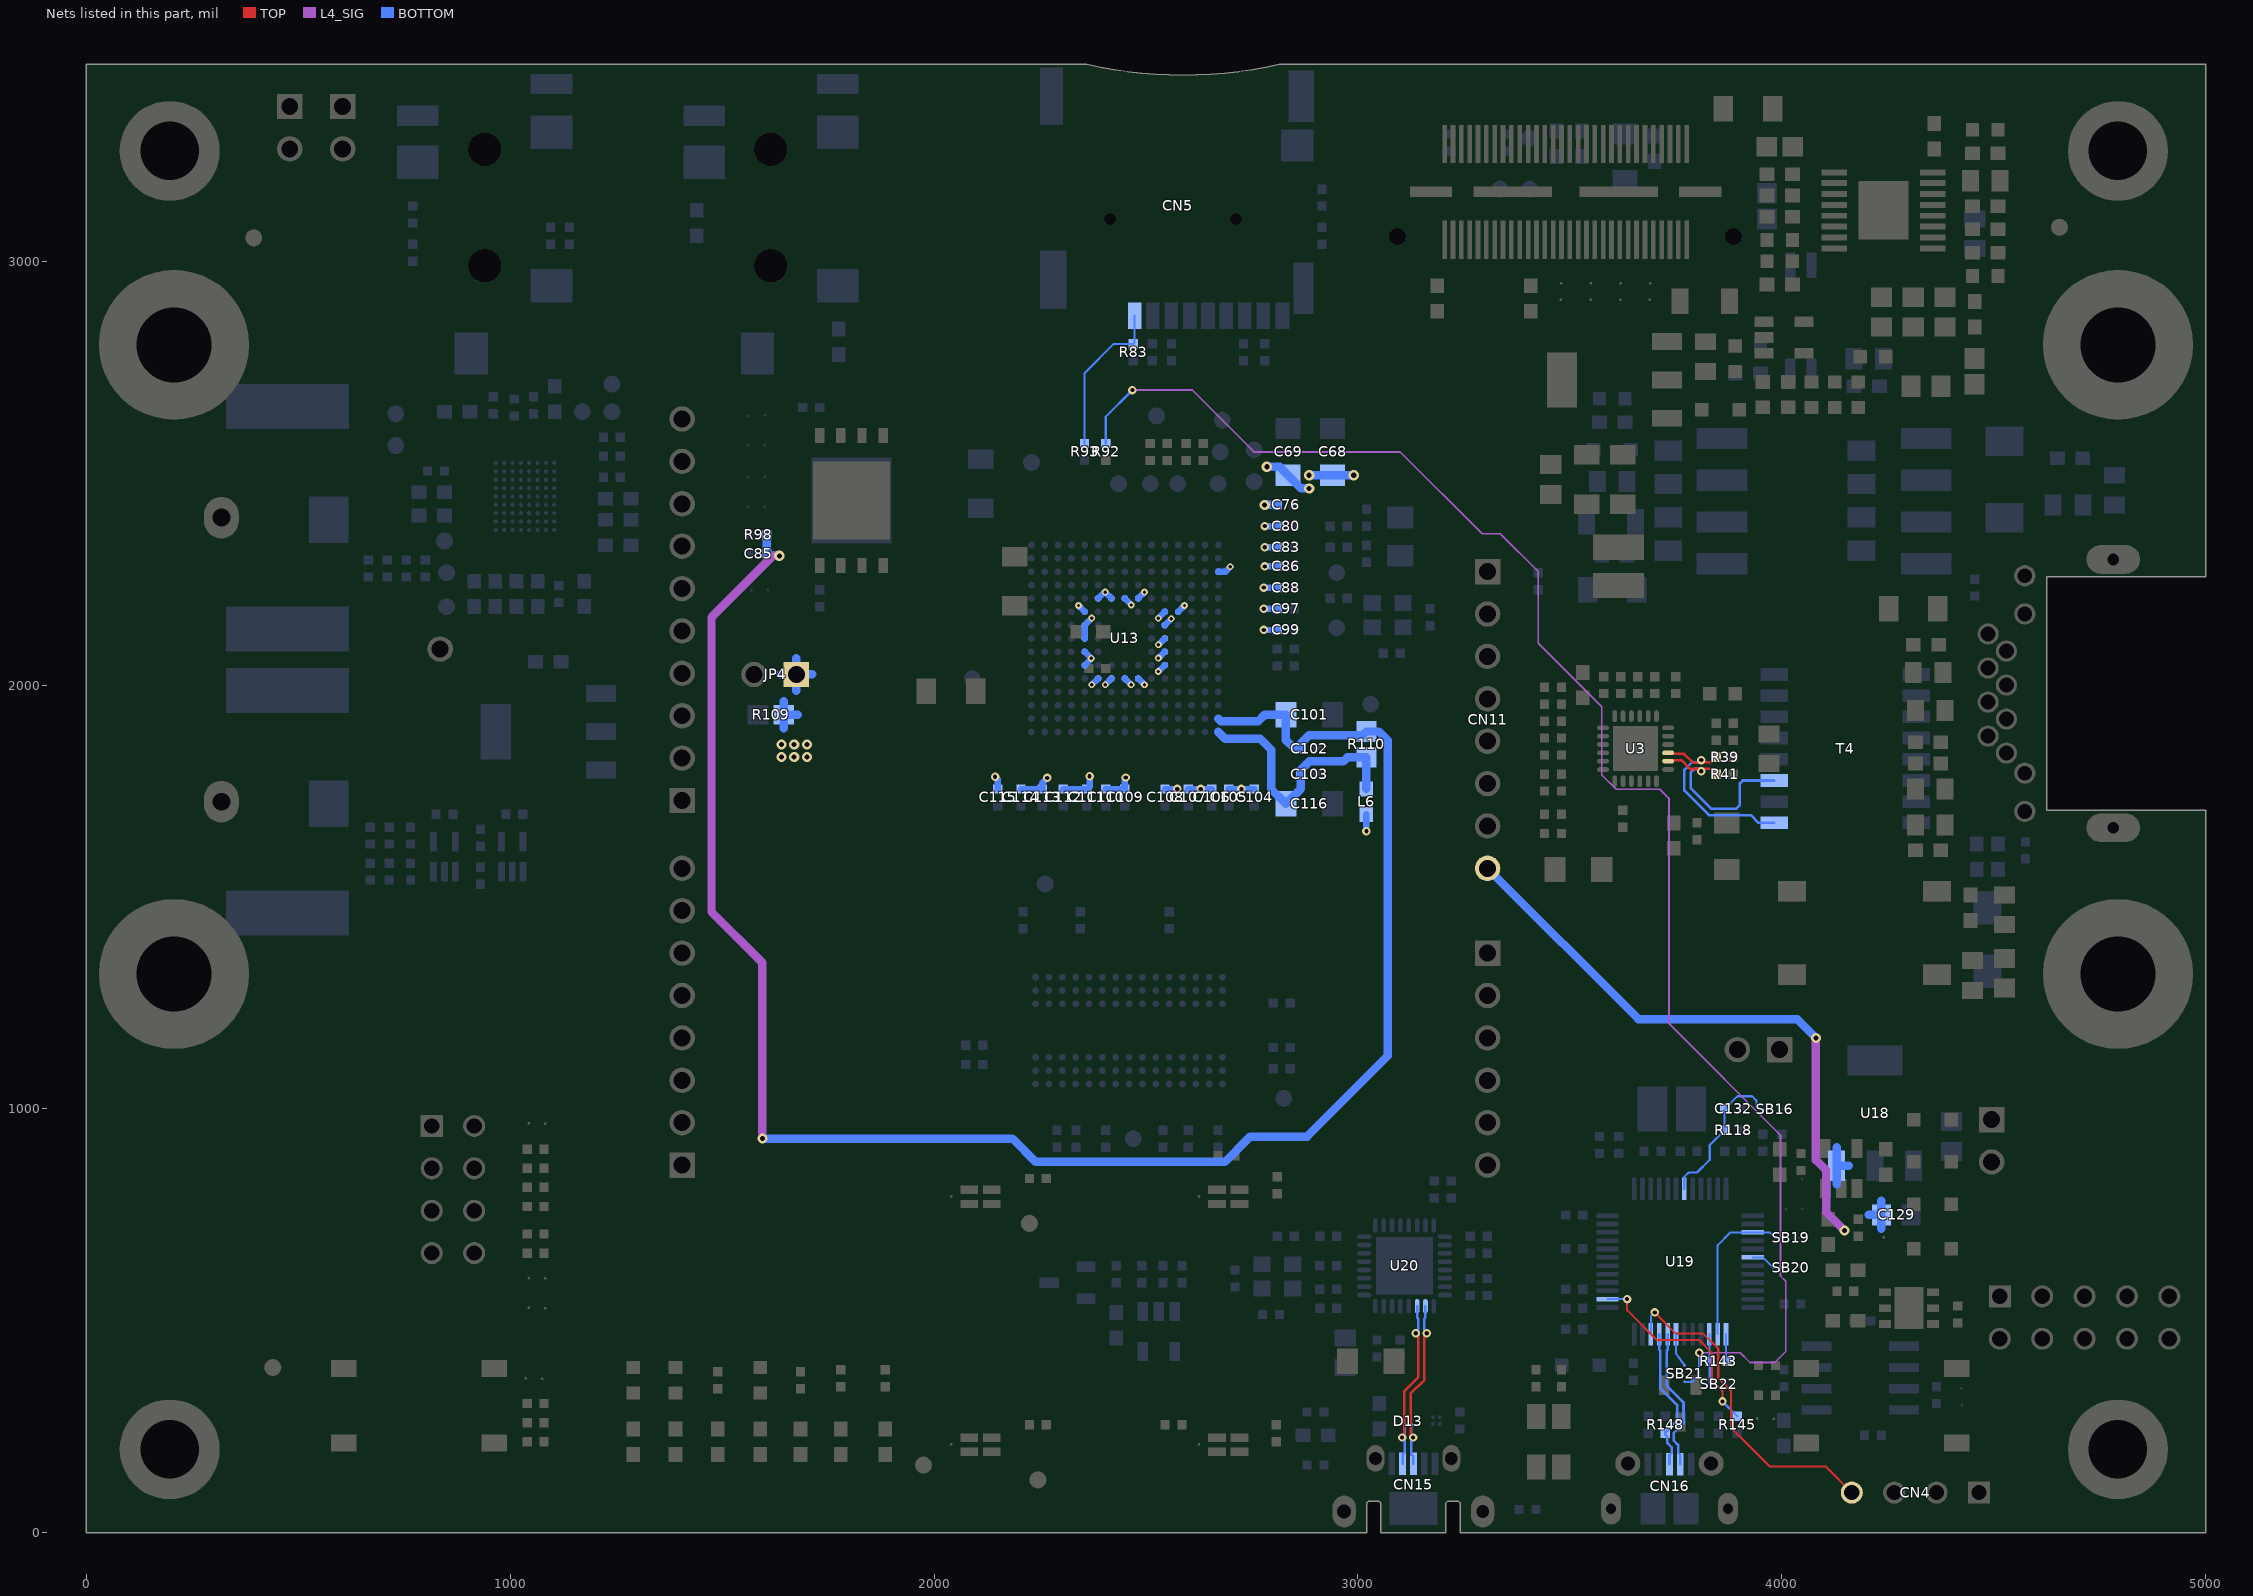
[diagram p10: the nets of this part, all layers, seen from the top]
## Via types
v1: diameter 20, hole 10, TOP to BOTTOM, 354 vias
v2: diameter 24, hole 12, TOP to BOTTOM, 349 vias
v3: diameter 16, hole 8, TOP to BOTTOM, 219 vias
v4: diameter 12, hole 6, TOP to BOTTOM, 27 vias

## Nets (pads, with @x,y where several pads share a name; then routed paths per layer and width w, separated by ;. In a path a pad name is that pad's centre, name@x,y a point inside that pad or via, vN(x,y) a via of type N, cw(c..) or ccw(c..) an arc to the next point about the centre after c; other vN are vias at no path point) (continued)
STM_JTMS: CN4.4 U19.34 | length 788
  TOP w5: v1(3700,520) 3750,470 3815,470 3850,435 3850,365 3880,335 3880,248 3971,157 4103,157 CN4.4@4165,95
  BOTTOM w5: U19.34@3691.1,468.74 3691.1,511.1 v1(3700,520)
STM_RST: C132.2 R118.1 SB16.2 U19.7 | length 373.2
  BOTTOM w5: U19.7@3769.84,811.26 3769.84,839.84 3780,850 3800,850 3830,880 3830,915 R118.1@3865,950 C132.2@3865,1000 3895,1030 3930,1030 3940,1020 3940,1005 3945,1000 3962.98,1000 SB16.2@3964.17,998.81
SWO: R92.1 SB21.2 | length 3745.7
  L4_SIG w4: v1(2468,2696) 2609,2696 2755,2550 3100,2550 3293,2357 3336.02,2357 3425,2268.02 3425,2099 3575,1949 3575,1788 3609,1754 3712,1754 3734,1732 3734,1201 3997,938 3997,606 4009,594 4009,428 3983,402 3925,402 3902,425 v1(3805,425)
  BOTTOM w5: R92.1@2405,2570 2405,2633 v1(2468,2696) ; SB21.2@3771.19,356.17 3788.17,356.17 3805,373 v1(3805,425)
T_JTCK: SB19.1 U19.15 U19.26 | length 381.4
  BOTTOM w5: U19.26@3848.58,468.74 3848.58,678.58 3878.9,708.9 U19.15@3931.26,708.9 3971.1,708.9 3984.67,695.33 SB19.1@4001.99,695.33
T_JTMS: R143.1 SB22.1 U19.27 | length 124.2
  BOTTOM w5: U19.27@3828.9,468.74 3828.9,406.1 R143.1@3830,405 3830,345
T_NRST: SB20.1 U19.18 | length 80.9
  BOTTOM w5: U19.18@3931.26,649.84 3955.16,649.84 3979.67,625.33 SB20.1@4001.99,625.33
T_SWDIO_IN: R143.2 U19.25 | length 64.5
  BOTTOM w5: U19.25@3868.27,468.74 3868.27,406.73 R143.2@3870,405
T_SWO: SB21.1 U19.31 | length 80.2
  BOTTOM w5: U19.31@3750.16,468.74 3750.16,423.18 SB21.1@3770.33,395.01
TD_N: R41.2 T4.3 U3.20 | length 475.1
  TOP w6.1: U3.20@3731.77,1820.47 3742.65,1820.47 3745,1822.82 3762.96,1822.82 3783.78,1802 3804.81,1802 v1(3809.81,1797) 3815.31,1802.5 3832.5,1802.5 R41.2@3845,1790
  BOTTOM w6.1: v1(3809.81,1797) 3804.31,1802.5 3793.72,1802.5 3785,1793.78 3785,1757.22 3834.22,1708 3892,1708 3901,1717 3901,1768 3908,1775 T4.3@3982.48,1775
TD_P: R39.2 T4.1 U3.21 | length 475.1
  TOP w6.1: U3.21@3731.77,1840.16 3740,1840.16 3742.34,1837.82 3769.18,1837.82 3790,1817 3803.81,1817 v1(3809.81,1823) 3815.31,1817.5 3832.5,1817.5 R39.2@3845,1830
  BOTTOM w6.1: v1(3809.81,1823) 3804.31,1817.5 3787.5,1817.5 3770,1800 3770,1751 3828,1693 3927,1693 3945,1675 T4.1@3982.48,1675
USB_HS_N: CN15.2 D13.A1 U20.19 | length 431.1
  TOP w6.1: v1(3104,225) 3109.5,230.5 3109.5,334.5 3141.87,366.87 3141.87,465.31 v1(3136.37,470.81)
  BOTTOM w6.1: CN15.2@3105.28,162.8 3105.28,185 3110.57,190.29 3110.57,218.43 v1(3104,225) 3110.57,231.57 3110.57,254.69 D13.A1@3110.13,255.13 ; v1(3136.37,470.81) 3141.87,476.31 3141.87,505.35 3139.53,507.69 U20.19@3139.53,534.72
USB_HS_P: CN15.3 D13.A2 U20.18 | length 429.3
  TOP w6.1: v1(3130,225) 3124.5,230.5 3124.5,328.28 3156.87,360.65 3156.87,465.31 v1(3162.37,470.81)
  BOTTOM w6.1: D13.A2@3125.87,255.13 3125.57,254.83 3125.57,229.43 v1(3130,225) 3125.57,220.57 3125.57,185 3130.87,179.7 CN15.3@3130.87,162.8 ; U20.18@3159.21,534.72 3159.21,507.69 3156.87,505.35 3156.87,476.31 v1(3162.37,470.81)
USB_RENUMN: R145.2 U19.38 | length 489
  TOP w5: v1(3635,551.42) 3635,525 3705,455 3805,455 3835,425 3835,360 3860,335 v1(3860,310)
  BOTTOM w5: U19.38@3588.74,551.42 v1(3635,551.42) ; v1(3860,310) R145.2@3895,275
USB_STLK_N: CN16.2 U19.32 | length 339.8
  BOTTOM w6.1: U19.32@3730.47,468.74 3730.47,432.21 3728.13,429.87 3728.13,347.87 3768,308 3768,259 3745,236 3745,218 3755.3,207.7 3755.3,189 3760.59,183.71 CN16.2@3760.59,162.4
USB_STLK_P: CN16.3 R148.1 U19.33 | length 344
  BOTTOM w6.1: U19.33@3710.79,468.74 3710.79,432.21 3713.13,429.87 3713.13,341.65 3753,301.78 3753,265.22 3725,237.22 R148.1@3725,235 3725,231 3730,226 3730,211.78 3740.3,201.48 3740.3,189 3735,183.7 CN16.3@3735,162.4
USD_D2: CN5.1 R83.1 R93.1 | length 377.1
  BOTTOM w5: R93.1@2355,2570 2355,2736 2424,2805 R83.1@2470,2805 2473.07,2808.07 CN5.1@2473.07,2871.21
VDD: C68.1 C69.1 C76.2 C80.2 C83.2 C86.2 C88.2 C97.2 C99.2 C104.2 C105.2 C106.2 C107.2 C108.2 C109.2 C110.2 C111.2 C112.2 C113.2 C114.2 C115.2 JP4.1 L6.1 R109.1 U13.C1 U13.E7 U13.E8 U13.E9 U13.E10 U13.F4 U13.F5 U13.F11 U13.G5 U13.G11 U13.H5 U13.H11 U13.J5 U13.J11 U13.K5 U13.K11 U13.L7 U13.L8 U13.L9 U13.L10 | length 1600.3
  BOTTOM w15: v1(2144,1784) 2150,1778 C115.2@2150,1755 ; C114.2@2205,1755 C113.2@2255,1755 2255,1769 v1(2267,1781) ; C112.2@2305,1755 C111.2@2360,1755 2362,1755 2367,1760 v1(2367,1785) ; v3(2340.66,2187.84) U13.F11@2355.51,2172.99 ; U13.K11@2355.51,2047.01 2371,2062.5 v3(2371,2063) U13.J11@2355.51,2078.5 ; U13.H11@2355.51,2110 U13.G11@2355.51,2141.5 2362,2147.99 v3(2372,2158) ; v3(2372.16,2000.66) U13.L10@2387.01,2015.51 ; U13.E10@2387.01,2204.49 2401.86,2219.34 v3(2403.65,2219.34) U13.E9@2418.5,2204.49 ; v3(2403.65,2000.66) U13.L9@2418.5,2015.51 ; C110.2@2405,1755 C109.2@2450,1755 2450,1780 v1(2452,1782) ; U13.L8@2450,2015.51 v3(2464.85,2000.66) ; U13.E8@2450,2204.49 2465,2189.49 v3(2465,2189) ; U13.L7@2481.5,2015.51 v3(2496.35,2000.66) ; U13.E7@2481.5,2204.49 v3(2496.35,2219.34) ; v3(2529,2032) 2544.01,2047.01 U13.K5@2544.49,2047.01 ; v3(2529,2157.5) U13.F5@2544.49,2172.99 ; v3(2529.34,2063.65) 2529.64,2063.65 U13.J5@2544.49,2078.5 ; v3(2529.34,2095.15) 2529.64,2095.15 U13.H5@2544.49,2110 ; U13.G5@2544.49,2141.5 v3(2559.34,2156.35) ; C108.2@2545,1755 v1(2574,1755) ; U13.F4@2575.98,2172.99 v3(2590.83,2187.84) ; C107.2@2600,1755 v1(2629,1755) C106.2@2655,1755 ; U13.C1@2670.47,2267.48 2687.48,2267.48 v3(2699,2279) ; C105.2@2695,1755 v1(2725,1755) C104.2@2755,1755 ; v1(2778,2130) C99.2@2810,2130 ; v1(2778,2180) C97.2@2810,2180 ; v1(2778,2230) C88.2@2810,2230 ; v1(2780,2280) C86.2@2810,2280 ; v1(2780,2325) C83.2@2810,2325 ; v1(2780,2375) C80.2@2810,2375 ; v1(3020,1655) L6.1@3020,1695
  BOTTOM w20: 1636.98,2025 JP4.1@1675,2025 ; 1645.51,1898.48 R109.1@1645.51,1930 ; 1645.51,1961.52 R109.1@1645.51,1930 ; 1675,1986.98 JP4.1@1675,2025 ; 1675,2063.02 JP4.1@1675,2025 ; 1678.03,1930 R109.1@1645.51,1930 ; 1713.02,2025 JP4.1@1675,2025 ; v2(2780,2425) C76.2@2810,2425 ; v2(2785,2515) 2815,2515 C69.1@2835,2495 2866,2464 v2(2885,2464) ; v2(2885,2495) C68.1@2940,2495 v2(2990,2495)
  other v2: 1640,1830 1670,1830 1700,1830 1640,1860 1670,1860 1700,1860
VDDA: C103.2 C116.1 L6.2 R110.1 U13.R1 | length 620.4
  BOTTOM w20: U13.R1@2670.47,1889.53 2687,1873 2770,1873 2795,1848 2795,1755 C116.1@2830,1720 2865,1755 C103.2@2865,1790 2865,1800 2885,1820 2965.51,1820 2975,1829.49 R110.1@3020,1829.49 L6.2@3020,1755
VIN: C129.2 CN11.8 U18.3 | length 1634.5
  L4_SIG w20: v2(4080.51,1167.49) 4080.51,879.49 4105,855 4105,756 v2(4148,713)
  BOTTOM w20: CN11.8@3305.8,1567.7 3661.5,1212 4036,1212 v2(4080.51,1167.49) ; 4129.45,822.46 U18.3@4129.45,865.98 ; 4129.45,909.5 U18.3@4129.45,865.98 ; 4157.47,865.98 U18.3@4129.45,865.98 ; 4204.48,750 C129.2@4235,750 ; 4235,716.98 C129.2@4235,750 ; 4235,783.02 C129.2@4235,750
VREF+: C85.2 C101.1 C102.2 R98.2 R110.2 U13.P1 | length 4432
  L4_SIG w20: v2(1595,930) 1595,1345 1475,1465 1475,2160 1620,2305 v2(1635,2305)
  BOTTOM w20: v2(1595,930) 2185,930 2240,875 2686,875 2746,935 2880,935 3070,1125 3070,1870 3049.49,1890.51 R110.2@3020,1890.51 3011.49,1882 2885,1882 2865,1862 C102.2@2865,1850 2850,1850 2830,1870 C101.1@2830,1930 2780,1930 2765,1915 2676.49,1915 U13.P1@2670.47,1921.02 ; R98.2@1605,2355 C85.2@1605,2310 1610,2305 v2(1635,2305)
pads on no net: "CN1. " "CN5. " "CN6. " "CN7. " CN1.2 CN1.20 CN1.22 CN1.24 CN1.25 CN1.26 CN1.28 CN1.30 CN1.31 CN1.32 CN1.33 CN1.34 CN1.38 CN1.41 CN1.42 CN1.43 CN1.46 CN1.48 CN1.50 CN1.51 CN1.52 CN1.54 CN1.55 CN1.56 CN1.58 CN1.59 CN5.11 CN5.12 CN5.13 CN5.14 CN6.5 CN6.7 CN7.5 CN7.7 T4.4 T4.5 T4.12 T4.13 U2.1 U2.2 U3.4 U7.3 U7.5 U11.A6 U11.A8 U11.B4 U11.B5 U11.B8 U11.C4 U11.C5 U11.C7 U11.C8 U11.E1 U11.E5 U11.F4 U11.F5 U11.F6 U11.F8 U11.F9 U11.G4 U11.H2 U11.H3 U11.H4 U11.H5 U12.9 U15.1 U16.1 U17.E7 U17.H3 U17.H7 U17.K2 U17.K3 U19.4 U19.11 U19.14 U19.16 U19.17 U19.19 U19.21 U19.22 U19.29 U19.40 U19.41 U19.42 U19.43 U19.45 U19.46 U20.12 U20.15 U20.16 U20.25 U250.9
copper on no net: | length 384679.8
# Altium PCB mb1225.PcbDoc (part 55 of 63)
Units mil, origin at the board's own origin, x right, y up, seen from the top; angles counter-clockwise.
Board outline 5000 x 3464.56 mil, 6 copper layers (TOP, L2_GND, L3_VCC, L4_SIG, L5_GND, BOTTOM), stack 62.2 mil thick; 452 components, 378 nets, 1968 pads, 949 vias.

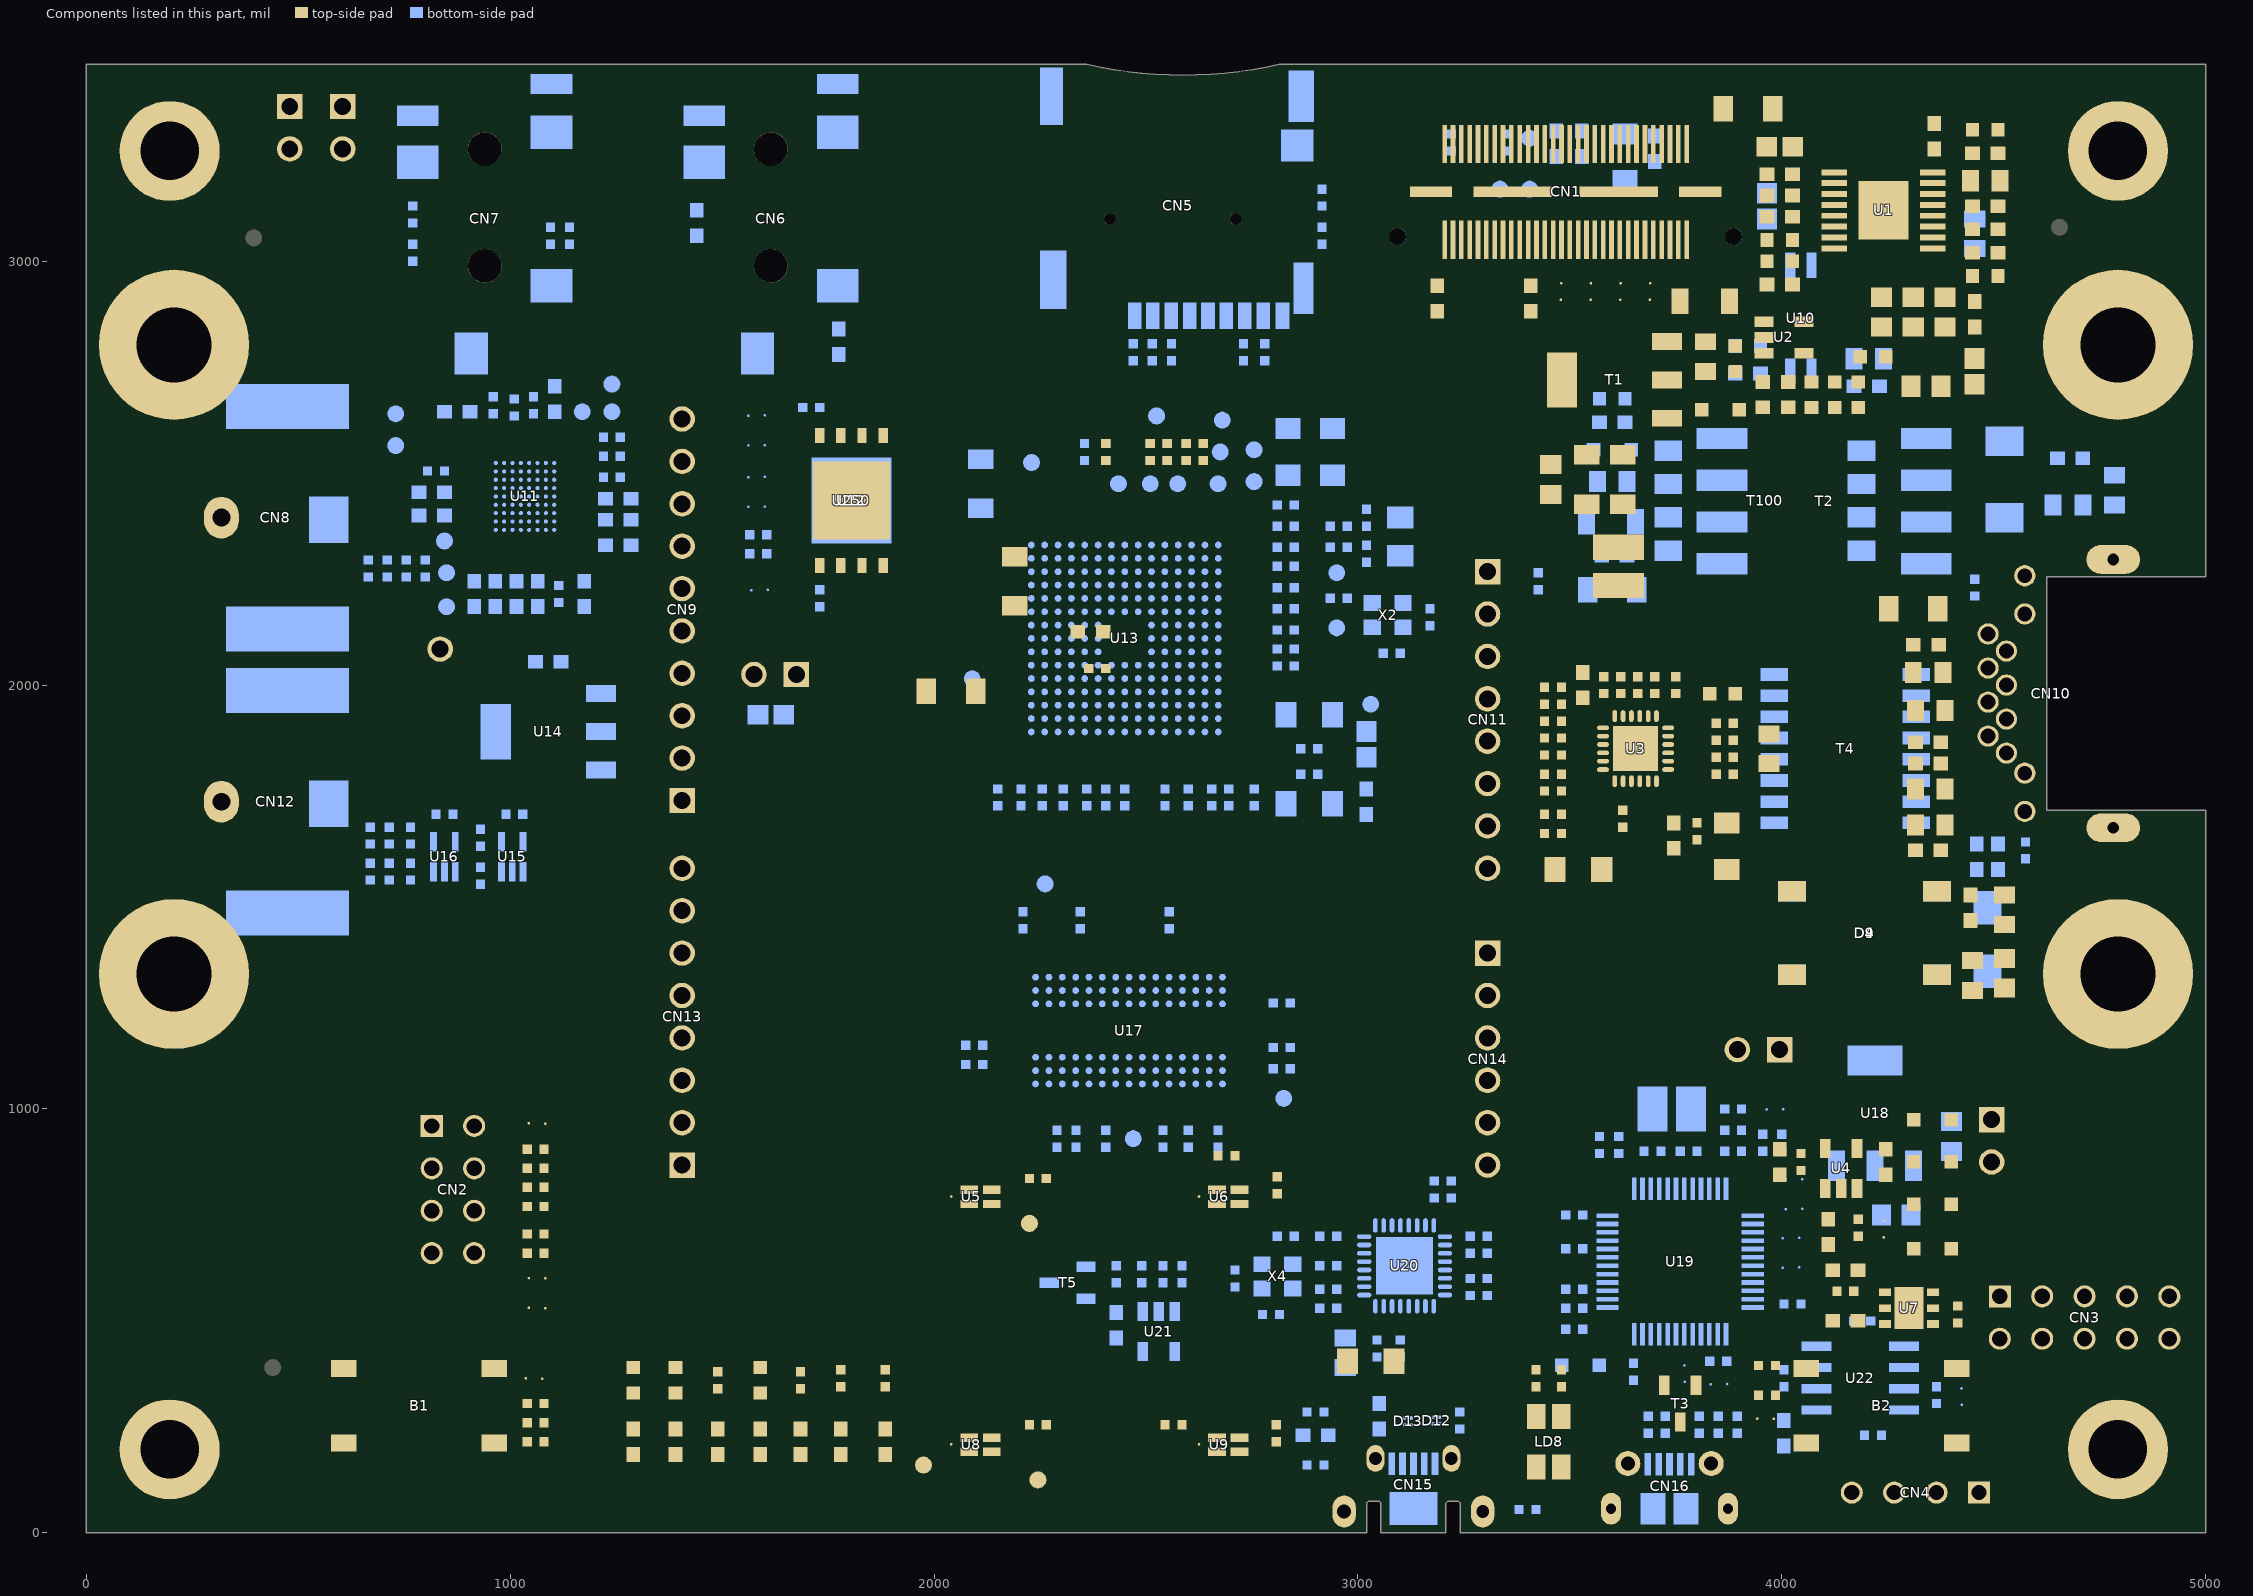
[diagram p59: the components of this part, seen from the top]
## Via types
v1: diameter 20, hole 10, TOP to BOTTOM, 354 vias
v2: diameter 24, hole 12, TOP to BOTTOM, 349 vias
v3: diameter 16, hole 8, TOP to BOTTOM, 219 vias
v4: diameter 12, hole 6, TOP to BOTTOM, 27 vias

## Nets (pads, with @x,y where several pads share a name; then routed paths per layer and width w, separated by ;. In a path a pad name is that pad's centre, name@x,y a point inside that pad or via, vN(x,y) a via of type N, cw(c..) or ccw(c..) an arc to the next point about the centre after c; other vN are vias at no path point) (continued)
copper on no net: (continued)
  BOTTOM w2: 1039.8,-1830.65 1103.68,-1766.77 1039.8,-1830.65 ; 1040.95,-1876.65 1061.85,-1855.74 1040.95,-1876.65 ; 1041.82,-1830.87 1105.93,-1766.77 1041.82,-1830.87 ; 1043.19,-1876.65 1064.1,-1855.74 1043.19,-1876.65 ; 1044.07,-1830.87 1108.17,-1766.77 1044.07,-1830.87 ; 1045.44,-1876.65 1066.34,-1855.74 1045.44,-1876.65 ; 1046.31,-1830.87 1110.42,-1766.77 1046.31,-1830.87 ; 1047.68,-1876.65 1068.59,-1855.74 1047.68,-1876.65 ; 1048.56,-1830.87 1112.66,-1766.77 1048.56,-1830.87 ; 1049.93,-1876.65 1070.83,-1855.74 1049.93,-1876.65 ; 1050.8,-1830.87 1114.91,-1766.77 1050.8,-1830.87 ; 1052.17,-1876.65 1073.08,-1855.74 1052.17,-1876.65 ; 1053.05,-1830.87 1117.15,-1766.77 1053.05,-1830.87 ; 1054.42,-1876.65 1075.32,-1855.74 1054.42,-1876.65 ; 1055.29,-1830.87 1119.4,-1766.77 1055.29,-1830.87 ; 1056.66,-1876.65 1077.57,-1855.74 1056.66,-1876.65 ; 1057.54,-1830.87 1090.65,-1797.76 1057.54,-1830.87 ; 1058.91,-1876.65 1079.81,-1855.74 1058.91,-1876.65 ; 1059.78,-1830.87 1087.8,-1802.86 1059.78,-1830.87 ; 1061.15,-1876.65 1082.06,-1855.74 1061.15,-1876.65 ; 1063.4,-1876.65 1084.3,-1855.74 1063.4,-1876.65 ; 1064.27,-1830.87 1087.07,-1808.07 1064.27,-1830.87 ; 1065.64,-1876.65 1086.55,-1855.74 1065.64,-1876.65 ; 1066.52,-1830.87 1087.61,-1809.78 1066.52,-1830.87 ; 1067.89,-1876.65 1088.79,-1855.74 1067.89,-1876.65 ; 1068.76,-1830.87 1088.63,-1811.01 1068.76,-1830.87 ; 1070.13,-1876.65 1091.04,-1855.74 1070.13,-1876.65 ; 1071.01,-1830.87 1089.89,-1811.99 1071.01,-1830.87 ; 1072.38,-1876.65 1093.28,-1855.74 1072.38,-1876.65 ; 1073.26,-1830.87 1091.68,-1812.44 1073.26,-1830.87 ; 1074.62,-1876.65 1095.53,-1855.74 1074.62,-1876.65 ; 1075.5,-1830.87 1093.92,-1812.44 1075.5,-1830.87 ; 1076.87,-1876.65 1097.77,-1855.74 1076.87,-1876.65 ; 1077.75,-1830.87 1096.17,-1812.44 1077.75,-1830.87 ; 1079.11,-1876.65 1100.02,-1855.74 1079.11,-1876.65 ; 1079.99,-1830.87 1098.41,-1812.44 1079.99,-1830.87 ; 1081.36,-1876.65 1102.26,-1855.74 1081.36,-1876.65 ; 1082.24,-1830.87 1100.66,-1812.44 1082.24,-1830.87 ; 1083.6,-1876.65 1104.51,-1855.74 1083.6,-1876.65 ; 1084.48,-1830.87 1102.9,-1812.44 1084.48,-1830.87 ; 1086.73,-1830.87 1105.15,-1812.44 1086.73,-1830.87 ; 1088.09,-1876.65 1110.89,-1853.85 1088.09,-1876.65 ; 1088.97,-1830.87 1107.39,-1812.44 1088.97,-1830.87 ; 1090.34,-1876.65 1114.74,-1852.24 1090.34,-1876.65 ; 1091.22,-1830.87 1109.64,-1812.44 1091.22,-1830.87 ; 1092.58,-1876.65 1153.43,-1815.8 1092.58,-1876.65 ; 1093.46,-1830.87 1111.88,-1812.44 1093.46,-1830.87 ; 1094.83,-1876.65 1154.5,-1816.97 1094.83,-1876.65 ; 1095,-1793.4 1121.64,-1766.77 1095,-1793.4 ; 1095.71,-1830.87 1114.13,-1812.44 1095.71,-1830.87 ; 1097.95,-1830.87 1116.37,-1812.44 1097.95,-1830.87 ; 1099.32,-1876.65 1156.25,-1819.71 1099.32,-1876.65 ; 1100.2,-1830.87 1118.62,-1812.44 1100.2,-1830.87 ; 1100.57,-1790.09 1123.89,-1766.77 1100.57,-1790.09 ; 1101.56,-1876.65 1156.81,-1821.4 1101.56,-1876.65 ; 1102.44,-1830.87 1120.86,-1812.44 1102.44,-1830.87 ; 1103.81,-1876.65 1157.09,-1823.36 1103.81,-1876.65 ; 1104.12,-1788.78 1126.13,-1766.77 1104.12,-1788.78 ; 1104.69,-1830.87 1123.11,-1812.44 1104.69,-1830.87 ; 1106.05,-1876.65 1157.13,-1825.57 1106.05,-1876.65 ; 1106.93,-1830.87 1125.35,-1812.44 1106.93,-1830.87 ; 1107.2,-1787.95 1128.38,-1766.77 1107.2,-1787.95 ; 1108.3,-1876.65 1157.06,-1827.88 1108.3,-1876.65 ; 1109.18,-1830.87 1127.6,-1812.44 1109.18,-1830.87 ; 1109.65,-1787.74 1130.62,-1766.77 1109.65,-1787.74 ; 1110.54,-1876.65 1157.05,-1830.14 1110.54,-1876.65 ; 1111.42,-1830.87 1129.84,-1812.44 1111.42,-1830.87 ; 1111.89,-1787.74 1132.87,-1766.77 1111.89,-1787.74 ; 1112.82,-1876.61 1157.05,-1832.38 1112.82,-1876.61 ; 1113.67,-1830.87 1132.09,-1812.44 1113.67,-1830.87 ; 1114.14,-1787.74 1135.11,-1766.77 1114.14,-1787.74 ; 1115.39,-1876.29 1156.92,-1834.76 1115.39,-1876.29 ; 1115.91,-1830.87 1134.33,-1812.44 1115.91,-1830.87 ; 1116.38,-1787.74 1137.36,-1766.77 1116.38,-1787.74 ; 1118.16,-1830.87 1136.58,-1812.44 1118.16,-1830.87 ; 1118.2,-1875.72 1156.52,-1837.41 1118.2,-1875.72 ; 1118.63,-1787.74 1139.6,-1766.77 1118.63,-1787.74 ; 1120.4,-1830.87 1138.82,-1812.44 1120.4,-1830.87 ; 1120.87,-1787.74 1141.85,-1766.77 1120.87,-1787.74 ; 1121.15,-1875.02 1155.67,-1840.5 1121.15,-1875.02 ; 1121.58,-1845.41 1152.26,-1814.73 1121.58,-1845.41 ; 1122.09,-1831.42 1141.07,-1812.44 1122.09,-1831.42 ; 1122.98,-1841.76 1150.97,-1813.77 1122.98,-1841.76 ; 1123.12,-1787.74 1144.09,-1766.77 1123.12,-1787.74 ; 1123.36,-1832.4 1143.31,-1812.44 1123.36,-1832.4 ; 1123.78,-1838.71 1149.55,-1812.94 1123.78,-1838.71 ; 1124.15,-1833.85 1145.56,-1812.44 1124.15,-1833.85 ; 1124.25,-1874.17 1154.27,-1844.14 1124.25,-1874.17 ; 1124.31,-1835.94 1147.8,-1812.44 1124.31,-1835.94 ; 1125.36,-1787.74 1146.34,-1766.77 1125.36,-1787.74 ; 1127.61,-1787.74 1148.58,-1766.77 1127.61,-1787.74 ; 1127.84,-1872.82 1152.27,-1848.39 1127.84,-1872.82 ; 1129.85,-1787.74 1150.83,-1766.77 1129.85,-1787.74 ; 1132.1,-1787.74 1153.07,-1766.77 1132.1,-1787.74 ; 1132.18,-1870.72 1149.17,-1853.73 1132.18,-1870.72 ; 1134.34,-1787.74 1155.32,-1766.77 1134.34,-1787.74 ; 1136.59,-1787.74 1157.56,-1766.77 1136.59,-1787.74 ; 1138.83,-1787.74 1159.81,-1766.77 1138.83,-1787.74 ; 1141.08,-1787.74 1162.05,-1766.77 1141.08,-1787.74 ; 1143.32,-1787.74 1164.3,-1766.77 1143.32,-1787.74 ; 1145.57,-1787.74 1166.54,-1766.77 1145.57,-1787.74 ; 1147.81,-1787.74 1168.79,-1766.77 1147.81,-1787.74 ; 1150.06,-1787.74 1171.03,-1766.77 1150.06,-1787.74 ; 1152.3,-1787.74 1171.39,-1768.65 1152.3,-1787.74 ; 1154.55,-1787.74 1170.75,-1771.53 1154.55,-1787.74 ; 1156.79,-1787.74 1170.12,-1774.41 1156.79,-1787.74 ; 1159.04,-1787.74 1169.48,-1777.29 1159.04,-1787.74 ; 1161.28,-1787.74 1168.85,-1780.17 1161.28,-1787.74 ; 1163.53,-1787.74 1168.22,-1783.05 1163.53,-1787.74 ; 1168.79,-1852.08 1254.13,-1766.74 1168.79,-1852.08 ; 1168.81,-1849.81 1251.88,-1766.74 1168.81,-1849.81 ; 1168.8,-1845.33 1247.39,-1766.74 1168.8,-1845.33 ; 1168.84,-1847.54 1249.64,-1766.74 1168.84,-1847.54 ; 1168.85,-1843.04 1245.15,-1766.74 1168.85,-1843.04 ; 1169.13,-1840.51 1242.9,-1766.74 1169.13,-1840.51 ; 1169.58,-1858.02 1260.86,-1766.74 1169.58,-1858.02 ; 1169.64,-1837.76 1240.66,-1766.74 1169.64,-1837.76 ; 1170.24,-1834.92 1238.41,-1766.74 1170.24,-1834.92 ; 1170.73,-1861.36 1236.56,-1795.53 1170.73,-1861.36 ; 1170.85,-1832.05 1236.17,-1766.74 1170.85,-1832.05 ; 1171.48,-1829.18 1233.92,-1766.74 1171.48,-1829.18 ; 1172.12,-1826.3 1231.68,-1766.74 1172.12,-1826.3 ; 1172.27,-1864.31 1230.04,-1806.54 1172.27,-1864.31 ; 1172.76,-1823.41 1229.43,-1766.74 1172.76,-1823.41 ; 1173.17,-1865.66 1229.54,-1809.29 1173.17,-1865.66 ; 1174.16,-1866.91 1229,-1812.07 1174.16,-1866.91 ; 1174.2,-1817.48 1224.94,-1766.74 1174.2,-1817.48 ; 1175.06,-1814.37 1222.7,-1766.74 1175.06,-1814.37 ; 1175.24,-1868.07 1228.41,-1814.91 1175.24,-1868.07 ; 1176.07,-1811.12 1220.11,-1767.08 1176.07,-1811.12 ; 1177.25,-1807.7 1217.15,-1767.8 1177.25,-1807.7 ; 1178.69,-1804.01 1213.98,-1768.72 1178.69,-1804.01 ; 1183.27,-1794.94 1206.37,-1771.84 1183.27,-1794.94 ; 1186.66,-1874.62 1222.94,-1838.33 1186.66,-1874.62 ; 1187.6,-1788.36 1200.61,-1775.35 1187.6,-1788.36 ; 1190.29,-1875.48 1222.48,-1843.29 1190.29,-1875.48 ; 1196.16,-1876.34 1223.77,-1848.73 1196.16,-1876.34 ; 1200.65,-1876.34 1225.81,-1851.18 1200.65,-1876.34 ; 1202.89,-1876.34 1227.05,-1852.18 1202.89,-1876.34 ; 1207.38,-1876.34 1229.83,-1853.9 1207.38,-1876.34 ; 1211.87,-1876.34 1233.32,-1854.9 1211.87,-1876.34 ; 1214.12,-1876.34 1235.17,-1855.29 1214.12,-1876.34 ; 1216.36,-1876.34 1237.03,-1855.68 1216.36,-1876.34 ; 1218.61,-1876.34 1238.9,-1856.05 1218.61,-1876.34 ; 1220.85,-1876.34 1241.06,-1856.14 1220.85,-1876.34 ; 1223.1,-1876.34 1243.55,-1855.89 1223.1,-1876.34 ; 1225.34,-1876.34 1246.16,-1855.52 1225.34,-1876.34 ; 1227.59,-1876.34 1248.88,-1855.05 1227.59,-1876.34 ; 1229.83,-1876.34 1252.03,-1854.15 1229.83,-1876.34 ; 1232.08,-1876.34 1255.87,-1852.56 1232.08,-1876.34 ; 1234.32,-1876.34 1260.98,-1849.69 1234.32,-1876.34 ; 1236.57,-1876.34 1305.07,-1807.84 1236.57,-1876.34 ; 1238.81,-1876.34 1304.81,-1810.35 1238.81,-1876.34 ; 1243.3,-1876.34 1304.19,-1815.46 1243.3,-1876.34 ; 1247.79,-1876.34 1303.36,-1820.78 1247.79,-1876.34 ; 1250.04,-1876.34 1302.71,-1823.68 1250.04,-1876.34 ; 1250.59,-1788.23 1272.09,-1766.74 1250.59,-1788.23 ; 1253.31,-1787.76 1274.33,-1766.74 1253.31,-1787.76 ; 1255.69,-1787.63 1276.48,-1766.84 1255.69,-1787.63 ; 1256.77,-1876.34 1300.76,-1832.36 1256.77,-1876.34 ; 1259.39,-1875.98 1300.15,-1835.22 1259.39,-1875.98 ; 1260.03,-1787.78 1280.36,-1767.45 1260.03,-1787.78 ; 1262.08,-1875.53 1299.33,-1838.28 1262.08,-1875.53 ; 1263.8,-1846.86 1305.12,-1805.55 1263.8,-1846.86 ; 1266.5,-1841.92 1305.09,-1803.33 1266.5,-1841.92 ; 1267.34,-1789.44 1287.24,-1769.55 1267.34,-1789.44 ; 1267.98,-1874.12 1297.17,-1844.93 1267.98,-1874.12 ; 1268.69,-1790.34 1288.85,-1770.18 1268.69,-1790.34 ; 1268.87,-1835.06 1305.1,-1798.83 1268.87,-1835.06 ; 1271.08,-1826.11 1304.5,-1792.7 1271.08,-1826.11 ; 1271.63,-1823.32 1304.07,-1790.88 1271.63,-1823.32 ; 1272.55,-1817.91 1303.04,-1787.42 1272.55,-1817.91 ; 1272.99,-1795.02 1294.2,-1773.81 1272.99,-1795.02 ; 1273.7,-1810.03 1301.12,-1782.61 1273.7,-1810.03 ; 1273.68,-1796.57 1295.32,-1774.94 1273.68,-1796.57 ; 1274.25,-1798.25 1296.45,-1776.06 1274.25,-1798.25 ; 1274.62,-1800.13 1297.55,-1777.2 1274.62,-1800.13 ; 1304.95,-1875.32 1373.4,-1806.87 1304.95,-1875.32 ; 1305.57,-1872.45 1374.49,-1803.53 1305.57,-1872.45 ; 1306.17,-1876.34 1372.93,-1809.58 1306.17,-1876.34 ; 1306.19,-1869.59 1378.05,-1797.72 1306.19,-1869.59 ; 1307.4,-1863.89 1404.55,-1766.74 1307.4,-1863.89 ; 1308,-1861.04 1402.3,-1766.74 1308,-1861.04 ; 1308.41,-1876.34 1372.25,-1812.51 1308.41,-1876.34 ; 1308.59,-1858.2 1400.06,-1766.74 1308.59,-1858.2 ; 1309.19,-1855.36 1397.81,-1766.74 1309.19,-1855.36 ; 1310.38,-1849.68 1393.32,-1766.74 1310.38,-1849.68 ; 1310.99,-1846.83 1391.08,-1766.74 1310.99,-1846.83 ; 1311.59,-1843.98 1388.83,-1766.74 1311.59,-1843.98 ; 1312.21,-1841.12 1386.59,-1766.74 1312.21,-1841.12 ; 1312.83,-1838.25 1384.34,-1766.74 1312.83,-1838.25 ; 1312.9,-1876.34 1371.28,-1817.97 1312.9,-1876.34 ; 1314.78,-1829.57 1377.6,-1766.74 1314.78,-1829.57 ; 1315.15,-1876.34 1370.53,-1820.97 1315.15,-1876.34 ; 1315.46,-1826.64 1375.36,-1766.74 1315.46,-1826.64 ; 1316.16,-1823.7 1373.11,-1766.74 1316.16,-1823.7 ; 1316.88,-1820.73 1370.87,-1766.74 1316.88,-1820.73 ; 1319.4,-1811.47 1363.36,-1767.52 1319.4,-1811.47 ; 1319.64,-1876.34 1369.31,-1826.68 1319.64,-1876.34 ; 1321.98,-1804.41 1357.35,-1769.03 1321.98,-1804.41 ; 1326.37,-1876.34 1367.74,-1834.97 1326.37,-1876.34 ; 1328.62,-1876.34 1367.11,-1837.85 1328.62,-1876.34 ; 1331.52,-1788.13 1343.82,-1775.83 1331.52,-1788.13 ; 1333.11,-1876.34 1365.73,-1843.72 1333.11,-1876.34 ; 1337.6,-1876.34 1364.29,-1849.65 1337.6,-1876.34 ; 1346.58,-1876.34 1361.59,-1861.33 1346.58,-1876.34 ; 1351.07,-1876.34 1360.32,-1867.09 1351.07,-1876.34 ; 1353.31,-1876.34 1359.68,-1869.97 1353.31,-1876.34 ; 1355.56,-1876.34 1359.04,-1872.86 1355.56,-1876.34 ; 1357.8,-1876.34 1358.38,-1875.77 1357.8,-1876.34 ; 1373.62,-1849.3 1412.73,-1810.19 1373.62,-1849.3 ; 1374.23,-1846.45 1410.48,-1810.19 1374.23,-1846.45 ; 1374.83,-1843.6 1408.24,-1810.19 1374.83,-1843.6 ; 1375.44,-1840.75 1405.99,-1810.19 1375.44,-1840.75 ; 1376.04,-1837.9 1403.75,-1810.19 1376.04,-1837.9 ; 1376.65,-1835.05 1401.5,-1810.19 1376.65,-1835.05 ; 1377.25,-1832.2 1399.26,-1810.19 1377.25,-1832.2 ; 1377.87,-1847.3 1414.97,-1810.19 1377.87,-1847.3 ; 1377.86,-1829.35 1397.01,-1810.19 1377.86,-1829.35 ; 1378.46,-1826.5 1394.77,-1810.19 1378.46,-1826.5 ; 1379.07,-1823.65 1392.52,-1810.19 1379.07,-1823.65 ; 1379.68,-1820.8 1390.28,-1810.19 1379.68,-1820.8 ; 1380.28,-1817.95 1388.03,-1810.19 1380.28,-1817.95 ; 1380.89,-1815.1 1385.79,-1810.19 1380.89,-1815.1 ; 1381.49,-1812.24 1383.54,-1810.19 1381.49,-1812.24 ; 1382.77,-1793.01 1409.04,-1766.74 1382.77,-1793.01 ; 1382.89,-1844.52 1417.22,-1810.19 1382.89,-1844.52 ; 1387.91,-1841.74 1419.46,-1810.19 1387.91,-1841.74 ; 1388.03,-1789.99 1411.28,-1766.74 1388.03,-1789.99 ; 1391.56,-1788.71 1413.53,-1766.74 1391.56,-1788.71 ; 1392.94,-1838.97 1421.71,-1810.19 1392.94,-1838.97 ; 1394.72,-1787.79 1415.77,-1766.74 1394.72,-1787.79 ; 1397,-1787.76 1418.02,-1766.74 1397,-1787.76 ; 1397.96,-1836.19 1423.95,-1810.19 1397.96,-1836.19 ; 1399.24,-1787.76 1420.26,-1766.74 1399.24,-1787.76 ; 1401.49,-1787.76 1422.51,-1766.74 1401.49,-1787.76 ; 1402.98,-1833.41 1426.2,-1810.19 1402.98,-1833.41 ; 1403.73,-1787.76 1424.75,-1766.74 1403.73,-1787.76 ; 1405.98,-1787.76 1427,-1766.74 1405.98,-1787.76 ; 1408,-1830.64 1428.44,-1810.19 1408,-1830.64 ; 1408.22,-1787.76 1429.24,-1766.74 1408.22,-1787.76 ; 1410.47,-1787.76 1431.49,-1766.74 1410.47,-1787.76 ; 1412.71,-1787.76 1433.73,-1766.74 1412.71,-1787.76 ; 1413.02,-1827.86 1430.69,-1810.19 1413.02,-1827.86 ; 1414.96,-1787.76 1435.98,-1766.74 1414.96,-1787.76 ; 1417.2,-1787.76 1438.22,-1766.74 1417.2,-1787.76 ; 1418.04,-1825.08 1432.93,-1810.19 1418.04,-1825.08 ; 1419.45,-1787.76 1440.47,-1766.74 1419.45,-1787.76 ; 1421.69,-1787.76 1442.71,-1766.74 1421.69,-1787.76 ; 1423.07,-1822.31 1435.18,-1810.19 1423.07,-1822.31 ; 1423.94,-1787.76 1444.96,-1766.74 1423.94,-1787.76 ; 1426.18,-1787.76 1447.2,-1766.74 1426.18,-1787.76 ; 1428.09,-1819.53 1437.42,-1810.19 1428.09,-1819.53 ; 1428.43,-1787.76 1449.45,-1766.74 1428.43,-1787.76 ; 1430.67,-1787.76 1451.69,-1766.74 1430.67,-1787.76 ; 1432.92,-1787.76 1453.94,-1766.74 1432.92,-1787.76 ; 1433.11,-1816.75 1439.67,-1810.19 1433.11,-1816.75 ; 1435.16,-1787.76 1456.18,-1766.74 1435.16,-1787.76 ; 1437.41,-1787.76 1458.43,-1766.74 1437.41,-1787.76 ; 1438.13,-1813.98 1441.91,-1810.19 1438.13,-1813.98 ; 1439.65,-1787.76 1457.91,-1769.5 1439.65,-1787.76 ; 1441.9,-1787.76 1457.3,-1772.35 1441.9,-1787.76 ; 1442.35,-1847.93 1523.53,-1766.74 1442.35,-1847.93 ; 1442.37,-1845.66 1521.29,-1766.74 1442.37,-1845.66 ; 1442.52,-1852.24 1528.02,-1766.74 1442.52,-1852.24 ; 1442.68,-1840.86 1516.8,-1766.74 1442.68,-1840.86 ; 1443.08,-1856.18 1532.51,-1766.74 1443.08,-1856.18 ; 1443.15,-1811.2 1444.16,-1810.19 1443.15,-1811.2 ; 1443.47,-1835.58 1512.31,-1766.74 1443.47,-1835.58 ; 1443.53,-1857.97 1534.76,-1766.74 1443.53,-1857.97 ; 1444.1,-1859.65 1537,-1766.74 1444.1,-1859.65 ; 1444.14,-1787.76 1456.7,-1775.2 1444.14,-1787.76 ; 1444.8,-1829.76 1507.82,-1766.74 1444.8,-1829.76 ; 1445.53,-1826.78 1505.57,-1766.74 1445.53,-1826.78 ; 1446.19,-1823.88 1503.33,-1766.74 1446.19,-1823.88 ; 1446.39,-1787.76 1456.1,-1778.05 1446.39,-1787.76 ; 1446.81,-1821.02 1501.08,-1766.74 1446.81,-1821.02 ; 1448.22,-1815.11 1496.59,-1766.74 1448.22,-1815.11 ; 1448.37,-1866.6 1502.94,-1812.03 1448.37,-1866.6 ; 1449.2,-1811.89 1494.35,-1766.74 1449.2,-1811.89 ; 1449.41,-1867.81 1505.19,-1812.03 1449.41,-1867.81 ; 1450.51,-1868.95 1507.43,-1812.03 1450.51,-1868.95 ; 1450.88,-1787.76 1454.89,-1783.75 1450.88,-1787.76 ; 1451.72,-1869.99 1509.68,-1812.03 1451.72,-1869.99 ; 1453.04,-1870.91 1511.92,-1812.03 1453.04,-1870.91 ; 1453.7,-1800.66 1485.73,-1768.63 1453.7,-1800.66 ; 1454.5,-1871.69 1514.17,-1812.03 1454.5,-1871.69 ; 1455.98,-1796.13 1481.98,-1770.12 1455.98,-1796.13 ; 1456.05,-1872.39 1516.41,-1812.03 1456.05,-1872.39 ; 1457.64,-1873.05 1518.66,-1812.03 1457.64,-1873.05 ; 1459.26,-1873.67 1496.54,-1836.39 1459.26,-1873.67 ; 1459.57,-1790.29 1476.8,-1773.07 1459.57,-1790.29 ; 1464.55,-1875.11 1496.07,-1843.6 1464.55,-1875.11 ; 1474.55,-1876.34 1499.67,-1851.22 1474.55,-1876.34 ; 1476.79,-1876.34 1500.88,-1852.26 1476.79,-1876.34 ; 1479.04,-1876.34 1502.36,-1853.02 1479.04,-1876.34 ; 1481.28,-1876.34 1503.97,-1853.65 1481.28,-1876.34 ; 1483.53,-1876.34 1505.66,-1854.21 1483.53,-1876.34 ; 1485.77,-1876.34 1507.4,-1854.71 1485.77,-1876.34 ; 1490.26,-1876.34 1510.94,-1855.66 1490.26,-1876.34 ; 1492.51,-1876.34 1513.11,-1855.74 1492.51,-1876.34 ; 1494.75,-1876.34 1515.36,-1855.74 1494.75,-1876.34 ; 1496.96,-1835.97 1520.9,-1812.03 1496.96,-1835.97 ; 1497,-1876.34 1517.6,-1855.74 1497,-1876.34 ; 1499.21,-1835.97 1523.15,-1812.03 1499.21,-1835.97 ; 1499.24,-1876.34 1519.85,-1855.74 1499.24,-1876.34 ; 1501.45,-1835.97 1525.39,-1812.03 1501.45,-1835.97 ; 1501.49,-1876.34 1522.09,-1855.74 1501.49,-1876.34 ; 1503.7,-1835.97 1527.64,-1812.03 1503.7,-1835.97 ; 1503.73,-1876.34 1524.34,-1855.74 1503.73,-1876.34 ; 1505.94,-1835.97 1529.88,-1812.03 1505.94,-1835.97 ; 1505.98,-1876.34 1526.59,-1855.74 1505.98,-1876.34 ; 1508.22,-1876.34 1528.83,-1855.74 1508.22,-1876.34 ; 1508.19,-1835.97 1532.13,-1812.03 1508.19,-1835.97 ; 1510.47,-1876.34 1531.08,-1855.74 1510.47,-1876.34 ; 1510.43,-1835.97 1534.37,-1812.03 1510.43,-1835.97 ; 1512.71,-1876.34 1533.32,-1855.74 1512.71,-1876.34 ; 1512.68,-1835.97 1536.62,-1812.03 1512.68,-1835.97 ; 1514.92,-1835.97 1538.86,-1812.03 1514.92,-1835.97 ; 1514.96,-1876.34 1535.57,-1855.74 1514.96,-1876.34 ; 1515.05,-1790.94 1539.25,-1766.74 1515.05,-1790.94 ; 1517.17,-1835.97 1541.11,-1812.03 1517.17,-1835.97 ; 1517.2,-1876.34 1537.81,-1855.74 1517.2,-1876.34 ; 1519.41,-1835.97 1543.35,-1812.03 1519.41,-1835.97 ; 1519.45,-1876.34 1540.06,-1855.74 1519.45,-1876.34 ; 1521.66,-1835.97 1545.6,-1812.03 1521.66,-1835.97 ; 1521.69,-1876.34 1542.3,-1855.74 1521.69,-1876.34 ; 1523.9,-1835.97 1547.84,-1812.03 1523.9,-1835.97 ; 1523.94,-1876.34 1544.55,-1855.74 1523.94,-1876.34 ; 1525.77,-1786.95 1545.98,-1766.74 1525.77,-1786.95 ; 1526.15,-1835.97 1550.09,-1812.03 1526.15,-1835.97 ; 1526.18,-1876.34 1546.79,-1855.74 1526.18,-1876.34 ; 1528.02,-1786.95 1548.23,-1766.74 1528.02,-1786.95 ; 1528.39,-1835.97 1552.33,-1812.03 1528.39,-1835.97 ; 1528.43,-1876.34 1549.04,-1855.74 1528.43,-1876.34 ; 1530.26,-1786.95 1550.47,-1766.74 1530.26,-1786.95 ; 1530.67,-1876.34 1551.28,-1855.74 1530.67,-1876.34 ; 1530.64,-1835.97 1554.58,-1812.03 1530.64,-1835.97 ; 1532.51,-1786.95 1552.72,-1766.74 1532.51,-1786.95 ; 1532.92,-1876.34 1553.53,-1855.74 1532.92,-1876.34 ; 1532.88,-1835.97 1556.82,-1812.03 1532.88,-1835.97 ; 1534.75,-1786.95 1554.97,-1766.74 1534.75,-1786.95 ; 1535.16,-1876.34 1555.77,-1855.74 1535.16,-1876.34 ; 1535.13,-1835.97 1559.07,-1812.03 1535.13,-1835.97 ; 1537,-1786.95 1557.21,-1766.74 1537,-1786.95 ; 1537.37,-1835.97 1561.31,-1812.03 1537.37,-1835.97 ; 1537.41,-1876.34 1558.02,-1855.74 1537.41,-1876.34 ; 1539.24,-1786.95 1559.46,-1766.74 1539.24,-1786.95 ; 1539.62,-1835.97 1563.56,-1812.03 1539.62,-1835.97 ; 1539.65,-1876.34 1560.26,-1855.74 1539.65,-1876.34 ; 1541.49,-1786.95 1561.7,-1766.74 1541.49,-1786.95 ; 1541.86,-1835.97 1565.8,-1812.03 1541.86,-1835.97 ; 1541.9,-1876.34 1562.51,-1855.74 1541.9,-1876.34 ; 1543.73,-1786.95 1563.95,-1766.74 1543.73,-1786.95 ; 1544.11,-1835.97 1568.05,-1812.03 1544.11,-1835.97 ; 1544.14,-1876.34 1564.75,-1855.74 1544.14,-1876.34 ; 1545.98,-1786.95 1566.19,-1766.74 1545.98,-1786.95 ; 1546.35,-1835.97 1570.29,-1812.03 1546.35,-1835.97 ; 1546.39,-1876.34 1567,-1855.74 1546.39,-1876.34 ; 1548.22,-1786.95 1568.44,-1766.74 1548.22,-1786.95 ; 1548.6,-1835.97 1572.54,-1812.03 1548.6,-1835.97 ; 1548.63,-1876.34 1568.93,-1856.05 1548.63,-1876.34 ; 1550.47,-1786.95 1570.68,-1766.74 1550.47,-1786.95 ; 1550.84,-1835.97 1574.78,-1812.03 1550.84,-1835.97 ; 1550.88,-1876.34 1568.22,-1859 1550.88,-1876.34 ; 1552.71,-1786.95 1572.93,-1766.74 1552.71,-1786.95 ; 1553.12,-1876.34 1567.52,-1861.95 1553.12,-1876.34 ; 1553.09,-1835.97 1577.03,-1812.03 1553.09,-1835.97 ; 1554.96,-1786.95 1575.17,-1766.74 1554.96,-1786.95 ; 1555.37,-1876.34 1566.81,-1864.9 1555.37,-1876.34 ; 1555.33,-1835.97 1579.27,-1812.03 1555.33,-1835.97 ; 1557.2,-1786.95 1577.42,-1766.74 1557.2,-1786.95 ; 1557.61,-1876.34 1566.11,-1867.85 1557.61,-1876.34 ; 1557.58,-1835.97 1581.52,-1812.03 1557.58,-1835.97 ; 1559.45,-1786.95 1579.66,-1766.74 1559.45,-1786.95 ; 1559.82,-1835.97 1583.76,-1812.03 1559.82,-1835.97 ; 1559.86,-1876.34 1565.41,-1870.8 1559.86,-1876.34 ; 1561.7,-1786.95 1581.91,-1766.74 1561.7,-1786.95 ; 1562.07,-1835.97 1586.01,-1812.03 1562.07,-1835.97 ; 1562.1,-1876.34 1564.7,-1873.75 1562.1,-1876.34 ; 1563.94,-1786.95 1584.15,-1766.74 1563.94,-1786.95 ; 1564.31,-1835.97 1588.25,-1812.03 1564.31,-1835.97 ; 1566.19,-1786.95 1586.4,-1766.74 1566.19,-1786.95 ; 1566.56,-1835.97 1590.5,-1812.03 1566.56,-1835.97 ; 1568.8,-1835.97 1592.74,-1812.03 1568.8,-1835.97 ; 1570.68,-1786.95 1588.01,-1769.61 1570.68,-1786.95 ; 1571.05,-1835.97 1594.99,-1812.03 1571.05,-1835.97 ; 1572.92,-1786.95 1587.36,-1772.51 1572.92,-1786.95 ; 1573.29,-1835.97 1597.23,-1812.03 1573.29,-1835.97 ; 1575.17,-1786.95 1586.7,-1775.41 1575.17,-1786.95 ; 1575.54,-1835.97 1599.48,-1812.03 1575.54,-1835.97 ; 1577.41,-1786.95 1586.05,-1778.31 1577.41,-1786.95 ; 1577.78,-1835.97 1601.72,-1812.03 1577.78,-1835.97 ; 1578.19,-1875.97 1609.93,-1844.24 1578.19,-1875.97 ; 1578.82,-1873.1 1607.68,-1844.24 1578.82,-1873.1 ; 1579.44,-1870.23 1605.44,-1844.24 1579.44,-1870.23 ; 1579.66,-1786.95 1585.39,-1781.22 1579.66,-1786.95 ; 1580.06,-1876.34 1612.17,-1844.24 1580.06,-1876.34 ; 1580.07,-1867.36 1603.19,-1844.24 1580.07,-1867.36 ; 1580.03,-1835.97 1603.97,-1812.03 1580.03,-1835.97 ; 1580.7,-1864.49 1600.95,-1844.24 1580.7,-1864.49 ; 1581.32,-1861.62 1598.7,-1844.24 1581.32,-1861.62 ; 1581.9,-1786.95 1584.73,-1784.12 1581.9,-1786.95 ; 1581.95,-1858.74 1596.46,-1844.24 1581.95,-1858.74 ; 1582.27,-1835.97 1606.21,-1812.03 1582.27,-1835.97 ; 1582.31,-1876.34 1614.42,-1844.24 1582.31,-1876.34 ; 1582.58,-1855.87 1594.21,-1844.24 1582.58,-1855.87 ; 1583.2,-1853 1591.97,-1844.24 1583.2,-1853 ; 1583.83,-1850.13 1589.72,-1844.24 1583.83,-1850.13 ; 1584.46,-1847.26 1587.48,-1844.24 1584.46,-1847.26 ; 1584.52,-1835.97 1608.46,-1812.03 1584.52,-1835.97 ; 1584.55,-1876.34 1616.66,-1844.24 1584.55,-1876.34 ; 1585.08,-1844.38 1585.23,-1844.24 1585.08,-1844.38 ; 1586.76,-1835.97 1610.7,-1812.03 1586.76,-1835.97 ; 1586.8,-1876.34 1618.91,-1844.24 1586.8,-1876.34 ; 1589.01,-1835.97 1612.95,-1812.03 1589.01,-1835.97 ; 1589.04,-1876.34 1621.15,-1844.24 1589.04,-1876.34 ; 1591.25,-1835.97 1615.19,-1812.03 1591.25,-1835.97 ; 1591.29,-1876.34 1623.4,-1844.24 1591.29,-1876.34 ; 1593.5,-1835.97 1617.44,-1812.03 1593.5,-1835.97 ; 1593.53,-1876.34 1625.64,-1844.24 1593.53,-1876.34 ; 1594.59,-1803.45 1631.3,-1766.74 1594.59,-1803.45 ; 1595.2,-1800.6 1629.05,-1766.74 1595.2,-1800.6 ; 1595.74,-1835.97 1619.68,-1812.03 1595.74,-1835.97 ; 1595.78,-1876.34 1627.89,-1844.24 1595.78,-1876.34 ; 1595.83,-1797.71 1626.81,-1766.74 1595.83,-1797.71 ; 1596.47,-1794.83 1624.56,-1766.74 1596.47,-1794.83 ; 1596.84,-1803.45 1633.54,-1766.74 1596.84,-1803.45 ; 1597.11,-1791.95 1622.32,-1766.74 1597.11,-1791.95 ; 1597.75,-1789.06 1620.07,-1766.74 1597.75,-1789.06 ; 1598.02,-1876.34 1630.13,-1844.24 1598.02,-1876.34 ; 1597.99,-1835.97 1621.93,-1812.03 1597.99,-1835.97 ; 1598.39,-1786.18 1617.83,-1766.74 1598.39,-1786.18 ; 1599.02,-1783.3 1615.58,-1766.74 1599.02,-1783.3 ; 1599.08,-1803.45 1635.79,-1766.74 1599.08,-1803.45 ; 1599.66,-1780.41 1613.34,-1766.74 1599.66,-1780.41 ; 1600.27,-1876.34 1632.38,-1844.24 1600.27,-1876.34 ; 1600.23,-1835.97 1624.17,-1812.03 1600.23,-1835.97 ; 1600.3,-1777.53 1611.09,-1766.74 1600.3,-1777.53 ; 1600.94,-1774.65 1608.85,-1766.74 1600.94,-1774.65 ; 1601.33,-1803.45 1638.03,-1766.74 1601.33,-1803.45 ; 1601.58,-1771.76 1606.6,-1766.74 1601.58,-1771.76 ; 1602.22,-1768.88 1604.36,-1766.74 1602.22,-1768.88 ; 1602.51,-1876.34 1634.62,-1844.24 1602.51,-1876.34 ; 1602.48,-1835.97 1626.42,-1812.03 1602.48,-1835.97 ; 1603.57,-1803.45 1640.28,-1766.74 1603.57,-1803.45 ; 1604.72,-1835.97 1628.66,-1812.03 1604.72,-1835.97 ; 1604.76,-1876.34 1636.87,-1844.24 1604.76,-1876.34 ; 1605.82,-1803.45 1642.52,-1766.74 1605.82,-1803.45 ; 1606.97,-1835.97 1630.91,-1812.03 1606.97,-1835.97 ; 1607,-1876.34 1639.04,-1844.31 1607,-1876.34 ; 1608.06,-1803.45 1644.77,-1766.74 1608.06,-1803.45 ; 1609.21,-1835.97 1633.15,-1812.03 1609.21,-1835.97 ; 1609.25,-1876.34 1638.4,-1847.19 1609.25,-1876.34 ; 1610.31,-1803.45 1647.01,-1766.74 1610.31,-1803.45 ; 1611.46,-1835.97 1635.4,-1812.03 1611.46,-1835.97 ; 1611.5,-1876.34 1637.77,-1850.07 1611.5,-1876.34 ; 1612.55,-1803.45 1649.26,-1766.74 1612.55,-1803.45 ; 1613.7,-1835.97 1637.64,-1812.03 1613.7,-1835.97 ; 1613.74,-1876.34 1637.14,-1852.94 1613.74,-1876.34 ; 1614.8,-1803.45 1651.5,-1766.74 1614.8,-1803.45 ; 1615.95,-1835.97 1639.89,-1812.03 1615.95,-1835.97 ; 1615.99,-1876.34 1636.51,-1855.82 1615.99,-1876.34 ; 1617.04,-1803.45 1653.75,-1766.74 1617.04,-1803.45 ; 1618.2,-1835.97 1642.14,-1812.03 1618.2,-1835.97 ; 1618.23,-1876.34 1635.88,-1858.7 1618.23,-1876.34 ; 1619.29,-1803.45 1655.99,-1766.74 1619.29,-1803.45 ; 1620.44,-1835.97 1644.38,-1812.03 1620.44,-1835.97 ; 1620.48,-1876.34 1635.25,-1861.57 1620.48,-1876.34 ; 1621.53,-1803.45 1658.24,-1766.74 1621.53,-1803.45 ; 1622.72,-1876.34 1634.61,-1864.45 1622.72,-1876.34 ; 1622.69,-1835.97 1646.63,-1812.03 1622.69,-1835.97 ; 1623.78,-1803.45 1660.48,-1766.74 1623.78,-1803.45 ; 1624.97,-1876.34 1633.98,-1867.33 1624.97,-1876.34 ; 1624.93,-1835.97 1648.87,-1812.03 1624.93,-1835.97 ; 1626.02,-1803.45 1662.73,-1766.74 1626.02,-1803.45 ; 1627.21,-1876.34 1633.35,-1870.2 1627.21,-1876.34 ; 1627.18,-1835.97 1651.12,-1812.03 1627.18,-1835.97 ; 1628.27,-1803.45 1664.97,-1766.74 1628.27,-1803.45 ; 1629.42,-1835.97 1653.36,-1812.03 1629.42,-1835.97 ; 1629.46,-1876.34 1632.72,-1873.08 1629.46,-1876.34 ; 1630.51,-1803.45 1667.22,-1766.74 1630.51,-1803.45 ; 1631.67,-1835.97 1655.61,-1812.03 1631.67,-1835.97 ; 1631.7,-1876.34 1632.09,-1875.96 1631.7,-1876.34 ; 1632.76,-1803.45 1669.46,-1766.74 1632.76,-1803.45 ; 1633.91,-1835.97 1657.85,-1812.03 1633.91,-1835.97 ; 1635,-1803.45 1651.57,-1786.88 1635,-1803.45 ; 1636.16,-1835.97 1660.1,-1812.03 1636.16,-1835.97 ; 1637.25,-1803.45 1650.92,-1789.77 1637.25,-1803.45 ; 1638.4,-1835.97 1662.34,-1812.03 1638.4,-1835.97 ; 1639.49,-1803.45 1650.27,-1792.67 1639.49,-1803.45 ; 1640.65,-1835.97 1664.59,-1812.03 1640.65,-1835.97 ; 1641.74,-1803.45 1649.62,-1795.56 1641.74,-1803.45 ; 1642.89,-1835.97 1666.83,-1812.03 1642.89,-1835.97 ; 1643.98,-1803.45 1648.98,-1798.45 1643.98,-1803.45 ; 1645.14,-1835.97 1669.08,-1812.03 1645.14,-1835.97 ; 1646,-1837.35 1671.32,-1812.03 1646,-1837.35 ; 1646.23,-1803.45 1648.33,-1801.34 1646.23,-1803.45 ; 1646.42,-1839.18 1673.57,-1812.03 1646.42,-1839.18 ; 1646.83,-1841.01 1675.81,-1812.03 1646.83,-1841.01 ; 1647.25,-1842.83 1678.06,-1812.03 1647.25,-1842.83 ; 1647.67,-1844.66 1680.3,-1812.03 1647.67,-1844.66 ; 1648.08,-1846.49 1682.55,-1812.03 1648.08,-1846.49 ; 1648.5,-1848.32 1684.79,-1812.03 1648.5,-1848.32 ; 1648.91,-1850.15 1688.21,-1810.86 1648.91,-1850.15 ; 1649.33,-1851.98 1721.4,-1779.91 1649.33,-1851.98 ; 1649.75,-1853.81 1722.08,-1781.48 1649.75,-1853.81 ; 1650.16,-1855.64 1722.69,-1783.11 1650.16,-1855.64 ; 1650.58,-1857.47 1723.25,-1784.79 1650.58,-1857.47 ; 1651,-1859.29 1723.75,-1786.54 1651,-1859.29 ; 1651.76,-1786.69 1671.71,-1766.74 1651.76,-1786.69 ; 1651.83,-1862.95 1724.45,-1790.33 1651.83,-1862.95 ; 1652.66,-1866.61 1724.46,-1794.81 1652.66,-1866.61 ; 1653.08,-1868.44 1724.48,-1797.04 1653.08,-1868.44 ; 1653.49,-1870.27 1724.5,-1799.26 1653.49,-1870.27 ; 1653.91,-1872.1 1724.45,-1801.55 1653.91,-1872.1 ; 1654.01,-1786.69 1673.95,-1766.74 1654.01,-1786.69 ; 1654.74,-1875.75 1698.93,-1831.56 1654.74,-1875.75 ; 1656.25,-1786.69 1676.2,-1766.74 1656.25,-1786.69 ; 1656.4,-1876.34 1699.31,-1833.43 1656.4,-1876.34 ; 1658.5,-1786.69 1678.44,-1766.74 1658.5,-1786.69 ; 1658.64,-1876.34 1699.68,-1835.3 1658.64,-1876.34 ; 1660.74,-1786.69 1680.69,-1766.74 1660.74,-1786.69 ; 1660.89,-1876.34 1700.06,-1837.17 1660.89,-1876.34 ; 1662.99,-1786.69 1682.93,-1766.74 1662.99,-1786.69 ; 1663.13,-1876.34 1700.44,-1839.04 1663.13,-1876.34 ; 1665.23,-1786.69 1685.18,-1766.74 1665.23,-1786.69 ; 1665.38,-1876.34 1700.82,-1840.91 1665.38,-1876.34 ; 1667.48,-1786.69 1687.42,-1766.74 1667.48,-1786.69 ; 1667.62,-1876.34 1701.19,-1842.77 1667.62,-1876.34 ; 1669.72,-1786.69 1689.67,-1766.74 1669.72,-1786.69 ; 1669.87,-1876.34 1701.57,-1844.64 1669.87,-1876.34 ; 1671.97,-1786.69 1691.91,-1766.74 1671.97,-1786.69 ; 1672.11,-1876.34 1701.95,-1846.51 1672.11,-1876.34 ; 1674.21,-1786.69 1694.16,-1766.74 1674.21,-1786.69 ; 1674.36,-1876.34 1702.32,-1848.38 1674.36,-1876.34 ; 1676.46,-1786.69 1696.4,-1766.74 1676.46,-1786.69 ; 1676.6,-1876.34 1702.7,-1850.25 1676.6,-1876.34 ; 1678.7,-1786.69 1698.65,-1766.74 1678.7,-1786.69 ; 1678.85,-1876.34 1703.08,-1852.11 1678.85,-1876.34 ; 1680.95,-1786.69 1700.89,-1766.74 1680.95,-1786.69 ; 1681.09,-1876.34 1703.45,-1853.98 1681.09,-1876.34 ; 1683.34,-1876.34 1703.83,-1855.85 1683.34,-1876.34 ; 1685.58,-1876.34 1704.21,-1857.72 1685.58,-1876.34 ; 1687.35,-1789.26 1708.21,-1768.4 1687.35,-1789.26 ; 1687.83,-1876.34 1704.59,-1859.59 1687.83,-1876.34 ; 1688.79,-1790.07 1709.78,-1769.08 1688.79,-1790.07 ; 1690.07,-1876.34 1704.96,-1861.45 1690.07,-1876.34 ; 1690.58,-1808.48 1720.67,-1778.39 1690.58,-1808.48 ; 1691.13,-1792.22 1712.75,-1770.6 1691.13,-1792.22 ; 1692.32,-1876.34 1705.34,-1863.32 1692.32,-1876.34 ; 1692.38,-1802.2 1718.93,-1775.64 1692.38,-1802.2 ; 1692.78,-1799.55 1717.88,-1774.45 1692.78,-1799.55 ; 1694.56,-1876.34 1705.72,-1865.19 1694.56,-1876.34 ; 1696.81,-1876.34 1706.09,-1867.06 1696.81,-1876.34 ; 1699.05,-1876.34 1706.47,-1868.93 1699.05,-1876.34 ; 1699.99,-1830.51 1723.78,-1806.72 1699.99,-1830.51 ; 1701.3,-1876.34 1706.85,-1870.79 1701.3,-1876.34 ; 1703.54,-1876.34 1707.22,-1872.66 1703.54,-1876.34 ; 1705.21,-1829.77 1721.8,-1813.18 1705.21,-1829.77 ; 1705.79,-1876.34 1707.6,-1874.53 1705.79,-1876.34 ; 1708.97,-1828.26 1719.86,-1817.37 1708.97,-1828.26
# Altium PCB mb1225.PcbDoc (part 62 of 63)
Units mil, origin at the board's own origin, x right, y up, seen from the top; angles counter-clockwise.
Board outline 5000 x 3464.56 mil, 6 copper layers (TOP, L2_GND, L3_VCC, L4_SIG, L5_GND, BOTTOM), stack 62.2 mil thick; 452 components, 378 nets, 1968 pads, 949 vias.

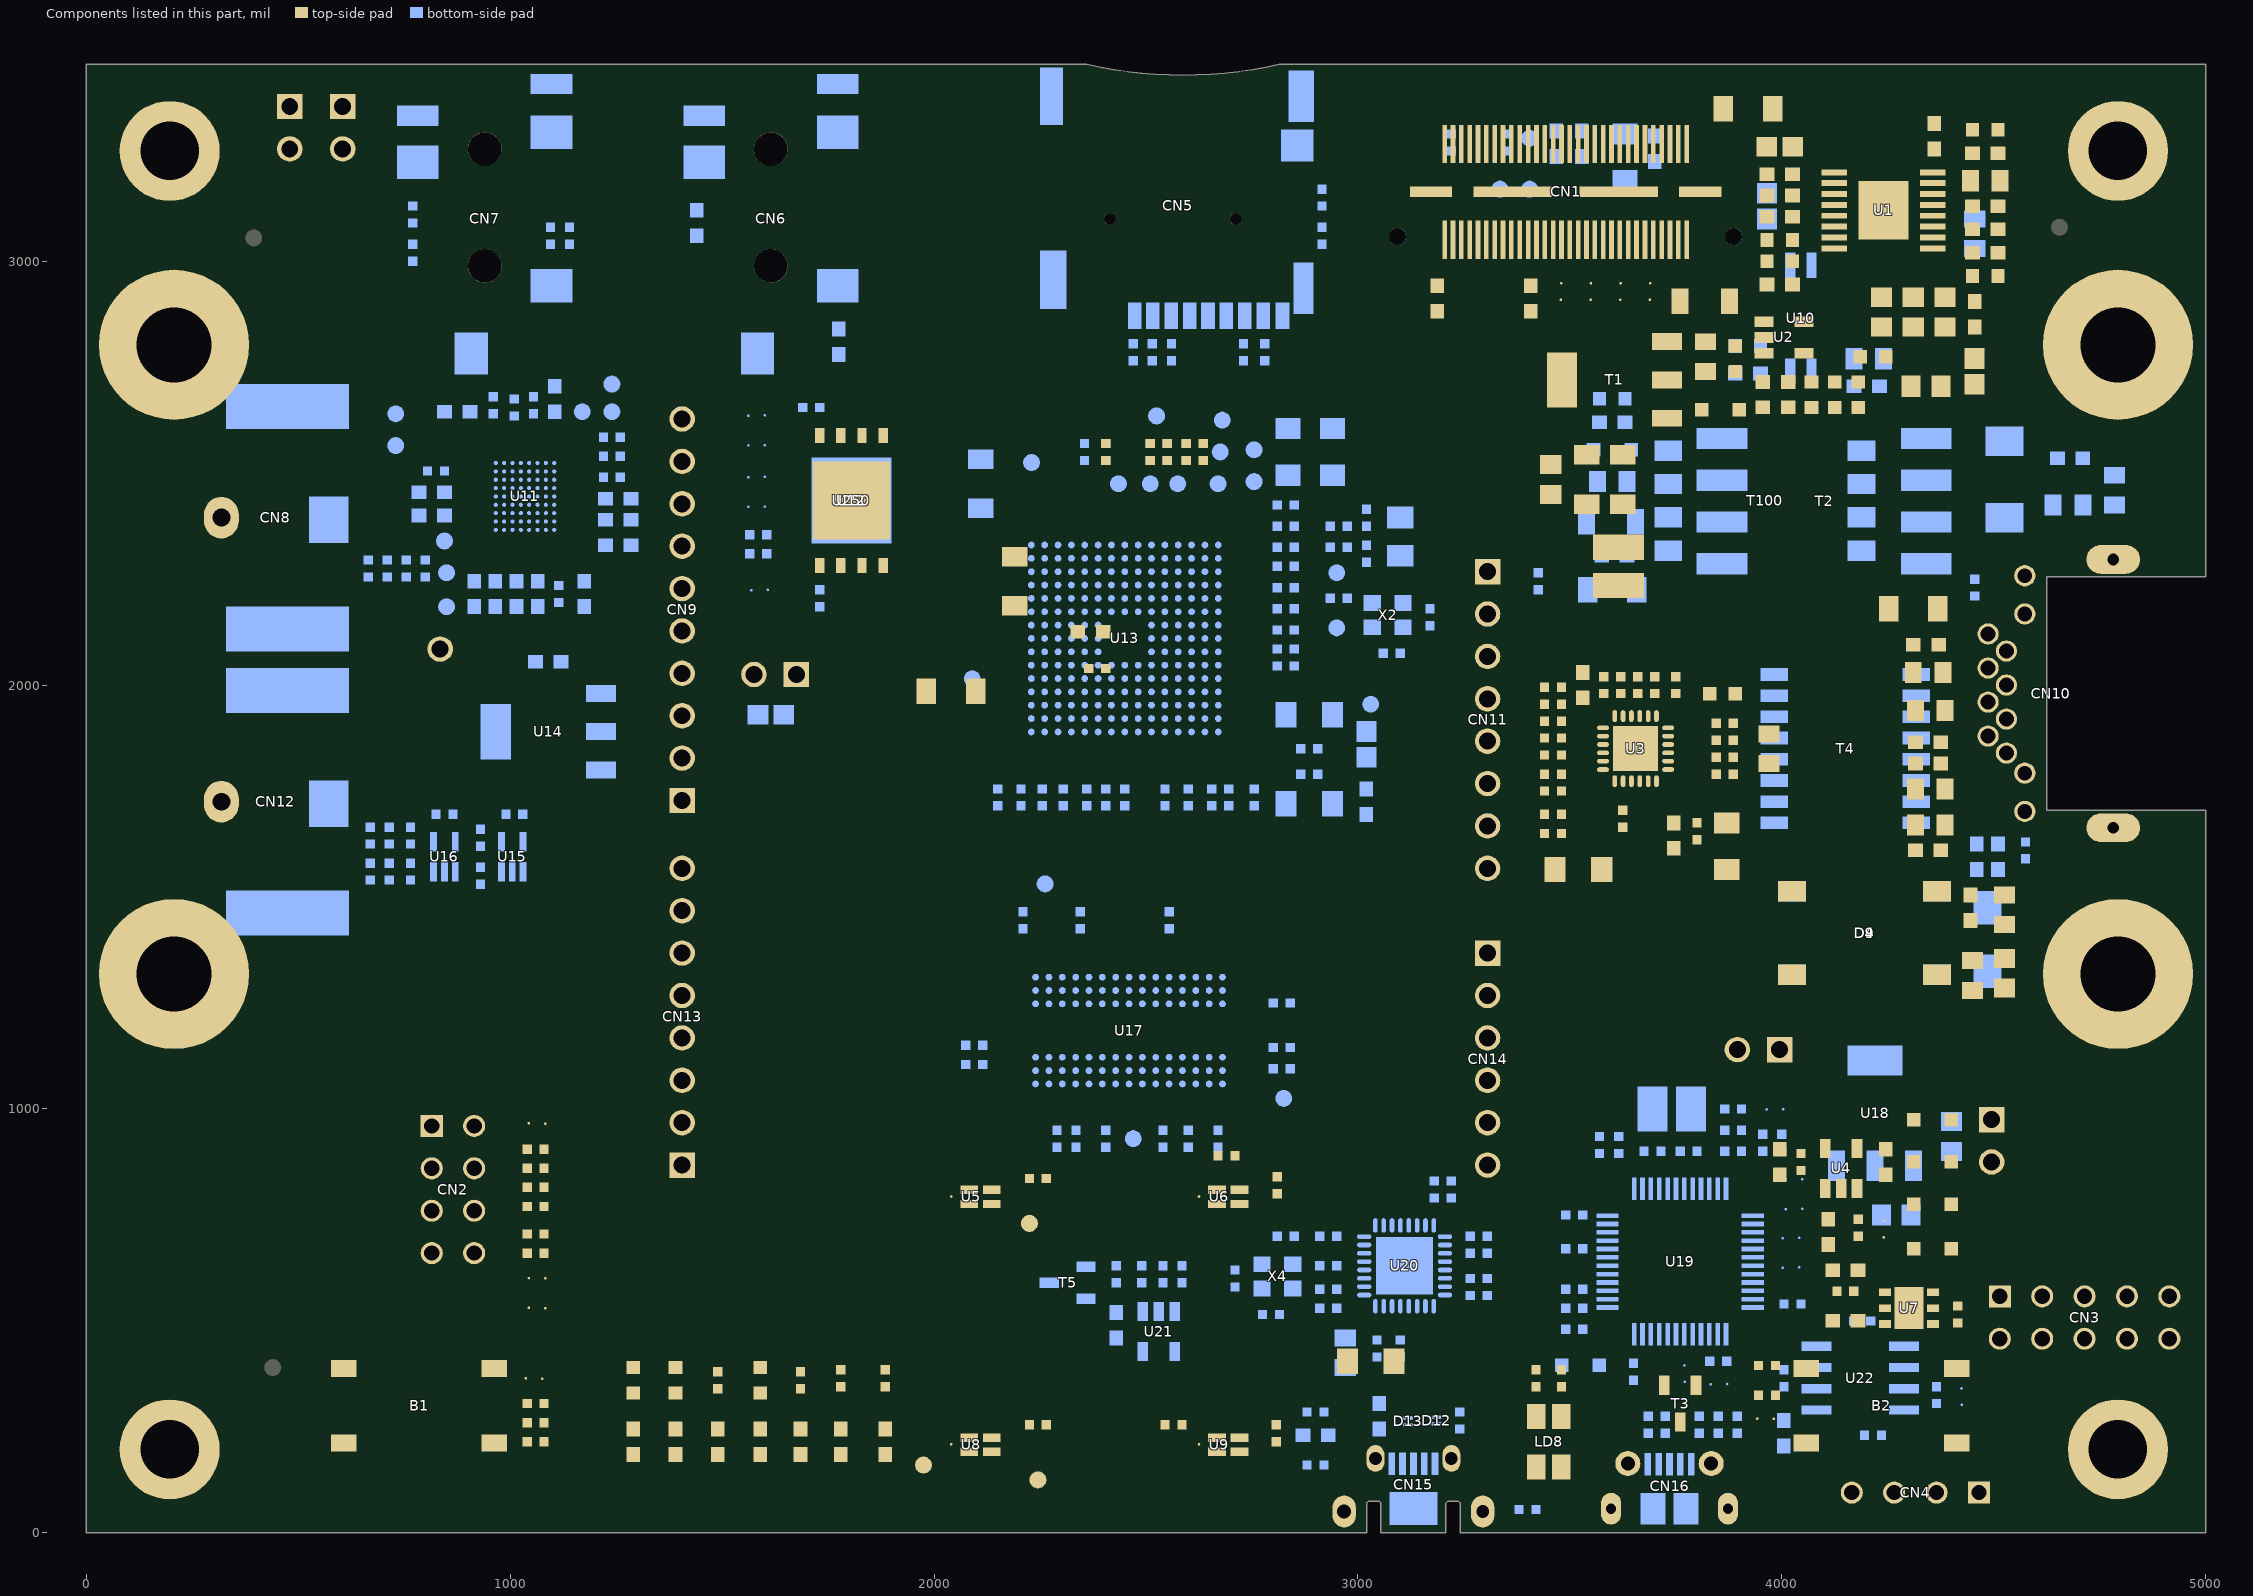
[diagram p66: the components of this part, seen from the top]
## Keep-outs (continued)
BOTTOM:
  circle w1: c4655,3080 r60
  circle w1: c4655,3080 r65
  circle w1: c440,390 r60
  circle w1: c440,390 r65
  circle w1: c395,3055 r65
  circle w1: c395,3055 r60
  circle w1: c4655,3080 r60
  circle w1: c4655,3080 r65
  circle w1: c440,390 r60
  circle w1: c440,390 r65
  circle w1: c395,3055 r65
  circle w1: c395,3055 r60
Keep-Out Layer:
  lines w1: -3560,-5040 18040,-5040 ; -3560,-5040 -3560,11160 ; -3560,-5040 18040,-5040 ; -3560,-5040 -3560,11160 ; -3560,11160 18040,11160 ; -3560,11160 18040,11160 ; -3260,-4740 -3260,10860 ; -3260,-4740 12840,-4740 ; -3260,-4740 -3260,10860 ; -3260,-4740 12840,-4740 ; -3260,10860 17740,10860 ; -3260,10860 17740,10860 ; 2360,3464.56 ccw(c2587.5,4472.06) 2815,3464.56 ; 2360,3464.56 ccw(c2587.5,4472.06) 2815,3464.56 ; 2360,3464.56 0,3464.56 0,0 3020.63,0 3020.63,70.28 3024.57,74.22 3050.16,74.22 3054.1,70.28 3054.1,0 3207.64,0 3207.64,70.28 3211.58,74.22 3237.17,74.22 3241.11,70.28 3241.11,0 5000,0 5000,1705 4625,1705 4625,2255 5000,2255 5000,3464.56 2815,3464.56 ; 7040,-4590 7240,-4790 ; 7040,-4590 7240,-5040 ; 7040,-4590 7440,-4590 ; 7040,-4590 7240,-4790 ; 7040,-4590 7240,-5040 ; 7040,-4590 7440,-4590 ; 7240,-5040 7240,-4740 7240,-5040 ; 7240,-5040 7240,-4340 7240,-5040 ; 7240,-5040 7440,-4590 ; 7240,-5040 7440,-4590 ; 7240,-4790 7440,-4590 ; 7240,-4790 7440,-4590 ; 12840,-4740 17740,-4740 ; 12840,-4740 17740,-4740 ; 17740,-4740 17740,4860 ; 17740,-4740 17740,4860 ; 17740,4860 17740,8660 17740,4860 ; 17740,10860 17740,3260 17740,10860 ; 18040,-5040 18040,11160 ; 18040,-5040 18040,11160 ; -3560,-840 -3260,-840 -3560,-840 ; -3560,3060 -3260,3060 -3560,3060 ; -3560,6960 -3260,6960 -3560,6960 ; 240,-5040 240,-4740 240,-5040 ; 240,10860 240,11160 240,10860 ; 3740,-5040 3740,-4740 3740,-5040 ; 3740,10860 3740,11160 3740,10860 ; 4999.99,255 5000,255 ; 7240,10860 7240,11160 7240,10860 ; 10740,-5040 10740,-4740 10740,-5040 ; 10740,10860 10740,11160 10740,10860 ; 14240,-5040 14240,-4740 14240,-5040 ; 14240,10860 14240,11160 14240,10860 ; 17740,-840 18040,-840 17740,-840 ; 17740,3060 18040,3060 17740,3060 ; 17740,6960 18040,6960 17740,6960
  text "6" at -1460,10960 h130
  text "6" at -1460,10960 h130
  text "5" at 2040,10960 h130
  text "5" at 2040,10960 h130
  text "4" at 5540,10960 h130
  text "4" at 5540,10960 h130
  text "3" at 9040,10960 h130
  text "3" at 9040,10960 h130
  text "2" at 12540,10960 h130
  text "2" at 12540,10960 h130
  text "1" at 16040,10960 h130
  text "1" at 16040,10960 h130
  text "D" at -3460,8660 h130
  text "D" at -3460,8660 h130
  text "D" at 17840,8660 h130
  text "D" at 17840,8660 h130
  text "C" at -3460,4760 h130
  text "C" at -3460,4760 h130
  text "C" at 17840,4760 h130
  text "C" at 17840,4760 h130
  text "B" at -3460,1060 h130
  text "B" at -3460,1060 h130
  text "B" at 17840,1060 h130
  text "B" at 17840,1060 h130
  text "A" at -3460,-3140 h130
  text "A" at -3460,-3140 h130
  text "A" at 17840,-3140 h130
  text "A" at 17840,-3140 h130
  text "6" at -1460,-4940 h130
  text "6" at -1460,-4940 h130
  text "5" at 2040,-4940 h130
  text "5" at 2040,-4940 h130
  text "4" at 5540,-4940 h130
  text "4" at 5540,-4940 h130
  text "3" at 9040,-4940 h130
  text "3" at 9040,-4940 h130
  text "2" at 12540,-4940 h130
  text "2" at 12540,-4940 h130
  text "1" at 16040,-4940 h130
  text "1" at 16040,-4940 h130
Multi-Layer:
  region: 3,1088 3,527 555,527 555,1088 3,1088
  region: 4025,2105 4025,1597 4273,1597 4273,2105 4025,2105

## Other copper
TOP:
  pour cut-out: 2290.95,2250.83 2289.93,2255.91 2287.06,2260.22 2282.75,2263.09 2277.67,2264.11 2272.59,2263.09 2268.28,2260.22 2265.41,2255.91 2264.39,2250.83 2265.41,2245.75 2268.28,2241.44 2272.59,2238.57 2277.67,2237.55 2282.75,2238.57 2287.06,2241.44 2289.93,2245.75 2290.95,2250.83
  pour cut-out: 2323.28,2251 2322.26,2256.08 2319.39,2260.39 2315.08,2263.26 2310,2264.28 2304.92,2263.26 2300.61,2260.39 2297.74,2256.08 2296.72,2251 2297.74,2245.92 2300.61,2241.61 2304.92,2238.74 2310,2237.72 2315.08,2238.74 2319.39,2241.61 2322.26,2245.92 2323.28,2251
  pour cut-out: 2294.33,2396 2293.09,2402.25 2289.55,2407.55 2284.25,2411.09 2278,2412.33 2271.75,2411.09 2266.45,2407.55 2262.91,2402.25 2261.67,2396 2262.91,2389.75 2266.45,2384.45 2271.75,2380.91 2278,2379.67 2284.25,2380.91 2289.55,2384.45 2293.09,2389.75 2294.33,2396
  pour cut-out: 2322.45,2219.34 2321.43,2224.42 2318.56,2228.73 2314.25,2231.6 2309.17,2232.62 2304.09,2231.6 2299.78,2228.73 2296.91,2224.42 2295.89,2219.34 2296.91,2214.26 2299.78,2209.95 2304.09,2207.08 2309.17,2206.06 2314.25,2207.08 2318.56,2209.95 2321.43,2214.26 2322.45,2219.34
  pour cut-out: 4646.52,458 4645.42,466.36 4642.19,474.15 4637.06,480.84 4630.37,485.97 4622.58,489.2 4614.22,490.3 4605.86,489.2 4598.07,485.97 4591.38,480.84 4586.25,474.15 4583.02,466.36 4581.92,458 4583.02,449.64 4586.25,441.85 4591.38,435.16 4598.07,430.03 4605.86,426.8 4614.22,425.7 4622.58,426.8 4630.37,430.03 4637.06,435.16 4642.19,441.85 4645.42,449.64 4646.52,458
  pour cut-out: 4546.52,458 4545.42,466.36 4542.19,474.15 4537.06,480.84 4530.37,485.97 4522.58,489.2 4514.22,490.3 4505.86,489.2 4498.07,485.97 4491.38,480.84 4486.25,474.15 4483.02,466.36 4481.92,458 4483.02,449.64 4486.25,441.85 4491.38,435.16 4498.07,430.03 4505.86,426.8 4514.22,425.7 4522.58,426.8 4530.37,430.03 4537.06,435.16 4542.19,441.85 4545.42,449.64 4546.52,458
  pour cut-out: 4846.52,458 4845.42,466.36 4842.19,474.15 4837.06,480.84 4830.37,485.97 4822.58,489.2 4814.22,490.3 4805.86,489.2 4798.07,485.97 4791.38,480.84 4786.25,474.15 4783.02,466.36 4781.92,458 4783.02,449.64 4786.25,441.85 4791.38,435.16 4798.07,430.03 4805.86,426.8 4814.22,425.7 4822.58,426.8 4830.37,430.03 4837.06,435.16 4842.19,441.85 4845.42,449.64 4846.52,458
  pour cut-out: 4746.52,458 4745.42,466.36 4742.19,474.15 4737.06,480.84 4730.37,485.97 4722.58,489.2 4714.22,490.3 4705.86,489.2 4698.07,485.97 4691.38,480.84 4686.25,474.15 4683.02,466.36 4681.92,458 4683.02,449.64 4686.25,441.85 4691.38,435.16 4698.07,430.03 4705.86,426.8 4714.22,425.7 4722.58,426.8 4730.37,430.03 4737.06,435.16 4742.19,441.85 4745.42,449.64 4746.52,458
  pour cut-out: 4946.52,458 4945.42,466.36 4942.19,474.15 4937.06,480.84 4930.37,485.97 4922.58,489.2 4914.22,490.3 4905.86,489.2 4898.07,485.97 4891.38,480.84 4886.25,474.15 4883.02,466.36 4881.92,458 4883.02,449.64 4886.25,441.85 4891.38,435.16 4898.07,430.03 4905.86,426.8 4914.22,425.7 4922.58,426.8 4930.37,430.03 4937.06,435.16 4942.19,441.85 4945.42,449.64 4946.52,458
  text "1" at 541.7,1308.3 h34
  text "1" at 541.7,1308.3 h34
  text "B" at 540,1230 h34
  text "B" at 540,1230 h34
  text "COMPANY NAME:" at 3735,-1740 h60
  text "COMPANY NAME:" at 3735,-1740 h60
  text "LAYER:" at 2135,-1790 h75
  text "LAYER:" at 2135,-1790 h75
  text "1" at 2685,-1790 h75
  text "1" at 2685,-1790 h75
  text "ST" at 3885,-1890 h75
  text "ST" at 3885,-1890 h75
  text "PRIMARY SIDE" at 2185,-1940 h60
  text "PRIMARY SIDE" at 2185,-1940 h60
  text "PROJECT NAME:" at 3735,-2040 h60
  text "PROJECT NAME:" at 3735,-2040 h60
  text "DESIGNED BY SOFER" at 865,-2060 h60
  text "DESIGNED BY SOFER" at 865,-2060 h60
  text "www.sofer.com.cn" at 885,-2160 h60
  text "www.sofer.com.cn" at 885,-2160 h60
  text "DESIGNER:" at 2185,-2190 h60
  text "DESIGNER:" at 2185,-2190 h60
  text "Shelley" at 2685,-2190 h60
  text "Shelley" at 2685,-2190 h60
  text "MB1225" at 3885,-2190 h75
  text "MB1225" at 3885,-2190 h75
  text "Tel : +86 21 - 6482 6908" at 685,-2340 h60
  text "Tel : +86 21 - 6482 6908" at 685,-2340 h60
  text "PROJECT NUMBER:" at 3735,-2340 h60
  text "PROJECT NUMBER:" at 3735,-2340 h60
  text "REV" at 4935,-2340 h60
  text "REV" at 4935,-2340 h60
  text "Mail: design@sofer.com.cn" at 685,-2440 h60
  text "Mail: design@sofer.com.cn" at 685,-2440 h60
  text "DATE:" at 2185,-2440 h60
  text "DATE:" at 2185,-2440 h60
  text "2016.02.18" at 2485,-2440 h60
  text "2016.02.18" at 2485,-2440 h60
  text "D031-019A2" at 3885,-2490 h75
  text "D031-019A2" at 3885,-2490 h75
  text "B" at 5035,-2490 h75
  text "B" at 5035,-2490 h75
L4_SIG:
  text "4" at 785,1310 h34
  text "4" at 785,1310 h34
  text "B" at 785,1230 h34
  text "B" at 785,1230 h34
  text "COMPANY NAME:" at 3735,-1740 h60
  text "COMPANY NAME:" at 3735,-1740 h60
  text "LAYER:" at 2135,-1790 h75
  text "LAYER:" at 2135,-1790 h75
  text "ST" at 3885,-1890 h75
  text "ST" at 3885,-1890 h75
  text "PROJECT NAME:" at 3735,-2040 h60
  text "PROJECT NAME:" at 3735,-2040 h60
  text "DESIGNED BY SOFER" at 865,-2060 h60
  text "DESIGNED BY SOFER" at 865,-2060 h60
  text "www.sofer.com.cn" at 885,-2160 h60
  text "www.sofer.com.cn" at 885,-2160 h60
  text "DESIGNER:" at 2185,-2190 h60
  text "DESIGNER:" at 2185,-2190 h60
  text "Shelley" at 2685,-2190 h60
  text "Shelley" at 2685,-2190 h60
  text "MB1225" at 3885,-2190 h75
  text "MB1225" at 3885,-2190 h75
  text "Tel : +86 21 - 6482 6908" at 685,-2340 h60
  text "Tel : +86 21 - 6482 6908" at 685,-2340 h60
  text "PROJECT NUMBER:" at 3735,-2340 h60
  text "PROJECT NUMBER:" at 3735,-2340 h60
  text "REV" at 4935,-2340 h60
  text "REV" at 4935,-2340 h60
  text "Mail: design@sofer.com.cn" at 685,-2440 h60
  text "Mail: design@sofer.com.cn" at 685,-2440 h60
  text "DATE:" at 2185,-2440 h60
  text "DATE:" at 2185,-2440 h60
  text "2016.02.18" at 2485,-2440 h60
  text "2016.02.18" at 2485,-2440 h60
  text "D031-019A2" at 3885,-2490 h75
  text "D031-019A2" at 3885,-2490 h75
  text "B" at 5035,-2490 h75
  text "B" at 5035,-2490 h75
BOTTOM:
  pour cut-out: 4531.33,875 4530.09,884.4 4526.46,893.17 4520.69,900.69 4513.17,906.46 4504.4,910.09 4495,911.33 4485.6,910.09 4476.83,906.46 4469.31,900.69 4463.54,893.17 4459.91,884.4 4458.67,875 4459.91,865.6 4463.54,856.83 4469.31,849.31 4476.83,843.54 4485.6,839.91 4495,838.67 4504.4,839.91 4513.17,843.54 4520.69,849.31 4526.46,856.83 4530.09,865.6 4531.33,875
  pour cut-out: 3939.33,3270 3938.09,3276.25 3934.55,3281.55 3929.25,3285.09 3923,3286.33 3916.75,3285.09 3911.45,3281.55 3907.91,3276.25 3906.67,3270 3907.91,3263.75 3911.45,3258.45 3916.75,3254.91 3923,3253.67 3929.25,3254.91 3934.55,3258.45 3938.09,3263.75 3939.33,3270
  pour cut-out: 4116.33,3250 4115.09,3256.25 4111.55,3261.55 4106.25,3265.09 4100,3266.33 4093.75,3265.09 4088.45,3261.55 4084.91,3256.25 4083.67,3250 4084.91,3243.75 4088.45,3238.45 4093.75,3234.91 4100,3233.67 4106.25,3234.91 4111.55,3238.45 4115.09,3243.75 4116.33,3250
  pour cut-out: 4086.33,3205 4085.09,3211.25 4081.55,3216.55 4076.25,3220.09 4070,3221.33 4063.75,3220.09 4058.45,3216.55 4054.91,3211.25 4053.67,3205 4054.91,3198.75 4058.45,3193.45 4063.75,3189.91 4070,3188.67 4076.25,3189.91 4081.55,3193.45 4085.09,3198.75 4086.33,3205
  pour cut-out: 4336.33,3265 4335.09,3271.25 4331.55,3276.55 4326.25,3280.09 4320,3281.33 4313.75,3280.09 4308.45,3276.55 4304.91,3271.25 4303.67,3265 4304.91,3258.75 4308.45,3253.45 4313.75,3249.91 4320,3248.67 4326.25,3249.91 4331.55,3253.45 4335.09,3258.75 4336.33,3265
  pour cut-out: 4571.33,3130 4570.09,3136.25 4566.55,3141.55 4561.25,3145.09 4555,3146.33 4548.75,3145.09 4543.45,3141.55 4539.91,3136.25 4538.67,3130 4539.91,3123.75 4543.45,3118.45 4548.75,3114.91 4555,3113.67 4561.25,3114.91 4566.55,3118.45 4570.09,3123.75 4571.33,3130
  pour cut-out: 4571.33,3190 4570.09,3196.25 4566.55,3201.55 4561.25,3205.09 4555,3206.33 4548.75,3205.09 4543.45,3201.55 4539.91,3196.25 4538.67,3190 4539.91,3183.75 4543.45,3178.45 4548.75,3174.91 4555,3173.67 4561.25,3174.91 4566.55,3178.45 4570.09,3183.75 4571.33,3190
  pour cut-out: 4571.33,3255 4570.09,3261.25 4566.55,3266.55 4561.25,3270.09 4555,3271.33 4548.75,3270.09 4543.45,3266.55 4539.91,3261.25 4538.67,3255 4539.91,3248.75 4543.45,3243.45 4548.75,3239.91 4555,3238.67 4561.25,3239.91 4566.55,3243.45 4570.09,3248.75 4571.33,3255
  pour cut-out: 4196.33,660 4195.09,666.25 4191.55,671.55 4186.25,675.09 4180,676.33 4173.75,675.09 4168.45,671.55 4164.91,666.25 4163.67,660 4164.91,653.75 4168.45,648.45 4173.75,644.91 4180,643.67 4186.25,644.91 4191.55,648.45 4195.09,653.75 4196.33,660
  pour cut-out: 4161.33,770 4160.09,776.25 4156.55,781.55 4151.25,785.09 4145,786.33 4138.75,785.09 4133.45,781.55 4129.91,776.25 4128.67,770 4129.91,763.75 4133.45,758.45 4138.75,754.91 4145,753.67 4151.25,754.91 4156.55,758.45 4160.09,763.75 4161.33,770
  text "6" at 925,1310 h34
  text "6" at 925,1310 h34
  text "B" at 920,1230 h34
  text "B" at 920,1230 h34
  text "COMPANY NAME:" at 3735,-1740 h60
  text "COMPANY NAME:" at 3735,-1740 h60
  text "LAYER:" at 2135,-1790 h75
  text "LAYER:" at 2135,-1790 h75
  text "6" at 2635,-1790 h75
  text "6" at 2635,-1790 h75
  text "ST" at 3885,-1890 h75
  text "ST" at 3885,-1890 h75
  text "SECONDARY SIDE" at 2185,-1940 h60
  text "SECONDARY SIDE" at 2185,-1940 h60
  text "PROJECT NAME:" at 3735,-2040 h60
  text "PROJECT NAME:" at 3735,-2040 h60
  text "DESIGNED BY SOFER" at 865,-2060 h60
  text "DESIGNED BY SOFER" at 865,-2060 h60
  text "www.sofer.com.cn" at 885,-2160 h60
  text "www.sofer.com.cn" at 885,-2160 h60
  text "DESIGNER:" at 2185,-2190 h60
  text "DESIGNER:" at 2185,-2190 h60
  text "Shelley" at 2685,-2190 h60
  text "Shelley" at 2685,-2190 h60
  text "MB1225" at 3885,-2190 h75
  text "MB1225" at 3885,-2190 h75
  text "Tel : +86 21 - 6482 6908" at 685,-2340 h60
  text "Tel : +86 21 - 6482 6908" at 685,-2340 h60
  text "PROJECT NUMBER:" at 3735,-2340 h60
  text "PROJECT NUMBER:" at 3735,-2340 h60
  text "REV" at 4935,-2340 h60
  text "REV" at 4935,-2340 h60
  text "Mail: design@sofer.com.cn" at 685,-2440 h60
  text "Mail: design@sofer.com.cn" at 685,-2440 h60
  text "DATE:" at 2185,-2440 h60
  text "DATE:" at 2185,-2440 h60
  text "2016.02.18" at 2485,-2440 h60
  text "2016.02.18" at 2485,-2440 h60
  text "D031-019A2" at 3885,-2490 h75
  text "D031-019A2" at 3885,-2490 h75
  text "B" at 5035,-2490 h75
  text "B" at 5035,-2490 h75
L2_GND (plane layer: these items are gaps in the copper):
  region: 4024.98,2105 4024.98,1595 4273,1595 4273,2105
  region: 591,1300.04 591,1276.1 663.94,1276.1 663.94,1300.04
  region: 450.03,1360.01 450.03,1215.02 601.35,1215.02 601.35,1360.01
  region: 655.62,1360.01 655.62,1215.02 1013.38,1215.02 1013.38,1360.01
  region: 0,1088 0,527 555,527 555,1088
  pour cut-out: 2741.52,3099.56 2740.52,3107.14 2737.6,3114.2 2732.94,3120.26 2726.88,3124.92 2719.82,3127.84 2712.24,3128.84 2704.66,3127.84 2697.6,3124.92 2691.54,3120.26 2686.88,3114.2 2683.96,3107.14 2682.96,3099.56 2683.96,3091.98 2686.88,3084.92 2691.54,3078.86 2697.6,3074.2 2704.66,3071.28 2712.24,3070.28 2719.82,3071.28 2726.88,3074.2 2732.94,3078.86 2737.6,3084.92 2740.52,3091.98 2741.52,3099.56
  pour cut-out: 2444.28,3099.56 2443.28,3107.14 2440.36,3114.2 2435.7,3120.26 2429.64,3124.92 2422.58,3127.84 2415,3128.84 2407.42,3127.84 2400.36,3124.92 2394.3,3120.26 2389.64,3114.2 2386.72,3107.14 2385.72,3099.56 2386.72,3091.98 2389.64,3084.92 2394.3,3078.86 2400.36,3074.2 2407.42,3071.28 2415,3070.28 2422.58,3071.28 2429.64,3074.2 2435.7,3078.86 2440.36,3084.92 2443.28,3091.98 2444.28,3099.56
  pour cut-out: 1669.83,3264.56 1667.96,3278.75 1662.48,3291.97 1653.77,3303.33 1642.41,3312.04 1629.19,3317.52 1615,3319.39 1600.81,3317.52 1587.59,3312.04 1576.23,3303.33 1567.52,3291.97 1562.04,3278.75 1560.17,3264.56 1562.04,3250.37 1567.52,3237.15 1576.23,3225.79 1587.59,3217.08 1600.81,3211.6 1615,3209.73 1629.19,3211.6 1642.41,3217.08 1653.77,3225.79 1662.48,3237.15 1667.96,3250.37 1669.83,3264.56
  pour cut-out: 994.83,3264.56 992.96,3278.75 987.48,3291.97 978.77,3303.33 967.41,3312.04 954.19,3317.52 940,3319.39 925.81,3317.52 912.59,3312.04 901.23,3303.33 892.52,3291.97 887.04,3278.75 885.17,3264.56 887.04,3250.37 892.52,3237.15 901.23,3225.79 912.59,3217.08 925.81,3211.6 940,3209.73 954.19,3211.6 967.41,3217.08 978.77,3225.79 987.48,3237.15 992.96,3250.37 994.83,3264.56
  pour cut-out: 994.83,2988.97 992.96,3003.16 987.48,3016.38 978.77,3027.74 967.41,3036.45 954.19,3041.93 940,3043.8 925.81,3041.93 912.59,3036.45 901.23,3027.74 892.52,3016.38 887.04,3003.16 885.17,2988.97 887.04,2974.78 892.52,2961.56 901.23,2950.2 912.59,2941.49 925.81,2936.01 940,2934.14 954.19,2936.01 967.41,2941.49 978.77,2950.2 987.48,2961.56 992.96,2974.78 994.83,2988.97
  pour cut-out: 1669.83,2988.97 1667.96,3003.16 1662.48,3016.38 1653.77,3027.74 1642.41,3036.45 1629.19,3041.93 1615,3043.8 1600.81,3041.93 1587.59,3036.45 1576.23,3027.74 1567.52,3016.38 1562.04,3003.16 1560.17,2988.97 1562.04,2974.78 1567.52,2961.56 1576.23,2950.2 1587.59,2941.49 1600.81,2936.01 1615,2934.14 1629.19,2936.01 1642.41,2941.49 1653.77,2950.2 1662.48,2961.56 1667.96,2974.78 1669.83,2988.97
  pour cut-out: 3129.5,3058.42 3128.28,3067.68 3124.7,3076.3 3119.02,3083.71 3111.61,3089.39 3102.99,3092.97 3093.73,3094.19 3084.47,3092.97 3075.85,3089.39 3068.44,3083.71 3062.76,3076.3 3059.18,3067.68 3057.96,3058.42 3059.18,3049.16 3062.76,3040.54 3068.44,3033.13 3075.85,3027.45 3084.47,3023.87 3093.73,3022.65 3102.99,3023.87 3111.61,3027.45 3119.02,3033.13 3124.7,3040.54 3128.28,3049.16 3129.5,3058.42
  lines w10: 600,1220 600,1275 655,1275 655,1220 600,1220 ; 600,1300 600,1355 655,1355 655,1300 600,1300
  lines w20: 3895,3495 3895,3090 3765,2960 3745,2960 3726,2941 3726,2881 3670,2825 3440,2825 3370,2755 3370,2400 3496,2274 3496,2204 3585,2115 3955,2115 4005,2165 4005,2850 4155,3000 4375,3000 4440,2935 4560,2935 4585,2960 4585,3490
  text "2" at 611.7,1308.3 h34
  text "2" at 611.7,1308.3 h34
  text "B" at 610,1230 h34
  text "B" at 610,1230 h34
L3_VCC (plane layer: these items are gaps in the copper):
  region: 4024.98,2105 4024.98,1595 4273,1595 4273,2105
  region: 725,1360.01 725,1215.02 1013.38,1215.02 1013.38,1360.01
  region: 450.03,1360.01 450.03,1215.02 672.87,1215.02 672.87,1360.01
  region: 668.05,1300.04 668.05,1276.1 730,1276.1 730,1300.04
  region: 0,1088 0,527 555,527 555,1088
  region: 4665.3,1442.97 cw(c4893.73,1167.88) 4723.36,1482.25 cw(c4824.17,1131.49) 4793.75,1495.18 cw(c4749.59,1098.97) 4870.22,1478.95 cw(c4716.26,1170.91) 4927.38,1442.97 4825.57,1442.97
  pour cut-out: 3922.03,3058.42 3920.81,3067.68 3917.23,3076.31 3911.55,3083.72 3904.14,3089.4 3895.51,3092.98 3886.25,3094.2 3876.99,3092.98 3868.36,3089.4 3860.95,3083.72 3855.27,3076.31 3851.69,3067.68 3850.47,3058.42 3851.69,3049.16 3855.27,3040.53 3860.95,3033.12 3868.36,3027.44 3876.99,3023.86 3886.25,3022.64 3895.51,3023.86 3904.14,3027.44 3911.55,3033.12 3917.23,3040.53 3920.81,3049.16 3922.03,3058.42
  pour cut-out: 3129.51,3058.42 3128.29,3067.68 3124.71,3076.31 3119.03,3083.72 3111.62,3089.4 3102.99,3092.98 3093.73,3094.2 3084.47,3092.98 3075.84,3089.4 3068.43,3083.72 3062.75,3076.31 3059.17,3067.68 3057.95,3058.42 3059.17,3049.16 3062.75,3040.53 3068.43,3033.12 3075.84,3027.44 3084.47,3023.86 3093.73,3022.64 3102.99,3023.86 3111.62,3027.44 3119.03,3033.12 3124.71,3040.53 3128.29,3049.16 3129.51,3058.42
  pour cut-out: 1669.84,2988.97 1667.97,3003.16 1662.49,3016.39 1653.78,3027.75 1642.42,3036.46 1629.19,3041.94 1615,3043.81 1600.81,3041.94 1587.58,3036.46 1576.22,3027.75 1567.51,3016.39 1562.03,3003.16 1560.16,2988.97 1562.03,2974.78 1567.51,2961.55 1576.22,2950.19 1587.58,2941.48 1600.81,2936 1615,2934.13 1629.19,2936 1642.42,2941.48 1653.78,2950.19 1662.49,2961.55 1667.97,2974.78 1669.84,2988.97
  pour cut-out: 994.83,3264.56 992.96,3278.75 987.48,3291.97 978.77,3303.33 967.41,3312.04 954.19,3317.52 940,3319.39 925.81,3317.52 912.59,3312.04 901.23,3303.33 892.52,3291.97 887.04,3278.75 885.17,3264.56 887.04,3250.37 892.52,3237.15 901.23,3225.79 912.59,3217.08 925.81,3211.6 940,3209.73 954.19,3211.6 967.41,3217.08 978.77,3225.79 987.48,3237.15 992.96,3250.37 994.83,3264.56
  pour cut-out: 1669.83,3264.56 1667.96,3278.75 1662.48,3291.97 1653.77,3303.33 1642.41,3312.04 1629.19,3317.52 1615,3319.39 1600.81,3317.52 1587.59,3312.04 1576.23,3303.33 1567.52,3291.97 1562.04,3278.75 1560.17,3264.56 1562.04,3250.37 1567.52,3237.15 1576.23,3225.79 1587.59,3217.08 1600.81,3211.6 1615,3209.73 1629.19,3211.6 1642.41,3217.08 1653.77,3225.79 1662.48,3237.15 1667.96,3250.37 1669.83,3264.56
  pour cut-out: 2444.28,3099.56 2443.28,3107.14 2440.36,3114.2 2435.7,3120.26 2429.64,3124.92 2422.58,3127.84 2415,3128.84 2407.42,3127.84 2400.36,3124.92 2394.3,3120.26 2389.64,3114.2 2386.72,3107.14 2385.72,3099.56 2386.72,3091.98 2389.64,3084.92 2394.3,3078.86 2400.36,3074.2 2407.42,3071.28 2415,3070.28 2422.58,3071.28 2429.64,3074.2 2435.7,3078.86 2440.36,3084.92 2443.28,3091.98 2444.28,3099.56
  pour cut-out: 2741.52,3099.56 2740.52,3107.14 2737.6,3114.2 2732.94,3120.26 2726.88,3124.92 2719.82,3127.84 2712.24,3128.84 2704.66,3127.84 2697.6,3124.92 2691.54,3120.26 2686.88,3114.2 2683.96,3107.14 2682.96,3099.56 2683.96,3091.98 2686.88,3084.92 2691.54,3078.86 2697.6,3074.2 2704.66,3071.28 2712.24,3070.28 2719.82,3071.28 2726.88,3074.2 2732.94,3078.86 2737.6,3084.92 2740.52,3091.98 2741.52,3099.56
  lines w10: 4665.29,1442.47 cw(c4792.99,1318.43) 4922.21,1440.89 ; 4979.96,1690.41 4610.41,1690.41 4610.41,2269.59 4979.96,2269.59 ; 670,1220 670,1275 725,1275 725,1220 670,1220 ; 670,1300 670,1355 725,1355 725,1300 670,1300
  lines w20: 3095,1600 1670,1600 1620,1650 1620,2060 1645,2085 1700,2085 1745,2130 1745,2510 1805,2570 3025,2570 3040,2555 3040,2460 3020,2440 2855,2440 2835,2420 2835,2055 2860,2030 3055,2030 3100,1985 3100,1920 ; 3410,-135 3410,925 3445,960 3970,960 4010,920 4010,485 3995,470 3920,470 3895,445 3895,325 3935,285 4500,285 4575,210 4575,-55 ; 4170,285 4170,565 4195,590 4300,590 4320,610 4320,1050 4215,1155 3150,1155 3100,1205 3100,1920 ; 5045,1440 3470,1440 3415,1495 3415,1895 3390,1920 3100,1920 ; 610,2020 680,1950 1215,1950 1255,1990 1255,2225 1235,2245 1065,2245 1045,2265 1045,2385 1025,2405 890,2405 860,2435 860,2745 880,2765 1035,2765 1050,2750 1050,2590 1070,2570 1230,2570 1250,2590 1250,2895 1220,2925 695,2925 640,2925 610,2895 610,2020
  text "3" at 681.7,1308.3 h34
  text "3" at 681.7,1308.3 h34
  text "B" at 680,1230 h34
  text "B" at 680,1230 h34
L5_GND (plane layer: these items are gaps in the copper):
  region: 4024.98,2105 4024.98,1595 4273,1595 4273,2105
  region: 865,1360.01 865,1215.02 1013.38,1215.02 1013.38,1360.01
  region: 450.03,1360.01 450.03,1215.02 812,1215.02 812,1360.01
  region: 810,1300.04 810,1276.1 870,1276.1 870,1300.04
  region: 0,1088 0,527 555,527 555,1088
  pour cut-out: 2741.52,3099.56 2740.52,3107.14 2737.6,3114.2 2732.94,3120.26 2726.88,3124.92 2719.82,3127.84 2712.24,3128.84 2704.66,3127.84 2697.6,3124.92 2691.54,3120.26 2686.88,3114.2 2683.96,3107.14 2682.96,3099.56 2683.96,3091.98 2686.88,3084.92 2691.54,3078.86 2697.6,3074.2 2704.66,3071.28 2712.24,3070.28 2719.82,3071.28 2726.88,3074.2 2732.94,3078.86 2737.6,3084.92 2740.52,3091.98 2741.52,3099.56
  pour cut-out: 2444.28,3099.56 2443.28,3107.14 2440.36,3114.2 2435.7,3120.26 2429.64,3124.92 2422.58,3127.84 2415,3128.84 2407.42,3127.84 2400.36,3124.92 2394.3,3120.26 2389.64,3114.2 2386.72,3107.14 2385.72,3099.56 2386.72,3091.98 2389.64,3084.92 2394.3,3078.86 2400.36,3074.2 2407.42,3071.28 2415,3070.28 2422.58,3071.28 2429.64,3074.2 2435.7,3078.86 2440.36,3084.92 2443.28,3091.98 2444.28,3099.56
  pour cut-out: 1669.83,3264.56 1667.96,3278.75 1662.48,3291.97 1653.77,3303.33 1642.41,3312.04 1629.19,3317.52 1615,3319.39 1600.81,3317.52 1587.59,3312.04 1576.23,3303.33 1567.52,3291.97 1562.04,3278.75 1560.17,3264.56 1562.04,3250.37 1567.52,3237.15 1576.23,3225.79 1587.59,3217.08 1600.81,3211.6 1615,3209.73 1629.19,3211.6 1642.41,3217.08 1653.77,3225.79 1662.48,3237.15 1667.96,3250.37 1669.83,3264.56
  pour cut-out: 994.83,3264.56 992.96,3278.75 987.48,3291.97 978.77,3303.33 967.41,3312.04 954.19,3317.52 940,3319.39 925.81,3317.52 912.59,3312.04 901.23,3303.33 892.52,3291.97 887.04,3278.75 885.17,3264.56 887.04,3250.37 892.52,3237.15 901.23,3225.79 912.59,3217.08 925.81,3211.6 940,3209.73 954.19,3211.6 967.41,3217.08 978.77,3225.79 987.48,3237.15 992.96,3250.37 994.83,3264.56
  pour cut-out: 994.83,2988.97 992.96,3003.16 987.48,3016.38 978.77,3027.74 967.41,3036.45 954.19,3041.93 940,3043.8 925.81,3041.93 912.59,3036.45 901.23,3027.74 892.52,3016.38 887.04,3003.16 885.17,2988.97 887.04,2974.78 892.52,2961.56 901.23,2950.2 912.59,2941.49 925.81,2936.01 940,2934.14 954.19,2936.01 967.41,2941.49 978.77,2950.2 987.48,2961.56 992.96,2974.78 994.83,2988.97
  pour cut-out: 1669.83,2988.97 1667.96,3003.16 1662.48,3016.38 1653.77,3027.74 1642.41,3036.45 1629.19,3041.93 1615,3043.8 1600.81,3041.93 1587.59,3036.45 1576.23,3027.74 1567.52,3016.38 1562.04,3003.16 1560.17,2988.97 1562.04,2974.78 1567.52,2961.56 1576.23,2950.2 1587.59,2941.49 1600.81,2936.01 1615,2934.14 1629.19,2936.01 1642.41,2941.49 1653.77,2950.2 1662.48,2961.56 1667.96,2974.78 1669.83,2988.97
  pour cut-out: 3129.5,3058.42 3128.28,3067.68 3124.7,3076.3 3119.02,3083.71 3111.61,3089.39 3102.99,3092.97 3093.73,3094.19 3084.47,3092.97 3075.85,3089.39 3068.44,3083.71 3062.76,3076.3 3059.18,3067.68 3057.96,3058.42 3059.18,3049.16 3062.76,3040.54 3068.44,3033.13 3075.85,3027.45 3084.47,3023.87 3093.73,3022.65 3102.99,3023.87 3111.61,3027.45 3119.02,3033.13 3124.7,3040.54 3128.28,3049.16 3129.5,3058.42
  lines w10: 810,1220 865,1220 865,1275 810,1275 810,1220 ; 810,1300 865,1300 865,1355 810,1355 810,1300
  lines w20: 3895,3495 3895,3090 3765,2960 3745,2960 3726,2941 3726,2881 3670,2825 3440,2825 3370,2755 3370,2400 3496,2274 3496,2204 3585,2115 3955,2115 4005,2165 4005,2850 4155,3000 4375,3000 4440,2935 4560,2935 4585,2960 4585,3490
  text "5" at 855,1310 h34
  text "5" at 855,1310 h34
  text "B" at 850,1230 h34
  text "B" at 850,1230 h34

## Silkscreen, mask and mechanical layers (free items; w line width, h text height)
Top Overlay:
  drawing of 30663 lines, arcs and shapes, not listed
  text "A" at 4545,3355 h40
  text "spk L" at 705,3228 h40 r90
  text "spk R" at 401,3224 h40 r90
  text "uSD" at 2598,3219 h34
  text "CN5" at 2437,3216 h34
  text "JP3" at 421,3161 h34
  text "JP2" at 547,3161 h34
  text "DSI LCD" at 2960,3140 h34 r90
  text "CN7" at 963,3089 h34 r90
  text "CN6" at 1606,3088 h34 r90
  text "Line Out" at 1029.42,3056 h34 r90
  text "Line In" at 1708,3056 h34 r90
  text "CN10" at 4727,2431 h34
  text "Ethernet" at 4691,2377 h34
  text "CN8" at 102,2376 h34
  text "SPDIF TX" at 22,2279 h34
  text "Rev.B" at 1905,1730 h40
  text "MB1225" at 2155,1725 h50
  text "CN12" at 113,1687 h34
  text "SPDIF RX" at 23,1614 h34
  text "A" at 3860,1345 h40
  text "S" at 465,1309 h34
  text "B" at 465.7,1228.3 h34
  text "Wifi or I2C ext" at 559,1119 h34
  text "Ext 5V" at 4641,1089 h34
  text "T.R" at 2830,875 h34
  text "T.L" at 2120,870 h34
  text "CN3" at 4833.06,629.64 h34
  text "STM32F769I-DISCO" at 2110,608 h50
  text "MB1225B" at 2324,489 h50
  text "B.L" at 2140,295 h34
  text "B.R" at 2735,295 h34
  text "reset" at 4493,197 h34
  text "CN16" at 3695,131 h30
  text "user" at 710,115 h34
  text "USB HS" at 3036,98 h34
  text "USB" at 3697,90 h30
  text "COM" at 3396,64 h34
  text "ST_LINK" at 3650,41 h30
  text "www.st.com/stm32f7-discovery" at 1938,36 h40
  text "CN15" at 3060,33 h34
  text "PWR" at 1760,15 h34 r90
  text "Fault" at 1851,11 h34 r90
  text "usr1" at 1244,10 h34 r90
  text "usr2" at 1345,5 h34 r90
  text "usr3" at 1450,5 h34 r90
  text "OC" at 1560,5 h34 r90
  text "VBUS" at 1655,5 h34 r90
  text "DIO" at 4090,5 h34
  text "GND" at 4210,5 h34
  text "CLK" at 4325,5 h34
  text "3V3" at 4440,5 h34
  text "COMPANY NAME:" at 3735,-1740 h60
  text "COMPANY NAME:" at 3735,-1740 h60
  text "LAYER:" at 2135,-1790 h75
  text "LAYER:" at 2135,-1790 h75
  text "ST" at 3885,-1890 h75
  text "ST" at 3885,-1890 h75
  text "SILKSCREEN, (PRIMARY)" at 2185,-1940 h60
  text "SILKSCREEN, (PRIMARY)" at 2185,-1940 h60
  text "PROJECT NAME:" at 3735,-2040 h60
  text "PROJECT NAME:" at 3735,-2040 h60
  text "DESIGNED BY SOFER" at 865,-2060 h60
  text "DESIGNED BY SOFER" at 865,-2060 h60
  text "www.sofer.com.cn" at 885,-2160 h60
  text "www.sofer.com.cn" at 885,-2160 h60
  text "DESIGNER:" at 2185,-2190 h60
  text "DESIGNER:" at 2185,-2190 h60
  text "Shelley" at 2685,-2190 h60
  text "Shelley" at 2685,-2190 h60
  text "MB1225" at 3885,-2190 h75
  text "MB1225" at 3885,-2190 h75
  text "Tel : +86 21 - 6482 6908" at 685,-2340 h60
  text "Tel : +86 21 - 6482 6908" at 685,-2340 h60
  text "PROJECT NUMBER:" at 3735,-2340 h60
  text "PROJECT NUMBER:" at 3735,-2340 h60
  text "REV" at 4935,-2340 h60
  text "REV" at 4935,-2340 h60
  text "Mail: design@sofer.com.cn" at 685,-2440 h60
  text "Mail: design@sofer.com.cn" at 685,-2440 h60
  text "DATE:" at 2185,-2440 h60
  text "DATE:" at 2185,-2440 h60
  text "2016.02.18" at 2485,-2440 h60
  text "2016.02.18" at 2485,-2440 h60
  text "D031-019A2" at 3885,-2490 h75
  text "D031-019A2" at 3885,-2490 h75
  text "B" at 5035,-2490 h75
  text "B" at 5035,-2490 h75
Bottom Overlay:
  drawing of 25002 lines, arcs and shapes, not listed
  text "uSD" at 2215,3425 h34 r90
  text "Line In" at 1881,3225 h34 r270
  text "Line Out" at 1200,3185 h34 r270
  text "spk L" at 603,2963 h40 r270
  text "spk R" at 489,2960 h40 r270
  text "D15" at 1525,2635 h30
  text "D14" at 1525,2525 h30
  text "AVDD" at 1515,2375 h30 r315
  text "GND" at 1530,2325 h30
  text "Ethernet" at 4667,2310 h34
  text "nc" at 3405,2240 h30
  text "D13" at 1530,2205 h30
  text "IOREF5" at 3505,2150 h30
  text "SPDIF TX" at 264,2110 h34
  text "D12" at 1525,2105 h30
  text "Idd" at 1742,2090 h34
  text "NRST" at 3455,2045 h30
  text "D11" at 1525,2010 h30
  text "SPDIF RX" at 264,1970 h34
  text "3V3" at 3430,1960 h30
  text "D10" at 1525,1905 h30
  text "5V" at 3410,1845 h30
  text "D9" at 1505,1810 h30
  text "GND" at 3435,1750 h30
  text "D8" at 1505,1715 h30
  text "GND" at 3430,1670 h30
  text "VIN" at 3435,1550 h30
  text "D7" at 1515,1545 h30
  text "D6" at 1515,1445 h30
  text "D5" at 1515,1355 h30
  text "A0" at 3425,1350 h30
  text "B" at 993,1309 h34
  text "A1" at 3425,1260 h30
  text "D4" at 1515,1255 h30
  text "B" at 993,1229 h34
  text "VCP_TX" at 3855,1205 h34 r270
  text "VCP_RX" at 3940,1200 h34 r270
  text "D3" at 1515,1150 h30
  text "A2" at 3425,1150 h30
  text "A3" at 3425,1055 h30
  text "D2" at 1515,1050 h30
  text "JP1" at 4954,976 h34
  text "D1" at 1515,955 h30
  text "A4" at 3425,955 h30
  text "CN2" at 733,943 h34
  text "Ext 5V" at 4970,894 h34
  text "Wifi or I2C ext" at 733,871 h34
  text "D0" at 1515,850 h30
  text "A5" at 3425,850 h30
  text "stlk" at 4503,649 h34 r270
  text "chgr" at 4896,633 h34 r270
  text "usbhs" at 4593,630 h34 r270
  text "poe5V" at 4793,630 h34 r270
  text "ext5V" at 4698,627 h34 r270
  text "5V" at 4942,347 h34
  text "USB HS" at 2900,25 h34
  text "USB ST_LINK" at 4246,22 h34
  text "COMPANY NAME:" at 3735,-1740 h60
  text "COMPANY NAME:" at 3735,-1740 h60
  text "LAYER:" at 2135,-1790 h75
  text "LAYER:" at 2135,-1790 h75
  text "ST" at 3885,-1890 h75
  text "ST" at 3885,-1890 h75
  text "SILKSCREEN, (SECONDARY)" at 3300,-1940 h60
  text "PROJECT NAME:" at 3735,-2040 h60
  text "PROJECT NAME:" at 3735,-2040 h60
  text "DESIGNED BY SOFER" at 865,-2060 h60
  text "DESIGNED BY SOFER" at 865,-2060 h60
  text "www.sofer.com.cn" at 885,-2160 h60
  text "www.sofer.com.cn" at 885,-2160 h60
  text "DESIGNER:" at 2185,-2190 h60
  text "DESIGNER:" at 2185,-2190 h60
  text "Shelley" at 2685,-2190 h60
  text "Shelley" at 2685,-2190 h60
  text "MB1225" at 3885,-2190 h75
  text "MB1225" at 3885,-2190 h75
  text "Tel : +86 21 - 6482 6908" at 685,-2340 h60
  text "Tel : +86 21 - 6482 6908" at 685,-2340 h60
  text "PROJECT NUMBER:" at 3735,-2340 h60
  text "PROJECT NUMBER:" at 3735,-2340 h60
  text "REV" at 4935,-2340 h60
  text "REV" at 4935,-2340 h60
  text "Mail: design@sofer.com.cn" at 685,-2440 h60
  text "Mail: design@sofer.com.cn" at 685,-2440 h60
  text "DATE:" at 2185,-2440 h60
  text "DATE:" at 2185,-2440 h60
  text "2016.02.18" at 2485,-2440 h60
  text "2016.02.18" at 2485,-2440 h60
  text "D031-019A2" at 3885,-2490 h75
  text "D031-019A2" at 3885,-2490 h75
  text "B" at 5035,-2490 h75
  text "B" at 5035,-2490 h75
Top Paste:
  drawing of 24678 lines, arcs and shapes, not listed
  text "COMPANY NAME:" at 3735,-1740 h60
  text "COMPANY NAME:" at 3735,-1740 h60
  text "LAYER:" at 2135,-1790 h75
  text "LAYER:" at 2135,-1790 h75
  text "ST" at 3885,-1890 h75
  text "ST" at 3885,-1890 h75
  text "SOLDER PASTE (PRIMARY)" at 2185,-1940 h60
  text "SOLDER PASTE (PRIMARY)" at 2185,-1940 h60
  text "PROJECT NAME:" at 3735,-2040 h60
  text "PROJECT NAME:" at 3735,-2040 h60
  text "DESIGNED BY SOFER" at 865,-2060 h60
  text "DESIGNED BY SOFER" at 865,-2060 h60
  text "www.sofer.com.cn" at 885,-2160 h60
  text "www.sofer.com.cn" at 885,-2160 h60
  text "DESIGNER:" at 2185,-2190 h60
  text "DESIGNER:" at 2185,-2190 h60
  text "Shelley" at 2685,-2190 h60
  text "Shelley" at 2685,-2190 h60
  text "MB1225" at 3885,-2190 h75
  text "MB1225" at 3885,-2190 h75
  text "Tel : +86 21 - 6482 6908" at 685,-2340 h60
  text "Tel : +86 21 - 6482 6908" at 685,-2340 h60
  text "PROJECT NUMBER:" at 3735,-2340 h60
  text "PROJECT NUMBER:" at 3735,-2340 h60
  text "REV" at 4935,-2340 h60
  text "REV" at 4935,-2340 h60
  text "Mail: design@sofer.com.cn" at 685,-2440 h60
  text "Mail: design@sofer.com.cn" at 685,-2440 h60
  text "DATE:" at 2185,-2440 h60
  text "DATE:" at 2185,-2440 h60
  text "2016.02.18" at 2485,-2440 h60
  text "2016.02.18" at 2485,-2440 h60
  text "D031-019A2" at 3885,-2490 h75
  text "D031-019A2" at 3885,-2490 h75
  text "B" at 5035,-2490 h75
  text "B" at 5035,-2490 h75
Bottom Paste:
  drawing of 24678 lines, arcs and shapes, not listed
  text "COMPANY NAME:" at 3735,-1740 h60
  text "COMPANY NAME:" at 3735,-1740 h60
  text "LAYER:" at 2135,-1790 h75
  text "LAYER:" at 2135,-1790 h75
  text "ST" at 3885,-1890 h75
  text "ST" at 3885,-1890 h75
  text "SOLDER PASTE (SECONDARY)" at 2185,-1940 h60
  text "SOLDER PASTE (SECONDARY)" at 2185,-1940 h60
  text "PROJECT NAME:" at 3735,-2040 h60
  text "PROJECT NAME:" at 3735,-2040 h60
  text "DESIGNED BY SOFER" at 865,-2060 h60
  text "DESIGNED BY SOFER" at 865,-2060 h60
  text "www.sofer.com.cn" at 885,-2160 h60
  text "www.sofer.com.cn" at 885,-2160 h60
  text "DESIGNER:" at 2185,-2190 h60
  text "DESIGNER:" at 2185,-2190 h60
  text "Shelley" at 2685,-2190 h60
  text "Shelley" at 2685,-2190 h60
  text "MB1225" at 3885,-2190 h75
  text "MB1225" at 3885,-2190 h75
  text "Tel : +86 21 - 6482 6908" at 685,-2340 h60
  text "Tel : +86 21 - 6482 6908" at 685,-2340 h60
  text "PROJECT NUMBER:" at 3735,-2340 h60
  text "PROJECT NUMBER:" at 3735,-2340 h60
  text "REV" at 4935,-2340 h60
  text "REV" at 4935,-2340 h60
  text "Mail: design@sofer.com.cn" at 685,-2440 h60
  text "Mail: design@sofer.com.cn" at 685,-2440 h60
  text "DATE:" at 2185,-2440 h60
  text "DATE:" at 2185,-2440 h60
  text "2016.02.18" at 2485,-2440 h60
  text "2016.02.18" at 2485,-2440 h60
  text "D031-019A2" at 3885,-2490 h75
  text "D031-019A2" at 3885,-2490 h75
  text "B" at 5035,-2490 h75
  text "B" at 5035,-2490 h75
Top Solder:
  drawing of 24678 lines, arcs and shapes, not listed
  text "COMPANY NAME:" at 3735,-1740 h60
  text "LAYER:" at 2135,-1790 h75
  text "LAYER:" at 2135,-1790 h75
  text "ST" at 3885,-1890 h75
  text "SOLDER MASK (PRIMARY)" at 2185,-1940 h60
  text "SOLDER MASK (PRIMARY)" at 2185,-1940 h60
  text "PROJECT NAME:" at 3735,-2040 h60
  text "DESIGNED BY SOFER" at 865,-2060 h60
  text "DESIGNED BY SOFER" at 865,-2060 h60
  text "www.sofer.com.cn" at 885,-2160 h60
  text "www.sofer.com.cn" at 885,-2160 h60
  text "DESIGNER:" at 2185,-2190 h60
  text "DESIGNER:" at 2185,-2190 h60
  text "Shelley" at 2685,-2190 h60
  text "Shelley" at 2685,-2190 h60
  text "MB1225" at 3885,-2190 h75
  text "Tel : +86 21 - 6482 6908" at 685,-2340 h60
  text "Tel : +86 21 - 6482 6908" at 685,-2340 h60
  text "PROJECT NUMBER:" at 3735,-2340 h60
  text "REV" at 4935,-2340 h60
  text "Mail: design@sofer.com.cn" at 685,-2440 h60
  text "Mail: design@sofer.com.cn" at 685,-2440 h60
  text "DATE:" at 2185,-2440 h60
  text "DATE:" at 2185,-2440 h60
  text "2016.02.18" at 2485,-2440 h60
  text "2016.02.18" at 2485,-2440 h60
  text "D031-019A2" at 3885,-2490 h75
  text "B" at 5035,-2490 h75
Bottom Solder:
  drawing of 24667 lines, arcs and shapes, not listed
  text "COMPANY NAME:" at 3735,-1740 h60
  text "LAYER:" at 2135,-1790 h75
  text "ST" at 3885,-1890 h75
  text "SOLDER MASK (SECONDARY)" at 2185,-1940 h60
  text "PROJECT NAME:" at 3735,-2040 h60
  text "DESIGNED BY SOFER" at 865,-2060 h60
  text "www.sofer.com.cn" at 885,-2160 h60
  text "DESIGNER:" at 2185,-2190 h60
  text "Shelley" at 2685,-2190 h60
  text "MB1225" at 3885,-2190 h75
  text "Tel : +86 21 - 6482 6908" at 685,-2340 h60
  text "PROJECT NUMBER:" at 3735,-2340 h60
  text "REV" at 4935,-2340 h60
  text "Mail: design@sofer.com.cn" at 685,-2440 h60
  text "DATE:" at 2185,-2440 h60
  text "2016.02.18" at 2485,-2440 h60
  text "D031-019A2" at 3885,-2490 h75
  text "B" at 5035,-2490 h75
Mechanical 1:
  lines w1: 950,2350 950,2540 1120,2540 1120,2350 950,2350 ; 2186,1015 2186,1362 2735,1362 2735,1015 2186,1015 ; 2191,1846 2191,2364 2709,2364 2709,1846 2191,1846 ; 4396.96,285.31 4396.96,374.85 4452.81,374.85 4452.81,285.31 4396.96,285.31
  text "FAB DARWING & DRILL LEGEND" at 2185,-1940 h60
  text "FAB DARWING & DRILL LEGEND" at 2185,-1940 h60
DIMENSION:
  drawing of 420 lines, arcs and shapes, not listed
  text "59" at 3220,3348.58 h25
  text "2" at 3785,2953.58 h25
  text "60" at 3225,2943.58 h25
  text "50" at 3320,2943.58 h25
  text "40" at 3420,2943.58 h25
  text "30" at 3520,2943.58 h25
  text "20" at 3620,2943.58 h25
  text "10" at 3715,2943.58 h25
BOARD_GEOMETRY_OUT:
  drawing of 22 lines, arcs and shapes, not listed
PIN_TOP:
  circle w1: c4065.98,760 r30
  circle w1: c4130.98,1435 r30
  circle w1: c3745.98,1435 r30
  circle w1: c600,2215 r30
  circle w1: c4515,2255.98 r30
  circle w1: c207,205.83 r177
  circle w1: c4792.99,205.83 r177
  circle w1: c207,1690.24 r177
  circle w1: c4792.99,1690.24 r177
  circle w1: c3853.78,2130.9 r20
  circle w1: c3126.22,2130.9 r20
DXF_0731:
  drawing of 19120 lines, arcs and shapes, not listed
  text "400.00" at 3019.05,7036.98 h75
  text "118.36427 (mm)" at 1944.05,6769.84 h75 r359.88
  text "U10" at 4570,6755 h85 r270
  text "CN1" at 1320,6615 h85
  text "CN4" at 1895,6415 h85 r90
  text "Ethernet" at 4890,6300 h75
  text "CN3" at 5660,6280 h85
  text "Designator6" at 4302,6048 h75
  text "CN8" at 35,6020 h85
  text "Designator5" at 1805,5900 h75
  text "MB1063" at 605,5520 h75
  text "U4" at 2760,4930 h85
  text "U7" at 2870,4725 h130
  text "ST-Link" at 425,4650 h75
  text "Memory Connector" at 3925,4380 h75 r270
  text "Memory connector" at 2060,4365 h75 r270
  text "CN7" at 5630,4200 h130 r180
  text "1" at 5189,4119 h130 r270
  text "CN5" at 540,4100 h85 r180
  text "CN10" at 5810,4035 h85
  text "SDRAM" at 3130,3775 h75
  text "CN12" at 4780,3640 h130
  text "CN9" at 80,3605 h130 r180
  text "U5" at 2495,3580 h130 r90
  text "MB1043" at 935,3445 h75
  text "CN13" at 80,3070 h130 r180
  text "CN14" at 65,2505 h130 r180
  text "CN16" at 5626.61,2425 h85
  text "CN11" at 665,2345 h85 r180
  text "CN14_1" at 475,1450 h85 r180
  text "U21" at 475,975 h85 r180
  text "CN23" at 6085,635 h130 r180
  text "B1" at 2355,480 h85
  text "RV2" at 1565,470 h85 r270
  text "B2" at 2895,465 h85
  text "U27" at 1980,460 h85 r315
  text "Speaker connector" at 3330,60 h75
  text "845.00" at 5.72,13.3 h0.06
  text "545.00" at 6.02,13.3 h0.06
  text "0.00" at 6.63,13.3 h0.06
  text "CN1" at 7.22,12.62 h0.03
  text "118.36427 (mm)" at 7.84,12.77 h0.06 r359.88
  text "400.00" at 8.92,13.04 h0.06
  text "U10" at 10.47,12.76 h0.03 r270
  text "CN8" at 5.93,12.02 h0.03
  text "MB1063" at 6.5,11.52 h0.06
  text "Designator5" at 7.7,11.9 h0.06
  text "CN4" at 7.79,12.42 h0.03 r90
  text "Designator6" at 10.2,12.05 h0.06
  text "Ethernet" at 10.79,12.3 h0.06
  text "CN3" at 11.56,12.28 h0.03
  text "ST-Link" at 6.32,10.65 h0.06
  text "U4" at 8.66,10.93 h0.03
  text "U7" at 8.77,10.72 h0.04
  text "CN9" at 5.98,9.6 h0.04 r180
  text "CN5" at 6.44,10.1 h0.03 r180
  text "Memory connector" at 7.96,10.36 h0.06 r270
  text "U5" at 8.4,9.58 h0.04 r90
  text "SDRAM" at 9.03,9.78 h0.06
  text "Memory Connector" at 9.82,10.38 h0.06 r270
  text "CN12" at 10.68,9.64 h0.04
  text "1" at 11.09,10.12 h0.04 r270
  text "CN7" at 11.53,10.2 h0.04 r180
  text "CN10" at 11.71,10.04 h0.03
  text "CN14" at 5.96,8.51 h0.04 r180
  text "CN13" at 5.98,9.07 h0.04 r180
  text "MB1043" at 6.83,9.44 h0.06
  text "CN11" at 6.56,8.35 h0.03 r180
  text "CN16" at 11.53,8.43 h0.03
  text "CN14_1" at 6.38,7.45 h0.03 r180
  text "U21" at 6.38,6.97 h0.03 r180
  text "CN23" at 11.98,6.63 h0.04 r180
  text "RV2" at 7.46,6.47 h0.03 r270
  text "U27" at 7.88,6.46 h0.03 r315
  text "B1" at 8.26,6.48 h0.03
  text "B2" at 8.79,6.46 h0.03
  text "Speaker connector" at 9.23,6.06 h0.06
MB988:
  lines w2.5: -116,711.75 cw(c-116,713) -116,714.25 ; -116,711.75 ccw(c-116,713) -116,714.25 ; -116,711.75 cw(c-116,713) -116,714.25 ; -116,711.75 ccw(c-116,713) -116,714.25 ; -116,1183.75 cw(c-116,1185) -116,1186.25 ; -116,1183.75 ccw(c-116,1185) -116,1186.25 ; -116,1183.75 cw(c-116,1185) -116,1186.25 ; -116,1183.75 ccw(c-116,1185) -116,1186.25 ; -116,2861.75 cw(c-116,2863) -116,2864.25 ; -116,2861.75 ccw(c-116,2863) -116,2864.25 ; -116,2861.75 cw(c-116,2863) -116,2864.25 ; -116,2861.75 ccw(c-116,2863) -116,2864.25 ; -116,3333.75 cw(c-116,3335) -116,3336.25 ; -116,3333.75 ccw(c-116,3335) -116,3336.25 ; -116,3333.75 cw(c-116,3335) -116,3336.25 ; -116,3333.75 ccw(c-116,3335) -116,3336.25 ; 1413.84,6598.75 cw(c1413.84,6600) 1413.84,6601.25 ; 1413.84,6598.75 ccw(c1413.84,6600) 1413.84,6601.25 ; 1413.84,6598.75 cw(c1413.84,6600) 1413.84,6601.25 ; 1413.84,6598.75 ccw(c1413.84,6600) 1413.84,6601.25 ; 1713.84,6598.75 cw(c1713.84,6600) 1713.84,6601.25 ; 1713.84,6598.75 ccw(c1713.84,6600) 1713.84,6601.25 ; 1713.84,6598.75 cw(c1713.84,6600) 1713.84,6601.25 ; 1713.84,6598.75 ccw(c1713.84,6600) 1713.84,6601.25 ; 4525.92,550.39 ccw(c4527.17,550.39) 4528.42,550.39 ; 4525.92,550.39 cw(c4527.17,550.39) 4528.42,550.39 ; 4525.92,550.39 ccw(c4527.17,550.39) 4528.42,550.39 ; 4525.92,550.39 cw(c4527.17,550.39) 4528.42,550.39 ; 4525.92,581.89 ccw(c4527.17,581.89) 4528.42,581.89 ; 4525.92,581.89 cw(c4527.17,581.89) 4528.42,581.89 ; 4525.92,581.89 ccw(c4527.17,581.89) 4528.42,581.89 ; 4525.92,581.89 cw(c4527.17,581.89) 4528.42,581.89 ; 4525.92,818.11 ccw(c4527.17,818.11) 4528.42,818.11 ; 4525.92,818.11 cw(c4527.17,818.11) 4528.42,818.11 ; 4525.92,818.11 ccw(c4527.17,818.11) 4528.42,818.11 ; 4525.92,818.11 cw(c4527.17,818.11) 4528.42,818.11 ; 4525.92,849.61 ccw(c4527.17,849.61) 4528.42,849.61 ; 4525.92,849.61 cw(c4527.17,849.61) 4528.42,849.61 ; 4525.92,849.61 ccw(c4527.17,849.61) 4528.42,849.61 ; 4525.92,849.61 cw(c4527.17,849.61) 4528.42,849.61 ; 4616.47,581.89 ccw(c4617.72,581.89) 4618.97,581.89 ; 4616.47,581.89 cw(c4617.72,581.89) 4618.97,581.89 ; 4616.47,581.89 ccw(c4617.72,581.89) 4618.97,581.89 ; 4616.47,581.89 cw(c4617.72,581.89) 4618.97,581.89 ; 4616.47,818.11 ccw(c4617.72,818.11) 4618.97,818.11 ; 4616.47,818.11 cw(c4617.72,818.11) 4618.97,818.11 ; 4616.47,818.11 ccw(c4617.72,818.11) 4618.97,818.11 ; 4616.47,818.11 cw(c4617.72,818.11) 4618.97,818.11 ; 1360.09,6450 ccw(c1361.34,6450) 1362.59,6450 ccw(c1361.34,6450) 1360.09,6450 ; 1360.09,6550 ccw(c1361.34,6550) 1362.59,6550 ccw(c1361.34,6550) 1360.09,6550
  lines w5: -13,713 -116,713 -116,1185 -13,1185 ; -13,2863 -116,2863 -116,3335 -13,3335 ; 0,1450 0,3170 0,6800 4500,6800 4500,4650 ccw(c5673.78,4400.51) 4500,4151.01 4500,0 0,0 0,1458.87 ; 4499.61,550.39 4527.17,550.39 4527.17,581.89 4617.72,581.89 4617.72,818.11 4527.17,818.11 4527.17,849.61 4499.61,849.61 ; 1413.84,6200 1713.84,6200 1713.84,6600 1413.84,6600 1413.84,6200
  lines w6: 75,6575 cw(c225,6575) 375,6575 cw(c225,6575) 75,6575 ; 688.84,6550 cw(c838.84,6550) 988.84,6550 cw(c838.84,6550) 688.84,6550 ; 1358.34,6350 ccw(c1361.34,6350) 1364.34,6350 ccw(c1361.34,6350) 1358.34,6350
  lines w23.62: 1563.84,6288.19 cw(c1563.84,6300) 1563.84,6311.81 ; 1563.84,6288.19 ccw(c1563.84,6300) 1563.84,6311.81 ; 1563.84,6288.19 cw(c1563.84,6300) 1563.84,6311.81 ; 1563.84,6288.19 ccw(c1563.84,6300) 1563.84,6311.81 ; 1563.84,6288.19 cw(c1563.84,6300) 1563.84,6311.81 ; 1563.84,6288.19 ccw(c1563.84,6300) 1563.84,6311.81 ; 1563.84,6288.19 cw(c1563.84,6300) 1563.84,6311.81 ; 1563.84,6288.19 ccw(c1563.84,6300) 1563.84,6311.81 ; 1563.84,6488.19 cw(c1563.84,6500) 1563.84,6511.81 ; 1563.84,6488.19 ccw(c1563.84,6500) 1563.84,6511.81 ; 1563.84,6488.19 cw(c1563.84,6500) 1563.84,6511.81 ; 1563.84,6488.19 ccw(c1563.84,6500) 1563.84,6511.81 ; 1563.84,6488.19 cw(c1563.84,6500) 1563.84,6511.81 ; 1563.84,6488.19 ccw(c1563.84,6500) 1563.84,6511.81 ; 1563.84,6488.19 cw(c1563.84,6500) 1563.84,6511.81 ; 1563.84,6488.19 ccw(c1563.84,6500) 1563.84,6511.81
  lines w28.62: 1563.84,6285.69 cw(c1563.84,6300) 1563.84,6314.31 cw(c1563.84,6300) 1563.84,6285.69 ; 1563.84,6485.69 cw(c1563.84,6500) 1563.84,6514.31 cw(c1563.84,6500) 1563.84,6485.69
  lines w68.9: 804.39,6550 ccw(c838.84,6550) 873.29,6550 ccw(c838.84,6550) 804.39,6550
  lines w73.9: 188.05,6575 ccw(c225,6575) 261.95,6575 ccw(c225,6575) 188.05,6575
MB786:
  drawing of 241 lines, arcs and shapes, not listed
LAY2:
  text "2" at 2685,-1790 h75
  text "2" at 2685,-1790 h75
  text "LAYER 2 (GND PLANE)" at 2185,-1940 h60
  text "LAYER 2 (GND PLANE)" at 2185,-1940 h60
LAY3:
  text "3" at 2685,-1790 h75
  text "3" at 2685,-1790 h75
  text "LAYER 3 (INTERNAL SIGNAL)" at 2185,-1940 h60
  text "LAYER 3 (INTERNAL SIGNAL)" at 2185,-1940 h60
LAY5:
  text "5" at 2685,-1790 h75
  text "5" at 2685,-1790 h75
  text "LAYER 5 (GND PLANE)" at 2185,-1940 h60
  text "LAYER 5 (GND PLANE)" at 2185,-1940 h60
LAY4:
  text "4" at 2685,-1790 h75
  text "4" at 2685,-1790 h75
  text "LAYER 4 (VTT PLANE)" at 2185,-1940 h60
  text "LAYER 4 (VTT PLANE)" at 2185,-1940 h60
